VERSION 5.8 ;
BUSBITCHARS "[]" ;
DIVIDERCHAR "/" ;
UNITS
    DATABASE MICRONS 1000 ;
END UNITS

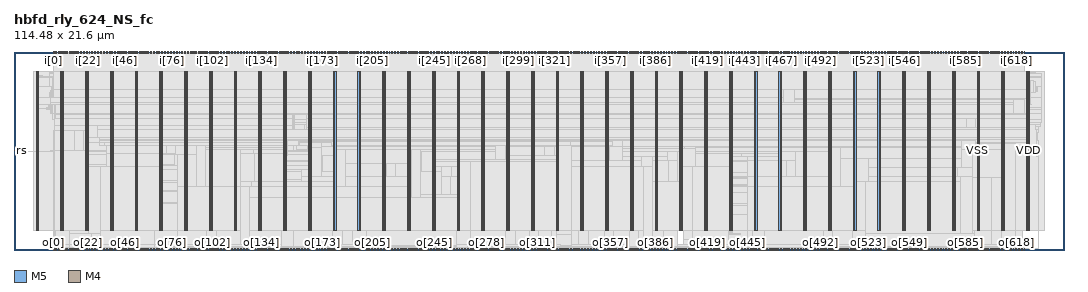
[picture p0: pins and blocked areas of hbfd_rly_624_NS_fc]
MACRO hbfd_rly_624_NS_fc
  FOREIGN hbfd_rly_624_NS_fc 0 0 ;
  CLASS BLOCK ;
  SIZE 114.48 BY 21.6 ;
  PIN clk_in
    DIRECTION INPUT ;
    USE SIGNAL ;
    PORT
      LAYER M5 ;
        RECT  57.216 21.408 57.24 21.6 ;
    END
  END clk_in
  PIN clk_out
    DIRECTION OUTPUT ;
    USE SIGNAL ;
    PORT
      LAYER M5 ;
        RECT  57.216 0 57.24 0.192 ;
    END
  END clk_out
  PIN i[0]
    DIRECTION INPUT ;
    USE SIGNAL ;
    PORT
      LAYER M5 ;
        RECT  4.32 21.408 4.344 21.6 ;
    END
  END i[0]
  PIN i[100]
    DIRECTION INPUT ;
    USE SIGNAL ;
    PORT
      LAYER M5 ;
        RECT  21.264 21.408 21.288 21.6 ;
    END
  END i[100]
  PIN i[101]
    DIRECTION INPUT ;
    USE SIGNAL ;
    PORT
      LAYER M5 ;
        RECT  21.456 21.408 21.48 21.6 ;
    END
  END i[101]
  PIN i[102]
    DIRECTION INPUT ;
    USE SIGNAL ;
    PORT
      LAYER M5 ;
        RECT  21.6 21.408 21.624 21.6 ;
    END
  END i[102]
  PIN i[103]
    DIRECTION INPUT ;
    USE SIGNAL ;
    PORT
      LAYER M5 ;
        RECT  21.792 21.408 21.816 21.6 ;
    END
  END i[103]
  PIN i[104]
    DIRECTION INPUT ;
    USE SIGNAL ;
    PORT
      LAYER M5 ;
        RECT  21.936 21.408 21.96 21.6 ;
    END
  END i[104]
  PIN i[105]
    DIRECTION INPUT ;
    USE SIGNAL ;
    PORT
      LAYER M5 ;
        RECT  22.128 21.408 22.152 21.6 ;
    END
  END i[105]
  PIN i[106]
    DIRECTION INPUT ;
    USE SIGNAL ;
    PORT
      LAYER M5 ;
        RECT  22.272 21.408 22.296 21.6 ;
    END
  END i[106]
  PIN i[107]
    DIRECTION INPUT ;
    USE SIGNAL ;
    PORT
      LAYER M5 ;
        RECT  22.464 21.408 22.488 21.6 ;
    END
  END i[107]
  PIN i[108]
    DIRECTION INPUT ;
    USE SIGNAL ;
    PORT
      LAYER M5 ;
        RECT  22.608 21.408 22.632 21.6 ;
    END
  END i[108]
  PIN i[109]
    DIRECTION INPUT ;
    USE SIGNAL ;
    PORT
      LAYER M5 ;
        RECT  22.8 21.408 22.824 21.6 ;
    END
  END i[109]
  PIN i[10]
    DIRECTION INPUT ;
    USE SIGNAL ;
    PORT
      LAYER M5 ;
        RECT  6 21.408 6.024 21.6 ;
    END
  END i[10]
  PIN i[110]
    DIRECTION INPUT ;
    USE SIGNAL ;
    PORT
      LAYER M5 ;
        RECT  22.944 21.408 22.968 21.6 ;
    END
  END i[110]
  PIN i[111]
    DIRECTION INPUT ;
    USE SIGNAL ;
    PORT
      LAYER M5 ;
        RECT  23.136 21.408 23.16 21.6 ;
    END
  END i[111]
  PIN i[112]
    DIRECTION INPUT ;
    USE SIGNAL ;
    PORT
      LAYER M5 ;
        RECT  23.328 21.408 23.352 21.6 ;
    END
  END i[112]
  PIN i[113]
    DIRECTION INPUT ;
    USE SIGNAL ;
    PORT
      LAYER M5 ;
        RECT  23.472 21.408 23.496 21.6 ;
    END
  END i[113]
  PIN i[114]
    DIRECTION INPUT ;
    USE SIGNAL ;
    PORT
      LAYER M5 ;
        RECT  23.664 21.408 23.688 21.6 ;
    END
  END i[114]
  PIN i[115]
    DIRECTION INPUT ;
    USE SIGNAL ;
    PORT
      LAYER M5 ;
        RECT  23.808 21.408 23.832 21.6 ;
    END
  END i[115]
  PIN i[116]
    DIRECTION INPUT ;
    USE SIGNAL ;
    PORT
      LAYER M5 ;
        RECT  24 21.408 24.024 21.6 ;
    END
  END i[116]
  PIN i[117]
    DIRECTION INPUT ;
    USE SIGNAL ;
    PORT
      LAYER M5 ;
        RECT  24.144 21.408 24.168 21.6 ;
    END
  END i[117]
  PIN i[118]
    DIRECTION INPUT ;
    USE SIGNAL ;
    PORT
      LAYER M5 ;
        RECT  24.336 21.408 24.36 21.6 ;
    END
  END i[118]
  PIN i[119]
    DIRECTION INPUT ;
    USE SIGNAL ;
    PORT
      LAYER M5 ;
        RECT  24.48 21.408 24.504 21.6 ;
    END
  END i[119]
  PIN i[11]
    DIRECTION INPUT ;
    USE SIGNAL ;
    PORT
      LAYER M5 ;
        RECT  6.192 21.408 6.216 21.6 ;
    END
  END i[11]
  PIN i[120]
    DIRECTION INPUT ;
    USE SIGNAL ;
    PORT
      LAYER M5 ;
        RECT  24.672 21.408 24.696 21.6 ;
    END
  END i[120]
  PIN i[121]
    DIRECTION INPUT ;
    USE SIGNAL ;
    PORT
      LAYER M5 ;
        RECT  24.816 21.408 24.84 21.6 ;
    END
  END i[121]
  PIN i[122]
    DIRECTION INPUT ;
    USE SIGNAL ;
    PORT
      LAYER M5 ;
        RECT  25.008 21.408 25.032 21.6 ;
    END
  END i[122]
  PIN i[123]
    DIRECTION INPUT ;
    USE SIGNAL ;
    PORT
      LAYER M5 ;
        RECT  25.152 21.408 25.176 21.6 ;
    END
  END i[123]
  PIN i[124]
    DIRECTION INPUT ;
    USE SIGNAL ;
    PORT
      LAYER M5 ;
        RECT  25.344 21.408 25.368 21.6 ;
    END
  END i[124]
  PIN i[125]
    DIRECTION INPUT ;
    USE SIGNAL ;
    PORT
      LAYER M5 ;
        RECT  25.488 21.408 25.512 21.6 ;
    END
  END i[125]
  PIN i[126]
    DIRECTION INPUT ;
    USE SIGNAL ;
    PORT
      LAYER M5 ;
        RECT  25.68 21.408 25.704 21.6 ;
    END
  END i[126]
  PIN i[127]
    DIRECTION INPUT ;
    USE SIGNAL ;
    PORT
      LAYER M5 ;
        RECT  25.872 21.408 25.896 21.6 ;
    END
  END i[127]
  PIN i[128]
    DIRECTION INPUT ;
    USE SIGNAL ;
    PORT
      LAYER M5 ;
        RECT  26.016 21.408 26.04 21.6 ;
    END
  END i[128]
  PIN i[129]
    DIRECTION INPUT ;
    USE SIGNAL ;
    PORT
      LAYER M5 ;
        RECT  26.208 21.408 26.232 21.6 ;
    END
  END i[129]
  PIN i[12]
    DIRECTION INPUT ;
    USE SIGNAL ;
    PORT
      LAYER M5 ;
        RECT  6.336 21.408 6.36 21.6 ;
    END
  END i[12]
  PIN i[130]
    DIRECTION INPUT ;
    USE SIGNAL ;
    PORT
      LAYER M5 ;
        RECT  26.352 21.408 26.376 21.6 ;
    END
  END i[130]
  PIN i[131]
    DIRECTION INPUT ;
    USE SIGNAL ;
    PORT
      LAYER M5 ;
        RECT  26.544 21.408 26.568 21.6 ;
    END
  END i[131]
  PIN i[132]
    DIRECTION INPUT ;
    USE SIGNAL ;
    PORT
      LAYER M5 ;
        RECT  26.688 21.408 26.712 21.6 ;
    END
  END i[132]
  PIN i[133]
    DIRECTION INPUT ;
    USE SIGNAL ;
    PORT
      LAYER M5 ;
        RECT  26.88 21.408 26.904 21.6 ;
    END
  END i[133]
  PIN i[134]
    DIRECTION INPUT ;
    USE SIGNAL ;
    PORT
      LAYER M5 ;
        RECT  27.024 21.408 27.048 21.6 ;
    END
  END i[134]
  PIN i[135]
    DIRECTION INPUT ;
    USE SIGNAL ;
    PORT
      LAYER M5 ;
        RECT  27.216 21.408 27.24 21.6 ;
    END
  END i[135]
  PIN i[136]
    DIRECTION INPUT ;
    USE SIGNAL ;
    PORT
      LAYER M5 ;
        RECT  27.36 21.408 27.384 21.6 ;
    END
  END i[136]
  PIN i[137]
    DIRECTION INPUT ;
    USE SIGNAL ;
    PORT
      LAYER M5 ;
        RECT  27.552 21.408 27.576 21.6 ;
    END
  END i[137]
  PIN i[138]
    DIRECTION INPUT ;
    USE SIGNAL ;
    PORT
      LAYER M5 ;
        RECT  27.696 21.408 27.72 21.6 ;
    END
  END i[138]
  PIN i[139]
    DIRECTION INPUT ;
    USE SIGNAL ;
    PORT
      LAYER M5 ;
        RECT  27.888 21.408 27.912 21.6 ;
    END
  END i[139]
  PIN i[13]
    DIRECTION INPUT ;
    USE SIGNAL ;
    PORT
      LAYER M5 ;
        RECT  6.528 21.408 6.552 21.6 ;
    END
  END i[13]
  PIN i[140]
    DIRECTION INPUT ;
    USE SIGNAL ;
    PORT
      LAYER M5 ;
        RECT  28.032 21.408 28.056 21.6 ;
    END
  END i[140]
  PIN i[141]
    DIRECTION INPUT ;
    USE SIGNAL ;
    PORT
      LAYER M5 ;
        RECT  28.224 21.408 28.248 21.6 ;
    END
  END i[141]
  PIN i[142]
    DIRECTION INPUT ;
    USE SIGNAL ;
    PORT
      LAYER M5 ;
        RECT  28.416 21.408 28.44 21.6 ;
    END
  END i[142]
  PIN i[143]
    DIRECTION INPUT ;
    USE SIGNAL ;
    PORT
      LAYER M5 ;
        RECT  28.56 21.408 28.584 21.6 ;
    END
  END i[143]
  PIN i[144]
    DIRECTION INPUT ;
    USE SIGNAL ;
    PORT
      LAYER M5 ;
        RECT  28.752 21.408 28.776 21.6 ;
    END
  END i[144]
  PIN i[145]
    DIRECTION INPUT ;
    USE SIGNAL ;
    PORT
      LAYER M5 ;
        RECT  28.896 21.408 28.92 21.6 ;
    END
  END i[145]
  PIN i[146]
    DIRECTION INPUT ;
    USE SIGNAL ;
    PORT
      LAYER M5 ;
        RECT  29.088 21.408 29.112 21.6 ;
    END
  END i[146]
  PIN i[147]
    DIRECTION INPUT ;
    USE SIGNAL ;
    PORT
      LAYER M5 ;
        RECT  29.232 21.408 29.256 21.6 ;
    END
  END i[147]
  PIN i[148]
    DIRECTION INPUT ;
    USE SIGNAL ;
    PORT
      LAYER M5 ;
        RECT  29.424 21.408 29.448 21.6 ;
    END
  END i[148]
  PIN i[149]
    DIRECTION INPUT ;
    USE SIGNAL ;
    PORT
      LAYER M5 ;
        RECT  29.568 21.408 29.592 21.6 ;
    END
  END i[149]
  PIN i[14]
    DIRECTION INPUT ;
    USE SIGNAL ;
    PORT
      LAYER M5 ;
        RECT  6.672 21.408 6.696 21.6 ;
    END
  END i[14]
  PIN i[150]
    DIRECTION INPUT ;
    USE SIGNAL ;
    PORT
      LAYER M5 ;
        RECT  29.76 21.408 29.784 21.6 ;
    END
  END i[150]
  PIN i[151]
    DIRECTION INPUT ;
    USE SIGNAL ;
    PORT
      LAYER M5 ;
        RECT  29.904 21.408 29.928 21.6 ;
    END
  END i[151]
  PIN i[152]
    DIRECTION INPUT ;
    USE SIGNAL ;
    PORT
      LAYER M5 ;
        RECT  30.096 21.408 30.12 21.6 ;
    END
  END i[152]
  PIN i[153]
    DIRECTION INPUT ;
    USE SIGNAL ;
    PORT
      LAYER M5 ;
        RECT  30.24 21.408 30.264 21.6 ;
    END
  END i[153]
  PIN i[154]
    DIRECTION INPUT ;
    USE SIGNAL ;
    PORT
      LAYER M5 ;
        RECT  30.432 21.408 30.456 21.6 ;
    END
  END i[154]
  PIN i[155]
    DIRECTION INPUT ;
    USE SIGNAL ;
    PORT
      LAYER M5 ;
        RECT  30.576 21.408 30.6 21.6 ;
    END
  END i[155]
  PIN i[156]
    DIRECTION INPUT ;
    USE SIGNAL ;
    PORT
      LAYER M5 ;
        RECT  30.768 21.408 30.792 21.6 ;
    END
  END i[156]
  PIN i[157]
    DIRECTION INPUT ;
    USE SIGNAL ;
    PORT
      LAYER M5 ;
        RECT  30.96 21.408 30.984 21.6 ;
    END
  END i[157]
  PIN i[158]
    DIRECTION INPUT ;
    USE SIGNAL ;
    PORT
      LAYER M5 ;
        RECT  31.104 21.408 31.128 21.6 ;
    END
  END i[158]
  PIN i[159]
    DIRECTION INPUT ;
    USE SIGNAL ;
    PORT
      LAYER M5 ;
        RECT  31.296 21.408 31.32 21.6 ;
    END
  END i[159]
  PIN i[15]
    DIRECTION INPUT ;
    USE SIGNAL ;
    PORT
      LAYER M5 ;
        RECT  6.864 21.408 6.888 21.6 ;
    END
  END i[15]
  PIN i[160]
    DIRECTION INPUT ;
    USE SIGNAL ;
    PORT
      LAYER M5 ;
        RECT  31.44 21.408 31.464 21.6 ;
    END
  END i[160]
  PIN i[161]
    DIRECTION INPUT ;
    USE SIGNAL ;
    PORT
      LAYER M5 ;
        RECT  31.632 21.408 31.656 21.6 ;
    END
  END i[161]
  PIN i[162]
    DIRECTION INPUT ;
    USE SIGNAL ;
    PORT
      LAYER M5 ;
        RECT  31.776 21.408 31.8 21.6 ;
    END
  END i[162]
  PIN i[163]
    DIRECTION INPUT ;
    USE SIGNAL ;
    PORT
      LAYER M5 ;
        RECT  31.968 21.408 31.992 21.6 ;
    END
  END i[163]
  PIN i[164]
    DIRECTION INPUT ;
    USE SIGNAL ;
    PORT
      LAYER M5 ;
        RECT  32.112 21.408 32.136 21.6 ;
    END
  END i[164]
  PIN i[165]
    DIRECTION INPUT ;
    USE SIGNAL ;
    PORT
      LAYER M5 ;
        RECT  32.304 21.408 32.328 21.6 ;
    END
  END i[165]
  PIN i[166]
    DIRECTION INPUT ;
    USE SIGNAL ;
    PORT
      LAYER M5 ;
        RECT  32.448 21.408 32.472 21.6 ;
    END
  END i[166]
  PIN i[167]
    DIRECTION INPUT ;
    USE SIGNAL ;
    PORT
      LAYER M5 ;
        RECT  32.64 21.408 32.664 21.6 ;
    END
  END i[167]
  PIN i[168]
    DIRECTION INPUT ;
    USE SIGNAL ;
    PORT
      LAYER M5 ;
        RECT  32.784 21.408 32.808 21.6 ;
    END
  END i[168]
  PIN i[169]
    DIRECTION INPUT ;
    USE SIGNAL ;
    PORT
      LAYER M5 ;
        RECT  32.976 21.408 33 21.6 ;
    END
  END i[169]
  PIN i[16]
    DIRECTION INPUT ;
    USE SIGNAL ;
    PORT
      LAYER M5 ;
        RECT  7.008 21.408 7.032 21.6 ;
    END
  END i[16]
  PIN i[170]
    DIRECTION INPUT ;
    USE SIGNAL ;
    PORT
      LAYER M5 ;
        RECT  33.12 21.408 33.144 21.6 ;
    END
  END i[170]
  PIN i[171]
    DIRECTION INPUT ;
    USE SIGNAL ;
    PORT
      LAYER M5 ;
        RECT  33.312 21.408 33.336 21.6 ;
    END
  END i[171]
  PIN i[172]
    DIRECTION INPUT ;
    USE SIGNAL ;
    PORT
      LAYER M5 ;
        RECT  33.504 21.408 33.528 21.6 ;
    END
  END i[172]
  PIN i[173]
    DIRECTION INPUT ;
    USE SIGNAL ;
    PORT
      LAYER M5 ;
        RECT  33.648 21.408 33.672 21.6 ;
    END
  END i[173]
  PIN i[174]
    DIRECTION INPUT ;
    USE SIGNAL ;
    PORT
      LAYER M5 ;
        RECT  33.84 21.408 33.864 21.6 ;
    END
  END i[174]
  PIN i[175]
    DIRECTION INPUT ;
    USE SIGNAL ;
    PORT
      LAYER M5 ;
        RECT  33.984 21.408 34.008 21.6 ;
    END
  END i[175]
  PIN i[176]
    DIRECTION INPUT ;
    USE SIGNAL ;
    PORT
      LAYER M5 ;
        RECT  34.176 21.408 34.2 21.6 ;
    END
  END i[176]
  PIN i[177]
    DIRECTION INPUT ;
    USE SIGNAL ;
    PORT
      LAYER M5 ;
        RECT  34.32 21.408 34.344 21.6 ;
    END
  END i[177]
  PIN i[178]
    DIRECTION INPUT ;
    USE SIGNAL ;
    PORT
      LAYER M5 ;
        RECT  34.512 21.408 34.536 21.6 ;
    END
  END i[178]
  PIN i[179]
    DIRECTION INPUT ;
    USE SIGNAL ;
    PORT
      LAYER M5 ;
        RECT  34.656 21.408 34.68 21.6 ;
    END
  END i[179]
  PIN i[17]
    DIRECTION INPUT ;
    USE SIGNAL ;
    PORT
      LAYER M5 ;
        RECT  7.2 21.408 7.224 21.6 ;
    END
  END i[17]
  PIN i[180]
    DIRECTION INPUT ;
    USE SIGNAL ;
    PORT
      LAYER M5 ;
        RECT  34.848 21.408 34.872 21.6 ;
    END
  END i[180]
  PIN i[181]
    DIRECTION INPUT ;
    USE SIGNAL ;
    PORT
      LAYER M5 ;
        RECT  34.992 21.408 35.016 21.6 ;
    END
  END i[181]
  PIN i[182]
    DIRECTION INPUT ;
    USE SIGNAL ;
    PORT
      LAYER M5 ;
        RECT  35.184 21.408 35.208 21.6 ;
    END
  END i[182]
  PIN i[183]
    DIRECTION INPUT ;
    USE SIGNAL ;
    PORT
      LAYER M5 ;
        RECT  35.328 21.408 35.352 21.6 ;
    END
  END i[183]
  PIN i[184]
    DIRECTION INPUT ;
    USE SIGNAL ;
    PORT
      LAYER M5 ;
        RECT  35.52 21.408 35.544 21.6 ;
    END
  END i[184]
  PIN i[185]
    DIRECTION INPUT ;
    USE SIGNAL ;
    PORT
      LAYER M5 ;
        RECT  35.664 21.408 35.688 21.6 ;
    END
  END i[185]
  PIN i[186]
    DIRECTION INPUT ;
    USE SIGNAL ;
    PORT
      LAYER M5 ;
        RECT  35.856 21.408 35.88 21.6 ;
    END
  END i[186]
  PIN i[187]
    DIRECTION INPUT ;
    USE SIGNAL ;
    PORT
      LAYER M5 ;
        RECT  36.048 21.408 36.072 21.6 ;
    END
  END i[187]
  PIN i[188]
    DIRECTION INPUT ;
    USE SIGNAL ;
    PORT
      LAYER M5 ;
        RECT  36.192 21.408 36.216 21.6 ;
    END
  END i[188]
  PIN i[189]
    DIRECTION INPUT ;
    USE SIGNAL ;
    PORT
      LAYER M5 ;
        RECT  36.384 21.408 36.408 21.6 ;
    END
  END i[189]
  PIN i[18]
    DIRECTION INPUT ;
    USE SIGNAL ;
    PORT
      LAYER M5 ;
        RECT  7.344 21.408 7.368 21.6 ;
    END
  END i[18]
  PIN i[190]
    DIRECTION INPUT ;
    USE SIGNAL ;
    PORT
      LAYER M5 ;
        RECT  36.528 21.408 36.552 21.6 ;
    END
  END i[190]
  PIN i[191]
    DIRECTION INPUT ;
    USE SIGNAL ;
    PORT
      LAYER M5 ;
        RECT  36.72 21.408 36.744 21.6 ;
    END
  END i[191]
  PIN i[192]
    DIRECTION INPUT ;
    USE SIGNAL ;
    PORT
      LAYER M5 ;
        RECT  36.864 21.408 36.888 21.6 ;
    END
  END i[192]
  PIN i[193]
    DIRECTION INPUT ;
    USE SIGNAL ;
    PORT
      LAYER M5 ;
        RECT  37.056 21.408 37.08 21.6 ;
    END
  END i[193]
  PIN i[194]
    DIRECTION INPUT ;
    USE SIGNAL ;
    PORT
      LAYER M5 ;
        RECT  37.2 21.408 37.224 21.6 ;
    END
  END i[194]
  PIN i[195]
    DIRECTION INPUT ;
    USE SIGNAL ;
    PORT
      LAYER M5 ;
        RECT  37.392 21.408 37.416 21.6 ;
    END
  END i[195]
  PIN i[196]
    DIRECTION INPUT ;
    USE SIGNAL ;
    PORT
      LAYER M5 ;
        RECT  37.536 21.408 37.56 21.6 ;
    END
  END i[196]
  PIN i[197]
    DIRECTION INPUT ;
    USE SIGNAL ;
    PORT
      LAYER M5 ;
        RECT  37.728 21.408 37.752 21.6 ;
    END
  END i[197]
  PIN i[198]
    DIRECTION INPUT ;
    USE SIGNAL ;
    PORT
      LAYER M5 ;
        RECT  37.872 21.408 37.896 21.6 ;
    END
  END i[198]
  PIN i[199]
    DIRECTION INPUT ;
    USE SIGNAL ;
    PORT
      LAYER M5 ;
        RECT  38.064 21.408 38.088 21.6 ;
    END
  END i[199]
  PIN i[19]
    DIRECTION INPUT ;
    USE SIGNAL ;
    PORT
      LAYER M5 ;
        RECT  7.536 21.408 7.56 21.6 ;
    END
  END i[19]
  PIN i[1]
    DIRECTION INPUT ;
    USE SIGNAL ;
    PORT
      LAYER M5 ;
        RECT  4.464 21.408 4.488 21.6 ;
    END
  END i[1]
  PIN i[200]
    DIRECTION INPUT ;
    USE SIGNAL ;
    PORT
      LAYER M5 ;
        RECT  38.208 21.408 38.232 21.6 ;
    END
  END i[200]
  PIN i[201]
    DIRECTION INPUT ;
    USE SIGNAL ;
    PORT
      LAYER M5 ;
        RECT  38.4 21.408 38.424 21.6 ;
    END
  END i[201]
  PIN i[202]
    DIRECTION INPUT ;
    USE SIGNAL ;
    PORT
      LAYER M5 ;
        RECT  38.592 21.408 38.616 21.6 ;
    END
  END i[202]
  PIN i[203]
    DIRECTION INPUT ;
    USE SIGNAL ;
    PORT
      LAYER M5 ;
        RECT  38.736 21.408 38.76 21.6 ;
    END
  END i[203]
  PIN i[204]
    DIRECTION INPUT ;
    USE SIGNAL ;
    PORT
      LAYER M5 ;
        RECT  38.928 21.408 38.952 21.6 ;
    END
  END i[204]
  PIN i[205]
    DIRECTION INPUT ;
    USE SIGNAL ;
    PORT
      LAYER M5 ;
        RECT  39.072 21.408 39.096 21.6 ;
    END
  END i[205]
  PIN i[206]
    DIRECTION INPUT ;
    USE SIGNAL ;
    PORT
      LAYER M5 ;
        RECT  39.264 21.408 39.288 21.6 ;
    END
  END i[206]
  PIN i[207]
    DIRECTION INPUT ;
    USE SIGNAL ;
    PORT
      LAYER M5 ;
        RECT  39.408 21.408 39.432 21.6 ;
    END
  END i[207]
  PIN i[208]
    DIRECTION INPUT ;
    USE SIGNAL ;
    PORT
      LAYER M5 ;
        RECT  39.6 21.408 39.624 21.6 ;
    END
  END i[208]
  PIN i[209]
    DIRECTION INPUT ;
    USE SIGNAL ;
    PORT
      LAYER M5 ;
        RECT  39.744 21.408 39.768 21.6 ;
    END
  END i[209]
  PIN i[20]
    DIRECTION INPUT ;
    USE SIGNAL ;
    PORT
      LAYER M5 ;
        RECT  7.68 21.408 7.704 21.6 ;
    END
  END i[20]
  PIN i[210]
    DIRECTION INPUT ;
    USE SIGNAL ;
    PORT
      LAYER M5 ;
        RECT  39.936 21.408 39.96 21.6 ;
    END
  END i[210]
  PIN i[211]
    DIRECTION INPUT ;
    USE SIGNAL ;
    PORT
      LAYER M5 ;
        RECT  40.08 21.408 40.104 21.6 ;
    END
  END i[211]
  PIN i[212]
    DIRECTION INPUT ;
    USE SIGNAL ;
    PORT
      LAYER M5 ;
        RECT  40.272 21.408 40.296 21.6 ;
    END
  END i[212]
  PIN i[213]
    DIRECTION INPUT ;
    USE SIGNAL ;
    PORT
      LAYER M5 ;
        RECT  40.416 21.408 40.44 21.6 ;
    END
  END i[213]
  PIN i[214]
    DIRECTION INPUT ;
    USE SIGNAL ;
    PORT
      LAYER M5 ;
        RECT  40.608 21.408 40.632 21.6 ;
    END
  END i[214]
  PIN i[215]
    DIRECTION INPUT ;
    USE SIGNAL ;
    PORT
      LAYER M5 ;
        RECT  40.752 21.408 40.776 21.6 ;
    END
  END i[215]
  PIN i[216]
    DIRECTION INPUT ;
    USE SIGNAL ;
    PORT
      LAYER M5 ;
        RECT  40.944 21.408 40.968 21.6 ;
    END
  END i[216]
  PIN i[217]
    DIRECTION INPUT ;
    USE SIGNAL ;
    PORT
      LAYER M5 ;
        RECT  41.136 21.408 41.16 21.6 ;
    END
  END i[217]
  PIN i[218]
    DIRECTION INPUT ;
    USE SIGNAL ;
    PORT
      LAYER M5 ;
        RECT  41.28 21.408 41.304 21.6 ;
    END
  END i[218]
  PIN i[219]
    DIRECTION INPUT ;
    USE SIGNAL ;
    PORT
      LAYER M5 ;
        RECT  41.472 21.408 41.496 21.6 ;
    END
  END i[219]
  PIN i[21]
    DIRECTION INPUT ;
    USE SIGNAL ;
    PORT
      LAYER M5 ;
        RECT  7.872 21.408 7.896 21.6 ;
    END
  END i[21]
  PIN i[220]
    DIRECTION INPUT ;
    USE SIGNAL ;
    PORT
      LAYER M5 ;
        RECT  41.616 21.408 41.64 21.6 ;
    END
  END i[220]
  PIN i[221]
    DIRECTION INPUT ;
    USE SIGNAL ;
    PORT
      LAYER M5 ;
        RECT  41.808 21.408 41.832 21.6 ;
    END
  END i[221]
  PIN i[222]
    DIRECTION INPUT ;
    USE SIGNAL ;
    PORT
      LAYER M5 ;
        RECT  41.952 21.408 41.976 21.6 ;
    END
  END i[222]
  PIN i[223]
    DIRECTION INPUT ;
    USE SIGNAL ;
    PORT
      LAYER M5 ;
        RECT  42.144 21.408 42.168 21.6 ;
    END
  END i[223]
  PIN i[224]
    DIRECTION INPUT ;
    USE SIGNAL ;
    PORT
      LAYER M5 ;
        RECT  42.288 21.408 42.312 21.6 ;
    END
  END i[224]
  PIN i[225]
    DIRECTION INPUT ;
    USE SIGNAL ;
    PORT
      LAYER M5 ;
        RECT  42.48 21.408 42.504 21.6 ;
    END
  END i[225]
  PIN i[226]
    DIRECTION INPUT ;
    USE SIGNAL ;
    PORT
      LAYER M5 ;
        RECT  42.624 21.408 42.648 21.6 ;
    END
  END i[226]
  PIN i[227]
    DIRECTION INPUT ;
    USE SIGNAL ;
    PORT
      LAYER M5 ;
        RECT  42.816 21.408 42.84 21.6 ;
    END
  END i[227]
  PIN i[228]
    DIRECTION INPUT ;
    USE SIGNAL ;
    PORT
      LAYER M5 ;
        RECT  42.96 21.408 42.984 21.6 ;
    END
  END i[228]
  PIN i[229]
    DIRECTION INPUT ;
    USE SIGNAL ;
    PORT
      LAYER M5 ;
        RECT  43.152 21.408 43.176 21.6 ;
    END
  END i[229]
  PIN i[22]
    DIRECTION INPUT ;
    USE SIGNAL ;
    PORT
      LAYER M5 ;
        RECT  8.016 21.408 8.04 21.6 ;
    END
  END i[22]
  PIN i[230]
    DIRECTION INPUT ;
    USE SIGNAL ;
    PORT
      LAYER M5 ;
        RECT  43.296 21.408 43.32 21.6 ;
    END
  END i[230]
  PIN i[231]
    DIRECTION INPUT ;
    USE SIGNAL ;
    PORT
      LAYER M5 ;
        RECT  43.488 21.408 43.512 21.6 ;
    END
  END i[231]
  PIN i[232]
    DIRECTION INPUT ;
    USE SIGNAL ;
    PORT
      LAYER M5 ;
        RECT  43.68 21.408 43.704 21.6 ;
    END
  END i[232]
  PIN i[233]
    DIRECTION INPUT ;
    USE SIGNAL ;
    PORT
      LAYER M5 ;
        RECT  43.824 21.408 43.848 21.6 ;
    END
  END i[233]
  PIN i[234]
    DIRECTION INPUT ;
    USE SIGNAL ;
    PORT
      LAYER M5 ;
        RECT  44.016 21.408 44.04 21.6 ;
    END
  END i[234]
  PIN i[235]
    DIRECTION INPUT ;
    USE SIGNAL ;
    PORT
      LAYER M5 ;
        RECT  44.16 21.408 44.184 21.6 ;
    END
  END i[235]
  PIN i[236]
    DIRECTION INPUT ;
    USE SIGNAL ;
    PORT
      LAYER M5 ;
        RECT  44.352 21.408 44.376 21.6 ;
    END
  END i[236]
  PIN i[237]
    DIRECTION INPUT ;
    USE SIGNAL ;
    PORT
      LAYER M5 ;
        RECT  44.496 21.408 44.52 21.6 ;
    END
  END i[237]
  PIN i[238]
    DIRECTION INPUT ;
    USE SIGNAL ;
    PORT
      LAYER M5 ;
        RECT  44.688 21.408 44.712 21.6 ;
    END
  END i[238]
  PIN i[239]
    DIRECTION INPUT ;
    USE SIGNAL ;
    PORT
      LAYER M5 ;
        RECT  44.832 21.408 44.856 21.6 ;
    END
  END i[239]
  PIN i[23]
    DIRECTION INPUT ;
    USE SIGNAL ;
    PORT
      LAYER M5 ;
        RECT  8.208 21.408 8.232 21.6 ;
    END
  END i[23]
  PIN i[240]
    DIRECTION INPUT ;
    USE SIGNAL ;
    PORT
      LAYER M5 ;
        RECT  45.024 21.408 45.048 21.6 ;
    END
  END i[240]
  PIN i[241]
    DIRECTION INPUT ;
    USE SIGNAL ;
    PORT
      LAYER M5 ;
        RECT  45.168 21.408 45.192 21.6 ;
    END
  END i[241]
  PIN i[242]
    DIRECTION INPUT ;
    USE SIGNAL ;
    PORT
      LAYER M5 ;
        RECT  45.36 21.408 45.384 21.6 ;
    END
  END i[242]
  PIN i[243]
    DIRECTION INPUT ;
    USE SIGNAL ;
    PORT
      LAYER M5 ;
        RECT  45.504 21.408 45.528 21.6 ;
    END
  END i[243]
  PIN i[244]
    DIRECTION INPUT ;
    USE SIGNAL ;
    PORT
      LAYER M5 ;
        RECT  45.696 21.408 45.72 21.6 ;
    END
  END i[244]
  PIN i[245]
    DIRECTION INPUT ;
    USE SIGNAL ;
    PORT
      LAYER M5 ;
        RECT  45.84 21.408 45.864 21.6 ;
    END
  END i[245]
  PIN i[246]
    DIRECTION INPUT ;
    USE SIGNAL ;
    PORT
      LAYER M5 ;
        RECT  46.032 21.408 46.056 21.6 ;
    END
  END i[246]
  PIN i[247]
    DIRECTION INPUT ;
    USE SIGNAL ;
    PORT
      LAYER M5 ;
        RECT  46.224 21.408 46.248 21.6 ;
    END
  END i[247]
  PIN i[248]
    DIRECTION INPUT ;
    USE SIGNAL ;
    PORT
      LAYER M5 ;
        RECT  46.368 21.408 46.392 21.6 ;
    END
  END i[248]
  PIN i[249]
    DIRECTION INPUT ;
    USE SIGNAL ;
    PORT
      LAYER M5 ;
        RECT  46.56 21.408 46.584 21.6 ;
    END
  END i[249]
  PIN i[24]
    DIRECTION INPUT ;
    USE SIGNAL ;
    PORT
      LAYER M5 ;
        RECT  8.4 21.408 8.424 21.6 ;
    END
  END i[24]
  PIN i[250]
    DIRECTION INPUT ;
    USE SIGNAL ;
    PORT
      LAYER M5 ;
        RECT  46.704 21.408 46.728 21.6 ;
    END
  END i[250]
  PIN i[251]
    DIRECTION INPUT ;
    USE SIGNAL ;
    PORT
      LAYER M5 ;
        RECT  46.896 21.408 46.92 21.6 ;
    END
  END i[251]
  PIN i[252]
    DIRECTION INPUT ;
    USE SIGNAL ;
    PORT
      LAYER M5 ;
        RECT  47.04 21.408 47.064 21.6 ;
    END
    PORT
      LAYER M5 ;
        RECT  46.944 21.456 47.208 21.491 ;
    END
  END i[252]
  PIN i[253]
    DIRECTION INPUT ;
    USE SIGNAL ;
    PORT
      LAYER M5 ;
        RECT  47.232 21.408 47.256 21.6 ;
    END
  END i[253]
  PIN i[254]
    DIRECTION INPUT ;
    USE SIGNAL ;
    PORT
      LAYER M5 ;
        RECT  47.376 21.408 47.4 21.6 ;
    END
  END i[254]
  PIN i[255]
    DIRECTION INPUT ;
    USE SIGNAL ;
    PORT
      LAYER M5 ;
        RECT  47.568 21.408 47.592 21.6 ;
    END
  END i[255]
  PIN i[256]
    DIRECTION INPUT ;
    USE SIGNAL ;
    PORT
      LAYER M5 ;
        RECT  47.712 21.408 47.736 21.6 ;
    END
  END i[256]
  PIN i[257]
    DIRECTION INPUT ;
    USE SIGNAL ;
    PORT
      LAYER M5 ;
        RECT  47.904 21.408 47.928 21.6 ;
    END
  END i[257]
  PIN i[258]
    DIRECTION INPUT ;
    USE SIGNAL ;
    PORT
      LAYER M5 ;
        RECT  48.048 21.408 48.072 21.6 ;
    END
  END i[258]
  PIN i[259]
    DIRECTION INPUT ;
    USE SIGNAL ;
    PORT
      LAYER M5 ;
        RECT  48.24 21.408 48.264 21.6 ;
    END
  END i[259]
  PIN i[25]
    DIRECTION INPUT ;
    USE SIGNAL ;
    PORT
      LAYER M5 ;
        RECT  8.544 21.408 8.568 21.6 ;
    END
  END i[25]
  PIN i[260]
    DIRECTION INPUT ;
    USE SIGNAL ;
    PORT
      LAYER M5 ;
        RECT  48.384 21.408 48.408 21.6 ;
    END
  END i[260]
  PIN i[261]
    DIRECTION INPUT ;
    USE SIGNAL ;
    PORT
      LAYER M5 ;
        RECT  48.576 21.408 48.6 21.6 ;
    END
  END i[261]
  PIN i[262]
    DIRECTION INPUT ;
    USE SIGNAL ;
    PORT
      LAYER M5 ;
        RECT  48.768 21.408 48.792 21.6 ;
    END
  END i[262]
  PIN i[263]
    DIRECTION INPUT ;
    USE SIGNAL ;
    PORT
      LAYER M5 ;
        RECT  48.912 21.408 48.936 21.6 ;
    END
  END i[263]
  PIN i[264]
    DIRECTION INPUT ;
    USE SIGNAL ;
    PORT
      LAYER M5 ;
        RECT  49.104 21.408 49.128 21.6 ;
    END
  END i[264]
  PIN i[265]
    DIRECTION INPUT ;
    USE SIGNAL ;
    PORT
      LAYER M5 ;
        RECT  49.248 21.408 49.272 21.6 ;
    END
  END i[265]
  PIN i[266]
    DIRECTION INPUT ;
    USE SIGNAL ;
    PORT
      LAYER M5 ;
        RECT  49.44 21.408 49.464 21.6 ;
    END
  END i[266]
  PIN i[267]
    DIRECTION INPUT ;
    USE SIGNAL ;
    PORT
      LAYER M5 ;
        RECT  49.584 21.408 49.608 21.6 ;
    END
  END i[267]
  PIN i[268]
    DIRECTION INPUT ;
    USE SIGNAL ;
    PORT
      LAYER M5 ;
        RECT  49.776 21.408 49.8 21.6 ;
    END
  END i[268]
  PIN i[269]
    DIRECTION INPUT ;
    USE SIGNAL ;
    PORT
      LAYER M5 ;
        RECT  49.92 21.408 49.944 21.6 ;
    END
  END i[269]
  PIN i[26]
    DIRECTION INPUT ;
    USE SIGNAL ;
    PORT
      LAYER M5 ;
        RECT  8.736 21.408 8.76 21.6 ;
    END
  END i[26]
  PIN i[270]
    DIRECTION INPUT ;
    USE SIGNAL ;
    PORT
      LAYER M5 ;
        RECT  50.112 21.408 50.136 21.6 ;
    END
  END i[270]
  PIN i[271]
    DIRECTION INPUT ;
    USE SIGNAL ;
    PORT
      LAYER M5 ;
        RECT  50.256 21.408 50.28 21.6 ;
    END
  END i[271]
  PIN i[272]
    DIRECTION INPUT ;
    USE SIGNAL ;
    PORT
      LAYER M5 ;
        RECT  50.448 21.408 50.472 21.6 ;
    END
  END i[272]
  PIN i[273]
    DIRECTION INPUT ;
    USE SIGNAL ;
    PORT
      LAYER M5 ;
        RECT  50.592 21.408 50.616 21.6 ;
    END
  END i[273]
  PIN i[274]
    DIRECTION INPUT ;
    USE SIGNAL ;
    PORT
      LAYER M5 ;
        RECT  50.784 21.408 50.808 21.6 ;
    END
  END i[274]
  PIN i[275]
    DIRECTION INPUT ;
    USE SIGNAL ;
    PORT
      LAYER M5 ;
        RECT  50.976 21.408 51 21.6 ;
    END
  END i[275]
  PIN i[276]
    DIRECTION INPUT ;
    USE SIGNAL ;
    PORT
      LAYER M5 ;
        RECT  51.12 21.408 51.144 21.6 ;
    END
  END i[276]
  PIN i[277]
    DIRECTION INPUT ;
    USE SIGNAL ;
    PORT
      LAYER M5 ;
        RECT  51.312 21.408 51.336 21.6 ;
    END
  END i[277]
  PIN i[278]
    DIRECTION INPUT ;
    USE SIGNAL ;
    PORT
      LAYER M5 ;
        RECT  51.456 21.408 51.48 21.6 ;
    END
  END i[278]
  PIN i[279]
    DIRECTION INPUT ;
    USE SIGNAL ;
    PORT
      LAYER M5 ;
        RECT  51.648 21.408 51.672 21.6 ;
    END
  END i[279]
  PIN i[27]
    DIRECTION INPUT ;
    USE SIGNAL ;
    PORT
      LAYER M5 ;
        RECT  8.88 21.408 8.904 21.6 ;
    END
  END i[27]
  PIN i[280]
    DIRECTION INPUT ;
    USE SIGNAL ;
    PORT
      LAYER M5 ;
        RECT  51.792 21.408 51.816 21.6 ;
    END
  END i[280]
  PIN i[281]
    DIRECTION INPUT ;
    USE SIGNAL ;
    PORT
      LAYER M5 ;
        RECT  51.984 21.408 52.008 21.6 ;
    END
  END i[281]
  PIN i[282]
    DIRECTION INPUT ;
    USE SIGNAL ;
    PORT
      LAYER M5 ;
        RECT  52.128 21.408 52.152 21.6 ;
    END
  END i[282]
  PIN i[283]
    DIRECTION INPUT ;
    USE SIGNAL ;
    PORT
      LAYER M5 ;
        RECT  52.32 21.408 52.344 21.6 ;
    END
  END i[283]
  PIN i[284]
    DIRECTION INPUT ;
    USE SIGNAL ;
    PORT
      LAYER M5 ;
        RECT  52.464 21.408 52.488 21.6 ;
    END
  END i[284]
  PIN i[285]
    DIRECTION INPUT ;
    USE SIGNAL ;
    PORT
      LAYER M5 ;
        RECT  52.656 21.408 52.68 21.6 ;
    END
  END i[285]
  PIN i[286]
    DIRECTION INPUT ;
    USE SIGNAL ;
    PORT
      LAYER M5 ;
        RECT  52.8 21.408 52.824 21.6 ;
    END
  END i[286]
  PIN i[287]
    DIRECTION INPUT ;
    USE SIGNAL ;
    PORT
      LAYER M5 ;
        RECT  52.992 21.408 53.016 21.6 ;
    END
  END i[287]
  PIN i[288]
    DIRECTION INPUT ;
    USE SIGNAL ;
    PORT
      LAYER M5 ;
        RECT  53.136 21.408 53.16 21.6 ;
    END
  END i[288]
  PIN i[289]
    DIRECTION INPUT ;
    USE SIGNAL ;
    PORT
      LAYER M5 ;
        RECT  53.328 21.408 53.352 21.6 ;
    END
  END i[289]
  PIN i[28]
    DIRECTION INPUT ;
    USE SIGNAL ;
    PORT
      LAYER M5 ;
        RECT  9.072 21.408 9.096 21.6 ;
    END
  END i[28]
  PIN i[290]
    DIRECTION INPUT ;
    USE SIGNAL ;
    PORT
      LAYER M5 ;
        RECT  53.52 21.408 53.544 21.6 ;
    END
  END i[290]
  PIN i[291]
    DIRECTION INPUT ;
    USE SIGNAL ;
    PORT
      LAYER M5 ;
        RECT  53.664 21.408 53.688 21.6 ;
    END
  END i[291]
  PIN i[292]
    DIRECTION INPUT ;
    USE SIGNAL ;
    PORT
      LAYER M5 ;
        RECT  53.856 21.408 53.88 21.6 ;
    END
  END i[292]
  PIN i[293]
    DIRECTION INPUT ;
    USE SIGNAL ;
    PORT
      LAYER M5 ;
        RECT  54 21.408 54.024 21.6 ;
    END
  END i[293]
  PIN i[294]
    DIRECTION INPUT ;
    USE SIGNAL ;
    PORT
      LAYER M5 ;
        RECT  54.192 21.408 54.216 21.6 ;
    END
  END i[294]
  PIN i[295]
    DIRECTION INPUT ;
    USE SIGNAL ;
    PORT
      LAYER M5 ;
        RECT  54.336 21.408 54.36 21.6 ;
    END
  END i[295]
  PIN i[296]
    DIRECTION INPUT ;
    USE SIGNAL ;
    PORT
      LAYER M5 ;
        RECT  54.528 21.408 54.552 21.6 ;
    END
  END i[296]
  PIN i[297]
    DIRECTION INPUT ;
    USE SIGNAL ;
    PORT
      LAYER M5 ;
        RECT  54.672 21.408 54.696 21.6 ;
    END
  END i[297]
  PIN i[298]
    DIRECTION INPUT ;
    USE SIGNAL ;
    PORT
      LAYER M5 ;
        RECT  54.864 21.408 54.888 21.6 ;
    END
  END i[298]
  PIN i[299]
    DIRECTION INPUT ;
    USE SIGNAL ;
    PORT
      LAYER M5 ;
        RECT  55.008 21.408 55.032 21.6 ;
    END
  END i[299]
  PIN i[29]
    DIRECTION INPUT ;
    USE SIGNAL ;
    PORT
      LAYER M5 ;
        RECT  9.216 21.408 9.24 21.6 ;
    END
  END i[29]
  PIN i[2]
    DIRECTION INPUT ;
    USE SIGNAL ;
    PORT
      LAYER M5 ;
        RECT  4.656 21.408 4.68 21.6 ;
    END
  END i[2]
  PIN i[300]
    DIRECTION INPUT ;
    USE SIGNAL ;
    PORT
      LAYER M5 ;
        RECT  55.2 21.408 55.224 21.6 ;
    END
  END i[300]
  PIN i[301]
    DIRECTION INPUT ;
    USE SIGNAL ;
    PORT
      LAYER M5 ;
        RECT  55.344 21.408 55.368 21.6 ;
    END
  END i[301]
  PIN i[302]
    DIRECTION INPUT ;
    USE SIGNAL ;
    PORT
      LAYER M5 ;
        RECT  55.536 21.408 55.56 21.6 ;
    END
  END i[302]
  PIN i[303]
    DIRECTION INPUT ;
    USE SIGNAL ;
    PORT
      LAYER M5 ;
        RECT  55.68 21.408 55.704 21.6 ;
    END
  END i[303]
  PIN i[304]
    DIRECTION INPUT ;
    USE SIGNAL ;
    PORT
      LAYER M5 ;
        RECT  55.872 21.408 55.896 21.6 ;
    END
  END i[304]
  PIN i[305]
    DIRECTION INPUT ;
    USE SIGNAL ;
    PORT
      LAYER M5 ;
        RECT  56.064 21.408 56.088 21.6 ;
    END
  END i[305]
  PIN i[306]
    DIRECTION INPUT ;
    USE SIGNAL ;
    PORT
      LAYER M5 ;
        RECT  56.208 21.408 56.232 21.6 ;
    END
  END i[306]
  PIN i[307]
    DIRECTION INPUT ;
    USE SIGNAL ;
    PORT
      LAYER M5 ;
        RECT  56.4 21.408 56.424 21.6 ;
    END
  END i[307]
  PIN i[308]
    DIRECTION INPUT ;
    USE SIGNAL ;
    PORT
      LAYER M5 ;
        RECT  56.544 21.408 56.568 21.6 ;
    END
  END i[308]
  PIN i[309]
    DIRECTION INPUT ;
    USE SIGNAL ;
    PORT
      LAYER M5 ;
        RECT  56.736 21.408 56.76 21.6 ;
    END
  END i[309]
  PIN i[30]
    DIRECTION INPUT ;
    USE SIGNAL ;
    PORT
      LAYER M5 ;
        RECT  9.408 21.408 9.432 21.6 ;
    END
  END i[30]
  PIN i[310]
    DIRECTION INPUT ;
    USE SIGNAL ;
    PORT
      LAYER M5 ;
        RECT  56.88 21.408 56.904 21.6 ;
    END
  END i[310]
  PIN i[311]
    DIRECTION INPUT ;
    USE SIGNAL ;
    PORT
      LAYER M5 ;
        RECT  57.072 21.408 57.096 21.6 ;
    END
  END i[311]
  PIN i[312]
    DIRECTION INPUT ;
    USE SIGNAL ;
    PORT
      LAYER M5 ;
        RECT  57.408 21.408 57.432 21.6 ;
    END
  END i[312]
  PIN i[313]
    DIRECTION INPUT ;
    USE SIGNAL ;
    PORT
      LAYER M5 ;
        RECT  57.552 21.408 57.576 21.6 ;
    END
  END i[313]
  PIN i[314]
    DIRECTION INPUT ;
    USE SIGNAL ;
    PORT
      LAYER M5 ;
        RECT  57.744 21.408 57.768 21.6 ;
    END
  END i[314]
  PIN i[315]
    DIRECTION INPUT ;
    USE SIGNAL ;
    PORT
      LAYER M5 ;
        RECT  57.888 21.408 57.912 21.6 ;
    END
  END i[315]
  PIN i[316]
    DIRECTION INPUT ;
    USE SIGNAL ;
    PORT
      LAYER M5 ;
        RECT  58.08 21.408 58.104 21.6 ;
    END
  END i[316]
  PIN i[317]
    DIRECTION INPUT ;
    USE SIGNAL ;
    PORT
      LAYER M5 ;
        RECT  58.224 21.408 58.248 21.6 ;
    END
  END i[317]
  PIN i[318]
    DIRECTION INPUT ;
    USE SIGNAL ;
    PORT
      LAYER M5 ;
        RECT  58.416 21.408 58.44 21.6 ;
    END
  END i[318]
  PIN i[319]
    DIRECTION INPUT ;
    USE SIGNAL ;
    PORT
      LAYER M5 ;
        RECT  58.608 21.408 58.632 21.6 ;
    END
  END i[319]
  PIN i[31]
    DIRECTION INPUT ;
    USE SIGNAL ;
    PORT
      LAYER M5 ;
        RECT  9.552 21.408 9.576 21.6 ;
    END
  END i[31]
  PIN i[320]
    DIRECTION INPUT ;
    USE SIGNAL ;
    PORT
      LAYER M5 ;
        RECT  58.752 21.408 58.776 21.6 ;
    END
  END i[320]
  PIN i[321]
    DIRECTION INPUT ;
    USE SIGNAL ;
    PORT
      LAYER M5 ;
        RECT  58.944 21.408 58.968 21.6 ;
    END
  END i[321]
  PIN i[322]
    DIRECTION INPUT ;
    USE SIGNAL ;
    PORT
      LAYER M5 ;
        RECT  59.088 21.408 59.112 21.6 ;
    END
  END i[322]
  PIN i[323]
    DIRECTION INPUT ;
    USE SIGNAL ;
    PORT
      LAYER M5 ;
        RECT  59.28 21.408 59.304 21.6 ;
    END
  END i[323]
  PIN i[324]
    DIRECTION INPUT ;
    USE SIGNAL ;
    PORT
      LAYER M5 ;
        RECT  59.424 21.408 59.448 21.6 ;
    END
  END i[324]
  PIN i[325]
    DIRECTION INPUT ;
    USE SIGNAL ;
    PORT
      LAYER M5 ;
        RECT  59.616 21.408 59.64 21.6 ;
    END
  END i[325]
  PIN i[326]
    DIRECTION INPUT ;
    USE SIGNAL ;
    PORT
      LAYER M5 ;
        RECT  59.76 21.408 59.784 21.6 ;
    END
  END i[326]
  PIN i[327]
    DIRECTION INPUT ;
    USE SIGNAL ;
    PORT
      LAYER M5 ;
        RECT  59.952 21.408 59.976 21.6 ;
    END
  END i[327]
  PIN i[328]
    DIRECTION INPUT ;
    USE SIGNAL ;
    PORT
      LAYER M5 ;
        RECT  60.096 21.408 60.12 21.6 ;
    END
  END i[328]
  PIN i[329]
    DIRECTION INPUT ;
    USE SIGNAL ;
    PORT
      LAYER M5 ;
        RECT  60.288 21.408 60.312 21.6 ;
    END
  END i[329]
  PIN i[32]
    DIRECTION INPUT ;
    USE SIGNAL ;
    PORT
      LAYER M5 ;
        RECT  9.744 21.408 9.768 21.6 ;
    END
  END i[32]
  PIN i[330]
    DIRECTION INPUT ;
    USE SIGNAL ;
    PORT
      LAYER M5 ;
        RECT  60.432 21.408 60.456 21.6 ;
    END
  END i[330]
  PIN i[331]
    DIRECTION INPUT ;
    USE SIGNAL ;
    PORT
      LAYER M5 ;
        RECT  60.624 21.408 60.648 21.6 ;
    END
  END i[331]
  PIN i[332]
    DIRECTION INPUT ;
    USE SIGNAL ;
    PORT
      LAYER M5 ;
        RECT  60.768 21.408 60.792 21.6 ;
    END
  END i[332]
  PIN i[333]
    DIRECTION INPUT ;
    USE SIGNAL ;
    PORT
      LAYER M5 ;
        RECT  60.96 21.408 60.984 21.6 ;
    END
  END i[333]
  PIN i[334]
    DIRECTION INPUT ;
    USE SIGNAL ;
    PORT
      LAYER M5 ;
        RECT  61.152 21.408 61.176 21.6 ;
    END
  END i[334]
  PIN i[335]
    DIRECTION INPUT ;
    USE SIGNAL ;
    PORT
      LAYER M5 ;
        RECT  61.296 21.408 61.32 21.6 ;
    END
  END i[335]
  PIN i[336]
    DIRECTION INPUT ;
    USE SIGNAL ;
    PORT
      LAYER M5 ;
        RECT  61.488 21.408 61.512 21.6 ;
    END
  END i[336]
  PIN i[337]
    DIRECTION INPUT ;
    USE SIGNAL ;
    PORT
      LAYER M5 ;
        RECT  61.632 21.408 61.656 21.6 ;
    END
  END i[337]
  PIN i[338]
    DIRECTION INPUT ;
    USE SIGNAL ;
    PORT
      LAYER M5 ;
        RECT  61.824 21.408 61.848 21.6 ;
    END
  END i[338]
  PIN i[339]
    DIRECTION INPUT ;
    USE SIGNAL ;
    PORT
      LAYER M5 ;
        RECT  61.968 21.408 61.992 21.6 ;
    END
  END i[339]
  PIN i[33]
    DIRECTION INPUT ;
    USE SIGNAL ;
    PORT
      LAYER M5 ;
        RECT  9.888 21.408 9.912 21.6 ;
    END
  END i[33]
  PIN i[340]
    DIRECTION INPUT ;
    USE SIGNAL ;
    PORT
      LAYER M5 ;
        RECT  62.16 21.408 62.184 21.6 ;
    END
  END i[340]
  PIN i[341]
    DIRECTION INPUT ;
    USE SIGNAL ;
    PORT
      LAYER M5 ;
        RECT  62.304 21.408 62.328 21.6 ;
    END
  END i[341]
  PIN i[342]
    DIRECTION INPUT ;
    USE SIGNAL ;
    PORT
      LAYER M5 ;
        RECT  62.496 21.408 62.52 21.6 ;
    END
  END i[342]
  PIN i[343]
    DIRECTION INPUT ;
    USE SIGNAL ;
    PORT
      LAYER M5 ;
        RECT  62.64 21.408 62.664 21.6 ;
    END
  END i[343]
  PIN i[344]
    DIRECTION INPUT ;
    USE SIGNAL ;
    PORT
      LAYER M5 ;
        RECT  62.832 21.408 62.856 21.6 ;
    END
  END i[344]
  PIN i[345]
    DIRECTION INPUT ;
    USE SIGNAL ;
    PORT
      LAYER M5 ;
        RECT  62.976 21.408 63 21.6 ;
    END
  END i[345]
  PIN i[346]
    DIRECTION INPUT ;
    USE SIGNAL ;
    PORT
      LAYER M5 ;
        RECT  63.168 21.408 63.192 21.6 ;
    END
  END i[346]
  PIN i[347]
    DIRECTION INPUT ;
    USE SIGNAL ;
    PORT
      LAYER M5 ;
        RECT  63.312 21.408 63.336 21.6 ;
    END
  END i[347]
  PIN i[348]
    DIRECTION INPUT ;
    USE SIGNAL ;
    PORT
      LAYER M5 ;
        RECT  63.504 21.408 63.528 21.6 ;
    END
  END i[348]
  PIN i[349]
    DIRECTION INPUT ;
    USE SIGNAL ;
    PORT
      LAYER M5 ;
        RECT  63.696 21.408 63.72 21.6 ;
    END
  END i[349]
  PIN i[34]
    DIRECTION INPUT ;
    USE SIGNAL ;
    PORT
      LAYER M5 ;
        RECT  10.08 21.408 10.104 21.6 ;
    END
  END i[34]
  PIN i[350]
    DIRECTION INPUT ;
    USE SIGNAL ;
    PORT
      LAYER M5 ;
        RECT  63.84 21.408 63.864 21.6 ;
    END
  END i[350]
  PIN i[351]
    DIRECTION INPUT ;
    USE SIGNAL ;
    PORT
      LAYER M5 ;
        RECT  64.032 21.408 64.056 21.6 ;
    END
  END i[351]
  PIN i[352]
    DIRECTION INPUT ;
    USE SIGNAL ;
    PORT
      LAYER M5 ;
        RECT  64.176 21.408 64.2 21.6 ;
    END
  END i[352]
  PIN i[353]
    DIRECTION INPUT ;
    USE SIGNAL ;
    PORT
      LAYER M5 ;
        RECT  64.368 21.408 64.392 21.6 ;
    END
  END i[353]
  PIN i[354]
    DIRECTION INPUT ;
    USE SIGNAL ;
    PORT
      LAYER M5 ;
        RECT  64.512 21.408 64.536 21.6 ;
    END
  END i[354]
  PIN i[355]
    DIRECTION INPUT ;
    USE SIGNAL ;
    PORT
      LAYER M5 ;
        RECT  64.704 21.408 64.728 21.6 ;
    END
  END i[355]
  PIN i[356]
    DIRECTION INPUT ;
    USE SIGNAL ;
    PORT
      LAYER M5 ;
        RECT  64.848 21.408 64.872 21.6 ;
    END
  END i[356]
  PIN i[357]
    DIRECTION INPUT ;
    USE SIGNAL ;
    PORT
      LAYER M5 ;
        RECT  65.04 21.408 65.064 21.6 ;
    END
  END i[357]
  PIN i[358]
    DIRECTION INPUT ;
    USE SIGNAL ;
    PORT
      LAYER M5 ;
        RECT  65.184 21.408 65.208 21.6 ;
    END
  END i[358]
  PIN i[359]
    DIRECTION INPUT ;
    USE SIGNAL ;
    PORT
      LAYER M5 ;
        RECT  65.376 21.408 65.4 21.6 ;
    END
  END i[359]
  PIN i[35]
    DIRECTION INPUT ;
    USE SIGNAL ;
    PORT
      LAYER M5 ;
        RECT  10.224 21.408 10.248 21.6 ;
    END
  END i[35]
  PIN i[360]
    DIRECTION INPUT ;
    USE SIGNAL ;
    PORT
      LAYER M5 ;
        RECT  65.52 21.408 65.544 21.6 ;
    END
  END i[360]
  PIN i[361]
    DIRECTION INPUT ;
    USE SIGNAL ;
    PORT
      LAYER M5 ;
        RECT  65.712 21.408 65.736 21.6 ;
    END
  END i[361]
  PIN i[362]
    DIRECTION INPUT ;
    USE SIGNAL ;
    PORT
      LAYER M5 ;
        RECT  65.856 21.408 65.88 21.6 ;
    END
  END i[362]
  PIN i[363]
    DIRECTION INPUT ;
    USE SIGNAL ;
    PORT
      LAYER M5 ;
        RECT  66.048 21.408 66.072 21.6 ;
    END
  END i[363]
  PIN i[364]
    DIRECTION INPUT ;
    USE SIGNAL ;
    PORT
      LAYER M5 ;
        RECT  66.24 21.408 66.264 21.6 ;
    END
  END i[364]
  PIN i[365]
    DIRECTION INPUT ;
    USE SIGNAL ;
    PORT
      LAYER M5 ;
        RECT  66.384 21.408 66.408 21.6 ;
    END
  END i[365]
  PIN i[366]
    DIRECTION INPUT ;
    USE SIGNAL ;
    PORT
      LAYER M5 ;
        RECT  66.576 21.408 66.6 21.6 ;
    END
  END i[366]
  PIN i[367]
    DIRECTION INPUT ;
    USE SIGNAL ;
    PORT
      LAYER M5 ;
        RECT  66.72 21.408 66.744 21.6 ;
    END
  END i[367]
  PIN i[368]
    DIRECTION INPUT ;
    USE SIGNAL ;
    PORT
      LAYER M5 ;
        RECT  66.912 21.408 66.936 21.6 ;
    END
  END i[368]
  PIN i[369]
    DIRECTION INPUT ;
    USE SIGNAL ;
    PORT
      LAYER M5 ;
        RECT  67.056 21.408 67.08 21.6 ;
    END
  END i[369]
  PIN i[36]
    DIRECTION INPUT ;
    USE SIGNAL ;
    PORT
      LAYER M5 ;
        RECT  10.416 21.408 10.44 21.6 ;
    END
  END i[36]
  PIN i[370]
    DIRECTION INPUT ;
    USE SIGNAL ;
    PORT
      LAYER M5 ;
        RECT  67.248 21.408 67.272 21.6 ;
    END
  END i[370]
  PIN i[371]
    DIRECTION INPUT ;
    USE SIGNAL ;
    PORT
      LAYER M5 ;
        RECT  67.392 21.408 67.416 21.6 ;
    END
  END i[371]
  PIN i[372]
    DIRECTION INPUT ;
    USE SIGNAL ;
    PORT
      LAYER M5 ;
        RECT  67.584 21.408 67.608 21.6 ;
    END
  END i[372]
  PIN i[373]
    DIRECTION INPUT ;
    USE SIGNAL ;
    PORT
      LAYER M5 ;
        RECT  67.728 21.408 67.752 21.6 ;
    END
  END i[373]
  PIN i[374]
    DIRECTION INPUT ;
    USE SIGNAL ;
    PORT
      LAYER M5 ;
        RECT  67.92 21.408 67.944 21.6 ;
    END
  END i[374]
  PIN i[375]
    DIRECTION INPUT ;
    USE SIGNAL ;
    PORT
      LAYER M5 ;
        RECT  68.064 21.408 68.088 21.6 ;
    END
  END i[375]
  PIN i[376]
    DIRECTION INPUT ;
    USE SIGNAL ;
    PORT
      LAYER M5 ;
        RECT  68.256 21.408 68.28 21.6 ;
    END
  END i[376]
  PIN i[377]
    DIRECTION INPUT ;
    USE SIGNAL ;
    PORT
      LAYER M5 ;
        RECT  68.4 21.408 68.424 21.6 ;
    END
  END i[377]
  PIN i[378]
    DIRECTION INPUT ;
    USE SIGNAL ;
    PORT
      LAYER M5 ;
        RECT  68.592 21.408 68.616 21.6 ;
    END
  END i[378]
  PIN i[379]
    DIRECTION INPUT ;
    USE SIGNAL ;
    PORT
      LAYER M5 ;
        RECT  68.784 21.408 68.808 21.6 ;
    END
  END i[379]
  PIN i[37]
    DIRECTION INPUT ;
    USE SIGNAL ;
    PORT
      LAYER M5 ;
        RECT  10.56 21.408 10.584 21.6 ;
    END
  END i[37]
  PIN i[380]
    DIRECTION INPUT ;
    USE SIGNAL ;
    PORT
      LAYER M5 ;
        RECT  68.928 21.408 68.952 21.6 ;
    END
  END i[380]
  PIN i[381]
    DIRECTION INPUT ;
    USE SIGNAL ;
    PORT
      LAYER M5 ;
        RECT  69.12 21.408 69.144 21.6 ;
    END
  END i[381]
  PIN i[382]
    DIRECTION INPUT ;
    USE SIGNAL ;
    PORT
      LAYER M5 ;
        RECT  69.264 21.408 69.288 21.6 ;
    END
  END i[382]
  PIN i[383]
    DIRECTION INPUT ;
    USE SIGNAL ;
    PORT
      LAYER M5 ;
        RECT  69.456 21.408 69.48 21.6 ;
    END
  END i[383]
  PIN i[384]
    DIRECTION INPUT ;
    USE SIGNAL ;
    PORT
      LAYER M5 ;
        RECT  69.6 21.408 69.624 21.6 ;
    END
  END i[384]
  PIN i[385]
    DIRECTION INPUT ;
    USE SIGNAL ;
    PORT
      LAYER M5 ;
        RECT  69.792 21.408 69.816 21.6 ;
    END
  END i[385]
  PIN i[386]
    DIRECTION INPUT ;
    USE SIGNAL ;
    PORT
      LAYER M5 ;
        RECT  69.936 21.408 69.96 21.6 ;
    END
  END i[386]
  PIN i[387]
    DIRECTION INPUT ;
    USE SIGNAL ;
    PORT
      LAYER M5 ;
        RECT  70.128 21.408 70.152 21.6 ;
    END
  END i[387]
  PIN i[388]
    DIRECTION INPUT ;
    USE SIGNAL ;
    PORT
      LAYER M5 ;
        RECT  70.272 21.408 70.296 21.6 ;
    END
  END i[388]
  PIN i[389]
    DIRECTION INPUT ;
    USE SIGNAL ;
    PORT
      LAYER M5 ;
        RECT  70.464 21.408 70.488 21.6 ;
    END
  END i[389]
  PIN i[38]
    DIRECTION INPUT ;
    USE SIGNAL ;
    PORT
      LAYER M5 ;
        RECT  10.752 21.408 10.776 21.6 ;
    END
  END i[38]
  PIN i[390]
    DIRECTION INPUT ;
    USE SIGNAL ;
    PORT
      LAYER M5 ;
        RECT  70.608 21.408 70.632 21.6 ;
    END
  END i[390]
  PIN i[391]
    DIRECTION INPUT ;
    USE SIGNAL ;
    PORT
      LAYER M5 ;
        RECT  70.8 21.408 70.824 21.6 ;
    END
  END i[391]
  PIN i[392]
    DIRECTION INPUT ;
    USE SIGNAL ;
    PORT
      LAYER M5 ;
        RECT  70.944 21.408 70.968 21.6 ;
    END
  END i[392]
  PIN i[393]
    DIRECTION INPUT ;
    USE SIGNAL ;
    PORT
      LAYER M5 ;
        RECT  71.136 21.408 71.16 21.6 ;
    END
  END i[393]
  PIN i[394]
    DIRECTION INPUT ;
    USE SIGNAL ;
    PORT
      LAYER M5 ;
        RECT  71.328 21.408 71.352 21.6 ;
    END
  END i[394]
  PIN i[395]
    DIRECTION INPUT ;
    USE SIGNAL ;
    PORT
      LAYER M5 ;
        RECT  71.472 21.408 71.496 21.6 ;
    END
  END i[395]
  PIN i[396]
    DIRECTION INPUT ;
    USE SIGNAL ;
    PORT
      LAYER M5 ;
        RECT  71.664 21.408 71.688 21.6 ;
    END
  END i[396]
  PIN i[397]
    DIRECTION INPUT ;
    USE SIGNAL ;
    PORT
      LAYER M5 ;
        RECT  71.808 21.408 71.832 21.6 ;
    END
  END i[397]
  PIN i[398]
    DIRECTION INPUT ;
    USE SIGNAL ;
    PORT
      LAYER M5 ;
        RECT  72 21.408 72.024 21.6 ;
    END
  END i[398]
  PIN i[399]
    DIRECTION INPUT ;
    USE SIGNAL ;
    PORT
      LAYER M5 ;
        RECT  72.144 21.408 72.168 21.6 ;
    END
  END i[399]
  PIN i[39]
    DIRECTION INPUT ;
    USE SIGNAL ;
    PORT
      LAYER M5 ;
        RECT  10.944 21.408 10.968 21.6 ;
    END
  END i[39]
  PIN i[3]
    DIRECTION INPUT ;
    USE SIGNAL ;
    PORT
      LAYER M5 ;
        RECT  4.8 21.408 4.824 21.6 ;
    END
  END i[3]
  PIN i[400]
    DIRECTION INPUT ;
    USE SIGNAL ;
    PORT
      LAYER M5 ;
        RECT  72.336 21.408 72.36 21.6 ;
    END
  END i[400]
  PIN i[401]
    DIRECTION INPUT ;
    USE SIGNAL ;
    PORT
      LAYER M5 ;
        RECT  72.48 21.408 72.504 21.6 ;
    END
  END i[401]
  PIN i[402]
    DIRECTION INPUT ;
    USE SIGNAL ;
    PORT
      LAYER M5 ;
        RECT  72.672 21.408 72.696 21.6 ;
    END
  END i[402]
  PIN i[403]
    DIRECTION INPUT ;
    USE SIGNAL ;
    PORT
      LAYER M5 ;
        RECT  72.816 21.408 72.84 21.6 ;
    END
  END i[403]
  PIN i[404]
    DIRECTION INPUT ;
    USE SIGNAL ;
    PORT
      LAYER M5 ;
        RECT  73.008 21.408 73.032 21.6 ;
    END
  END i[404]
  PIN i[405]
    DIRECTION INPUT ;
    USE SIGNAL ;
    PORT
      LAYER M5 ;
        RECT  73.152 21.408 73.176 21.6 ;
    END
  END i[405]
  PIN i[406]
    DIRECTION INPUT ;
    USE SIGNAL ;
    PORT
      LAYER M5 ;
        RECT  73.344 21.408 73.368 21.6 ;
    END
  END i[406]
  PIN i[407]
    DIRECTION INPUT ;
    USE SIGNAL ;
    PORT
      LAYER M5 ;
        RECT  73.488 21.408 73.512 21.6 ;
    END
  END i[407]
  PIN i[408]
    DIRECTION INPUT ;
    USE SIGNAL ;
    PORT
      LAYER M5 ;
        RECT  73.68 21.408 73.704 21.6 ;
    END
  END i[408]
  PIN i[409]
    DIRECTION INPUT ;
    USE SIGNAL ;
    PORT
      LAYER M5 ;
        RECT  73.872 21.408 73.896 21.6 ;
    END
  END i[409]
  PIN i[40]
    DIRECTION INPUT ;
    USE SIGNAL ;
    PORT
      LAYER M5 ;
        RECT  11.088 21.408 11.112 21.6 ;
    END
  END i[40]
  PIN i[410]
    DIRECTION INPUT ;
    USE SIGNAL ;
    PORT
      LAYER M5 ;
        RECT  74.016 21.408 74.04 21.6 ;
    END
  END i[410]
  PIN i[411]
    DIRECTION INPUT ;
    USE SIGNAL ;
    PORT
      LAYER M5 ;
        RECT  74.208 21.408 74.232 21.6 ;
    END
  END i[411]
  PIN i[412]
    DIRECTION INPUT ;
    USE SIGNAL ;
    PORT
      LAYER M5 ;
        RECT  74.352 21.408 74.376 21.6 ;
    END
  END i[412]
  PIN i[413]
    DIRECTION INPUT ;
    USE SIGNAL ;
    PORT
      LAYER M5 ;
        RECT  74.544 21.408 74.568 21.6 ;
    END
  END i[413]
  PIN i[414]
    DIRECTION INPUT ;
    USE SIGNAL ;
    PORT
      LAYER M5 ;
        RECT  74.688 21.408 74.712 21.6 ;
    END
  END i[414]
  PIN i[415]
    DIRECTION INPUT ;
    USE SIGNAL ;
    PORT
      LAYER M5 ;
        RECT  74.88 21.408 74.904 21.6 ;
    END
  END i[415]
  PIN i[416]
    DIRECTION INPUT ;
    USE SIGNAL ;
    PORT
      LAYER M5 ;
        RECT  75.024 21.408 75.048 21.6 ;
    END
  END i[416]
  PIN i[417]
    DIRECTION INPUT ;
    USE SIGNAL ;
    PORT
      LAYER M5 ;
        RECT  75.216 21.408 75.24 21.6 ;
    END
  END i[417]
  PIN i[418]
    DIRECTION INPUT ;
    USE SIGNAL ;
    PORT
      LAYER M5 ;
        RECT  75.36 21.408 75.384 21.6 ;
    END
  END i[418]
  PIN i[419]
    DIRECTION INPUT ;
    USE SIGNAL ;
    PORT
      LAYER M5 ;
        RECT  75.552 21.408 75.576 21.6 ;
    END
  END i[419]
  PIN i[41]
    DIRECTION INPUT ;
    USE SIGNAL ;
    PORT
      LAYER M5 ;
        RECT  11.28 21.408 11.304 21.6 ;
    END
  END i[41]
  PIN i[420]
    DIRECTION INPUT ;
    USE SIGNAL ;
    PORT
      LAYER M5 ;
        RECT  75.696 21.408 75.72 21.6 ;
    END
  END i[420]
  PIN i[421]
    DIRECTION INPUT ;
    USE SIGNAL ;
    PORT
      LAYER M5 ;
        RECT  75.888 21.408 75.912 21.6 ;
    END
  END i[421]
  PIN i[422]
    DIRECTION INPUT ;
    USE SIGNAL ;
    PORT
      LAYER M5 ;
        RECT  76.032 21.408 76.056 21.6 ;
    END
  END i[422]
  PIN i[423]
    DIRECTION INPUT ;
    USE SIGNAL ;
    PORT
      LAYER M5 ;
        RECT  76.224 21.408 76.248 21.6 ;
    END
  END i[423]
  PIN i[424]
    DIRECTION INPUT ;
    USE SIGNAL ;
    PORT
      LAYER M5 ;
        RECT  76.416 21.408 76.44 21.6 ;
    END
  END i[424]
  PIN i[425]
    DIRECTION INPUT ;
    USE SIGNAL ;
    PORT
      LAYER M5 ;
        RECT  76.56 21.408 76.584 21.6 ;
    END
  END i[425]
  PIN i[426]
    DIRECTION INPUT ;
    USE SIGNAL ;
    PORT
      LAYER M5 ;
        RECT  76.752 21.408 76.776 21.6 ;
    END
  END i[426]
  PIN i[427]
    DIRECTION INPUT ;
    USE SIGNAL ;
    PORT
      LAYER M5 ;
        RECT  76.896 21.408 76.92 21.6 ;
    END
  END i[427]
  PIN i[428]
    DIRECTION INPUT ;
    USE SIGNAL ;
    PORT
      LAYER M5 ;
        RECT  77.088 21.408 77.112 21.6 ;
    END
  END i[428]
  PIN i[429]
    DIRECTION INPUT ;
    USE SIGNAL ;
    PORT
      LAYER M5 ;
        RECT  77.232 21.408 77.256 21.6 ;
    END
  END i[429]
  PIN i[42]
    DIRECTION INPUT ;
    USE SIGNAL ;
    PORT
      LAYER M5 ;
        RECT  11.424 21.408 11.448 21.6 ;
    END
  END i[42]
  PIN i[430]
    DIRECTION INPUT ;
    USE SIGNAL ;
    PORT
      LAYER M5 ;
        RECT  77.424 21.408 77.448 21.6 ;
    END
  END i[430]
  PIN i[431]
    DIRECTION INPUT ;
    USE SIGNAL ;
    PORT
      LAYER M5 ;
        RECT  77.568 21.408 77.592 21.6 ;
    END
  END i[431]
  PIN i[432]
    DIRECTION INPUT ;
    USE SIGNAL ;
    PORT
      LAYER M5 ;
        RECT  77.76 21.408 77.784 21.6 ;
    END
  END i[432]
  PIN i[433]
    DIRECTION INPUT ;
    USE SIGNAL ;
    PORT
      LAYER M5 ;
        RECT  77.904 21.408 77.928 21.6 ;
    END
  END i[433]
  PIN i[434]
    DIRECTION INPUT ;
    USE SIGNAL ;
    PORT
      LAYER M5 ;
        RECT  78.096 21.408 78.12 21.6 ;
    END
  END i[434]
  PIN i[435]
    DIRECTION INPUT ;
    USE SIGNAL ;
    PORT
      LAYER M5 ;
        RECT  78.24 21.408 78.264 21.6 ;
    END
  END i[435]
  PIN i[436]
    DIRECTION INPUT ;
    USE SIGNAL ;
    PORT
      LAYER M5 ;
        RECT  78.432 21.408 78.456 21.6 ;
    END
  END i[436]
  PIN i[437]
    DIRECTION INPUT ;
    USE SIGNAL ;
    PORT
      LAYER M5 ;
        RECT  78.576 21.408 78.6 21.6 ;
    END
  END i[437]
  PIN i[438]
    DIRECTION INPUT ;
    USE SIGNAL ;
    PORT
      LAYER M5 ;
        RECT  78.768 21.408 78.792 21.6 ;
    END
  END i[438]
  PIN i[439]
    DIRECTION INPUT ;
    USE SIGNAL ;
    PORT
      LAYER M5 ;
        RECT  78.96 21.408 78.984 21.6 ;
    END
  END i[439]
  PIN i[43]
    DIRECTION INPUT ;
    USE SIGNAL ;
    PORT
      LAYER M5 ;
        RECT  11.616 21.408 11.64 21.6 ;
    END
  END i[43]
  PIN i[440]
    DIRECTION INPUT ;
    USE SIGNAL ;
    PORT
      LAYER M5 ;
        RECT  79.104 21.408 79.128 21.6 ;
    END
  END i[440]
  PIN i[441]
    DIRECTION INPUT ;
    USE SIGNAL ;
    PORT
      LAYER M5 ;
        RECT  79.296 21.408 79.32 21.6 ;
    END
  END i[441]
  PIN i[442]
    DIRECTION INPUT ;
    USE SIGNAL ;
    PORT
      LAYER M5 ;
        RECT  79.44 21.408 79.464 21.6 ;
    END
  END i[442]
  PIN i[443]
    DIRECTION INPUT ;
    USE SIGNAL ;
    PORT
      LAYER M5 ;
        RECT  79.632 21.408 79.656 21.6 ;
    END
  END i[443]
  PIN i[444]
    DIRECTION INPUT ;
    USE SIGNAL ;
    PORT
      LAYER M5 ;
        RECT  79.776 21.408 79.8 21.6 ;
    END
  END i[444]
  PIN i[445]
    DIRECTION INPUT ;
    USE SIGNAL ;
    PORT
      LAYER M5 ;
        RECT  79.968 21.408 79.992 21.6 ;
    END
  END i[445]
  PIN i[446]
    DIRECTION INPUT ;
    USE SIGNAL ;
    PORT
      LAYER M5 ;
        RECT  80.112 21.408 80.136 21.6 ;
    END
  END i[446]
  PIN i[447]
    DIRECTION INPUT ;
    USE SIGNAL ;
    PORT
      LAYER M5 ;
        RECT  80.304 21.408 80.328 21.6 ;
    END
  END i[447]
  PIN i[448]
    DIRECTION INPUT ;
    USE SIGNAL ;
    PORT
      LAYER M5 ;
        RECT  80.448 21.408 80.472 21.6 ;
    END
  END i[448]
  PIN i[449]
    DIRECTION INPUT ;
    USE SIGNAL ;
    PORT
      LAYER M5 ;
        RECT  80.64 21.408 80.664 21.6 ;
    END
  END i[449]
  PIN i[44]
    DIRECTION INPUT ;
    USE SIGNAL ;
    PORT
      LAYER M5 ;
        RECT  11.76 21.408 11.784 21.6 ;
    END
  END i[44]
  PIN i[450]
    DIRECTION INPUT ;
    USE SIGNAL ;
    PORT
      LAYER M5 ;
        RECT  80.784 21.408 80.808 21.6 ;
    END
  END i[450]
  PIN i[451]
    DIRECTION INPUT ;
    USE SIGNAL ;
    PORT
      LAYER M5 ;
        RECT  80.976 21.408 81 21.6 ;
    END
  END i[451]
  PIN i[452]
    DIRECTION INPUT ;
    USE SIGNAL ;
    PORT
      LAYER M5 ;
        RECT  81.12 21.408 81.144 21.6 ;
    END
  END i[452]
  PIN i[453]
    DIRECTION INPUT ;
    USE SIGNAL ;
    PORT
      LAYER M5 ;
        RECT  81.312 21.408 81.336 21.6 ;
    END
  END i[453]
  PIN i[454]
    DIRECTION INPUT ;
    USE SIGNAL ;
    PORT
      LAYER M5 ;
        RECT  81.504 21.408 81.528 21.6 ;
    END
  END i[454]
  PIN i[455]
    DIRECTION INPUT ;
    USE SIGNAL ;
    PORT
      LAYER M5 ;
        RECT  81.648 21.408 81.672 21.6 ;
    END
  END i[455]
  PIN i[456]
    DIRECTION INPUT ;
    USE SIGNAL ;
    PORT
      LAYER M5 ;
        RECT  81.84 21.408 81.864 21.6 ;
    END
  END i[456]
  PIN i[457]
    DIRECTION INPUT ;
    USE SIGNAL ;
    PORT
      LAYER M5 ;
        RECT  81.984 21.408 82.008 21.6 ;
    END
  END i[457]
  PIN i[458]
    DIRECTION INPUT ;
    USE SIGNAL ;
    PORT
      LAYER M5 ;
        RECT  82.176 21.408 82.2 21.6 ;
    END
  END i[458]
  PIN i[459]
    DIRECTION INPUT ;
    USE SIGNAL ;
    PORT
      LAYER M5 ;
        RECT  82.32 21.408 82.344 21.6 ;
    END
  END i[459]
  PIN i[45]
    DIRECTION INPUT ;
    USE SIGNAL ;
    PORT
      LAYER M5 ;
        RECT  11.952 21.408 11.976 21.6 ;
    END
  END i[45]
  PIN i[460]
    DIRECTION INPUT ;
    USE SIGNAL ;
    PORT
      LAYER M5 ;
        RECT  82.512 21.408 82.536 21.6 ;
    END
  END i[460]
  PIN i[461]
    DIRECTION INPUT ;
    USE SIGNAL ;
    PORT
      LAYER M5 ;
        RECT  82.656 21.408 82.68 21.6 ;
    END
  END i[461]
  PIN i[462]
    DIRECTION INPUT ;
    USE SIGNAL ;
    PORT
      LAYER M5 ;
        RECT  82.848 21.408 82.872 21.6 ;
    END
  END i[462]
  PIN i[463]
    DIRECTION INPUT ;
    USE SIGNAL ;
    PORT
      LAYER M5 ;
        RECT  82.992 21.408 83.016 21.6 ;
    END
  END i[463]
  PIN i[464]
    DIRECTION INPUT ;
    USE SIGNAL ;
    PORT
      LAYER M5 ;
        RECT  83.184 21.408 83.208 21.6 ;
    END
  END i[464]
  PIN i[465]
    DIRECTION INPUT ;
    USE SIGNAL ;
    PORT
      LAYER M5 ;
        RECT  83.328 21.408 83.352 21.6 ;
    END
  END i[465]
  PIN i[466]
    DIRECTION INPUT ;
    USE SIGNAL ;
    PORT
      LAYER M5 ;
        RECT  83.52 21.408 83.544 21.6 ;
    END
  END i[466]
  PIN i[467]
    DIRECTION INPUT ;
    USE SIGNAL ;
    PORT
      LAYER M5 ;
        RECT  83.664 21.408 83.688 21.6 ;
    END
  END i[467]
  PIN i[468]
    DIRECTION INPUT ;
    USE SIGNAL ;
    PORT
      LAYER M5 ;
        RECT  83.856 21.408 83.88 21.6 ;
    END
  END i[468]
  PIN i[469]
    DIRECTION INPUT ;
    USE SIGNAL ;
    PORT
      LAYER M5 ;
        RECT  84.048 21.408 84.072 21.6 ;
    END
  END i[469]
  PIN i[46]
    DIRECTION INPUT ;
    USE SIGNAL ;
    PORT
      LAYER M5 ;
        RECT  12.096 21.408 12.12 21.6 ;
    END
  END i[46]
  PIN i[470]
    DIRECTION INPUT ;
    USE SIGNAL ;
    PORT
      LAYER M5 ;
        RECT  84.192 21.408 84.216 21.6 ;
    END
  END i[470]
  PIN i[471]
    DIRECTION INPUT ;
    USE SIGNAL ;
    PORT
      LAYER M5 ;
        RECT  84.384 21.408 84.408 21.6 ;
    END
  END i[471]
  PIN i[472]
    DIRECTION INPUT ;
    USE SIGNAL ;
    PORT
      LAYER M5 ;
        RECT  84.528 21.408 84.552 21.6 ;
    END
  END i[472]
  PIN i[473]
    DIRECTION INPUT ;
    USE SIGNAL ;
    PORT
      LAYER M5 ;
        RECT  84.72 21.408 84.744 21.6 ;
    END
  END i[473]
  PIN i[474]
    DIRECTION INPUT ;
    USE SIGNAL ;
    PORT
      LAYER M5 ;
        RECT  84.864 21.408 84.888 21.6 ;
    END
  END i[474]
  PIN i[475]
    DIRECTION INPUT ;
    USE SIGNAL ;
    PORT
      LAYER M5 ;
        RECT  85.056 21.408 85.08 21.6 ;
    END
  END i[475]
  PIN i[476]
    DIRECTION INPUT ;
    USE SIGNAL ;
    PORT
      LAYER M5 ;
        RECT  85.2 21.408 85.224 21.6 ;
    END
  END i[476]
  PIN i[477]
    DIRECTION INPUT ;
    USE SIGNAL ;
    PORT
      LAYER M5 ;
        RECT  85.392 21.408 85.416 21.6 ;
    END
  END i[477]
  PIN i[478]
    DIRECTION INPUT ;
    USE SIGNAL ;
    PORT
      LAYER M5 ;
        RECT  85.536 21.408 85.56 21.6 ;
    END
  END i[478]
  PIN i[479]
    DIRECTION INPUT ;
    USE SIGNAL ;
    PORT
      LAYER M5 ;
        RECT  85.728 21.408 85.752 21.6 ;
    END
  END i[479]
  PIN i[47]
    DIRECTION INPUT ;
    USE SIGNAL ;
    PORT
      LAYER M5 ;
        RECT  12.288 21.408 12.312 21.6 ;
    END
  END i[47]
  PIN i[480]
    DIRECTION INPUT ;
    USE SIGNAL ;
    PORT
      LAYER M5 ;
        RECT  85.872 21.408 85.896 21.6 ;
    END
  END i[480]
  PIN i[481]
    DIRECTION INPUT ;
    USE SIGNAL ;
    PORT
      LAYER M5 ;
        RECT  86.064 21.408 86.088 21.6 ;
    END
  END i[481]
  PIN i[482]
    DIRECTION INPUT ;
    USE SIGNAL ;
    PORT
      LAYER M5 ;
        RECT  86.256 21.408 86.28 21.6 ;
    END
  END i[482]
  PIN i[483]
    DIRECTION INPUT ;
    USE SIGNAL ;
    PORT
      LAYER M5 ;
        RECT  86.4 21.408 86.424 21.6 ;
    END
  END i[483]
  PIN i[484]
    DIRECTION INPUT ;
    USE SIGNAL ;
    PORT
      LAYER M5 ;
        RECT  86.592 21.408 86.616 21.6 ;
    END
  END i[484]
  PIN i[485]
    DIRECTION INPUT ;
    USE SIGNAL ;
    PORT
      LAYER M5 ;
        RECT  86.736 21.408 86.76 21.6 ;
    END
  END i[485]
  PIN i[486]
    DIRECTION INPUT ;
    USE SIGNAL ;
    PORT
      LAYER M5 ;
        RECT  86.928 21.408 86.952 21.6 ;
    END
  END i[486]
  PIN i[487]
    DIRECTION INPUT ;
    USE SIGNAL ;
    PORT
      LAYER M5 ;
        RECT  87.072 21.408 87.096 21.6 ;
    END
  END i[487]
  PIN i[488]
    DIRECTION INPUT ;
    USE SIGNAL ;
    PORT
      LAYER M5 ;
        RECT  87.264 21.408 87.288 21.6 ;
    END
  END i[488]
  PIN i[489]
    DIRECTION INPUT ;
    USE SIGNAL ;
    PORT
      LAYER M5 ;
        RECT  87.408 21.408 87.432 21.6 ;
    END
  END i[489]
  PIN i[48]
    DIRECTION INPUT ;
    USE SIGNAL ;
    PORT
      LAYER M5 ;
        RECT  12.432 21.408 12.456 21.6 ;
    END
  END i[48]
  PIN i[490]
    DIRECTION INPUT ;
    USE SIGNAL ;
    PORT
      LAYER M5 ;
        RECT  87.6 21.408 87.624 21.6 ;
    END
  END i[490]
  PIN i[491]
    DIRECTION INPUT ;
    USE SIGNAL ;
    PORT
      LAYER M5 ;
        RECT  87.744 21.408 87.768 21.6 ;
    END
  END i[491]
  PIN i[492]
    DIRECTION INPUT ;
    USE SIGNAL ;
    PORT
      LAYER M5 ;
        RECT  87.936 21.408 87.96 21.6 ;
    END
  END i[492]
  PIN i[493]
    DIRECTION INPUT ;
    USE SIGNAL ;
    PORT
      LAYER M5 ;
        RECT  88.08 21.408 88.104 21.6 ;
    END
  END i[493]
  PIN i[494]
    DIRECTION INPUT ;
    USE SIGNAL ;
    PORT
      LAYER M5 ;
        RECT  88.272 21.408 88.296 21.6 ;
    END
  END i[494]
  PIN i[495]
    DIRECTION INPUT ;
    USE SIGNAL ;
    PORT
      LAYER M5 ;
        RECT  88.416 21.408 88.44 21.6 ;
    END
  END i[495]
  PIN i[496]
    DIRECTION INPUT ;
    USE SIGNAL ;
    PORT
      LAYER M5 ;
        RECT  88.608 21.408 88.632 21.6 ;
    END
  END i[496]
  PIN i[497]
    DIRECTION INPUT ;
    USE SIGNAL ;
    PORT
      LAYER M5 ;
        RECT  88.8 21.408 88.824 21.6 ;
    END
  END i[497]
  PIN i[498]
    DIRECTION INPUT ;
    USE SIGNAL ;
    PORT
      LAYER M5 ;
        RECT  88.944 21.408 88.968 21.6 ;
    END
  END i[498]
  PIN i[499]
    DIRECTION INPUT ;
    USE SIGNAL ;
    PORT
      LAYER M5 ;
        RECT  89.136 21.408 89.16 21.6 ;
    END
  END i[499]
  PIN i[49]
    DIRECTION INPUT ;
    USE SIGNAL ;
    PORT
      LAYER M5 ;
        RECT  12.624 21.408 12.648 21.6 ;
    END
  END i[49]
  PIN i[4]
    DIRECTION INPUT ;
    USE SIGNAL ;
    PORT
      LAYER M5 ;
        RECT  4.992 21.408 5.016 21.6 ;
    END
  END i[4]
  PIN i[500]
    DIRECTION INPUT ;
    USE SIGNAL ;
    PORT
      LAYER M5 ;
        RECT  89.28 21.408 89.304 21.6 ;
    END
  END i[500]
  PIN i[501]
    DIRECTION INPUT ;
    USE SIGNAL ;
    PORT
      LAYER M5 ;
        RECT  89.472 21.408 89.496 21.6 ;
    END
  END i[501]
  PIN i[502]
    DIRECTION INPUT ;
    USE SIGNAL ;
    PORT
      LAYER M5 ;
        RECT  89.616 21.408 89.64 21.6 ;
    END
  END i[502]
  PIN i[503]
    DIRECTION INPUT ;
    USE SIGNAL ;
    PORT
      LAYER M5 ;
        RECT  89.808 21.408 89.832 21.6 ;
    END
  END i[503]
  PIN i[504]
    DIRECTION INPUT ;
    USE SIGNAL ;
    PORT
      LAYER M5 ;
        RECT  89.952 21.408 89.976 21.6 ;
    END
  END i[504]
  PIN i[505]
    DIRECTION INPUT ;
    USE SIGNAL ;
    PORT
      LAYER M5 ;
        RECT  90.144 21.408 90.168 21.6 ;
    END
  END i[505]
  PIN i[506]
    DIRECTION INPUT ;
    USE SIGNAL ;
    PORT
      LAYER M5 ;
        RECT  90.288 21.408 90.312 21.6 ;
    END
  END i[506]
  PIN i[507]
    DIRECTION INPUT ;
    USE SIGNAL ;
    PORT
      LAYER M5 ;
        RECT  90.48 21.408 90.504 21.6 ;
    END
  END i[507]
  PIN i[508]
    DIRECTION INPUT ;
    USE SIGNAL ;
    PORT
      LAYER M5 ;
        RECT  90.624 21.408 90.648 21.6 ;
    END
  END i[508]
  PIN i[509]
    DIRECTION INPUT ;
    USE SIGNAL ;
    PORT
      LAYER M5 ;
        RECT  90.816 21.408 90.84 21.6 ;
    END
  END i[509]
  PIN i[50]
    DIRECTION INPUT ;
    USE SIGNAL ;
    PORT
      LAYER M5 ;
        RECT  12.768 21.408 12.792 21.6 ;
    END
  END i[50]
  PIN i[510]
    DIRECTION INPUT ;
    USE SIGNAL ;
    PORT
      LAYER M5 ;
        RECT  90.96 21.408 90.984 21.6 ;
    END
  END i[510]
  PIN i[511]
    DIRECTION INPUT ;
    USE SIGNAL ;
    PORT
      LAYER M5 ;
        RECT  91.152 21.408 91.176 21.6 ;
    END
  END i[511]
  PIN i[512]
    DIRECTION INPUT ;
    USE SIGNAL ;
    PORT
      LAYER M5 ;
        RECT  91.344 21.408 91.368 21.6 ;
    END
  END i[512]
  PIN i[513]
    DIRECTION INPUT ;
    USE SIGNAL ;
    PORT
      LAYER M5 ;
        RECT  91.488 21.408 91.512 21.6 ;
    END
  END i[513]
  PIN i[514]
    DIRECTION INPUT ;
    USE SIGNAL ;
    PORT
      LAYER M5 ;
        RECT  91.68 21.408 91.704 21.6 ;
    END
  END i[514]
  PIN i[515]
    DIRECTION INPUT ;
    USE SIGNAL ;
    PORT
      LAYER M5 ;
        RECT  91.824 21.408 91.848 21.6 ;
    END
  END i[515]
  PIN i[516]
    DIRECTION INPUT ;
    USE SIGNAL ;
    PORT
      LAYER M5 ;
        RECT  92.016 21.408 92.04 21.6 ;
    END
  END i[516]
  PIN i[517]
    DIRECTION INPUT ;
    USE SIGNAL ;
    PORT
      LAYER M5 ;
        RECT  92.16 21.408 92.184 21.6 ;
    END
  END i[517]
  PIN i[518]
    DIRECTION INPUT ;
    USE SIGNAL ;
    PORT
      LAYER M5 ;
        RECT  92.352 21.408 92.376 21.6 ;
    END
  END i[518]
  PIN i[519]
    DIRECTION INPUT ;
    USE SIGNAL ;
    PORT
      LAYER M5 ;
        RECT  92.496 21.408 92.52 21.6 ;
    END
  END i[519]
  PIN i[51]
    DIRECTION INPUT ;
    USE SIGNAL ;
    PORT
      LAYER M5 ;
        RECT  12.96 21.408 12.984 21.6 ;
    END
  END i[51]
  PIN i[520]
    DIRECTION INPUT ;
    USE SIGNAL ;
    PORT
      LAYER M5 ;
        RECT  92.688 21.408 92.712 21.6 ;
    END
  END i[520]
  PIN i[521]
    DIRECTION INPUT ;
    USE SIGNAL ;
    PORT
      LAYER M5 ;
        RECT  92.832 21.408 92.856 21.6 ;
    END
  END i[521]
  PIN i[522]
    DIRECTION INPUT ;
    USE SIGNAL ;
    PORT
      LAYER M5 ;
        RECT  93.024 21.408 93.048 21.6 ;
    END
  END i[522]
  PIN i[523]
    DIRECTION INPUT ;
    USE SIGNAL ;
    PORT
      LAYER M5 ;
        RECT  93.168 21.408 93.192 21.6 ;
    END
  END i[523]
  PIN i[524]
    DIRECTION INPUT ;
    USE SIGNAL ;
    PORT
      LAYER M5 ;
        RECT  93.36 21.408 93.384 21.6 ;
    END
  END i[524]
  PIN i[525]
    DIRECTION INPUT ;
    USE SIGNAL ;
    PORT
      LAYER M5 ;
        RECT  93.504 21.408 93.528 21.6 ;
    END
  END i[525]
  PIN i[526]
    DIRECTION INPUT ;
    USE SIGNAL ;
    PORT
      LAYER M5 ;
        RECT  93.696 21.408 93.72 21.6 ;
    END
  END i[526]
  PIN i[527]
    DIRECTION INPUT ;
    USE SIGNAL ;
    PORT
      LAYER M5 ;
        RECT  93.888 21.408 93.912 21.6 ;
    END
  END i[527]
  PIN i[528]
    DIRECTION INPUT ;
    USE SIGNAL ;
    PORT
      LAYER M5 ;
        RECT  94.032 21.408 94.056 21.6 ;
    END
  END i[528]
  PIN i[529]
    DIRECTION INPUT ;
    USE SIGNAL ;
    PORT
      LAYER M5 ;
        RECT  94.224 21.408 94.248 21.6 ;
    END
  END i[529]
  PIN i[52]
    DIRECTION INPUT ;
    USE SIGNAL ;
    PORT
      LAYER M5 ;
        RECT  13.152 21.408 13.176 21.6 ;
    END
  END i[52]
  PIN i[530]
    DIRECTION INPUT ;
    USE SIGNAL ;
    PORT
      LAYER M5 ;
        RECT  94.368 21.408 94.392 21.6 ;
    END
  END i[530]
  PIN i[531]
    DIRECTION INPUT ;
    USE SIGNAL ;
    PORT
      LAYER M5 ;
        RECT  94.56 21.408 94.584 21.6 ;
    END
  END i[531]
  PIN i[532]
    DIRECTION INPUT ;
    USE SIGNAL ;
    PORT
      LAYER M5 ;
        RECT  94.704 21.408 94.728 21.6 ;
    END
  END i[532]
  PIN i[533]
    DIRECTION INPUT ;
    USE SIGNAL ;
    PORT
      LAYER M5 ;
        RECT  94.896 21.408 94.92 21.6 ;
    END
  END i[533]
  PIN i[534]
    DIRECTION INPUT ;
    USE SIGNAL ;
    PORT
      LAYER M5 ;
        RECT  95.04 21.408 95.064 21.6 ;
    END
  END i[534]
  PIN i[535]
    DIRECTION INPUT ;
    USE SIGNAL ;
    PORT
      LAYER M5 ;
        RECT  95.232 21.408 95.256 21.6 ;
    END
  END i[535]
  PIN i[536]
    DIRECTION INPUT ;
    USE SIGNAL ;
    PORT
      LAYER M5 ;
        RECT  95.376 21.408 95.4 21.6 ;
    END
  END i[536]
  PIN i[537]
    DIRECTION INPUT ;
    USE SIGNAL ;
    PORT
      LAYER M5 ;
        RECT  95.568 21.408 95.592 21.6 ;
    END
  END i[537]
  PIN i[538]
    DIRECTION INPUT ;
    USE SIGNAL ;
    PORT
      LAYER M5 ;
        RECT  95.712 21.408 95.736 21.6 ;
    END
  END i[538]
  PIN i[539]
    DIRECTION INPUT ;
    USE SIGNAL ;
    PORT
      LAYER M5 ;
        RECT  95.904 21.408 95.928 21.6 ;
    END
  END i[539]
  PIN i[53]
    DIRECTION INPUT ;
    USE SIGNAL ;
    PORT
      LAYER M5 ;
        RECT  13.296 21.408 13.32 21.6 ;
    END
  END i[53]
  PIN i[540]
    DIRECTION INPUT ;
    USE SIGNAL ;
    PORT
      LAYER M5 ;
        RECT  96.048 21.408 96.072 21.6 ;
    END
  END i[540]
  PIN i[541]
    DIRECTION INPUT ;
    USE SIGNAL ;
    PORT
      LAYER M5 ;
        RECT  96.24 21.408 96.264 21.6 ;
    END
  END i[541]
  PIN i[542]
    DIRECTION INPUT ;
    USE SIGNAL ;
    PORT
      LAYER M5 ;
        RECT  96.432 21.408 96.456 21.6 ;
    END
  END i[542]
  PIN i[543]
    DIRECTION INPUT ;
    USE SIGNAL ;
    PORT
      LAYER M5 ;
        RECT  96.576 21.408 96.6 21.6 ;
    END
  END i[543]
  PIN i[544]
    DIRECTION INPUT ;
    USE SIGNAL ;
    PORT
      LAYER M5 ;
        RECT  96.768 21.408 96.792 21.6 ;
    END
  END i[544]
  PIN i[545]
    DIRECTION INPUT ;
    USE SIGNAL ;
    PORT
      LAYER M5 ;
        RECT  96.912 21.408 96.936 21.6 ;
    END
  END i[545]
  PIN i[546]
    DIRECTION INPUT ;
    USE SIGNAL ;
    PORT
      LAYER M5 ;
        RECT  97.104 21.408 97.128 21.6 ;
    END
  END i[546]
  PIN i[547]
    DIRECTION INPUT ;
    USE SIGNAL ;
    PORT
      LAYER M5 ;
        RECT  97.248 21.408 97.272 21.6 ;
    END
  END i[547]
  PIN i[548]
    DIRECTION INPUT ;
    USE SIGNAL ;
    PORT
      LAYER M5 ;
        RECT  97.44 21.408 97.464 21.6 ;
    END
  END i[548]
  PIN i[549]
    DIRECTION INPUT ;
    USE SIGNAL ;
    PORT
      LAYER M5 ;
        RECT  97.584 21.408 97.608 21.6 ;
    END
  END i[549]
  PIN i[54]
    DIRECTION INPUT ;
    USE SIGNAL ;
    PORT
      LAYER M5 ;
        RECT  13.488 21.408 13.512 21.6 ;
    END
  END i[54]
  PIN i[550]
    DIRECTION INPUT ;
    USE SIGNAL ;
    PORT
      LAYER M5 ;
        RECT  97.776 21.408 97.8 21.6 ;
    END
  END i[550]
  PIN i[551]
    DIRECTION INPUT ;
    USE SIGNAL ;
    PORT
      LAYER M5 ;
        RECT  97.92 21.408 97.944 21.6 ;
    END
  END i[551]
  PIN i[552]
    DIRECTION INPUT ;
    USE SIGNAL ;
    PORT
      LAYER M5 ;
        RECT  98.112 21.408 98.136 21.6 ;
    END
  END i[552]
  PIN i[553]
    DIRECTION INPUT ;
    USE SIGNAL ;
    PORT
      LAYER M5 ;
        RECT  98.256 21.408 98.28 21.6 ;
    END
  END i[553]
  PIN i[554]
    DIRECTION INPUT ;
    USE SIGNAL ;
    PORT
      LAYER M5 ;
        RECT  98.448 21.408 98.472 21.6 ;
    END
  END i[554]
  PIN i[555]
    DIRECTION INPUT ;
    USE SIGNAL ;
    PORT
      LAYER M5 ;
        RECT  98.592 21.408 98.616 21.6 ;
    END
  END i[555]
  PIN i[556]
    DIRECTION INPUT ;
    USE SIGNAL ;
    PORT
      LAYER M5 ;
        RECT  98.784 21.408 98.808 21.6 ;
    END
  END i[556]
  PIN i[557]
    DIRECTION INPUT ;
    USE SIGNAL ;
    PORT
      LAYER M5 ;
        RECT  98.976 21.408 99 21.6 ;
    END
  END i[557]
  PIN i[558]
    DIRECTION INPUT ;
    USE SIGNAL ;
    PORT
      LAYER M5 ;
        RECT  99.12 21.408 99.144 21.6 ;
    END
  END i[558]
  PIN i[559]
    DIRECTION INPUT ;
    USE SIGNAL ;
    PORT
      LAYER M5 ;
        RECT  99.312 21.408 99.336 21.6 ;
    END
  END i[559]
  PIN i[55]
    DIRECTION INPUT ;
    USE SIGNAL ;
    PORT
      LAYER M5 ;
        RECT  13.632 21.408 13.656 21.6 ;
    END
  END i[55]
  PIN i[560]
    DIRECTION INPUT ;
    USE SIGNAL ;
    PORT
      LAYER M5 ;
        RECT  99.456 21.408 99.48 21.6 ;
    END
  END i[560]
  PIN i[561]
    DIRECTION INPUT ;
    USE SIGNAL ;
    PORT
      LAYER M5 ;
        RECT  99.648 21.408 99.672 21.6 ;
    END
  END i[561]
  PIN i[562]
    DIRECTION INPUT ;
    USE SIGNAL ;
    PORT
      LAYER M5 ;
        RECT  99.792 21.408 99.816 21.6 ;
    END
  END i[562]
  PIN i[563]
    DIRECTION INPUT ;
    USE SIGNAL ;
    PORT
      LAYER M5 ;
        RECT  99.984 21.408 100.008 21.6 ;
    END
  END i[563]
  PIN i[564]
    DIRECTION INPUT ;
    USE SIGNAL ;
    PORT
      LAYER M5 ;
        RECT  100.128 21.408 100.152 21.6 ;
    END
  END i[564]
  PIN i[565]
    DIRECTION INPUT ;
    USE SIGNAL ;
    PORT
      LAYER M5 ;
        RECT  100.32 21.408 100.344 21.6 ;
    END
  END i[565]
  PIN i[566]
    DIRECTION INPUT ;
    USE SIGNAL ;
    PORT
      LAYER M5 ;
        RECT  100.464 21.408 100.488 21.6 ;
    END
  END i[566]
  PIN i[567]
    DIRECTION INPUT ;
    USE SIGNAL ;
    PORT
      LAYER M5 ;
        RECT  100.656 21.408 100.68 21.6 ;
    END
  END i[567]
  PIN i[568]
    DIRECTION INPUT ;
    USE SIGNAL ;
    PORT
      LAYER M5 ;
        RECT  100.8 21.408 100.824 21.6 ;
    END
  END i[568]
  PIN i[569]
    DIRECTION INPUT ;
    USE SIGNAL ;
    PORT
      LAYER M5 ;
        RECT  100.992 21.408 101.016 21.6 ;
    END
  END i[569]
  PIN i[56]
    DIRECTION INPUT ;
    USE SIGNAL ;
    PORT
      LAYER M5 ;
        RECT  13.824 21.408 13.848 21.6 ;
    END
  END i[56]
  PIN i[570]
    DIRECTION INPUT ;
    USE SIGNAL ;
    PORT
      LAYER M5 ;
        RECT  101.136 21.408 101.16 21.6 ;
    END
  END i[570]
  PIN i[571]
    DIRECTION INPUT ;
    USE SIGNAL ;
    PORT
      LAYER M5 ;
        RECT  101.328 21.408 101.352 21.6 ;
    END
  END i[571]
  PIN i[572]
    DIRECTION INPUT ;
    USE SIGNAL ;
    PORT
      LAYER M5 ;
        RECT  101.52 21.408 101.544 21.6 ;
    END
  END i[572]
  PIN i[573]
    DIRECTION INPUT ;
    USE SIGNAL ;
    PORT
      LAYER M5 ;
        RECT  101.664 21.408 101.688 21.6 ;
    END
  END i[573]
  PIN i[574]
    DIRECTION INPUT ;
    USE SIGNAL ;
    PORT
      LAYER M5 ;
        RECT  101.856 21.408 101.88 21.6 ;
    END
  END i[574]
  PIN i[575]
    DIRECTION INPUT ;
    USE SIGNAL ;
    PORT
      LAYER M5 ;
        RECT  102 21.408 102.024 21.6 ;
    END
  END i[575]
  PIN i[576]
    DIRECTION INPUT ;
    USE SIGNAL ;
    PORT
      LAYER M5 ;
        RECT  102.192 21.408 102.216 21.6 ;
    END
  END i[576]
  PIN i[577]
    DIRECTION INPUT ;
    USE SIGNAL ;
    PORT
      LAYER M5 ;
        RECT  102.336 21.408 102.36 21.6 ;
    END
  END i[577]
  PIN i[578]
    DIRECTION INPUT ;
    USE SIGNAL ;
    PORT
      LAYER M5 ;
        RECT  102.528 21.408 102.552 21.6 ;
    END
  END i[578]
  PIN i[579]
    DIRECTION INPUT ;
    USE SIGNAL ;
    PORT
      LAYER M5 ;
        RECT  102.672 21.408 102.696 21.6 ;
    END
  END i[579]
  PIN i[57]
    DIRECTION INPUT ;
    USE SIGNAL ;
    PORT
      LAYER M5 ;
        RECT  13.968 21.408 13.992 21.6 ;
    END
  END i[57]
  PIN i[580]
    DIRECTION INPUT ;
    USE SIGNAL ;
    PORT
      LAYER M5 ;
        RECT  102.864 21.408 102.888 21.6 ;
    END
  END i[580]
  PIN i[581]
    DIRECTION INPUT ;
    USE SIGNAL ;
    PORT
      LAYER M5 ;
        RECT  103.008 21.408 103.032 21.6 ;
    END
  END i[581]
  PIN i[582]
    DIRECTION INPUT ;
    USE SIGNAL ;
    PORT
      LAYER M5 ;
        RECT  103.2 21.408 103.224 21.6 ;
    END
  END i[582]
  PIN i[583]
    DIRECTION INPUT ;
    USE SIGNAL ;
    PORT
      LAYER M5 ;
        RECT  103.344 21.408 103.368 21.6 ;
    END
  END i[583]
  PIN i[584]
    DIRECTION INPUT ;
    USE SIGNAL ;
    PORT
      LAYER M5 ;
        RECT  103.536 21.408 103.56 21.6 ;
    END
  END i[584]
  PIN i[585]
    DIRECTION INPUT ;
    USE SIGNAL ;
    PORT
      LAYER M5 ;
        RECT  103.68 21.408 103.704 21.6 ;
    END
  END i[585]
  PIN i[586]
    DIRECTION INPUT ;
    USE SIGNAL ;
    PORT
      LAYER M5 ;
        RECT  103.872 21.408 103.896 21.6 ;
    END
  END i[586]
  PIN i[587]
    DIRECTION INPUT ;
    USE SIGNAL ;
    PORT
      LAYER M5 ;
        RECT  104.064 21.408 104.088 21.6 ;
    END
  END i[587]
  PIN i[588]
    DIRECTION INPUT ;
    USE SIGNAL ;
    PORT
      LAYER M5 ;
        RECT  104.208 21.408 104.232 21.6 ;
    END
  END i[588]
  PIN i[589]
    DIRECTION INPUT ;
    USE SIGNAL ;
    PORT
      LAYER M5 ;
        RECT  104.4 21.408 104.424 21.6 ;
    END
  END i[589]
  PIN i[58]
    DIRECTION INPUT ;
    USE SIGNAL ;
    PORT
      LAYER M5 ;
        RECT  14.16 21.408 14.184 21.6 ;
    END
  END i[58]
  PIN i[590]
    DIRECTION INPUT ;
    USE SIGNAL ;
    PORT
      LAYER M5 ;
        RECT  104.544 21.408 104.568 21.6 ;
    END
  END i[590]
  PIN i[591]
    DIRECTION INPUT ;
    USE SIGNAL ;
    PORT
      LAYER M5 ;
        RECT  104.736 21.408 104.76 21.6 ;
    END
  END i[591]
  PIN i[592]
    DIRECTION INPUT ;
    USE SIGNAL ;
    PORT
      LAYER M5 ;
        RECT  104.88 21.408 104.904 21.6 ;
    END
  END i[592]
  PIN i[593]
    DIRECTION INPUT ;
    USE SIGNAL ;
    PORT
      LAYER M5 ;
        RECT  105.072 21.408 105.096 21.6 ;
    END
  END i[593]
  PIN i[594]
    DIRECTION INPUT ;
    USE SIGNAL ;
    PORT
      LAYER M5 ;
        RECT  105.216 21.408 105.24 21.6 ;
    END
  END i[594]
  PIN i[595]
    DIRECTION INPUT ;
    USE SIGNAL ;
    PORT
      LAYER M5 ;
        RECT  105.408 21.408 105.432 21.6 ;
    END
  END i[595]
  PIN i[596]
    DIRECTION INPUT ;
    USE SIGNAL ;
    PORT
      LAYER M5 ;
        RECT  105.552 21.408 105.576 21.6 ;
    END
  END i[596]
  PIN i[597]
    DIRECTION INPUT ;
    USE SIGNAL ;
    PORT
      LAYER M5 ;
        RECT  105.744 21.408 105.768 21.6 ;
    END
  END i[597]
  PIN i[598]
    DIRECTION INPUT ;
    USE SIGNAL ;
    PORT
      LAYER M5 ;
        RECT  105.888 21.408 105.912 21.6 ;
    END
  END i[598]
  PIN i[599]
    DIRECTION INPUT ;
    USE SIGNAL ;
    PORT
      LAYER M5 ;
        RECT  106.08 21.408 106.104 21.6 ;
    END
  END i[599]
  PIN i[59]
    DIRECTION INPUT ;
    USE SIGNAL ;
    PORT
      LAYER M5 ;
        RECT  14.304 21.408 14.328 21.6 ;
    END
  END i[59]
  PIN i[5]
    DIRECTION INPUT ;
    USE SIGNAL ;
    PORT
      LAYER M5 ;
        RECT  5.136 21.408 5.16 21.6 ;
    END
  END i[5]
  PIN i[600]
    DIRECTION INPUT ;
    USE SIGNAL ;
    PORT
      LAYER M5 ;
        RECT  106.224 21.408 106.248 21.6 ;
    END
  END i[600]
  PIN i[601]
    DIRECTION INPUT ;
    USE SIGNAL ;
    PORT
      LAYER M5 ;
        RECT  106.416 21.408 106.44 21.6 ;
    END
  END i[601]
  PIN i[602]
    DIRECTION INPUT ;
    USE SIGNAL ;
    PORT
      LAYER M5 ;
        RECT  106.608 21.408 106.632 21.6 ;
    END
  END i[602]
  PIN i[603]
    DIRECTION INPUT ;
    USE SIGNAL ;
    PORT
      LAYER M5 ;
        RECT  106.752 21.408 106.776 21.6 ;
    END
  END i[603]
  PIN i[604]
    DIRECTION INPUT ;
    USE SIGNAL ;
    PORT
      LAYER M5 ;
        RECT  106.944 21.408 106.968 21.6 ;
    END
  END i[604]
  PIN i[605]
    DIRECTION INPUT ;
    USE SIGNAL ;
    PORT
      LAYER M5 ;
        RECT  107.088 21.408 107.112 21.6 ;
    END
  END i[605]
  PIN i[606]
    DIRECTION INPUT ;
    USE SIGNAL ;
    PORT
      LAYER M5 ;
        RECT  107.28 21.408 107.304 21.6 ;
    END
  END i[606]
  PIN i[607]
    DIRECTION INPUT ;
    USE SIGNAL ;
    PORT
      LAYER M5 ;
        RECT  107.424 21.408 107.448 21.6 ;
    END
  END i[607]
  PIN i[608]
    DIRECTION INPUT ;
    USE SIGNAL ;
    PORT
      LAYER M5 ;
        RECT  107.616 21.408 107.64 21.6 ;
    END
  END i[608]
  PIN i[609]
    DIRECTION INPUT ;
    USE SIGNAL ;
    PORT
      LAYER M5 ;
        RECT  107.76 21.408 107.784 21.6 ;
    END
  END i[609]
  PIN i[60]
    DIRECTION INPUT ;
    USE SIGNAL ;
    PORT
      LAYER M5 ;
        RECT  14.496 21.408 14.52 21.6 ;
    END
  END i[60]
  PIN i[610]
    DIRECTION INPUT ;
    USE SIGNAL ;
    PORT
      LAYER M5 ;
        RECT  107.952 21.408 107.976 21.6 ;
    END
  END i[610]
  PIN i[611]
    DIRECTION INPUT ;
    USE SIGNAL ;
    PORT
      LAYER M5 ;
        RECT  108.096 21.408 108.12 21.6 ;
    END
  END i[611]
  PIN i[612]
    DIRECTION INPUT ;
    USE SIGNAL ;
    PORT
      LAYER M5 ;
        RECT  108.288 21.408 108.312 21.6 ;
    END
  END i[612]
  PIN i[613]
    DIRECTION INPUT ;
    USE SIGNAL ;
    PORT
      LAYER M5 ;
        RECT  108.432 21.408 108.456 21.6 ;
    END
  END i[613]
  PIN i[614]
    DIRECTION INPUT ;
    USE SIGNAL ;
    PORT
      LAYER M5 ;
        RECT  108.624 21.408 108.648 21.6 ;
    END
  END i[614]
  PIN i[615]
    DIRECTION INPUT ;
    USE SIGNAL ;
    PORT
      LAYER M5 ;
        RECT  108.768 21.408 108.792 21.6 ;
    END
  END i[615]
  PIN i[616]
    DIRECTION INPUT ;
    USE SIGNAL ;
    PORT
      LAYER M5 ;
        RECT  108.96 21.408 108.984 21.6 ;
    END
  END i[616]
  PIN i[617]
    DIRECTION INPUT ;
    USE SIGNAL ;
    PORT
      LAYER M5 ;
        RECT  109.152 21.408 109.176 21.6 ;
    END
  END i[617]
  PIN i[618]
    DIRECTION INPUT ;
    USE SIGNAL ;
    PORT
      LAYER M5 ;
        RECT  109.296 21.408 109.32 21.6 ;
    END
  END i[618]
  PIN i[619]
    DIRECTION INPUT ;
    USE SIGNAL ;
    PORT
      LAYER M5 ;
        RECT  109.488 21.408 109.512 21.6 ;
    END
  END i[619]
  PIN i[61]
    DIRECTION INPUT ;
    USE SIGNAL ;
    PORT
      LAYER M5 ;
        RECT  14.64 21.408 14.664 21.6 ;
    END
  END i[61]
  PIN i[620]
    DIRECTION INPUT ;
    USE SIGNAL ;
    PORT
      LAYER M5 ;
        RECT  109.632 21.408 109.656 21.6 ;
    END
  END i[620]
  PIN i[621]
    DIRECTION INPUT ;
    USE SIGNAL ;
    PORT
      LAYER M5 ;
        RECT  109.824 21.408 109.848 21.6 ;
    END
  END i[621]
  PIN i[622]
    DIRECTION INPUT ;
    USE SIGNAL ;
    PORT
      LAYER M5 ;
        RECT  109.968 21.408 109.992 21.6 ;
    END
  END i[622]
  PIN i[623]
    DIRECTION INPUT ;
    USE SIGNAL ;
    PORT
      LAYER M5 ;
        RECT  110.16 21.408 110.184 21.6 ;
    END
  END i[623]
  PIN i[62]
    DIRECTION INPUT ;
    USE SIGNAL ;
    PORT
      LAYER M5 ;
        RECT  14.832 21.408 14.856 21.6 ;
    END
  END i[62]
  PIN i[63]
    DIRECTION INPUT ;
    USE SIGNAL ;
    PORT
      LAYER M5 ;
        RECT  14.976 21.408 15 21.6 ;
    END
  END i[63]
  PIN i[64]
    DIRECTION INPUT ;
    USE SIGNAL ;
    PORT
      LAYER M5 ;
        RECT  15.168 21.408 15.192 21.6 ;
    END
  END i[64]
  PIN i[65]
    DIRECTION INPUT ;
    USE SIGNAL ;
    PORT
      LAYER M5 ;
        RECT  15.312 21.408 15.336 21.6 ;
    END
  END i[65]
  PIN i[66]
    DIRECTION INPUT ;
    USE SIGNAL ;
    PORT
      LAYER M5 ;
        RECT  15.504 21.408 15.528 21.6 ;
    END
  END i[66]
  PIN i[67]
    DIRECTION INPUT ;
    USE SIGNAL ;
    PORT
      LAYER M5 ;
        RECT  15.696 21.408 15.72 21.6 ;
    END
  END i[67]
  PIN i[68]
    DIRECTION INPUT ;
    USE SIGNAL ;
    PORT
      LAYER M5 ;
        RECT  15.84 21.408 15.864 21.6 ;
    END
  END i[68]
  PIN i[69]
    DIRECTION INPUT ;
    USE SIGNAL ;
    PORT
      LAYER M5 ;
        RECT  16.032 21.408 16.056 21.6 ;
    END
  END i[69]
  PIN i[6]
    DIRECTION INPUT ;
    USE SIGNAL ;
    PORT
      LAYER M5 ;
        RECT  5.328 21.408 5.352 21.6 ;
    END
  END i[6]
  PIN i[70]
    DIRECTION INPUT ;
    USE SIGNAL ;
    PORT
      LAYER M5 ;
        RECT  16.176 21.408 16.2 21.6 ;
    END
  END i[70]
  PIN i[71]
    DIRECTION INPUT ;
    USE SIGNAL ;
    PORT
      LAYER M5 ;
        RECT  16.368 21.408 16.392 21.6 ;
    END
  END i[71]
  PIN i[72]
    DIRECTION INPUT ;
    USE SIGNAL ;
    PORT
      LAYER M5 ;
        RECT  16.512 21.408 16.536 21.6 ;
    END
  END i[72]
  PIN i[73]
    DIRECTION INPUT ;
    USE SIGNAL ;
    PORT
      LAYER M5 ;
        RECT  16.704 21.408 16.728 21.6 ;
    END
  END i[73]
  PIN i[74]
    DIRECTION INPUT ;
    USE SIGNAL ;
    PORT
      LAYER M5 ;
        RECT  16.848 21.408 16.872 21.6 ;
    END
  END i[74]
  PIN i[75]
    DIRECTION INPUT ;
    USE SIGNAL ;
    PORT
      LAYER M5 ;
        RECT  17.04 21.408 17.064 21.6 ;
    END
  END i[75]
  PIN i[76]
    DIRECTION INPUT ;
    USE SIGNAL ;
    PORT
      LAYER M5 ;
        RECT  17.184 21.408 17.208 21.6 ;
    END
  END i[76]
  PIN i[77]
    DIRECTION INPUT ;
    USE SIGNAL ;
    PORT
      LAYER M5 ;
        RECT  17.376 21.408 17.4 21.6 ;
    END
  END i[77]
  PIN i[78]
    DIRECTION INPUT ;
    USE SIGNAL ;
    PORT
      LAYER M5 ;
        RECT  17.52 21.408 17.544 21.6 ;
    END
  END i[78]
  PIN i[79]
    DIRECTION INPUT ;
    USE SIGNAL ;
    PORT
      LAYER M5 ;
        RECT  17.712 21.408 17.736 21.6 ;
    END
  END i[79]
  PIN i[7]
    DIRECTION INPUT ;
    USE SIGNAL ;
    PORT
      LAYER M5 ;
        RECT  5.472 21.408 5.496 21.6 ;
    END
  END i[7]
  PIN i[80]
    DIRECTION INPUT ;
    USE SIGNAL ;
    PORT
      LAYER M5 ;
        RECT  17.856 21.408 17.88 21.6 ;
    END
  END i[80]
  PIN i[81]
    DIRECTION INPUT ;
    USE SIGNAL ;
    PORT
      LAYER M5 ;
        RECT  18.048 21.408 18.072 21.6 ;
    END
  END i[81]
  PIN i[82]
    DIRECTION INPUT ;
    USE SIGNAL ;
    PORT
      LAYER M5 ;
        RECT  18.24 21.408 18.264 21.6 ;
    END
  END i[82]
  PIN i[83]
    DIRECTION INPUT ;
    USE SIGNAL ;
    PORT
      LAYER M5 ;
        RECT  18.384 21.408 18.408 21.6 ;
    END
  END i[83]
  PIN i[84]
    DIRECTION INPUT ;
    USE SIGNAL ;
    PORT
      LAYER M5 ;
        RECT  18.576 21.408 18.6 21.6 ;
    END
  END i[84]
  PIN i[85]
    DIRECTION INPUT ;
    USE SIGNAL ;
    PORT
      LAYER M5 ;
        RECT  18.72 21.408 18.744 21.6 ;
    END
  END i[85]
  PIN i[86]
    DIRECTION INPUT ;
    USE SIGNAL ;
    PORT
      LAYER M5 ;
        RECT  18.912 21.408 18.936 21.6 ;
    END
  END i[86]
  PIN i[87]
    DIRECTION INPUT ;
    USE SIGNAL ;
    PORT
      LAYER M5 ;
        RECT  19.056 21.408 19.08 21.6 ;
    END
  END i[87]
  PIN i[88]
    DIRECTION INPUT ;
    USE SIGNAL ;
    PORT
      LAYER M5 ;
        RECT  19.248 21.408 19.272 21.6 ;
    END
  END i[88]
  PIN i[89]
    DIRECTION INPUT ;
    USE SIGNAL ;
    PORT
      LAYER M5 ;
        RECT  19.392 21.408 19.416 21.6 ;
    END
  END i[89]
  PIN i[8]
    DIRECTION INPUT ;
    USE SIGNAL ;
    PORT
      LAYER M5 ;
        RECT  5.664 21.408 5.688 21.6 ;
    END
  END i[8]
  PIN i[90]
    DIRECTION INPUT ;
    USE SIGNAL ;
    PORT
      LAYER M5 ;
        RECT  19.584 21.408 19.608 21.6 ;
    END
  END i[90]
  PIN i[91]
    DIRECTION INPUT ;
    USE SIGNAL ;
    PORT
      LAYER M5 ;
        RECT  19.728 21.408 19.752 21.6 ;
    END
  END i[91]
  PIN i[92]
    DIRECTION INPUT ;
    USE SIGNAL ;
    PORT
      LAYER M5 ;
        RECT  19.92 21.408 19.944 21.6 ;
    END
  END i[92]
  PIN i[93]
    DIRECTION INPUT ;
    USE SIGNAL ;
    PORT
      LAYER M5 ;
        RECT  20.064 21.408 20.088 21.6 ;
    END
  END i[93]
  PIN i[94]
    DIRECTION INPUT ;
    USE SIGNAL ;
    PORT
      LAYER M5 ;
        RECT  20.256 21.408 20.28 21.6 ;
    END
  END i[94]
  PIN i[95]
    DIRECTION INPUT ;
    USE SIGNAL ;
    PORT
      LAYER M5 ;
        RECT  20.4 21.408 20.424 21.6 ;
    END
  END i[95]
  PIN i[96]
    DIRECTION INPUT ;
    USE SIGNAL ;
    PORT
      LAYER M5 ;
        RECT  20.592 21.408 20.616 21.6 ;
    END
  END i[96]
  PIN i[97]
    DIRECTION INPUT ;
    USE SIGNAL ;
    PORT
      LAYER M5 ;
        RECT  20.784 21.408 20.808 21.6 ;
    END
  END i[97]
  PIN i[98]
    DIRECTION INPUT ;
    USE SIGNAL ;
    PORT
      LAYER M5 ;
        RECT  20.928 21.408 20.952 21.6 ;
    END
  END i[98]
  PIN i[99]
    DIRECTION INPUT ;
    USE SIGNAL ;
    PORT
      LAYER M5 ;
        RECT  21.12 21.408 21.144 21.6 ;
    END
  END i[99]
  PIN i[9]
    DIRECTION INPUT ;
    USE SIGNAL ;
    PORT
      LAYER M5 ;
        RECT  5.856 21.408 5.88 21.6 ;
    END
  END i[9]
  PIN o[0]
    DIRECTION OUTPUT ;
    USE SIGNAL ;
    PORT
      LAYER M5 ;
        RECT  4.32 0 4.344 0.192 ;
    END
  END o[0]
  PIN o[100]
    DIRECTION OUTPUT ;
    USE SIGNAL ;
    PORT
      LAYER M5 ;
        RECT  21.264 0 21.288 0.192 ;
    END
  END o[100]
  PIN o[101]
    DIRECTION OUTPUT ;
    USE SIGNAL ;
    PORT
      LAYER M5 ;
        RECT  21.456 0 21.48 0.192 ;
    END
  END o[101]
  PIN o[102]
    DIRECTION OUTPUT ;
    USE SIGNAL ;
    PORT
      LAYER M5 ;
        RECT  21.6 0 21.624 0.192 ;
    END
  END o[102]
  PIN o[103]
    DIRECTION OUTPUT ;
    USE SIGNAL ;
    PORT
      LAYER M5 ;
        RECT  21.792 0 21.816 0.192 ;
    END
  END o[103]
  PIN o[104]
    DIRECTION OUTPUT ;
    USE SIGNAL ;
    PORT
      LAYER M5 ;
        RECT  21.936 0 21.96 0.192 ;
    END
  END o[104]
  PIN o[105]
    DIRECTION OUTPUT ;
    USE SIGNAL ;
    PORT
      LAYER M5 ;
        RECT  22.128 0 22.152 0.192 ;
    END
  END o[105]
  PIN o[106]
    DIRECTION OUTPUT ;
    USE SIGNAL ;
    PORT
      LAYER M5 ;
        RECT  22.272 0 22.296 0.192 ;
    END
  END o[106]
  PIN o[107]
    DIRECTION OUTPUT ;
    USE SIGNAL ;
    PORT
      LAYER M5 ;
        RECT  22.464 0 22.488 0.192 ;
    END
  END o[107]
  PIN o[108]
    DIRECTION OUTPUT ;
    USE SIGNAL ;
    PORT
      LAYER M5 ;
        RECT  22.608 0 22.632 0.192 ;
    END
  END o[108]
  PIN o[109]
    DIRECTION OUTPUT ;
    USE SIGNAL ;
    PORT
      LAYER M5 ;
        RECT  22.8 0 22.824 0.192 ;
    END
  END o[109]
  PIN o[10]
    DIRECTION OUTPUT ;
    USE SIGNAL ;
    PORT
      LAYER M5 ;
        RECT  6 0 6.024 0.192 ;
    END
  END o[10]
  PIN o[110]
    DIRECTION OUTPUT ;
    USE SIGNAL ;
    PORT
      LAYER M5 ;
        RECT  22.944 0 22.968 0.192 ;
    END
  END o[110]
  PIN o[111]
    DIRECTION OUTPUT ;
    USE SIGNAL ;
    PORT
      LAYER M5 ;
        RECT  23.136 0 23.16 0.192 ;
    END
  END o[111]
  PIN o[112]
    DIRECTION OUTPUT ;
    USE SIGNAL ;
    PORT
      LAYER M5 ;
        RECT  23.328 0 23.352 0.192 ;
    END
  END o[112]
  PIN o[113]
    DIRECTION OUTPUT ;
    USE SIGNAL ;
    PORT
      LAYER M5 ;
        RECT  23.472 0 23.496 0.192 ;
    END
  END o[113]
  PIN o[114]
    DIRECTION OUTPUT ;
    USE SIGNAL ;
    PORT
      LAYER M5 ;
        RECT  23.664 0 23.688 0.192 ;
    END
  END o[114]
  PIN o[115]
    DIRECTION OUTPUT ;
    USE SIGNAL ;
    PORT
      LAYER M5 ;
        RECT  23.808 0 23.832 0.192 ;
    END
  END o[115]
  PIN o[116]
    DIRECTION OUTPUT ;
    USE SIGNAL ;
    PORT
      LAYER M5 ;
        RECT  24 0 24.024 0.192 ;
    END
  END o[116]
  PIN o[117]
    DIRECTION OUTPUT ;
    USE SIGNAL ;
    PORT
      LAYER M5 ;
        RECT  24.144 0 24.168 0.192 ;
    END
  END o[117]
  PIN o[118]
    DIRECTION OUTPUT ;
    USE SIGNAL ;
    PORT
      LAYER M5 ;
        RECT  24.336 0 24.36 0.192 ;
    END
  END o[118]
  PIN o[119]
    DIRECTION OUTPUT ;
    USE SIGNAL ;
    PORT
      LAYER M5 ;
        RECT  24.48 0 24.504 0.192 ;
    END
  END o[119]
  PIN o[11]
    DIRECTION OUTPUT ;
    USE SIGNAL ;
    PORT
      LAYER M5 ;
        RECT  6.192 0 6.216 0.192 ;
    END
  END o[11]
  PIN o[120]
    DIRECTION OUTPUT ;
    USE SIGNAL ;
    PORT
      LAYER M5 ;
        RECT  24.672 0 24.696 0.192 ;
    END
  END o[120]
  PIN o[121]
    DIRECTION OUTPUT ;
    USE SIGNAL ;
    PORT
      LAYER M5 ;
        RECT  24.816 0 24.84 0.192 ;
    END
  END o[121]
  PIN o[122]
    DIRECTION OUTPUT ;
    USE SIGNAL ;
    PORT
      LAYER M5 ;
        RECT  25.008 0 25.032 0.192 ;
    END
  END o[122]
  PIN o[123]
    DIRECTION OUTPUT ;
    USE SIGNAL ;
    PORT
      LAYER M5 ;
        RECT  25.152 0 25.176 0.192 ;
    END
  END o[123]
  PIN o[124]
    DIRECTION OUTPUT ;
    USE SIGNAL ;
    PORT
      LAYER M5 ;
        RECT  25.344 0 25.368 0.192 ;
    END
  END o[124]
  PIN o[125]
    DIRECTION OUTPUT ;
    USE SIGNAL ;
    PORT
      LAYER M5 ;
        RECT  25.488 0 25.512 0.192 ;
    END
  END o[125]
  PIN o[126]
    DIRECTION OUTPUT ;
    USE SIGNAL ;
    PORT
      LAYER M5 ;
        RECT  25.68 0 25.704 0.192 ;
    END
  END o[126]
  PIN o[127]
    DIRECTION OUTPUT ;
    USE SIGNAL ;
    PORT
      LAYER M5 ;
        RECT  25.872 0 25.896 0.192 ;
    END
  END o[127]
  PIN o[128]
    DIRECTION OUTPUT ;
    USE SIGNAL ;
    PORT
      LAYER M5 ;
        RECT  26.016 0 26.04 0.192 ;
    END
  END o[128]
  PIN o[129]
    DIRECTION OUTPUT ;
    USE SIGNAL ;
    PORT
      LAYER M5 ;
        RECT  26.208 0 26.232 0.192 ;
    END
  END o[129]
  PIN o[12]
    DIRECTION OUTPUT ;
    USE SIGNAL ;
    PORT
      LAYER M5 ;
        RECT  6.336 0 6.36 0.192 ;
    END
  END o[12]
  PIN o[130]
    DIRECTION OUTPUT ;
    USE SIGNAL ;
    PORT
      LAYER M5 ;
        RECT  26.352 0 26.376 0.192 ;
    END
  END o[130]
  PIN o[131]
    DIRECTION OUTPUT ;
    USE SIGNAL ;
    PORT
      LAYER M5 ;
        RECT  26.544 0 26.568 0.192 ;
    END
  END o[131]
  PIN o[132]
    DIRECTION OUTPUT ;
    USE SIGNAL ;
    PORT
      LAYER M5 ;
        RECT  26.688 0 26.712 0.192 ;
    END
  END o[132]
  PIN o[133]
    DIRECTION OUTPUT ;
    USE SIGNAL ;
    PORT
      LAYER M5 ;
        RECT  26.88 0 26.904 0.192 ;
    END
  END o[133]
  PIN o[134]
    DIRECTION OUTPUT ;
    USE SIGNAL ;
    PORT
      LAYER M5 ;
        RECT  27.024 0 27.048 0.192 ;
    END
  END o[134]
  PIN o[135]
    DIRECTION OUTPUT ;
    USE SIGNAL ;
    PORT
      LAYER M5 ;
        RECT  27.216 0 27.24 0.192 ;
    END
  END o[135]
  PIN o[136]
    DIRECTION OUTPUT ;
    USE SIGNAL ;
    PORT
      LAYER M5 ;
        RECT  27.36 0 27.384 0.192 ;
    END
  END o[136]
  PIN o[137]
    DIRECTION OUTPUT ;
    USE SIGNAL ;
    PORT
      LAYER M5 ;
        RECT  27.552 0 27.576 0.192 ;
    END
  END o[137]
  PIN o[138]
    DIRECTION OUTPUT ;
    USE SIGNAL ;
    PORT
      LAYER M5 ;
        RECT  27.696 0 27.72 0.192 ;
    END
  END o[138]
  PIN o[139]
    DIRECTION OUTPUT ;
    USE SIGNAL ;
    PORT
      LAYER M5 ;
        RECT  27.888 0 27.912 0.192 ;
    END
  END o[139]
  PIN o[13]
    DIRECTION OUTPUT ;
    USE SIGNAL ;
    PORT
      LAYER M5 ;
        RECT  6.528 0 6.552 0.192 ;
    END
  END o[13]
  PIN o[140]
    DIRECTION OUTPUT ;
    USE SIGNAL ;
    PORT
      LAYER M5 ;
        RECT  28.032 0 28.056 0.192 ;
    END
  END o[140]
  PIN o[141]
    DIRECTION OUTPUT ;
    USE SIGNAL ;
    PORT
      LAYER M5 ;
        RECT  28.224 0 28.248 0.192 ;
    END
  END o[141]
  PIN o[142]
    DIRECTION OUTPUT ;
    USE SIGNAL ;
    PORT
      LAYER M5 ;
        RECT  28.416 0 28.44 0.192 ;
    END
  END o[142]
  PIN o[143]
    DIRECTION OUTPUT ;
    USE SIGNAL ;
    PORT
      LAYER M5 ;
        RECT  28.56 0 28.584 0.192 ;
    END
  END o[143]
  PIN o[144]
    DIRECTION OUTPUT ;
    USE SIGNAL ;
    PORT
      LAYER M5 ;
        RECT  28.752 0 28.776 0.192 ;
    END
  END o[144]
  PIN o[145]
    DIRECTION OUTPUT ;
    USE SIGNAL ;
    PORT
      LAYER M5 ;
        RECT  28.896 0 28.92 0.192 ;
    END
  END o[145]
  PIN o[146]
    DIRECTION OUTPUT ;
    USE SIGNAL ;
    PORT
      LAYER M5 ;
        RECT  29.088 0 29.112 0.192 ;
    END
  END o[146]
  PIN o[147]
    DIRECTION OUTPUT ;
    USE SIGNAL ;
    PORT
      LAYER M5 ;
        RECT  29.232 0 29.256 0.192 ;
    END
  END o[147]
  PIN o[148]
    DIRECTION OUTPUT ;
    USE SIGNAL ;
    PORT
      LAYER M5 ;
        RECT  29.424 0 29.448 0.192 ;
    END
  END o[148]
  PIN o[149]
    DIRECTION OUTPUT ;
    USE SIGNAL ;
    PORT
      LAYER M5 ;
        RECT  29.568 0 29.592 0.192 ;
    END
  END o[149]
  PIN o[14]
    DIRECTION OUTPUT ;
    USE SIGNAL ;
    PORT
      LAYER M5 ;
        RECT  6.672 0 6.696 0.192 ;
    END
  END o[14]
  PIN o[150]
    DIRECTION OUTPUT ;
    USE SIGNAL ;
    PORT
      LAYER M5 ;
        RECT  29.76 0 29.784 0.192 ;
    END
  END o[150]
  PIN o[151]
    DIRECTION OUTPUT ;
    USE SIGNAL ;
    PORT
      LAYER M5 ;
        RECT  29.904 0 29.928 0.192 ;
    END
  END o[151]
  PIN o[152]
    DIRECTION OUTPUT ;
    USE SIGNAL ;
    PORT
      LAYER M5 ;
        RECT  30.096 0 30.12 0.192 ;
    END
  END o[152]
  PIN o[153]
    DIRECTION OUTPUT ;
    USE SIGNAL ;
    PORT
      LAYER M5 ;
        RECT  30.24 0 30.264 0.192 ;
    END
  END o[153]
  PIN o[154]
    DIRECTION OUTPUT ;
    USE SIGNAL ;
    PORT
      LAYER M5 ;
        RECT  30.432 0 30.456 0.192 ;
    END
  END o[154]
  PIN o[155]
    DIRECTION OUTPUT ;
    USE SIGNAL ;
    PORT
      LAYER M5 ;
        RECT  30.576 0 30.6 0.192 ;
    END
  END o[155]
  PIN o[156]
    DIRECTION OUTPUT ;
    USE SIGNAL ;
    PORT
      LAYER M5 ;
        RECT  30.768 0 30.792 0.192 ;
    END
  END o[156]
  PIN o[157]
    DIRECTION OUTPUT ;
    USE SIGNAL ;
    PORT
      LAYER M5 ;
        RECT  30.96 0 30.984 0.192 ;
    END
  END o[157]
  PIN o[158]
    DIRECTION OUTPUT ;
    USE SIGNAL ;
    PORT
      LAYER M5 ;
        RECT  31.104 0 31.128 0.192 ;
    END
  END o[158]
  PIN o[159]
    DIRECTION OUTPUT ;
    USE SIGNAL ;
    PORT
      LAYER M5 ;
        RECT  31.296 0 31.32 0.192 ;
    END
  END o[159]
  PIN o[15]
    DIRECTION OUTPUT ;
    USE SIGNAL ;
    PORT
      LAYER M5 ;
        RECT  6.864 0 6.888 0.192 ;
    END
  END o[15]
  PIN o[160]
    DIRECTION OUTPUT ;
    USE SIGNAL ;
    PORT
      LAYER M5 ;
        RECT  31.44 0 31.464 0.192 ;
    END
  END o[160]
  PIN o[161]
    DIRECTION OUTPUT ;
    USE SIGNAL ;
    PORT
      LAYER M5 ;
        RECT  31.632 0 31.656 0.192 ;
    END
  END o[161]
  PIN o[162]
    DIRECTION OUTPUT ;
    USE SIGNAL ;
    PORT
      LAYER M5 ;
        RECT  31.776 0 31.8 0.192 ;
    END
  END o[162]
  PIN o[163]
    DIRECTION OUTPUT ;
    USE SIGNAL ;
    PORT
      LAYER M5 ;
        RECT  31.968 0 31.992 0.192 ;
    END
  END o[163]
  PIN o[164]
    DIRECTION OUTPUT ;
    USE SIGNAL ;
    PORT
      LAYER M5 ;
        RECT  32.112 0 32.136 0.192 ;
    END
  END o[164]
  PIN o[165]
    DIRECTION OUTPUT ;
    USE SIGNAL ;
    PORT
      LAYER M5 ;
        RECT  32.304 0 32.328 0.192 ;
    END
  END o[165]
  PIN o[166]
    DIRECTION OUTPUT ;
    USE SIGNAL ;
    PORT
      LAYER M5 ;
        RECT  32.448 0 32.472 0.192 ;
    END
  END o[166]
  PIN o[167]
    DIRECTION OUTPUT ;
    USE SIGNAL ;
    PORT
      LAYER M5 ;
        RECT  32.64 0 32.664 0.192 ;
    END
  END o[167]
  PIN o[168]
    DIRECTION OUTPUT ;
    USE SIGNAL ;
    PORT
      LAYER M5 ;
        RECT  32.784 0 32.808 0.192 ;
    END
  END o[168]
  PIN o[169]
    DIRECTION OUTPUT ;
    USE SIGNAL ;
    PORT
      LAYER M5 ;
        RECT  32.976 0 33 0.192 ;
    END
  END o[169]
  PIN o[16]
    DIRECTION OUTPUT ;
    USE SIGNAL ;
    PORT
      LAYER M5 ;
        RECT  7.008 0 7.032 0.192 ;
    END
  END o[16]
  PIN o[170]
    DIRECTION OUTPUT ;
    USE SIGNAL ;
    PORT
      LAYER M5 ;
        RECT  33.12 0 33.144 0.192 ;
    END
  END o[170]
  PIN o[171]
    DIRECTION OUTPUT ;
    USE SIGNAL ;
    PORT
      LAYER M5 ;
        RECT  33.312 0 33.336 0.192 ;
    END
  END o[171]
  PIN o[172]
    DIRECTION OUTPUT ;
    USE SIGNAL ;
    PORT
      LAYER M5 ;
        RECT  33.504 0 33.528 0.192 ;
    END
  END o[172]
  PIN o[173]
    DIRECTION OUTPUT ;
    USE SIGNAL ;
    PORT
      LAYER M5 ;
        RECT  33.648 0 33.672 0.192 ;
    END
  END o[173]
  PIN o[174]
    DIRECTION OUTPUT ;
    USE SIGNAL ;
    PORT
      LAYER M5 ;
        RECT  33.84 0 33.864 0.192 ;
    END
  END o[174]
  PIN o[175]
    DIRECTION OUTPUT ;
    USE SIGNAL ;
    PORT
      LAYER M5 ;
        RECT  33.984 0 34.008 0.192 ;
    END
  END o[175]
  PIN o[176]
    DIRECTION OUTPUT ;
    USE SIGNAL ;
    PORT
      LAYER M5 ;
        RECT  34.176 0 34.2 0.192 ;
    END
  END o[176]
  PIN o[177]
    DIRECTION OUTPUT ;
    USE SIGNAL ;
    PORT
      LAYER M5 ;
        RECT  34.32 0 34.344 0.192 ;
    END
  END o[177]
  PIN o[178]
    DIRECTION OUTPUT ;
    USE SIGNAL ;
    PORT
      LAYER M5 ;
        RECT  34.512 0 34.536 0.192 ;
    END
  END o[178]
  PIN o[179]
    DIRECTION OUTPUT ;
    USE SIGNAL ;
    PORT
      LAYER M5 ;
        RECT  34.656 0 34.68 0.192 ;
    END
  END o[179]
  PIN o[17]
    DIRECTION OUTPUT ;
    USE SIGNAL ;
    PORT
      LAYER M5 ;
        RECT  7.2 0 7.224 0.192 ;
    END
  END o[17]
  PIN o[180]
    DIRECTION OUTPUT ;
    USE SIGNAL ;
    PORT
      LAYER M5 ;
        RECT  34.848 0 34.872 0.192 ;
    END
  END o[180]
  PIN o[181]
    DIRECTION OUTPUT ;
    USE SIGNAL ;
    PORT
      LAYER M5 ;
        RECT  34.992 0 35.016 0.192 ;
    END
  END o[181]
  PIN o[182]
    DIRECTION OUTPUT ;
    USE SIGNAL ;
    PORT
      LAYER M5 ;
        RECT  35.184 0 35.208 0.192 ;
    END
  END o[182]
  PIN o[183]
    DIRECTION OUTPUT ;
    USE SIGNAL ;
    PORT
      LAYER M5 ;
        RECT  35.328 0 35.352 0.192 ;
    END
  END o[183]
  PIN o[184]
    DIRECTION OUTPUT ;
    USE SIGNAL ;
    PORT
      LAYER M5 ;
        RECT  35.52 0 35.544 0.192 ;
    END
  END o[184]
  PIN o[185]
    DIRECTION OUTPUT ;
    USE SIGNAL ;
    PORT
      LAYER M5 ;
        RECT  35.664 0 35.688 0.192 ;
    END
  END o[185]
  PIN o[186]
    DIRECTION OUTPUT ;
    USE SIGNAL ;
    PORT
      LAYER M5 ;
        RECT  35.856 0 35.88 0.192 ;
    END
  END o[186]
  PIN o[187]
    DIRECTION OUTPUT ;
    USE SIGNAL ;
    PORT
      LAYER M5 ;
        RECT  36.048 0 36.072 0.192 ;
    END
  END o[187]
  PIN o[188]
    DIRECTION OUTPUT ;
    USE SIGNAL ;
    PORT
      LAYER M5 ;
        RECT  36.192 0 36.216 0.192 ;
    END
  END o[188]
  PIN o[189]
    DIRECTION OUTPUT ;
    USE SIGNAL ;
    PORT
      LAYER M5 ;
        RECT  36.384 0 36.408 0.192 ;
    END
  END o[189]
  PIN o[18]
    DIRECTION OUTPUT ;
    USE SIGNAL ;
    PORT
      LAYER M5 ;
        RECT  7.344 0 7.368 0.192 ;
    END
  END o[18]
  PIN o[190]
    DIRECTION OUTPUT ;
    USE SIGNAL ;
    PORT
      LAYER M5 ;
        RECT  36.528 0 36.552 0.192 ;
    END
  END o[190]
  PIN o[191]
    DIRECTION OUTPUT ;
    USE SIGNAL ;
    PORT
      LAYER M5 ;
        RECT  36.72 0 36.744 0.192 ;
    END
  END o[191]
  PIN o[192]
    DIRECTION OUTPUT ;
    USE SIGNAL ;
    PORT
      LAYER M5 ;
        RECT  36.864 0 36.888 0.192 ;
    END
  END o[192]
  PIN o[193]
    DIRECTION OUTPUT ;
    USE SIGNAL ;
    PORT
      LAYER M5 ;
        RECT  37.056 0 37.08 0.192 ;
    END
  END o[193]
  PIN o[194]
    DIRECTION OUTPUT ;
    USE SIGNAL ;
    PORT
      LAYER M5 ;
        RECT  37.2 0 37.224 0.192 ;
    END
  END o[194]
  PIN o[195]
    DIRECTION OUTPUT ;
    USE SIGNAL ;
    PORT
      LAYER M5 ;
        RECT  37.392 0 37.416 0.192 ;
    END
  END o[195]
  PIN o[196]
    DIRECTION OUTPUT ;
    USE SIGNAL ;
    PORT
      LAYER M5 ;
        RECT  37.536 0 37.56 0.192 ;
    END
  END o[196]
  PIN o[197]
    DIRECTION OUTPUT ;
    USE SIGNAL ;
    PORT
      LAYER M5 ;
        RECT  37.728 0 37.752 0.192 ;
    END
  END o[197]
  PIN o[198]
    DIRECTION OUTPUT ;
    USE SIGNAL ;
    PORT
      LAYER M5 ;
        RECT  37.872 0 37.896 0.192 ;
    END
  END o[198]
  PIN o[199]
    DIRECTION OUTPUT ;
    USE SIGNAL ;
    PORT
      LAYER M5 ;
        RECT  38.064 0 38.088 0.192 ;
    END
  END o[199]
  PIN o[19]
    DIRECTION OUTPUT ;
    USE SIGNAL ;
    PORT
      LAYER M5 ;
        RECT  7.536 0 7.56 0.192 ;
    END
  END o[19]
  PIN o[1]
    DIRECTION OUTPUT ;
    USE SIGNAL ;
    PORT
      LAYER M5 ;
        RECT  4.464 0 4.488 0.192 ;
    END
  END o[1]
  PIN o[200]
    DIRECTION OUTPUT ;
    USE SIGNAL ;
    PORT
      LAYER M5 ;
        RECT  38.208 0 38.232 0.192 ;
    END
  END o[200]
  PIN o[201]
    DIRECTION OUTPUT ;
    USE SIGNAL ;
    PORT
      LAYER M5 ;
        RECT  38.4 0 38.424 0.192 ;
    END
  END o[201]
  PIN o[202]
    DIRECTION OUTPUT ;
    USE SIGNAL ;
    PORT
      LAYER M5 ;
        RECT  38.592 0 38.616 0.192 ;
    END
  END o[202]
  PIN o[203]
    DIRECTION OUTPUT ;
    USE SIGNAL ;
    PORT
      LAYER M5 ;
        RECT  38.736 0 38.76 0.192 ;
    END
  END o[203]
  PIN o[204]
    DIRECTION OUTPUT ;
    USE SIGNAL ;
    PORT
      LAYER M5 ;
        RECT  38.928 0 38.952 0.192 ;
    END
  END o[204]
  PIN o[205]
    DIRECTION OUTPUT ;
    USE SIGNAL ;
    PORT
      LAYER M5 ;
        RECT  39.072 0 39.096 0.192 ;
    END
  END o[205]
  PIN o[206]
    DIRECTION OUTPUT ;
    USE SIGNAL ;
    PORT
      LAYER M5 ;
        RECT  39.264 0 39.288 0.192 ;
    END
  END o[206]
  PIN o[207]
    DIRECTION OUTPUT ;
    USE SIGNAL ;
    PORT
      LAYER M5 ;
        RECT  39.408 0 39.432 0.192 ;
    END
  END o[207]
  PIN o[208]
    DIRECTION OUTPUT ;
    USE SIGNAL ;
    PORT
      LAYER M5 ;
        RECT  39.6 0 39.624 0.192 ;
    END
  END o[208]
  PIN o[209]
    DIRECTION OUTPUT ;
    USE SIGNAL ;
    PORT
      LAYER M5 ;
        RECT  39.744 0 39.768 0.192 ;
    END
  END o[209]
  PIN o[20]
    DIRECTION OUTPUT ;
    USE SIGNAL ;
    PORT
      LAYER M5 ;
        RECT  7.68 0 7.704 0.192 ;
    END
  END o[20]
  PIN o[210]
    DIRECTION OUTPUT ;
    USE SIGNAL ;
    PORT
      LAYER M5 ;
        RECT  39.936 0 39.96 0.192 ;
    END
  END o[210]
  PIN o[211]
    DIRECTION OUTPUT ;
    USE SIGNAL ;
    PORT
      LAYER M5 ;
        RECT  40.08 0 40.104 0.192 ;
    END
  END o[211]
  PIN o[212]
    DIRECTION OUTPUT ;
    USE SIGNAL ;
    PORT
      LAYER M5 ;
        RECT  40.272 0 40.296 0.192 ;
    END
  END o[212]
  PIN o[213]
    DIRECTION OUTPUT ;
    USE SIGNAL ;
    PORT
      LAYER M5 ;
        RECT  40.416 0 40.44 0.192 ;
    END
  END o[213]
  PIN o[214]
    DIRECTION OUTPUT ;
    USE SIGNAL ;
    PORT
      LAYER M5 ;
        RECT  40.608 0 40.632 0.192 ;
    END
  END o[214]
  PIN o[215]
    DIRECTION OUTPUT ;
    USE SIGNAL ;
    PORT
      LAYER M5 ;
        RECT  40.752 0 40.776 0.192 ;
    END
  END o[215]
  PIN o[216]
    DIRECTION OUTPUT ;
    USE SIGNAL ;
    PORT
      LAYER M5 ;
        RECT  40.944 0 40.968 0.192 ;
    END
  END o[216]
  PIN o[217]
    DIRECTION OUTPUT ;
    USE SIGNAL ;
    PORT
      LAYER M5 ;
        RECT  41.136 0 41.16 0.192 ;
    END
  END o[217]
  PIN o[218]
    DIRECTION OUTPUT ;
    USE SIGNAL ;
    PORT
      LAYER M5 ;
        RECT  41.28 0 41.304 0.192 ;
    END
  END o[218]
  PIN o[219]
    DIRECTION OUTPUT ;
    USE SIGNAL ;
    PORT
      LAYER M5 ;
        RECT  41.472 0 41.496 0.192 ;
    END
  END o[219]
  PIN o[21]
    DIRECTION OUTPUT ;
    USE SIGNAL ;
    PORT
      LAYER M5 ;
        RECT  7.872 0 7.896 0.192 ;
    END
  END o[21]
  PIN o[220]
    DIRECTION OUTPUT ;
    USE SIGNAL ;
    PORT
      LAYER M5 ;
        RECT  41.616 0 41.64 0.192 ;
    END
  END o[220]
  PIN o[221]
    DIRECTION OUTPUT ;
    USE SIGNAL ;
    PORT
      LAYER M5 ;
        RECT  41.808 0 41.832 0.192 ;
    END
  END o[221]
  PIN o[222]
    DIRECTION OUTPUT ;
    USE SIGNAL ;
    PORT
      LAYER M5 ;
        RECT  41.952 0 41.976 0.192 ;
    END
  END o[222]
  PIN o[223]
    DIRECTION OUTPUT ;
    USE SIGNAL ;
    PORT
      LAYER M5 ;
        RECT  42.144 0 42.168 0.192 ;
    END
  END o[223]
  PIN o[224]
    DIRECTION OUTPUT ;
    USE SIGNAL ;
    PORT
      LAYER M5 ;
        RECT  42.288 0 42.312 0.192 ;
    END
  END o[224]
  PIN o[225]
    DIRECTION OUTPUT ;
    USE SIGNAL ;
    PORT
      LAYER M5 ;
        RECT  42.48 0 42.504 0.192 ;
    END
  END o[225]
  PIN o[226]
    DIRECTION OUTPUT ;
    USE SIGNAL ;
    PORT
      LAYER M5 ;
        RECT  42.624 0 42.648 0.192 ;
    END
  END o[226]
  PIN o[227]
    DIRECTION OUTPUT ;
    USE SIGNAL ;
    PORT
      LAYER M5 ;
        RECT  42.816 0 42.84 0.192 ;
    END
  END o[227]
  PIN o[228]
    DIRECTION OUTPUT ;
    USE SIGNAL ;
    PORT
      LAYER M5 ;
        RECT  42.96 0 42.984 0.192 ;
    END
  END o[228]
  PIN o[229]
    DIRECTION OUTPUT ;
    USE SIGNAL ;
    PORT
      LAYER M5 ;
        RECT  43.152 0 43.176 0.192 ;
    END
  END o[229]
  PIN o[22]
    DIRECTION OUTPUT ;
    USE SIGNAL ;
    PORT
      LAYER M5 ;
        RECT  8.016 0 8.04 0.192 ;
    END
  END o[22]
  PIN o[230]
    DIRECTION OUTPUT ;
    USE SIGNAL ;
    PORT
      LAYER M5 ;
        RECT  43.296 0 43.32 0.192 ;
    END
  END o[230]
  PIN o[231]
    DIRECTION OUTPUT ;
    USE SIGNAL ;
    PORT
      LAYER M5 ;
        RECT  43.488 0 43.512 0.192 ;
    END
  END o[231]
  PIN o[232]
    DIRECTION OUTPUT ;
    USE SIGNAL ;
    PORT
      LAYER M5 ;
        RECT  43.68 0 43.704 0.192 ;
    END
  END o[232]
  PIN o[233]
    DIRECTION OUTPUT ;
    USE SIGNAL ;
    PORT
      LAYER M5 ;
        RECT  43.824 0 43.848 0.192 ;
    END
  END o[233]
  PIN o[234]
    DIRECTION OUTPUT ;
    USE SIGNAL ;
    PORT
      LAYER M5 ;
        RECT  44.016 0 44.04 0.192 ;
    END
  END o[234]
  PIN o[235]
    DIRECTION OUTPUT ;
    USE SIGNAL ;
    PORT
      LAYER M5 ;
        RECT  44.16 0 44.184 0.192 ;
    END
  END o[235]
  PIN o[236]
    DIRECTION OUTPUT ;
    USE SIGNAL ;
    PORT
      LAYER M5 ;
        RECT  44.352 0 44.376 0.192 ;
    END
  END o[236]
  PIN o[237]
    DIRECTION OUTPUT ;
    USE SIGNAL ;
    PORT
      LAYER M5 ;
        RECT  44.496 0 44.52 0.192 ;
    END
  END o[237]
  PIN o[238]
    DIRECTION OUTPUT ;
    USE SIGNAL ;
    PORT
      LAYER M5 ;
        RECT  44.688 0 44.712 0.192 ;
    END
  END o[238]
  PIN o[239]
    DIRECTION OUTPUT ;
    USE SIGNAL ;
    PORT
      LAYER M5 ;
        RECT  44.832 0 44.856 0.192 ;
    END
  END o[239]
  PIN o[23]
    DIRECTION OUTPUT ;
    USE SIGNAL ;
    PORT
      LAYER M5 ;
        RECT  8.208 0 8.232 0.192 ;
    END
  END o[23]
  PIN o[240]
    DIRECTION OUTPUT ;
    USE SIGNAL ;
    PORT
      LAYER M5 ;
        RECT  45.024 0 45.048 0.192 ;
    END
  END o[240]
  PIN o[241]
    DIRECTION OUTPUT ;
    USE SIGNAL ;
    PORT
      LAYER M5 ;
        RECT  45.168 0 45.192 0.192 ;
    END
  END o[241]
  PIN o[242]
    DIRECTION OUTPUT ;
    USE SIGNAL ;
    PORT
      LAYER M5 ;
        RECT  45.36 0 45.384 0.192 ;
    END
  END o[242]
  PIN o[243]
    DIRECTION OUTPUT ;
    USE SIGNAL ;
    PORT
      LAYER M5 ;
        RECT  45.504 0 45.528 0.192 ;
    END
  END o[243]
  PIN o[244]
    DIRECTION OUTPUT ;
    USE SIGNAL ;
    PORT
      LAYER M5 ;
        RECT  45.696 0 45.72 0.192 ;
    END
  END o[244]
  PIN o[245]
    DIRECTION OUTPUT ;
    USE SIGNAL ;
    PORT
      LAYER M5 ;
        RECT  45.84 0 45.864 0.192 ;
    END
  END o[245]
  PIN o[246]
    DIRECTION OUTPUT ;
    USE SIGNAL ;
    PORT
      LAYER M5 ;
        RECT  46.032 0 46.056 0.192 ;
    END
  END o[246]
  PIN o[247]
    DIRECTION OUTPUT ;
    USE SIGNAL ;
    PORT
      LAYER M5 ;
        RECT  46.224 0 46.248 0.192 ;
    END
  END o[247]
  PIN o[248]
    DIRECTION OUTPUT ;
    USE SIGNAL ;
    PORT
      LAYER M5 ;
        RECT  46.368 0 46.392 0.192 ;
    END
  END o[248]
  PIN o[249]
    DIRECTION OUTPUT ;
    USE SIGNAL ;
    PORT
      LAYER M5 ;
        RECT  46.56 0 46.584 0.192 ;
    END
  END o[249]
  PIN o[24]
    DIRECTION OUTPUT ;
    USE SIGNAL ;
    PORT
      LAYER M5 ;
        RECT  8.4 0 8.424 0.192 ;
    END
  END o[24]
  PIN o[250]
    DIRECTION OUTPUT ;
    USE SIGNAL ;
    PORT
      LAYER M5 ;
        RECT  46.704 0 46.728 0.192 ;
    END
  END o[250]
  PIN o[251]
    DIRECTION OUTPUT ;
    USE SIGNAL ;
    PORT
      LAYER M5 ;
        RECT  46.896 0 46.92 0.192 ;
    END
  END o[251]
  PIN o[252]
    DIRECTION OUTPUT ;
    USE SIGNAL ;
    PORT
      LAYER M5 ;
        RECT  47.04 0 47.064 0.192 ;
    END
  END o[252]
  PIN o[253]
    DIRECTION OUTPUT ;
    USE SIGNAL ;
    PORT
      LAYER M5 ;
        RECT  47.232 0 47.256 0.192 ;
    END
  END o[253]
  PIN o[254]
    DIRECTION OUTPUT ;
    USE SIGNAL ;
    PORT
      LAYER M5 ;
        RECT  47.376 0 47.4 0.192 ;
    END
  END o[254]
  PIN o[255]
    DIRECTION OUTPUT ;
    USE SIGNAL ;
    PORT
      LAYER M5 ;
        RECT  47.568 0 47.592 0.192 ;
    END
  END o[255]
  PIN o[256]
    DIRECTION OUTPUT ;
    USE SIGNAL ;
    PORT
      LAYER M5 ;
        RECT  47.712 0 47.736 0.192 ;
    END
  END o[256]
  PIN o[257]
    DIRECTION OUTPUT ;
    USE SIGNAL ;
    PORT
      LAYER M5 ;
        RECT  47.904 0 47.928 0.192 ;
    END
  END o[257]
  PIN o[258]
    DIRECTION OUTPUT ;
    USE SIGNAL ;
    PORT
      LAYER M5 ;
        RECT  48.048 0 48.072 0.192 ;
    END
  END o[258]
  PIN o[259]
    DIRECTION OUTPUT ;
    USE SIGNAL ;
    PORT
      LAYER M5 ;
        RECT  48.24 0 48.264 0.192 ;
    END
  END o[259]
  PIN o[25]
    DIRECTION OUTPUT ;
    USE SIGNAL ;
    PORT
      LAYER M5 ;
        RECT  8.544 0 8.568 0.192 ;
    END
  END o[25]
  PIN o[260]
    DIRECTION OUTPUT ;
    USE SIGNAL ;
    PORT
      LAYER M5 ;
        RECT  48.384 0 48.408 0.192 ;
    END
  END o[260]
  PIN o[261]
    DIRECTION OUTPUT ;
    USE SIGNAL ;
    PORT
      LAYER M5 ;
        RECT  48.576 0 48.6 0.192 ;
    END
  END o[261]
  PIN o[262]
    DIRECTION OUTPUT ;
    USE SIGNAL ;
    PORT
      LAYER M5 ;
        RECT  48.768 0 48.792 0.192 ;
    END
  END o[262]
  PIN o[263]
    DIRECTION OUTPUT ;
    USE SIGNAL ;
    PORT
      LAYER M5 ;
        RECT  48.912 0 48.936 0.192 ;
    END
  END o[263]
  PIN o[264]
    DIRECTION OUTPUT ;
    USE SIGNAL ;
    PORT
      LAYER M5 ;
        RECT  49.104 0 49.128 0.192 ;
    END
  END o[264]
  PIN o[265]
    DIRECTION OUTPUT ;
    USE SIGNAL ;
    PORT
      LAYER M5 ;
        RECT  49.248 0 49.272 0.192 ;
    END
  END o[265]
  PIN o[266]
    DIRECTION OUTPUT ;
    USE SIGNAL ;
    PORT
      LAYER M5 ;
        RECT  49.44 0 49.464 0.192 ;
    END
  END o[266]
  PIN o[267]
    DIRECTION OUTPUT ;
    USE SIGNAL ;
    PORT
      LAYER M5 ;
        RECT  49.584 0 49.608 0.192 ;
    END
  END o[267]
  PIN o[268]
    DIRECTION OUTPUT ;
    USE SIGNAL ;
    PORT
      LAYER M5 ;
        RECT  49.776 0 49.8 0.192 ;
    END
  END o[268]
  PIN o[269]
    DIRECTION OUTPUT ;
    USE SIGNAL ;
    PORT
      LAYER M5 ;
        RECT  49.92 0 49.944 0.192 ;
    END
  END o[269]
  PIN o[26]
    DIRECTION OUTPUT ;
    USE SIGNAL ;
    PORT
      LAYER M5 ;
        RECT  8.736 0 8.76 0.192 ;
    END
  END o[26]
  PIN o[270]
    DIRECTION OUTPUT ;
    USE SIGNAL ;
    PORT
      LAYER M5 ;
        RECT  50.112 0 50.136 0.192 ;
    END
  END o[270]
  PIN o[271]
    DIRECTION OUTPUT ;
    USE SIGNAL ;
    PORT
      LAYER M5 ;
        RECT  50.256 0 50.28 0.192 ;
    END
  END o[271]
  PIN o[272]
    DIRECTION OUTPUT ;
    USE SIGNAL ;
    PORT
      LAYER M5 ;
        RECT  50.448 0 50.472 0.192 ;
    END
  END o[272]
  PIN o[273]
    DIRECTION OUTPUT ;
    USE SIGNAL ;
    PORT
      LAYER M5 ;
        RECT  50.592 0 50.616 0.192 ;
    END
  END o[273]
  PIN o[274]
    DIRECTION OUTPUT ;
    USE SIGNAL ;
    PORT
      LAYER M5 ;
        RECT  50.784 0 50.808 0.192 ;
    END
  END o[274]
  PIN o[275]
    DIRECTION OUTPUT ;
    USE SIGNAL ;
    PORT
      LAYER M5 ;
        RECT  50.976 0 51 0.192 ;
    END
  END o[275]
  PIN o[276]
    DIRECTION OUTPUT ;
    USE SIGNAL ;
    PORT
      LAYER M5 ;
        RECT  51.12 0 51.144 0.192 ;
    END
  END o[276]
  PIN o[277]
    DIRECTION OUTPUT ;
    USE SIGNAL ;
    PORT
      LAYER M5 ;
        RECT  51.312 0 51.336 0.192 ;
    END
  END o[277]
  PIN o[278]
    DIRECTION OUTPUT ;
    USE SIGNAL ;
    PORT
      LAYER M5 ;
        RECT  51.456 0 51.48 0.192 ;
    END
  END o[278]
  PIN o[279]
    DIRECTION OUTPUT ;
    USE SIGNAL ;
    PORT
      LAYER M5 ;
        RECT  51.648 0 51.672 0.192 ;
    END
  END o[279]
  PIN o[27]
    DIRECTION OUTPUT ;
    USE SIGNAL ;
    PORT
      LAYER M5 ;
        RECT  8.88 0 8.904 0.192 ;
    END
  END o[27]
  PIN o[280]
    DIRECTION OUTPUT ;
    USE SIGNAL ;
    PORT
      LAYER M5 ;
        RECT  51.792 0 51.816 0.192 ;
    END
  END o[280]
  PIN o[281]
    DIRECTION OUTPUT ;
    USE SIGNAL ;
    PORT
      LAYER M5 ;
        RECT  51.984 0 52.008 0.192 ;
    END
  END o[281]
  PIN o[282]
    DIRECTION OUTPUT ;
    USE SIGNAL ;
    PORT
      LAYER M5 ;
        RECT  52.128 0 52.152 0.192 ;
    END
  END o[282]
  PIN o[283]
    DIRECTION OUTPUT ;
    USE SIGNAL ;
    PORT
      LAYER M5 ;
        RECT  52.32 0 52.344 0.192 ;
    END
  END o[283]
  PIN o[284]
    DIRECTION OUTPUT ;
    USE SIGNAL ;
    PORT
      LAYER M5 ;
        RECT  52.464 0 52.488 0.192 ;
    END
  END o[284]
  PIN o[285]
    DIRECTION OUTPUT ;
    USE SIGNAL ;
    PORT
      LAYER M5 ;
        RECT  52.656 0 52.68 0.192 ;
    END
  END o[285]
  PIN o[286]
    DIRECTION OUTPUT ;
    USE SIGNAL ;
    PORT
      LAYER M5 ;
        RECT  52.8 0 52.824 0.192 ;
    END
  END o[286]
  PIN o[287]
    DIRECTION OUTPUT ;
    USE SIGNAL ;
    PORT
      LAYER M5 ;
        RECT  52.992 0 53.016 0.192 ;
    END
  END o[287]
  PIN o[288]
    DIRECTION OUTPUT ;
    USE SIGNAL ;
    PORT
      LAYER M5 ;
        RECT  53.136 0 53.16 0.192 ;
    END
  END o[288]
  PIN o[289]
    DIRECTION OUTPUT ;
    USE SIGNAL ;
    PORT
      LAYER M5 ;
        RECT  53.328 0 53.352 0.192 ;
    END
  END o[289]
  PIN o[28]
    DIRECTION OUTPUT ;
    USE SIGNAL ;
    PORT
      LAYER M5 ;
        RECT  9.072 0 9.096 0.192 ;
    END
  END o[28]
  PIN o[290]
    DIRECTION OUTPUT ;
    USE SIGNAL ;
    PORT
      LAYER M5 ;
        RECT  53.52 0 53.544 0.192 ;
    END
  END o[290]
  PIN o[291]
    DIRECTION OUTPUT ;
    USE SIGNAL ;
    PORT
      LAYER M5 ;
        RECT  53.664 0 53.688 0.192 ;
    END
  END o[291]
  PIN o[292]
    DIRECTION OUTPUT ;
    USE SIGNAL ;
    PORT
      LAYER M5 ;
        RECT  53.856 0 53.88 0.192 ;
    END
  END o[292]
  PIN o[293]
    DIRECTION OUTPUT ;
    USE SIGNAL ;
    PORT
      LAYER M5 ;
        RECT  54 0 54.024 0.192 ;
    END
  END o[293]
  PIN o[294]
    DIRECTION OUTPUT ;
    USE SIGNAL ;
    PORT
      LAYER M5 ;
        RECT  54.192 0 54.216 0.192 ;
    END
  END o[294]
  PIN o[295]
    DIRECTION OUTPUT ;
    USE SIGNAL ;
    PORT
      LAYER M5 ;
        RECT  54.336 0 54.36 0.192 ;
    END
  END o[295]
  PIN o[296]
    DIRECTION OUTPUT ;
    USE SIGNAL ;
    PORT
      LAYER M5 ;
        RECT  54.528 0 54.552 0.192 ;
    END
  END o[296]
  PIN o[297]
    DIRECTION OUTPUT ;
    USE SIGNAL ;
    PORT
      LAYER M5 ;
        RECT  54.672 0 54.696 0.192 ;
    END
  END o[297]
  PIN o[298]
    DIRECTION OUTPUT ;
    USE SIGNAL ;
    PORT
      LAYER M5 ;
        RECT  54.864 0 54.888 0.192 ;
    END
  END o[298]
  PIN o[299]
    DIRECTION OUTPUT ;
    USE SIGNAL ;
    PORT
      LAYER M5 ;
        RECT  55.008 0 55.032 0.192 ;
    END
  END o[299]
  PIN o[29]
    DIRECTION OUTPUT ;
    USE SIGNAL ;
    PORT
      LAYER M5 ;
        RECT  9.216 0 9.24 0.192 ;
    END
  END o[29]
  PIN o[2]
    DIRECTION OUTPUT ;
    USE SIGNAL ;
    PORT
      LAYER M5 ;
        RECT  4.656 0 4.68 0.192 ;
    END
  END o[2]
  PIN o[300]
    DIRECTION OUTPUT ;
    USE SIGNAL ;
    PORT
      LAYER M5 ;
        RECT  55.2 0 55.224 0.192 ;
    END
  END o[300]
  PIN o[301]
    DIRECTION OUTPUT ;
    USE SIGNAL ;
    PORT
      LAYER M5 ;
        RECT  55.344 0 55.368 0.192 ;
    END
  END o[301]
  PIN o[302]
    DIRECTION OUTPUT ;
    USE SIGNAL ;
    PORT
      LAYER M5 ;
        RECT  55.536 0 55.56 0.192 ;
    END
  END o[302]
  PIN o[303]
    DIRECTION OUTPUT ;
    USE SIGNAL ;
    PORT
      LAYER M5 ;
        RECT  55.68 0 55.704 0.192 ;
    END
  END o[303]
  PIN o[304]
    DIRECTION OUTPUT ;
    USE SIGNAL ;
    PORT
      LAYER M5 ;
        RECT  55.872 0 55.896 0.192 ;
    END
  END o[304]
  PIN o[305]
    DIRECTION OUTPUT ;
    USE SIGNAL ;
    PORT
      LAYER M5 ;
        RECT  56.064 0 56.088 0.192 ;
    END
  END o[305]
  PIN o[306]
    DIRECTION OUTPUT ;
    USE SIGNAL ;
    PORT
      LAYER M5 ;
        RECT  56.208 0 56.232 0.192 ;
    END
  END o[306]
  PIN o[307]
    DIRECTION OUTPUT ;
    USE SIGNAL ;
    PORT
      LAYER M5 ;
        RECT  56.4 0 56.424 0.192 ;
    END
  END o[307]
  PIN o[308]
    DIRECTION OUTPUT ;
    USE SIGNAL ;
    PORT
      LAYER M5 ;
        RECT  56.544 0 56.568 0.192 ;
    END
  END o[308]
  PIN o[309]
    DIRECTION OUTPUT ;
    USE SIGNAL ;
    PORT
      LAYER M5 ;
        RECT  56.736 0 56.76 0.192 ;
    END
  END o[309]
  PIN o[30]
    DIRECTION OUTPUT ;
    USE SIGNAL ;
    PORT
      LAYER M5 ;
        RECT  9.408 0 9.432 0.192 ;
    END
  END o[30]
  PIN o[310]
    DIRECTION OUTPUT ;
    USE SIGNAL ;
    PORT
      LAYER M5 ;
        RECT  56.88 0 56.904 0.192 ;
    END
  END o[310]
  PIN o[311]
    DIRECTION OUTPUT ;
    USE SIGNAL ;
    PORT
      LAYER M5 ;
        RECT  57.072 0 57.096 0.192 ;
    END
  END o[311]
  PIN o[312]
    DIRECTION OUTPUT ;
    USE SIGNAL ;
    PORT
      LAYER M5 ;
        RECT  57.408 0 57.432 0.192 ;
    END
  END o[312]
  PIN o[313]
    DIRECTION OUTPUT ;
    USE SIGNAL ;
    PORT
      LAYER M5 ;
        RECT  57.552 0 57.576 0.192 ;
    END
  END o[313]
  PIN o[314]
    DIRECTION OUTPUT ;
    USE SIGNAL ;
    PORT
      LAYER M5 ;
        RECT  57.744 0 57.768 0.192 ;
    END
  END o[314]
  PIN o[315]
    DIRECTION OUTPUT ;
    USE SIGNAL ;
    PORT
      LAYER M5 ;
        RECT  57.888 0 57.912 0.192 ;
    END
  END o[315]
  PIN o[316]
    DIRECTION OUTPUT ;
    USE SIGNAL ;
    PORT
      LAYER M5 ;
        RECT  58.08 0 58.104 0.192 ;
    END
  END o[316]
  PIN o[317]
    DIRECTION OUTPUT ;
    USE SIGNAL ;
    PORT
      LAYER M5 ;
        RECT  58.224 0 58.248 0.192 ;
    END
  END o[317]
  PIN o[318]
    DIRECTION OUTPUT ;
    USE SIGNAL ;
    PORT
      LAYER M5 ;
        RECT  58.416 0 58.44 0.192 ;
    END
  END o[318]
  PIN o[319]
    DIRECTION OUTPUT ;
    USE SIGNAL ;
    PORT
      LAYER M5 ;
        RECT  58.608 0 58.632 0.192 ;
    END
  END o[319]
  PIN o[31]
    DIRECTION OUTPUT ;
    USE SIGNAL ;
    PORT
      LAYER M5 ;
        RECT  9.552 0 9.576 0.192 ;
    END
  END o[31]
  PIN o[320]
    DIRECTION OUTPUT ;
    USE SIGNAL ;
    PORT
      LAYER M5 ;
        RECT  58.752 0 58.776 0.192 ;
    END
  END o[320]
  PIN o[321]
    DIRECTION OUTPUT ;
    USE SIGNAL ;
    PORT
      LAYER M5 ;
        RECT  58.944 0 58.968 0.192 ;
    END
  END o[321]
  PIN o[322]
    DIRECTION OUTPUT ;
    USE SIGNAL ;
    PORT
      LAYER M5 ;
        RECT  59.088 0 59.112 0.192 ;
    END
  END o[322]
  PIN o[323]
    DIRECTION OUTPUT ;
    USE SIGNAL ;
    PORT
      LAYER M5 ;
        RECT  59.28 0 59.304 0.192 ;
    END
  END o[323]
  PIN o[324]
    DIRECTION OUTPUT ;
    USE SIGNAL ;
    PORT
      LAYER M5 ;
        RECT  59.424 0 59.448 0.192 ;
    END
  END o[324]
  PIN o[325]
    DIRECTION OUTPUT ;
    USE SIGNAL ;
    PORT
      LAYER M5 ;
        RECT  59.616 0 59.64 0.192 ;
    END
  END o[325]
  PIN o[326]
    DIRECTION OUTPUT ;
    USE SIGNAL ;
    PORT
      LAYER M5 ;
        RECT  59.76 0 59.784 0.192 ;
    END
  END o[326]
  PIN o[327]
    DIRECTION OUTPUT ;
    USE SIGNAL ;
    PORT
      LAYER M5 ;
        RECT  59.952 0 59.976 0.192 ;
    END
  END o[327]
  PIN o[328]
    DIRECTION OUTPUT ;
    USE SIGNAL ;
    PORT
      LAYER M5 ;
        RECT  60.096 0 60.12 0.192 ;
    END
  END o[328]
  PIN o[329]
    DIRECTION OUTPUT ;
    USE SIGNAL ;
    PORT
      LAYER M5 ;
        RECT  60.288 0 60.312 0.192 ;
    END
  END o[329]
  PIN o[32]
    DIRECTION OUTPUT ;
    USE SIGNAL ;
    PORT
      LAYER M5 ;
        RECT  9.744 0 9.768 0.192 ;
    END
  END o[32]
  PIN o[330]
    DIRECTION OUTPUT ;
    USE SIGNAL ;
    PORT
      LAYER M5 ;
        RECT  60.432 0 60.456 0.192 ;
    END
  END o[330]
  PIN o[331]
    DIRECTION OUTPUT ;
    USE SIGNAL ;
    PORT
      LAYER M5 ;
        RECT  60.624 0 60.648 0.192 ;
    END
  END o[331]
  PIN o[332]
    DIRECTION OUTPUT ;
    USE SIGNAL ;
    PORT
      LAYER M5 ;
        RECT  60.768 0 60.792 0.192 ;
    END
  END o[332]
  PIN o[333]
    DIRECTION OUTPUT ;
    USE SIGNAL ;
    PORT
      LAYER M5 ;
        RECT  60.96 0 60.984 0.192 ;
    END
  END o[333]
  PIN o[334]
    DIRECTION OUTPUT ;
    USE SIGNAL ;
    PORT
      LAYER M5 ;
        RECT  61.152 0 61.176 0.192 ;
    END
  END o[334]
  PIN o[335]
    DIRECTION OUTPUT ;
    USE SIGNAL ;
    PORT
      LAYER M5 ;
        RECT  61.296 0 61.32 0.192 ;
    END
  END o[335]
  PIN o[336]
    DIRECTION OUTPUT ;
    USE SIGNAL ;
    PORT
      LAYER M5 ;
        RECT  61.488 0 61.512 0.192 ;
    END
  END o[336]
  PIN o[337]
    DIRECTION OUTPUT ;
    USE SIGNAL ;
    PORT
      LAYER M5 ;
        RECT  61.632 0 61.656 0.192 ;
    END
  END o[337]
  PIN o[338]
    DIRECTION OUTPUT ;
    USE SIGNAL ;
    PORT
      LAYER M5 ;
        RECT  61.824 0 61.848 0.192 ;
    END
  END o[338]
  PIN o[339]
    DIRECTION OUTPUT ;
    USE SIGNAL ;
    PORT
      LAYER M5 ;
        RECT  61.968 0 61.992 0.192 ;
    END
  END o[339]
  PIN o[33]
    DIRECTION OUTPUT ;
    USE SIGNAL ;
    PORT
      LAYER M5 ;
        RECT  9.888 0 9.912 0.192 ;
    END
  END o[33]
  PIN o[340]
    DIRECTION OUTPUT ;
    USE SIGNAL ;
    PORT
      LAYER M5 ;
        RECT  62.16 0 62.184 0.192 ;
    END
  END o[340]
  PIN o[341]
    DIRECTION OUTPUT ;
    USE SIGNAL ;
    PORT
      LAYER M5 ;
        RECT  62.304 0 62.328 0.192 ;
    END
  END o[341]
  PIN o[342]
    DIRECTION OUTPUT ;
    USE SIGNAL ;
    PORT
      LAYER M5 ;
        RECT  62.496 0 62.52 0.192 ;
    END
  END o[342]
  PIN o[343]
    DIRECTION OUTPUT ;
    USE SIGNAL ;
    PORT
      LAYER M5 ;
        RECT  62.64 0 62.664 0.192 ;
    END
  END o[343]
  PIN o[344]
    DIRECTION OUTPUT ;
    USE SIGNAL ;
    PORT
      LAYER M5 ;
        RECT  62.832 0 62.856 0.192 ;
    END
  END o[344]
  PIN o[345]
    DIRECTION OUTPUT ;
    USE SIGNAL ;
    PORT
      LAYER M5 ;
        RECT  62.976 0 63 0.192 ;
    END
  END o[345]
  PIN o[346]
    DIRECTION OUTPUT ;
    USE SIGNAL ;
    PORT
      LAYER M5 ;
        RECT  63.168 0 63.192 0.192 ;
    END
  END o[346]
  PIN o[347]
    DIRECTION OUTPUT ;
    USE SIGNAL ;
    PORT
      LAYER M5 ;
        RECT  63.312 0 63.336 0.192 ;
    END
  END o[347]
  PIN o[348]
    DIRECTION OUTPUT ;
    USE SIGNAL ;
    PORT
      LAYER M5 ;
        RECT  63.504 0 63.528 0.192 ;
    END
  END o[348]
  PIN o[349]
    DIRECTION OUTPUT ;
    USE SIGNAL ;
    PORT
      LAYER M5 ;
        RECT  63.696 0 63.72 0.192 ;
    END
  END o[349]
  PIN o[34]
    DIRECTION OUTPUT ;
    USE SIGNAL ;
    PORT
      LAYER M5 ;
        RECT  10.08 0 10.104 0.192 ;
    END
  END o[34]
  PIN o[350]
    DIRECTION OUTPUT ;
    USE SIGNAL ;
    PORT
      LAYER M5 ;
        RECT  63.84 0 63.864 0.192 ;
    END
  END o[350]
  PIN o[351]
    DIRECTION OUTPUT ;
    USE SIGNAL ;
    PORT
      LAYER M5 ;
        RECT  64.032 0 64.056 0.192 ;
    END
  END o[351]
  PIN o[352]
    DIRECTION OUTPUT ;
    USE SIGNAL ;
    PORT
      LAYER M5 ;
        RECT  64.176 0 64.2 0.192 ;
    END
  END o[352]
  PIN o[353]
    DIRECTION OUTPUT ;
    USE SIGNAL ;
    PORT
      LAYER M5 ;
        RECT  64.368 0 64.392 0.192 ;
    END
  END o[353]
  PIN o[354]
    DIRECTION OUTPUT ;
    USE SIGNAL ;
    PORT
      LAYER M5 ;
        RECT  64.512 0 64.536 0.192 ;
    END
  END o[354]
  PIN o[355]
    DIRECTION OUTPUT ;
    USE SIGNAL ;
    PORT
      LAYER M5 ;
        RECT  64.704 0 64.728 0.192 ;
    END
  END o[355]
  PIN o[356]
    DIRECTION OUTPUT ;
    USE SIGNAL ;
    PORT
      LAYER M5 ;
        RECT  64.848 0 64.872 0.192 ;
    END
  END o[356]
  PIN o[357]
    DIRECTION OUTPUT ;
    USE SIGNAL ;
    PORT
      LAYER M5 ;
        RECT  65.04 0 65.064 0.192 ;
    END
  END o[357]
  PIN o[358]
    DIRECTION OUTPUT ;
    USE SIGNAL ;
    PORT
      LAYER M5 ;
        RECT  65.184 0 65.208 0.192 ;
    END
  END o[358]
  PIN o[359]
    DIRECTION OUTPUT ;
    USE SIGNAL ;
    PORT
      LAYER M5 ;
        RECT  65.376 0 65.4 0.192 ;
    END
  END o[359]
  PIN o[35]
    DIRECTION OUTPUT ;
    USE SIGNAL ;
    PORT
      LAYER M5 ;
        RECT  10.224 0 10.248 0.192 ;
    END
  END o[35]
  PIN o[360]
    DIRECTION OUTPUT ;
    USE SIGNAL ;
    PORT
      LAYER M5 ;
        RECT  65.52 0 65.544 0.192 ;
    END
  END o[360]
  PIN o[361]
    DIRECTION OUTPUT ;
    USE SIGNAL ;
    PORT
      LAYER M5 ;
        RECT  65.712 0 65.736 0.192 ;
    END
  END o[361]
  PIN o[362]
    DIRECTION OUTPUT ;
    USE SIGNAL ;
    PORT
      LAYER M5 ;
        RECT  65.856 0 65.88 0.192 ;
    END
  END o[362]
  PIN o[363]
    DIRECTION OUTPUT ;
    USE SIGNAL ;
    PORT
      LAYER M5 ;
        RECT  66.048 0 66.072 0.192 ;
    END
  END o[363]
  PIN o[364]
    DIRECTION OUTPUT ;
    USE SIGNAL ;
    PORT
      LAYER M5 ;
        RECT  66.24 0 66.264 0.192 ;
    END
  END o[364]
  PIN o[365]
    DIRECTION OUTPUT ;
    USE SIGNAL ;
    PORT
      LAYER M5 ;
        RECT  66.384 0 66.408 0.192 ;
    END
  END o[365]
  PIN o[366]
    DIRECTION OUTPUT ;
    USE SIGNAL ;
    PORT
      LAYER M5 ;
        RECT  66.576 0 66.6 0.192 ;
    END
  END o[366]
  PIN o[367]
    DIRECTION OUTPUT ;
    USE SIGNAL ;
    PORT
      LAYER M5 ;
        RECT  66.72 0 66.744 0.192 ;
    END
  END o[367]
  PIN o[368]
    DIRECTION OUTPUT ;
    USE SIGNAL ;
    PORT
      LAYER M5 ;
        RECT  66.912 0 66.936 0.192 ;
    END
  END o[368]
  PIN o[369]
    DIRECTION OUTPUT ;
    USE SIGNAL ;
    PORT
      LAYER M5 ;
        RECT  67.056 0 67.08 0.192 ;
    END
  END o[369]
  PIN o[36]
    DIRECTION OUTPUT ;
    USE SIGNAL ;
    PORT
      LAYER M5 ;
        RECT  10.416 0 10.44 0.192 ;
    END
  END o[36]
  PIN o[370]
    DIRECTION OUTPUT ;
    USE SIGNAL ;
    PORT
      LAYER M5 ;
        RECT  67.248 0 67.272 0.192 ;
    END
  END o[370]
  PIN o[371]
    DIRECTION OUTPUT ;
    USE SIGNAL ;
    PORT
      LAYER M5 ;
        RECT  67.392 0 67.416 0.192 ;
    END
  END o[371]
  PIN o[372]
    DIRECTION OUTPUT ;
    USE SIGNAL ;
    PORT
      LAYER M5 ;
        RECT  67.584 0 67.608 0.192 ;
    END
  END o[372]
  PIN o[373]
    DIRECTION OUTPUT ;
    USE SIGNAL ;
    PORT
      LAYER M5 ;
        RECT  67.728 0 67.752 0.192 ;
    END
  END o[373]
  PIN o[374]
    DIRECTION OUTPUT ;
    USE SIGNAL ;
    PORT
      LAYER M5 ;
        RECT  67.92 0 67.944 0.192 ;
    END
  END o[374]
  PIN o[375]
    DIRECTION OUTPUT ;
    USE SIGNAL ;
    PORT
      LAYER M5 ;
        RECT  68.064 0 68.088 0.192 ;
    END
  END o[375]
  PIN o[376]
    DIRECTION OUTPUT ;
    USE SIGNAL ;
    PORT
      LAYER M5 ;
        RECT  68.256 0 68.28 0.192 ;
    END
  END o[376]
  PIN o[377]
    DIRECTION OUTPUT ;
    USE SIGNAL ;
    PORT
      LAYER M5 ;
        RECT  68.4 0 68.424 0.192 ;
    END
  END o[377]
  PIN o[378]
    DIRECTION OUTPUT ;
    USE SIGNAL ;
    PORT
      LAYER M5 ;
        RECT  68.592 0 68.616 0.192 ;
    END
  END o[378]
  PIN o[379]
    DIRECTION OUTPUT ;
    USE SIGNAL ;
    PORT
      LAYER M5 ;
        RECT  68.784 0 68.808 0.192 ;
    END
  END o[379]
  PIN o[37]
    DIRECTION OUTPUT ;
    USE SIGNAL ;
    PORT
      LAYER M5 ;
        RECT  10.56 0 10.584 0.192 ;
    END
  END o[37]
  PIN o[380]
    DIRECTION OUTPUT ;
    USE SIGNAL ;
    PORT
      LAYER M5 ;
        RECT  68.928 0 68.952 0.192 ;
    END
  END o[380]
  PIN o[381]
    DIRECTION OUTPUT ;
    USE SIGNAL ;
    PORT
      LAYER M5 ;
        RECT  69.12 0 69.144 0.192 ;
    END
  END o[381]
  PIN o[382]
    DIRECTION OUTPUT ;
    USE SIGNAL ;
    PORT
      LAYER M5 ;
        RECT  69.264 0 69.288 0.192 ;
    END
  END o[382]
  PIN o[383]
    DIRECTION OUTPUT ;
    USE SIGNAL ;
    PORT
      LAYER M5 ;
        RECT  69.456 0 69.48 0.192 ;
    END
  END o[383]
  PIN o[384]
    DIRECTION OUTPUT ;
    USE SIGNAL ;
    PORT
      LAYER M5 ;
        RECT  69.6 0 69.624 0.192 ;
    END
  END o[384]
  PIN o[385]
    DIRECTION OUTPUT ;
    USE SIGNAL ;
    PORT
      LAYER M5 ;
        RECT  69.792 0 69.816 0.192 ;
    END
  END o[385]
  PIN o[386]
    DIRECTION OUTPUT ;
    USE SIGNAL ;
    PORT
      LAYER M5 ;
        RECT  69.936 0 69.96 0.192 ;
    END
  END o[386]
  PIN o[387]
    DIRECTION OUTPUT ;
    USE SIGNAL ;
    PORT
      LAYER M5 ;
        RECT  70.128 0 70.152 0.192 ;
    END
  END o[387]
  PIN o[388]
    DIRECTION OUTPUT ;
    USE SIGNAL ;
    PORT
      LAYER M5 ;
        RECT  70.272 0 70.296 0.192 ;
    END
  END o[388]
  PIN o[389]
    DIRECTION OUTPUT ;
    USE SIGNAL ;
    PORT
      LAYER M5 ;
        RECT  70.464 0 70.488 0.192 ;
    END
  END o[389]
  PIN o[38]
    DIRECTION OUTPUT ;
    USE SIGNAL ;
    PORT
      LAYER M5 ;
        RECT  10.752 0 10.776 0.192 ;
    END
  END o[38]
  PIN o[390]
    DIRECTION OUTPUT ;
    USE SIGNAL ;
    PORT
      LAYER M5 ;
        RECT  70.608 0 70.632 0.192 ;
    END
  END o[390]
  PIN o[391]
    DIRECTION OUTPUT ;
    USE SIGNAL ;
    PORT
      LAYER M5 ;
        RECT  70.8 0 70.824 0.192 ;
    END
  END o[391]
  PIN o[392]
    DIRECTION OUTPUT ;
    USE SIGNAL ;
    PORT
      LAYER M5 ;
        RECT  70.944 0 70.968 0.192 ;
    END
  END o[392]
  PIN o[393]
    DIRECTION OUTPUT ;
    USE SIGNAL ;
    PORT
      LAYER M5 ;
        RECT  71.136 0 71.16 0.192 ;
    END
  END o[393]
  PIN o[394]
    DIRECTION OUTPUT ;
    USE SIGNAL ;
    PORT
      LAYER M5 ;
        RECT  71.328 0 71.352 0.192 ;
    END
  END o[394]
  PIN o[395]
    DIRECTION OUTPUT ;
    USE SIGNAL ;
    PORT
      LAYER M5 ;
        RECT  71.472 0 71.496 0.192 ;
    END
  END o[395]
  PIN o[396]
    DIRECTION OUTPUT ;
    USE SIGNAL ;
    PORT
      LAYER M5 ;
        RECT  71.664 0 71.688 0.192 ;
    END
  END o[396]
  PIN o[397]
    DIRECTION OUTPUT ;
    USE SIGNAL ;
    PORT
      LAYER M5 ;
        RECT  71.808 0 71.832 0.192 ;
    END
  END o[397]
  PIN o[398]
    DIRECTION OUTPUT ;
    USE SIGNAL ;
    PORT
      LAYER M5 ;
        RECT  72 0 72.024 0.192 ;
    END
  END o[398]
  PIN o[399]
    DIRECTION OUTPUT ;
    USE SIGNAL ;
    PORT
      LAYER M5 ;
        RECT  72.144 0 72.168 0.192 ;
    END
  END o[399]
  PIN o[39]
    DIRECTION OUTPUT ;
    USE SIGNAL ;
    PORT
      LAYER M5 ;
        RECT  10.944 0 10.968 0.192 ;
    END
  END o[39]
  PIN o[3]
    DIRECTION OUTPUT ;
    USE SIGNAL ;
    PORT
      LAYER M5 ;
        RECT  4.8 0 4.824 0.192 ;
    END
  END o[3]
  PIN o[400]
    DIRECTION OUTPUT ;
    USE SIGNAL ;
    PORT
      LAYER M5 ;
        RECT  72.336 0 72.36 0.192 ;
    END
  END o[400]
  PIN o[401]
    DIRECTION OUTPUT ;
    USE SIGNAL ;
    PORT
      LAYER M5 ;
        RECT  72.48 0 72.504 0.192 ;
    END
  END o[401]
  PIN o[402]
    DIRECTION OUTPUT ;
    USE SIGNAL ;
    PORT
      LAYER M5 ;
        RECT  72.672 0 72.696 0.192 ;
    END
  END o[402]
  PIN o[403]
    DIRECTION OUTPUT ;
    USE SIGNAL ;
    PORT
      LAYER M5 ;
        RECT  72.816 0 72.84 0.192 ;
    END
  END o[403]
  PIN o[404]
    DIRECTION OUTPUT ;
    USE SIGNAL ;
    PORT
      LAYER M5 ;
        RECT  73.008 0 73.032 0.192 ;
    END
  END o[404]
  PIN o[405]
    DIRECTION OUTPUT ;
    USE SIGNAL ;
    PORT
      LAYER M5 ;
        RECT  73.152 0 73.176 0.192 ;
    END
  END o[405]
  PIN o[406]
    DIRECTION OUTPUT ;
    USE SIGNAL ;
    PORT
      LAYER M5 ;
        RECT  73.344 0 73.368 0.192 ;
    END
  END o[406]
  PIN o[407]
    DIRECTION OUTPUT ;
    USE SIGNAL ;
    PORT
      LAYER M5 ;
        RECT  73.488 0 73.512 0.192 ;
    END
  END o[407]
  PIN o[408]
    DIRECTION OUTPUT ;
    USE SIGNAL ;
    PORT
      LAYER M5 ;
        RECT  73.68 0 73.704 0.192 ;
    END
  END o[408]
  PIN o[409]
    DIRECTION OUTPUT ;
    USE SIGNAL ;
    PORT
      LAYER M5 ;
        RECT  73.872 0 73.896 0.192 ;
    END
  END o[409]
  PIN o[40]
    DIRECTION OUTPUT ;
    USE SIGNAL ;
    PORT
      LAYER M5 ;
        RECT  11.088 0 11.112 0.192 ;
    END
  END o[40]
  PIN o[410]
    DIRECTION OUTPUT ;
    USE SIGNAL ;
    PORT
      LAYER M5 ;
        RECT  74.016 0 74.04 0.192 ;
    END
  END o[410]
  PIN o[411]
    DIRECTION OUTPUT ;
    USE SIGNAL ;
    PORT
      LAYER M5 ;
        RECT  74.208 0 74.232 0.192 ;
    END
  END o[411]
  PIN o[412]
    DIRECTION OUTPUT ;
    USE SIGNAL ;
    PORT
      LAYER M5 ;
        RECT  74.352 0 74.376 0.192 ;
    END
  END o[412]
  PIN o[413]
    DIRECTION OUTPUT ;
    USE SIGNAL ;
    PORT
      LAYER M5 ;
        RECT  74.544 0 74.568 0.192 ;
    END
  END o[413]
  PIN o[414]
    DIRECTION OUTPUT ;
    USE SIGNAL ;
    PORT
      LAYER M5 ;
        RECT  74.688 0 74.712 0.192 ;
    END
  END o[414]
  PIN o[415]
    DIRECTION OUTPUT ;
    USE SIGNAL ;
    PORT
      LAYER M5 ;
        RECT  74.88 0 74.904 0.192 ;
    END
  END o[415]
  PIN o[416]
    DIRECTION OUTPUT ;
    USE SIGNAL ;
    PORT
      LAYER M5 ;
        RECT  75.024 0 75.048 0.192 ;
    END
  END o[416]
  PIN o[417]
    DIRECTION OUTPUT ;
    USE SIGNAL ;
    PORT
      LAYER M5 ;
        RECT  75.216 0 75.24 0.192 ;
    END
  END o[417]
  PIN o[418]
    DIRECTION OUTPUT ;
    USE SIGNAL ;
    PORT
      LAYER M5 ;
        RECT  75.36 0 75.384 0.192 ;
    END
  END o[418]
  PIN o[419]
    DIRECTION OUTPUT ;
    USE SIGNAL ;
    PORT
      LAYER M5 ;
        RECT  75.552 0 75.576 0.192 ;
    END
  END o[419]
  PIN o[41]
    DIRECTION OUTPUT ;
    USE SIGNAL ;
    PORT
      LAYER M5 ;
        RECT  11.28 0 11.304 0.192 ;
    END
  END o[41]
  PIN o[420]
    DIRECTION OUTPUT ;
    USE SIGNAL ;
    PORT
      LAYER M5 ;
        RECT  75.696 0 75.72 0.192 ;
    END
  END o[420]
  PIN o[421]
    DIRECTION OUTPUT ;
    USE SIGNAL ;
    PORT
      LAYER M5 ;
        RECT  75.888 0 75.912 0.192 ;
    END
  END o[421]
  PIN o[422]
    DIRECTION OUTPUT ;
    USE SIGNAL ;
    PORT
      LAYER M5 ;
        RECT  76.032 0 76.056 0.192 ;
    END
  END o[422]
  PIN o[423]
    DIRECTION OUTPUT ;
    USE SIGNAL ;
    PORT
      LAYER M5 ;
        RECT  76.224 0 76.248 0.192 ;
    END
  END o[423]
  PIN o[424]
    DIRECTION OUTPUT ;
    USE SIGNAL ;
    PORT
      LAYER M5 ;
        RECT  76.416 0 76.44 0.192 ;
    END
  END o[424]
  PIN o[425]
    DIRECTION OUTPUT ;
    USE SIGNAL ;
    PORT
      LAYER M5 ;
        RECT  76.56 0 76.584 0.192 ;
    END
  END o[425]
  PIN o[426]
    DIRECTION OUTPUT ;
    USE SIGNAL ;
    PORT
      LAYER M5 ;
        RECT  76.752 0 76.776 0.192 ;
    END
  END o[426]
  PIN o[427]
    DIRECTION OUTPUT ;
    USE SIGNAL ;
    PORT
      LAYER M5 ;
        RECT  76.896 0 76.92 0.192 ;
    END
  END o[427]
  PIN o[428]
    DIRECTION OUTPUT ;
    USE SIGNAL ;
    PORT
      LAYER M5 ;
        RECT  77.088 0 77.112 0.192 ;
    END
  END o[428]
  PIN o[429]
    DIRECTION OUTPUT ;
    USE SIGNAL ;
    PORT
      LAYER M5 ;
        RECT  77.232 0 77.256 0.192 ;
    END
  END o[429]
  PIN o[42]
    DIRECTION OUTPUT ;
    USE SIGNAL ;
    PORT
      LAYER M5 ;
        RECT  11.424 0 11.448 0.192 ;
    END
  END o[42]
  PIN o[430]
    DIRECTION OUTPUT ;
    USE SIGNAL ;
    PORT
      LAYER M5 ;
        RECT  77.424 0 77.448 0.192 ;
    END
  END o[430]
  PIN o[431]
    DIRECTION OUTPUT ;
    USE SIGNAL ;
    PORT
      LAYER M5 ;
        RECT  77.568 0 77.592 0.192 ;
    END
  END o[431]
  PIN o[432]
    DIRECTION OUTPUT ;
    USE SIGNAL ;
    PORT
      LAYER M5 ;
        RECT  77.76 0 77.784 0.192 ;
    END
  END o[432]
  PIN o[433]
    DIRECTION OUTPUT ;
    USE SIGNAL ;
    PORT
      LAYER M5 ;
        RECT  77.904 0 77.928 0.192 ;
    END
  END o[433]
  PIN o[434]
    DIRECTION OUTPUT ;
    USE SIGNAL ;
    PORT
      LAYER M5 ;
        RECT  78.096 0 78.12 0.192 ;
    END
  END o[434]
  PIN o[435]
    DIRECTION OUTPUT ;
    USE SIGNAL ;
    PORT
      LAYER M5 ;
        RECT  78.24 0 78.264 0.192 ;
    END
  END o[435]
  PIN o[436]
    DIRECTION OUTPUT ;
    USE SIGNAL ;
    PORT
      LAYER M5 ;
        RECT  78.432 0 78.456 0.192 ;
    END
  END o[436]
  PIN o[437]
    DIRECTION OUTPUT ;
    USE SIGNAL ;
    PORT
      LAYER M5 ;
        RECT  78.576 0 78.6 0.192 ;
    END
  END o[437]
  PIN o[438]
    DIRECTION OUTPUT ;
    USE SIGNAL ;
    PORT
      LAYER M5 ;
        RECT  78.768 0 78.792 0.192 ;
    END
  END o[438]
  PIN o[439]
    DIRECTION OUTPUT ;
    USE SIGNAL ;
    PORT
      LAYER M5 ;
        RECT  78.96 0 78.984 0.192 ;
    END
  END o[439]
  PIN o[43]
    DIRECTION OUTPUT ;
    USE SIGNAL ;
    PORT
      LAYER M5 ;
        RECT  11.616 0 11.64 0.192 ;
    END
  END o[43]
  PIN o[440]
    DIRECTION OUTPUT ;
    USE SIGNAL ;
    PORT
      LAYER M5 ;
        RECT  79.104 0 79.128 0.192 ;
    END
  END o[440]
  PIN o[441]
    DIRECTION OUTPUT ;
    USE SIGNAL ;
    PORT
      LAYER M5 ;
        RECT  79.296 0 79.32 0.192 ;
    END
  END o[441]
  PIN o[442]
    DIRECTION OUTPUT ;
    USE SIGNAL ;
    PORT
      LAYER M5 ;
        RECT  79.44 0 79.464 0.192 ;
    END
  END o[442]
  PIN o[443]
    DIRECTION OUTPUT ;
    USE SIGNAL ;
    PORT
      LAYER M5 ;
        RECT  79.632 0 79.656 0.192 ;
    END
  END o[443]
  PIN o[444]
    DIRECTION OUTPUT ;
    USE SIGNAL ;
    PORT
      LAYER M5 ;
        RECT  79.776 0 79.8 0.192 ;
    END
  END o[444]
  PIN o[445]
    DIRECTION OUTPUT ;
    USE SIGNAL ;
    PORT
      LAYER M5 ;
        RECT  79.968 0 79.992 0.192 ;
    END
  END o[445]
  PIN o[446]
    DIRECTION OUTPUT ;
    USE SIGNAL ;
    PORT
      LAYER M5 ;
        RECT  80.112 0 80.136 0.192 ;
    END
  END o[446]
  PIN o[447]
    DIRECTION OUTPUT ;
    USE SIGNAL ;
    PORT
      LAYER M5 ;
        RECT  80.304 0 80.328 0.192 ;
    END
  END o[447]
  PIN o[448]
    DIRECTION OUTPUT ;
    USE SIGNAL ;
    PORT
      LAYER M5 ;
        RECT  80.448 0 80.472 0.192 ;
    END
  END o[448]
  PIN o[449]
    DIRECTION OUTPUT ;
    USE SIGNAL ;
    PORT
      LAYER M5 ;
        RECT  80.64 0 80.664 0.192 ;
    END
  END o[449]
  PIN o[44]
    DIRECTION OUTPUT ;
    USE SIGNAL ;
    PORT
      LAYER M5 ;
        RECT  11.76 0 11.784 0.192 ;
    END
  END o[44]
  PIN o[450]
    DIRECTION OUTPUT ;
    USE SIGNAL ;
    PORT
      LAYER M5 ;
        RECT  80.784 0 80.808 0.192 ;
    END
  END o[450]
  PIN o[451]
    DIRECTION OUTPUT ;
    USE SIGNAL ;
    PORT
      LAYER M5 ;
        RECT  80.976 0 81 0.192 ;
    END
  END o[451]
  PIN o[452]
    DIRECTION OUTPUT ;
    USE SIGNAL ;
    PORT
      LAYER M5 ;
        RECT  81.12 0 81.144 0.192 ;
    END
  END o[452]
  PIN o[453]
    DIRECTION OUTPUT ;
    USE SIGNAL ;
    PORT
      LAYER M5 ;
        RECT  81.312 0 81.336 0.192 ;
    END
  END o[453]
  PIN o[454]
    DIRECTION OUTPUT ;
    USE SIGNAL ;
    PORT
      LAYER M5 ;
        RECT  81.504 0 81.528 0.192 ;
    END
  END o[454]
  PIN o[455]
    DIRECTION OUTPUT ;
    USE SIGNAL ;
    PORT
      LAYER M5 ;
        RECT  81.648 0 81.672 0.192 ;
    END
  END o[455]
  PIN o[456]
    DIRECTION OUTPUT ;
    USE SIGNAL ;
    PORT
      LAYER M5 ;
        RECT  81.84 0 81.864 0.192 ;
    END
  END o[456]
  PIN o[457]
    DIRECTION OUTPUT ;
    USE SIGNAL ;
    PORT
      LAYER M5 ;
        RECT  81.984 0 82.008 0.192 ;
    END
  END o[457]
  PIN o[458]
    DIRECTION OUTPUT ;
    USE SIGNAL ;
    PORT
      LAYER M5 ;
        RECT  82.176 0 82.2 0.192 ;
    END
  END o[458]
  PIN o[459]
    DIRECTION OUTPUT ;
    USE SIGNAL ;
    PORT
      LAYER M5 ;
        RECT  82.32 0 82.344 0.192 ;
    END
  END o[459]
  PIN o[45]
    DIRECTION OUTPUT ;
    USE SIGNAL ;
    PORT
      LAYER M5 ;
        RECT  11.952 0 11.976 0.192 ;
    END
  END o[45]
  PIN o[460]
    DIRECTION OUTPUT ;
    USE SIGNAL ;
    PORT
      LAYER M5 ;
        RECT  82.512 0 82.536 0.192 ;
    END
  END o[460]
  PIN o[461]
    DIRECTION OUTPUT ;
    USE SIGNAL ;
    PORT
      LAYER M5 ;
        RECT  82.656 0 82.68 0.192 ;
    END
  END o[461]
  PIN o[462]
    DIRECTION OUTPUT ;
    USE SIGNAL ;
    PORT
      LAYER M5 ;
        RECT  82.848 0 82.872 0.192 ;
    END
  END o[462]
  PIN o[463]
    DIRECTION OUTPUT ;
    USE SIGNAL ;
    PORT
      LAYER M5 ;
        RECT  82.992 0 83.016 0.192 ;
    END
  END o[463]
  PIN o[464]
    DIRECTION OUTPUT ;
    USE SIGNAL ;
    PORT
      LAYER M5 ;
        RECT  83.184 0 83.208 0.192 ;
    END
  END o[464]
  PIN o[465]
    DIRECTION OUTPUT ;
    USE SIGNAL ;
    PORT
      LAYER M5 ;
        RECT  83.328 0 83.352 0.192 ;
    END
  END o[465]
  PIN o[466]
    DIRECTION OUTPUT ;
    USE SIGNAL ;
    PORT
      LAYER M5 ;
        RECT  83.52 0 83.544 0.192 ;
    END
  END o[466]
  PIN o[467]
    DIRECTION OUTPUT ;
    USE SIGNAL ;
    PORT
      LAYER M5 ;
        RECT  83.664 0 83.688 0.192 ;
    END
  END o[467]
  PIN o[468]
    DIRECTION OUTPUT ;
    USE SIGNAL ;
    PORT
      LAYER M5 ;
        RECT  83.856 0 83.88 0.192 ;
    END
  END o[468]
  PIN o[469]
    DIRECTION OUTPUT ;
    USE SIGNAL ;
    PORT
      LAYER M5 ;
        RECT  84.048 0 84.072 0.192 ;
    END
  END o[469]
  PIN o[46]
    DIRECTION OUTPUT ;
    USE SIGNAL ;
    PORT
      LAYER M5 ;
        RECT  12.096 0 12.12 0.192 ;
    END
  END o[46]
  PIN o[470]
    DIRECTION OUTPUT ;
    USE SIGNAL ;
    PORT
      LAYER M5 ;
        RECT  84.192 0 84.216 0.192 ;
    END
  END o[470]
  PIN o[471]
    DIRECTION OUTPUT ;
    USE SIGNAL ;
    PORT
      LAYER M5 ;
        RECT  84.384 0 84.408 0.192 ;
    END
  END o[471]
  PIN o[472]
    DIRECTION OUTPUT ;
    USE SIGNAL ;
    PORT
      LAYER M5 ;
        RECT  84.528 0 84.552 0.192 ;
    END
  END o[472]
  PIN o[473]
    DIRECTION OUTPUT ;
    USE SIGNAL ;
    PORT
      LAYER M5 ;
        RECT  84.72 0 84.744 0.192 ;
    END
  END o[473]
  PIN o[474]
    DIRECTION OUTPUT ;
    USE SIGNAL ;
    PORT
      LAYER M5 ;
        RECT  84.864 0 84.888 0.192 ;
    END
  END o[474]
  PIN o[475]
    DIRECTION OUTPUT ;
    USE SIGNAL ;
    PORT
      LAYER M5 ;
        RECT  85.056 0 85.08 0.192 ;
    END
  END o[475]
  PIN o[476]
    DIRECTION OUTPUT ;
    USE SIGNAL ;
    PORT
      LAYER M5 ;
        RECT  85.2 0 85.224 0.192 ;
    END
  END o[476]
  PIN o[477]
    DIRECTION OUTPUT ;
    USE SIGNAL ;
    PORT
      LAYER M5 ;
        RECT  85.392 0 85.416 0.192 ;
    END
  END o[477]
  PIN o[478]
    DIRECTION OUTPUT ;
    USE SIGNAL ;
    PORT
      LAYER M5 ;
        RECT  85.536 0 85.56 0.192 ;
    END
  END o[478]
  PIN o[479]
    DIRECTION OUTPUT ;
    USE SIGNAL ;
    PORT
      LAYER M5 ;
        RECT  85.728 0 85.752 0.192 ;
    END
  END o[479]
  PIN o[47]
    DIRECTION OUTPUT ;
    USE SIGNAL ;
    PORT
      LAYER M5 ;
        RECT  12.288 0 12.312 0.192 ;
    END
  END o[47]
  PIN o[480]
    DIRECTION OUTPUT ;
    USE SIGNAL ;
    PORT
      LAYER M5 ;
        RECT  85.872 0 85.896 0.192 ;
    END
  END o[480]
  PIN o[481]
    DIRECTION OUTPUT ;
    USE SIGNAL ;
    PORT
      LAYER M5 ;
        RECT  86.064 0 86.088 0.192 ;
    END
  END o[481]
  PIN o[482]
    DIRECTION OUTPUT ;
    USE SIGNAL ;
    PORT
      LAYER M5 ;
        RECT  86.256 0 86.28 0.192 ;
    END
  END o[482]
  PIN o[483]
    DIRECTION OUTPUT ;
    USE SIGNAL ;
    PORT
      LAYER M5 ;
        RECT  86.4 0 86.424 0.192 ;
    END
  END o[483]
  PIN o[484]
    DIRECTION OUTPUT ;
    USE SIGNAL ;
    PORT
      LAYER M5 ;
        RECT  86.592 0 86.616 0.192 ;
    END
  END o[484]
  PIN o[485]
    DIRECTION OUTPUT ;
    USE SIGNAL ;
    PORT
      LAYER M5 ;
        RECT  86.736 0 86.76 0.192 ;
    END
  END o[485]
  PIN o[486]
    DIRECTION OUTPUT ;
    USE SIGNAL ;
    PORT
      LAYER M5 ;
        RECT  86.928 0 86.952 0.192 ;
    END
  END o[486]
  PIN o[487]
    DIRECTION OUTPUT ;
    USE SIGNAL ;
    PORT
      LAYER M5 ;
        RECT  87.072 0 87.096 0.192 ;
    END
  END o[487]
  PIN o[488]
    DIRECTION OUTPUT ;
    USE SIGNAL ;
    PORT
      LAYER M5 ;
        RECT  87.264 0 87.288 0.192 ;
    END
  END o[488]
  PIN o[489]
    DIRECTION OUTPUT ;
    USE SIGNAL ;
    PORT
      LAYER M5 ;
        RECT  87.408 0 87.432 0.192 ;
    END
  END o[489]
  PIN o[48]
    DIRECTION OUTPUT ;
    USE SIGNAL ;
    PORT
      LAYER M5 ;
        RECT  12.432 0 12.456 0.192 ;
    END
  END o[48]
  PIN o[490]
    DIRECTION OUTPUT ;
    USE SIGNAL ;
    PORT
      LAYER M5 ;
        RECT  87.6 0 87.624 0.192 ;
    END
  END o[490]
  PIN o[491]
    DIRECTION OUTPUT ;
    USE SIGNAL ;
    PORT
      LAYER M5 ;
        RECT  87.744 0 87.768 0.192 ;
    END
  END o[491]
  PIN o[492]
    DIRECTION OUTPUT ;
    USE SIGNAL ;
    PORT
      LAYER M5 ;
        RECT  87.936 0 87.96 0.192 ;
    END
  END o[492]
  PIN o[493]
    DIRECTION OUTPUT ;
    USE SIGNAL ;
    PORT
      LAYER M5 ;
        RECT  88.08 0 88.104 0.192 ;
    END
  END o[493]
  PIN o[494]
    DIRECTION OUTPUT ;
    USE SIGNAL ;
    PORT
      LAYER M5 ;
        RECT  88.272 0 88.296 0.192 ;
    END
  END o[494]
  PIN o[495]
    DIRECTION OUTPUT ;
    USE SIGNAL ;
    PORT
      LAYER M5 ;
        RECT  88.416 0 88.44 0.192 ;
    END
  END o[495]
  PIN o[496]
    DIRECTION OUTPUT ;
    USE SIGNAL ;
    PORT
      LAYER M5 ;
        RECT  88.608 0 88.632 0.192 ;
    END
  END o[496]
  PIN o[497]
    DIRECTION OUTPUT ;
    USE SIGNAL ;
    PORT
      LAYER M5 ;
        RECT  88.8 0 88.824 0.192 ;
    END
  END o[497]
  PIN o[498]
    DIRECTION OUTPUT ;
    USE SIGNAL ;
    PORT
      LAYER M5 ;
        RECT  88.944 0 88.968 0.192 ;
    END
  END o[498]
  PIN o[499]
    DIRECTION OUTPUT ;
    USE SIGNAL ;
    PORT
      LAYER M5 ;
        RECT  89.136 0 89.16 0.192 ;
    END
  END o[499]
  PIN o[49]
    DIRECTION OUTPUT ;
    USE SIGNAL ;
    PORT
      LAYER M5 ;
        RECT  12.624 0 12.648 0.192 ;
    END
  END o[49]
  PIN o[4]
    DIRECTION OUTPUT ;
    USE SIGNAL ;
    PORT
      LAYER M5 ;
        RECT  4.992 0 5.016 0.192 ;
    END
  END o[4]
  PIN o[500]
    DIRECTION OUTPUT ;
    USE SIGNAL ;
    PORT
      LAYER M5 ;
        RECT  89.28 0 89.304 0.192 ;
    END
  END o[500]
  PIN o[501]
    DIRECTION OUTPUT ;
    USE SIGNAL ;
    PORT
      LAYER M5 ;
        RECT  89.472 0 89.496 0.192 ;
    END
  END o[501]
  PIN o[502]
    DIRECTION OUTPUT ;
    USE SIGNAL ;
    PORT
      LAYER M5 ;
        RECT  89.616 0 89.64 0.192 ;
    END
  END o[502]
  PIN o[503]
    DIRECTION OUTPUT ;
    USE SIGNAL ;
    PORT
      LAYER M5 ;
        RECT  89.808 0 89.832 0.192 ;
    END
  END o[503]
  PIN o[504]
    DIRECTION OUTPUT ;
    USE SIGNAL ;
    PORT
      LAYER M5 ;
        RECT  89.952 0 89.976 0.192 ;
    END
  END o[504]
  PIN o[505]
    DIRECTION OUTPUT ;
    USE SIGNAL ;
    PORT
      LAYER M5 ;
        RECT  90.144 0 90.168 0.192 ;
    END
  END o[505]
  PIN o[506]
    DIRECTION OUTPUT ;
    USE SIGNAL ;
    PORT
      LAYER M5 ;
        RECT  90.288 0 90.312 0.192 ;
    END
  END o[506]
  PIN o[507]
    DIRECTION OUTPUT ;
    USE SIGNAL ;
    PORT
      LAYER M5 ;
        RECT  90.48 0 90.504 0.192 ;
    END
  END o[507]
  PIN o[508]
    DIRECTION OUTPUT ;
    USE SIGNAL ;
    PORT
      LAYER M5 ;
        RECT  90.624 0 90.648 0.192 ;
    END
  END o[508]
  PIN o[509]
    DIRECTION OUTPUT ;
    USE SIGNAL ;
    PORT
      LAYER M5 ;
        RECT  90.816 0 90.84 0.192 ;
    END
  END o[509]
  PIN o[50]
    DIRECTION OUTPUT ;
    USE SIGNAL ;
    PORT
      LAYER M5 ;
        RECT  12.768 0 12.792 0.192 ;
    END
  END o[50]
  PIN o[510]
    DIRECTION OUTPUT ;
    USE SIGNAL ;
    PORT
      LAYER M5 ;
        RECT  90.96 0 90.984 0.192 ;
    END
  END o[510]
  PIN o[511]
    DIRECTION OUTPUT ;
    USE SIGNAL ;
    PORT
      LAYER M5 ;
        RECT  91.152 0 91.176 0.192 ;
    END
  END o[511]
  PIN o[512]
    DIRECTION OUTPUT ;
    USE SIGNAL ;
    PORT
      LAYER M5 ;
        RECT  91.344 0 91.368 0.192 ;
    END
  END o[512]
  PIN o[513]
    DIRECTION OUTPUT ;
    USE SIGNAL ;
    PORT
      LAYER M5 ;
        RECT  91.488 0 91.512 0.192 ;
    END
  END o[513]
  PIN o[514]
    DIRECTION OUTPUT ;
    USE SIGNAL ;
    PORT
      LAYER M5 ;
        RECT  91.68 0 91.704 0.192 ;
    END
  END o[514]
  PIN o[515]
    DIRECTION OUTPUT ;
    USE SIGNAL ;
    PORT
      LAYER M5 ;
        RECT  91.824 0 91.848 0.192 ;
    END
  END o[515]
  PIN o[516]
    DIRECTION OUTPUT ;
    USE SIGNAL ;
    PORT
      LAYER M5 ;
        RECT  92.016 0 92.04 0.192 ;
    END
  END o[516]
  PIN o[517]
    DIRECTION OUTPUT ;
    USE SIGNAL ;
    PORT
      LAYER M5 ;
        RECT  92.16 0 92.184 0.192 ;
    END
  END o[517]
  PIN o[518]
    DIRECTION OUTPUT ;
    USE SIGNAL ;
    PORT
      LAYER M5 ;
        RECT  92.352 0 92.376 0.192 ;
    END
  END o[518]
  PIN o[519]
    DIRECTION OUTPUT ;
    USE SIGNAL ;
    PORT
      LAYER M5 ;
        RECT  92.496 0 92.52 0.192 ;
    END
  END o[519]
  PIN o[51]
    DIRECTION OUTPUT ;
    USE SIGNAL ;
    PORT
      LAYER M5 ;
        RECT  12.96 0 12.984 0.192 ;
    END
  END o[51]
  PIN o[520]
    DIRECTION OUTPUT ;
    USE SIGNAL ;
    PORT
      LAYER M5 ;
        RECT  92.688 0 92.712 0.192 ;
    END
  END o[520]
  PIN o[521]
    DIRECTION OUTPUT ;
    USE SIGNAL ;
    PORT
      LAYER M5 ;
        RECT  92.832 0 92.856 0.192 ;
    END
  END o[521]
  PIN o[522]
    DIRECTION OUTPUT ;
    USE SIGNAL ;
    PORT
      LAYER M5 ;
        RECT  93.024 0 93.048 0.192 ;
    END
  END o[522]
  PIN o[523]
    DIRECTION OUTPUT ;
    USE SIGNAL ;
    PORT
      LAYER M5 ;
        RECT  93.168 0 93.192 0.192 ;
    END
  END o[523]
  PIN o[524]
    DIRECTION OUTPUT ;
    USE SIGNAL ;
    PORT
      LAYER M5 ;
        RECT  93.36 0 93.384 0.192 ;
    END
  END o[524]
  PIN o[525]
    DIRECTION OUTPUT ;
    USE SIGNAL ;
    PORT
      LAYER M5 ;
        RECT  93.504 0 93.528 0.192 ;
    END
  END o[525]
  PIN o[526]
    DIRECTION OUTPUT ;
    USE SIGNAL ;
    PORT
      LAYER M5 ;
        RECT  93.696 0 93.72 0.192 ;
    END
  END o[526]
  PIN o[527]
    DIRECTION OUTPUT ;
    USE SIGNAL ;
    PORT
      LAYER M5 ;
        RECT  93.888 0 93.912 0.192 ;
    END
  END o[527]
  PIN o[528]
    DIRECTION OUTPUT ;
    USE SIGNAL ;
    PORT
      LAYER M5 ;
        RECT  94.032 0 94.056 0.192 ;
    END
  END o[528]
  PIN o[529]
    DIRECTION OUTPUT ;
    USE SIGNAL ;
    PORT
      LAYER M5 ;
        RECT  94.224 0 94.248 0.192 ;
    END
  END o[529]
  PIN o[52]
    DIRECTION OUTPUT ;
    USE SIGNAL ;
    PORT
      LAYER M5 ;
        RECT  13.152 0 13.176 0.192 ;
    END
  END o[52]
  PIN o[530]
    DIRECTION OUTPUT ;
    USE SIGNAL ;
    PORT
      LAYER M5 ;
        RECT  94.368 0 94.392 0.192 ;
    END
  END o[530]
  PIN o[531]
    DIRECTION OUTPUT ;
    USE SIGNAL ;
    PORT
      LAYER M5 ;
        RECT  94.56 0 94.584 0.192 ;
    END
  END o[531]
  PIN o[532]
    DIRECTION OUTPUT ;
    USE SIGNAL ;
    PORT
      LAYER M5 ;
        RECT  94.704 0 94.728 0.192 ;
    END
  END o[532]
  PIN o[533]
    DIRECTION OUTPUT ;
    USE SIGNAL ;
    PORT
      LAYER M5 ;
        RECT  94.896 0 94.92 0.192 ;
    END
  END o[533]
  PIN o[534]
    DIRECTION OUTPUT ;
    USE SIGNAL ;
    PORT
      LAYER M5 ;
        RECT  95.04 0 95.064 0.192 ;
    END
  END o[534]
  PIN o[535]
    DIRECTION OUTPUT ;
    USE SIGNAL ;
    PORT
      LAYER M5 ;
        RECT  95.232 0 95.256 0.192 ;
    END
  END o[535]
  PIN o[536]
    DIRECTION OUTPUT ;
    USE SIGNAL ;
    PORT
      LAYER M5 ;
        RECT  95.376 0 95.4 0.192 ;
    END
  END o[536]
  PIN o[537]
    DIRECTION OUTPUT ;
    USE SIGNAL ;
    PORT
      LAYER M5 ;
        RECT  95.568 0 95.592 0.192 ;
    END
  END o[537]
  PIN o[538]
    DIRECTION OUTPUT ;
    USE SIGNAL ;
    PORT
      LAYER M5 ;
        RECT  95.712 0 95.736 0.192 ;
    END
  END o[538]
  PIN o[539]
    DIRECTION OUTPUT ;
    USE SIGNAL ;
    PORT
      LAYER M5 ;
        RECT  95.904 0 95.928 0.192 ;
    END
  END o[539]
  PIN o[53]
    DIRECTION OUTPUT ;
    USE SIGNAL ;
    PORT
      LAYER M5 ;
        RECT  13.296 0 13.32 0.192 ;
    END
  END o[53]
  PIN o[540]
    DIRECTION OUTPUT ;
    USE SIGNAL ;
    PORT
      LAYER M5 ;
        RECT  96.048 0 96.072 0.192 ;
    END
  END o[540]
  PIN o[541]
    DIRECTION OUTPUT ;
    USE SIGNAL ;
    PORT
      LAYER M5 ;
        RECT  96.24 0 96.264 0.192 ;
    END
  END o[541]
  PIN o[542]
    DIRECTION OUTPUT ;
    USE SIGNAL ;
    PORT
      LAYER M5 ;
        RECT  96.432 0 96.456 0.192 ;
    END
  END o[542]
  PIN o[543]
    DIRECTION OUTPUT ;
    USE SIGNAL ;
    PORT
      LAYER M5 ;
        RECT  96.576 0 96.6 0.192 ;
    END
  END o[543]
  PIN o[544]
    DIRECTION OUTPUT ;
    USE SIGNAL ;
    PORT
      LAYER M5 ;
        RECT  96.768 0 96.792 0.192 ;
    END
  END o[544]
  PIN o[545]
    DIRECTION OUTPUT ;
    USE SIGNAL ;
    PORT
      LAYER M5 ;
        RECT  96.912 0 96.936 0.192 ;
    END
  END o[545]
  PIN o[546]
    DIRECTION OUTPUT ;
    USE SIGNAL ;
    PORT
      LAYER M5 ;
        RECT  97.104 0 97.128 0.192 ;
    END
  END o[546]
  PIN o[547]
    DIRECTION OUTPUT ;
    USE SIGNAL ;
    PORT
      LAYER M5 ;
        RECT  97.248 0 97.272 0.192 ;
    END
  END o[547]
  PIN o[548]
    DIRECTION OUTPUT ;
    USE SIGNAL ;
    PORT
      LAYER M5 ;
        RECT  97.44 0 97.464 0.192 ;
    END
  END o[548]
  PIN o[549]
    DIRECTION OUTPUT ;
    USE SIGNAL ;
    PORT
      LAYER M5 ;
        RECT  97.584 0 97.608 0.192 ;
    END
  END o[549]
  PIN o[54]
    DIRECTION OUTPUT ;
    USE SIGNAL ;
    PORT
      LAYER M5 ;
        RECT  13.488 0 13.512 0.192 ;
    END
  END o[54]
  PIN o[550]
    DIRECTION OUTPUT ;
    USE SIGNAL ;
    PORT
      LAYER M5 ;
        RECT  97.776 0 97.8 0.192 ;
    END
  END o[550]
  PIN o[551]
    DIRECTION OUTPUT ;
    USE SIGNAL ;
    PORT
      LAYER M5 ;
        RECT  97.92 0 97.944 0.192 ;
    END
  END o[551]
  PIN o[552]
    DIRECTION OUTPUT ;
    USE SIGNAL ;
    PORT
      LAYER M5 ;
        RECT  98.112 0 98.136 0.192 ;
    END
  END o[552]
  PIN o[553]
    DIRECTION OUTPUT ;
    USE SIGNAL ;
    PORT
      LAYER M5 ;
        RECT  98.256 0 98.28 0.192 ;
    END
  END o[553]
  PIN o[554]
    DIRECTION OUTPUT ;
    USE SIGNAL ;
    PORT
      LAYER M5 ;
        RECT  98.448 0 98.472 0.192 ;
    END
  END o[554]
  PIN o[555]
    DIRECTION OUTPUT ;
    USE SIGNAL ;
    PORT
      LAYER M5 ;
        RECT  98.592 0 98.616 0.192 ;
    END
  END o[555]
  PIN o[556]
    DIRECTION OUTPUT ;
    USE SIGNAL ;
    PORT
      LAYER M5 ;
        RECT  98.784 0 98.808 0.192 ;
    END
  END o[556]
  PIN o[557]
    DIRECTION OUTPUT ;
    USE SIGNAL ;
    PORT
      LAYER M5 ;
        RECT  98.976 0 99 0.192 ;
    END
  END o[557]
  PIN o[558]
    DIRECTION OUTPUT ;
    USE SIGNAL ;
    PORT
      LAYER M5 ;
        RECT  99.12 0 99.144 0.192 ;
    END
  END o[558]
  PIN o[559]
    DIRECTION OUTPUT ;
    USE SIGNAL ;
    PORT
      LAYER M5 ;
        RECT  99.312 0 99.336 0.192 ;
    END
  END o[559]
  PIN o[55]
    DIRECTION OUTPUT ;
    USE SIGNAL ;
    PORT
      LAYER M5 ;
        RECT  13.632 0 13.656 0.192 ;
    END
  END o[55]
  PIN o[560]
    DIRECTION OUTPUT ;
    USE SIGNAL ;
    PORT
      LAYER M5 ;
        RECT  99.456 0 99.48 0.192 ;
    END
  END o[560]
  PIN o[561]
    DIRECTION OUTPUT ;
    USE SIGNAL ;
    PORT
      LAYER M5 ;
        RECT  99.648 0 99.672 0.192 ;
    END
  END o[561]
  PIN o[562]
    DIRECTION OUTPUT ;
    USE SIGNAL ;
    PORT
      LAYER M5 ;
        RECT  99.792 0 99.816 0.192 ;
    END
  END o[562]
  PIN o[563]
    DIRECTION OUTPUT ;
    USE SIGNAL ;
    PORT
      LAYER M5 ;
        RECT  99.984 0 100.008 0.192 ;
    END
  END o[563]
  PIN o[564]
    DIRECTION OUTPUT ;
    USE SIGNAL ;
    PORT
      LAYER M5 ;
        RECT  100.128 0 100.152 0.192 ;
    END
  END o[564]
  PIN o[565]
    DIRECTION OUTPUT ;
    USE SIGNAL ;
    PORT
      LAYER M5 ;
        RECT  100.32 0 100.344 0.192 ;
    END
  END o[565]
  PIN o[566]
    DIRECTION OUTPUT ;
    USE SIGNAL ;
    PORT
      LAYER M5 ;
        RECT  100.464 0 100.488 0.192 ;
    END
  END o[566]
  PIN o[567]
    DIRECTION OUTPUT ;
    USE SIGNAL ;
    PORT
      LAYER M5 ;
        RECT  100.656 0 100.68 0.192 ;
    END
  END o[567]
  PIN o[568]
    DIRECTION OUTPUT ;
    USE SIGNAL ;
    PORT
      LAYER M5 ;
        RECT  100.8 0 100.824 0.192 ;
    END
  END o[568]
  PIN o[569]
    DIRECTION OUTPUT ;
    USE SIGNAL ;
    PORT
      LAYER M5 ;
        RECT  100.992 0 101.016 0.192 ;
    END
  END o[569]
  PIN o[56]
    DIRECTION OUTPUT ;
    USE SIGNAL ;
    PORT
      LAYER M5 ;
        RECT  13.824 0 13.848 0.192 ;
    END
  END o[56]
  PIN o[570]
    DIRECTION OUTPUT ;
    USE SIGNAL ;
    PORT
      LAYER M5 ;
        RECT  101.136 0 101.16 0.192 ;
    END
  END o[570]
  PIN o[571]
    DIRECTION OUTPUT ;
    USE SIGNAL ;
    PORT
      LAYER M5 ;
        RECT  101.328 0 101.352 0.192 ;
    END
  END o[571]
  PIN o[572]
    DIRECTION OUTPUT ;
    USE SIGNAL ;
    PORT
      LAYER M5 ;
        RECT  101.52 0 101.544 0.192 ;
    END
  END o[572]
  PIN o[573]
    DIRECTION OUTPUT ;
    USE SIGNAL ;
    PORT
      LAYER M5 ;
        RECT  101.664 0 101.688 0.192 ;
    END
  END o[573]
  PIN o[574]
    DIRECTION OUTPUT ;
    USE SIGNAL ;
    PORT
      LAYER M5 ;
        RECT  101.856 0 101.88 0.192 ;
    END
  END o[574]
  PIN o[575]
    DIRECTION OUTPUT ;
    USE SIGNAL ;
    PORT
      LAYER M5 ;
        RECT  102 0 102.024 0.192 ;
    END
  END o[575]
  PIN o[576]
    DIRECTION OUTPUT ;
    USE SIGNAL ;
    PORT
      LAYER M5 ;
        RECT  102.192 0 102.216 0.192 ;
    END
  END o[576]
  PIN o[577]
    DIRECTION OUTPUT ;
    USE SIGNAL ;
    PORT
      LAYER M5 ;
        RECT  102.336 0 102.36 0.192 ;
    END
  END o[577]
  PIN o[578]
    DIRECTION OUTPUT ;
    USE SIGNAL ;
    PORT
      LAYER M5 ;
        RECT  102.528 0 102.552 0.192 ;
    END
  END o[578]
  PIN o[579]
    DIRECTION OUTPUT ;
    USE SIGNAL ;
    PORT
      LAYER M5 ;
        RECT  102.672 0 102.696 0.192 ;
    END
  END o[579]
  PIN o[57]
    DIRECTION OUTPUT ;
    USE SIGNAL ;
    PORT
      LAYER M5 ;
        RECT  13.968 0 13.992 0.192 ;
    END
  END o[57]
  PIN o[580]
    DIRECTION OUTPUT ;
    USE SIGNAL ;
    PORT
      LAYER M5 ;
        RECT  102.864 0 102.888 0.192 ;
    END
  END o[580]
  PIN o[581]
    DIRECTION OUTPUT ;
    USE SIGNAL ;
    PORT
      LAYER M5 ;
        RECT  103.008 0 103.032 0.192 ;
    END
  END o[581]
  PIN o[582]
    DIRECTION OUTPUT ;
    USE SIGNAL ;
    PORT
      LAYER M5 ;
        RECT  103.2 0 103.224 0.192 ;
    END
  END o[582]
  PIN o[583]
    DIRECTION OUTPUT ;
    USE SIGNAL ;
    PORT
      LAYER M5 ;
        RECT  103.344 0 103.368 0.192 ;
    END
  END o[583]
  PIN o[584]
    DIRECTION OUTPUT ;
    USE SIGNAL ;
    PORT
      LAYER M5 ;
        RECT  103.536 0 103.56 0.192 ;
    END
  END o[584]
  PIN o[585]
    DIRECTION OUTPUT ;
    USE SIGNAL ;
    PORT
      LAYER M5 ;
        RECT  103.68 0 103.704 0.192 ;
    END
  END o[585]
  PIN o[586]
    DIRECTION OUTPUT ;
    USE SIGNAL ;
    PORT
      LAYER M5 ;
        RECT  103.872 0 103.896 0.192 ;
    END
  END o[586]
  PIN o[587]
    DIRECTION OUTPUT ;
    USE SIGNAL ;
    PORT
      LAYER M5 ;
        RECT  104.064 0 104.088 0.192 ;
    END
  END o[587]
  PIN o[588]
    DIRECTION OUTPUT ;
    USE SIGNAL ;
    PORT
      LAYER M5 ;
        RECT  104.208 0 104.232 0.192 ;
    END
  END o[588]
  PIN o[589]
    DIRECTION OUTPUT ;
    USE SIGNAL ;
    PORT
      LAYER M5 ;
        RECT  104.4 0 104.424 0.192 ;
    END
  END o[589]
  PIN o[58]
    DIRECTION OUTPUT ;
    USE SIGNAL ;
    PORT
      LAYER M5 ;
        RECT  14.16 0 14.184 0.192 ;
    END
  END o[58]
  PIN o[590]
    DIRECTION OUTPUT ;
    USE SIGNAL ;
    PORT
      LAYER M5 ;
        RECT  104.544 0 104.568 0.192 ;
    END
  END o[590]
  PIN o[591]
    DIRECTION OUTPUT ;
    USE SIGNAL ;
    PORT
      LAYER M5 ;
        RECT  104.736 0 104.76 0.192 ;
    END
  END o[591]
  PIN o[592]
    DIRECTION OUTPUT ;
    USE SIGNAL ;
    PORT
      LAYER M5 ;
        RECT  104.88 0 104.904 0.192 ;
    END
  END o[592]
  PIN o[593]
    DIRECTION OUTPUT ;
    USE SIGNAL ;
    PORT
      LAYER M5 ;
        RECT  105.072 0 105.096 0.192 ;
    END
  END o[593]
  PIN o[594]
    DIRECTION OUTPUT ;
    USE SIGNAL ;
    PORT
      LAYER M5 ;
        RECT  105.216 0 105.24 0.192 ;
    END
  END o[594]
  PIN o[595]
    DIRECTION OUTPUT ;
    USE SIGNAL ;
    PORT
      LAYER M5 ;
        RECT  105.408 0 105.432 0.192 ;
    END
  END o[595]
  PIN o[596]
    DIRECTION OUTPUT ;
    USE SIGNAL ;
    PORT
      LAYER M5 ;
        RECT  105.552 0 105.576 0.192 ;
    END
  END o[596]
  PIN o[597]
    DIRECTION OUTPUT ;
    USE SIGNAL ;
    PORT
      LAYER M5 ;
        RECT  105.744 0 105.768 0.192 ;
    END
  END o[597]
  PIN o[598]
    DIRECTION OUTPUT ;
    USE SIGNAL ;
    PORT
      LAYER M5 ;
        RECT  105.888 0 105.912 0.192 ;
    END
  END o[598]
  PIN o[599]
    DIRECTION OUTPUT ;
    USE SIGNAL ;
    PORT
      LAYER M5 ;
        RECT  106.08 0 106.104 0.192 ;
    END
  END o[599]
  PIN o[59]
    DIRECTION OUTPUT ;
    USE SIGNAL ;
    PORT
      LAYER M5 ;
        RECT  14.304 0 14.328 0.192 ;
    END
  END o[59]
  PIN o[5]
    DIRECTION OUTPUT ;
    USE SIGNAL ;
    PORT
      LAYER M5 ;
        RECT  5.136 0 5.16 0.192 ;
    END
  END o[5]
  PIN o[600]
    DIRECTION OUTPUT ;
    USE SIGNAL ;
    PORT
      LAYER M5 ;
        RECT  106.224 0 106.248 0.192 ;
    END
  END o[600]
  PIN o[601]
    DIRECTION OUTPUT ;
    USE SIGNAL ;
    PORT
      LAYER M5 ;
        RECT  106.416 0 106.44 0.192 ;
    END
  END o[601]
  PIN o[602]
    DIRECTION OUTPUT ;
    USE SIGNAL ;
    PORT
      LAYER M5 ;
        RECT  106.608 0 106.632 0.192 ;
    END
  END o[602]
  PIN o[603]
    DIRECTION OUTPUT ;
    USE SIGNAL ;
    PORT
      LAYER M5 ;
        RECT  106.752 0 106.776 0.192 ;
    END
  END o[603]
  PIN o[604]
    DIRECTION OUTPUT ;
    USE SIGNAL ;
    PORT
      LAYER M5 ;
        RECT  106.944 0 106.968 0.192 ;
    END
  END o[604]
  PIN o[605]
    DIRECTION OUTPUT ;
    USE SIGNAL ;
    PORT
      LAYER M5 ;
        RECT  107.088 0 107.112 0.192 ;
    END
  END o[605]
  PIN o[606]
    DIRECTION OUTPUT ;
    USE SIGNAL ;
    PORT
      LAYER M5 ;
        RECT  107.28 0 107.304 0.192 ;
    END
  END o[606]
  PIN o[607]
    DIRECTION OUTPUT ;
    USE SIGNAL ;
    PORT
      LAYER M5 ;
        RECT  107.424 0 107.448 0.192 ;
    END
  END o[607]
  PIN o[608]
    DIRECTION OUTPUT ;
    USE SIGNAL ;
    PORT
      LAYER M5 ;
        RECT  107.616 0 107.64 0.192 ;
    END
  END o[608]
  PIN o[609]
    DIRECTION OUTPUT ;
    USE SIGNAL ;
    PORT
      LAYER M5 ;
        RECT  107.76 0 107.784 0.192 ;
    END
  END o[609]
  PIN o[60]
    DIRECTION OUTPUT ;
    USE SIGNAL ;
    PORT
      LAYER M5 ;
        RECT  14.496 0 14.52 0.192 ;
    END
  END o[60]
  PIN o[610]
    DIRECTION OUTPUT ;
    USE SIGNAL ;
    PORT
      LAYER M5 ;
        RECT  107.952 0 107.976 0.192 ;
    END
  END o[610]
  PIN o[611]
    DIRECTION OUTPUT ;
    USE SIGNAL ;
    PORT
      LAYER M5 ;
        RECT  108.096 0 108.12 0.192 ;
    END
  END o[611]
  PIN o[612]
    DIRECTION OUTPUT ;
    USE SIGNAL ;
    PORT
      LAYER M5 ;
        RECT  108.288 0 108.312 0.192 ;
    END
  END o[612]
  PIN o[613]
    DIRECTION OUTPUT ;
    USE SIGNAL ;
    PORT
      LAYER M5 ;
        RECT  108.432 0 108.456 0.192 ;
    END
  END o[613]
  PIN o[614]
    DIRECTION OUTPUT ;
    USE SIGNAL ;
    PORT
      LAYER M5 ;
        RECT  108.624 0 108.648 0.192 ;
    END
  END o[614]
  PIN o[615]
    DIRECTION OUTPUT ;
    USE SIGNAL ;
    PORT
      LAYER M5 ;
        RECT  108.768 0 108.792 0.192 ;
    END
  END o[615]
  PIN o[616]
    DIRECTION OUTPUT ;
    USE SIGNAL ;
    PORT
      LAYER M5 ;
        RECT  108.96 0 108.984 0.192 ;
    END
  END o[616]
  PIN o[617]
    DIRECTION OUTPUT ;
    USE SIGNAL ;
    PORT
      LAYER M5 ;
        RECT  109.152 0 109.176 0.192 ;
    END
  END o[617]
  PIN o[618]
    DIRECTION OUTPUT ;
    USE SIGNAL ;
    PORT
      LAYER M5 ;
        RECT  109.296 0 109.32 0.192 ;
    END
  END o[618]
  PIN o[619]
    DIRECTION OUTPUT ;
    USE SIGNAL ;
    PORT
      LAYER M5 ;
        RECT  109.488 0 109.512 0.192 ;
    END
  END o[619]
  PIN o[61]
    DIRECTION OUTPUT ;
    USE SIGNAL ;
    PORT
      LAYER M5 ;
        RECT  14.64 0 14.664 0.192 ;
    END
  END o[61]
  PIN o[620]
    DIRECTION OUTPUT ;
    USE SIGNAL ;
    PORT
      LAYER M5 ;
        RECT  109.632 0 109.656 0.192 ;
    END
  END o[620]
  PIN o[621]
    DIRECTION OUTPUT ;
    USE SIGNAL ;
    PORT
      LAYER M5 ;
        RECT  109.824 0 109.848 0.192 ;
    END
  END o[621]
  PIN o[622]
    DIRECTION OUTPUT ;
    USE SIGNAL ;
    PORT
      LAYER M5 ;
        RECT  109.968 0 109.992 0.192 ;
    END
  END o[622]
  PIN o[623]
    DIRECTION OUTPUT ;
    USE SIGNAL ;
    PORT
      LAYER M5 ;
        RECT  110.16 0 110.184 0.192 ;
    END
  END o[623]
  PIN o[62]
    DIRECTION OUTPUT ;
    USE SIGNAL ;
    PORT
      LAYER M5 ;
        RECT  14.832 0 14.856 0.192 ;
    END
  END o[62]
  PIN o[63]
    DIRECTION OUTPUT ;
    USE SIGNAL ;
    PORT
      LAYER M5 ;
        RECT  14.976 0 15 0.192 ;
    END
  END o[63]
  PIN o[64]
    DIRECTION OUTPUT ;
    USE SIGNAL ;
    PORT
      LAYER M5 ;
        RECT  15.168 0 15.192 0.192 ;
    END
  END o[64]
  PIN o[65]
    DIRECTION OUTPUT ;
    USE SIGNAL ;
    PORT
      LAYER M5 ;
        RECT  15.312 0 15.336 0.192 ;
    END
  END o[65]
  PIN o[66]
    DIRECTION OUTPUT ;
    USE SIGNAL ;
    PORT
      LAYER M5 ;
        RECT  15.504 0 15.528 0.192 ;
    END
  END o[66]
  PIN o[67]
    DIRECTION OUTPUT ;
    USE SIGNAL ;
    PORT
      LAYER M5 ;
        RECT  15.696 0 15.72 0.192 ;
    END
  END o[67]
  PIN o[68]
    DIRECTION OUTPUT ;
    USE SIGNAL ;
    PORT
      LAYER M5 ;
        RECT  15.84 0 15.864 0.192 ;
    END
  END o[68]
  PIN o[69]
    DIRECTION OUTPUT ;
    USE SIGNAL ;
    PORT
      LAYER M5 ;
        RECT  16.032 0 16.056 0.192 ;
    END
  END o[69]
  PIN o[6]
    DIRECTION OUTPUT ;
    USE SIGNAL ;
    PORT
      LAYER M5 ;
        RECT  5.328 0 5.352 0.192 ;
    END
  END o[6]
  PIN o[70]
    DIRECTION OUTPUT ;
    USE SIGNAL ;
    PORT
      LAYER M5 ;
        RECT  16.176 0 16.2 0.192 ;
    END
  END o[70]
  PIN o[71]
    DIRECTION OUTPUT ;
    USE SIGNAL ;
    PORT
      LAYER M5 ;
        RECT  16.368 0 16.392 0.192 ;
    END
  END o[71]
  PIN o[72]
    DIRECTION OUTPUT ;
    USE SIGNAL ;
    PORT
      LAYER M5 ;
        RECT  16.512 0 16.536 0.192 ;
    END
  END o[72]
  PIN o[73]
    DIRECTION OUTPUT ;
    USE SIGNAL ;
    PORT
      LAYER M5 ;
        RECT  16.704 0 16.728 0.192 ;
    END
  END o[73]
  PIN o[74]
    DIRECTION OUTPUT ;
    USE SIGNAL ;
    PORT
      LAYER M5 ;
        RECT  16.848 0 16.872 0.192 ;
    END
  END o[74]
  PIN o[75]
    DIRECTION OUTPUT ;
    USE SIGNAL ;
    PORT
      LAYER M5 ;
        RECT  17.04 0 17.064 0.192 ;
    END
  END o[75]
  PIN o[76]
    DIRECTION OUTPUT ;
    USE SIGNAL ;
    PORT
      LAYER M5 ;
        RECT  17.184 0 17.208 0.192 ;
    END
  END o[76]
  PIN o[77]
    DIRECTION OUTPUT ;
    USE SIGNAL ;
    PORT
      LAYER M5 ;
        RECT  17.376 0 17.4 0.192 ;
    END
  END o[77]
  PIN o[78]
    DIRECTION OUTPUT ;
    USE SIGNAL ;
    PORT
      LAYER M5 ;
        RECT  17.52 0 17.544 0.192 ;
    END
  END o[78]
  PIN o[79]
    DIRECTION OUTPUT ;
    USE SIGNAL ;
    PORT
      LAYER M5 ;
        RECT  17.712 0 17.736 0.192 ;
    END
  END o[79]
  PIN o[7]
    DIRECTION OUTPUT ;
    USE SIGNAL ;
    PORT
      LAYER M5 ;
        RECT  5.472 0 5.496 0.192 ;
    END
  END o[7]
  PIN o[80]
    DIRECTION OUTPUT ;
    USE SIGNAL ;
    PORT
      LAYER M5 ;
        RECT  17.856 0 17.88 0.192 ;
    END
  END o[80]
  PIN o[81]
    DIRECTION OUTPUT ;
    USE SIGNAL ;
    PORT
      LAYER M5 ;
        RECT  18.048 0 18.072 0.192 ;
    END
  END o[81]
  PIN o[82]
    DIRECTION OUTPUT ;
    USE SIGNAL ;
    PORT
      LAYER M5 ;
        RECT  18.24 0 18.264 0.192 ;
    END
  END o[82]
  PIN o[83]
    DIRECTION OUTPUT ;
    USE SIGNAL ;
    PORT
      LAYER M5 ;
        RECT  18.384 0 18.408 0.192 ;
    END
  END o[83]
  PIN o[84]
    DIRECTION OUTPUT ;
    USE SIGNAL ;
    PORT
      LAYER M5 ;
        RECT  18.576 0 18.6 0.192 ;
    END
  END o[84]
  PIN o[85]
    DIRECTION OUTPUT ;
    USE SIGNAL ;
    PORT
      LAYER M5 ;
        RECT  18.72 0 18.744 0.192 ;
    END
  END o[85]
  PIN o[86]
    DIRECTION OUTPUT ;
    USE SIGNAL ;
    PORT
      LAYER M5 ;
        RECT  18.912 0 18.936 0.192 ;
    END
  END o[86]
  PIN o[87]
    DIRECTION OUTPUT ;
    USE SIGNAL ;
    PORT
      LAYER M5 ;
        RECT  19.056 0 19.08 0.192 ;
    END
  END o[87]
  PIN o[88]
    DIRECTION OUTPUT ;
    USE SIGNAL ;
    PORT
      LAYER M5 ;
        RECT  19.248 0 19.272 0.192 ;
    END
  END o[88]
  PIN o[89]
    DIRECTION OUTPUT ;
    USE SIGNAL ;
    PORT
      LAYER M5 ;
        RECT  19.392 0 19.416 0.192 ;
    END
  END o[89]
  PIN o[8]
    DIRECTION OUTPUT ;
    USE SIGNAL ;
    PORT
      LAYER M5 ;
        RECT  5.664 0 5.688 0.192 ;
    END
  END o[8]
  PIN o[90]
    DIRECTION OUTPUT ;
    USE SIGNAL ;
    PORT
      LAYER M5 ;
        RECT  19.584 0 19.608 0.192 ;
    END
  END o[90]
  PIN o[91]
    DIRECTION OUTPUT ;
    USE SIGNAL ;
    PORT
      LAYER M5 ;
        RECT  19.728 0 19.752 0.192 ;
    END
  END o[91]
  PIN o[92]
    DIRECTION OUTPUT ;
    USE SIGNAL ;
    PORT
      LAYER M5 ;
        RECT  19.92 0 19.944 0.192 ;
    END
  END o[92]
  PIN o[93]
    DIRECTION OUTPUT ;
    USE SIGNAL ;
    PORT
      LAYER M5 ;
        RECT  20.064 0 20.088 0.192 ;
    END
  END o[93]
  PIN o[94]
    DIRECTION OUTPUT ;
    USE SIGNAL ;
    PORT
      LAYER M5 ;
        RECT  20.256 0 20.28 0.192 ;
    END
  END o[94]
  PIN o[95]
    DIRECTION OUTPUT ;
    USE SIGNAL ;
    PORT
      LAYER M5 ;
        RECT  20.4 0 20.424 0.192 ;
    END
  END o[95]
  PIN o[96]
    DIRECTION OUTPUT ;
    USE SIGNAL ;
    PORT
      LAYER M5 ;
        RECT  20.592 0 20.616 0.192 ;
    END
  END o[96]
  PIN o[97]
    DIRECTION OUTPUT ;
    USE SIGNAL ;
    PORT
      LAYER M5 ;
        RECT  20.784 0 20.808 0.192 ;
    END
  END o[97]
  PIN o[98]
    DIRECTION OUTPUT ;
    USE SIGNAL ;
    PORT
      LAYER M5 ;
        RECT  20.928 0 20.952 0.192 ;
    END
  END o[98]
  PIN o[99]
    DIRECTION OUTPUT ;
    USE SIGNAL ;
    PORT
      LAYER M5 ;
        RECT  21.12 0 21.144 0.192 ;
    END
  END o[99]
  PIN o[9]
    DIRECTION OUTPUT ;
    USE SIGNAL ;
    PORT
      LAYER M5 ;
        RECT  5.856 0 5.88 0.192 ;
    END
  END o[9]
  PIN rs
    DIRECTION INPUT ;
    USE SIGNAL ;
    PORT
      LAYER M4 ;
        RECT  0 10.8 0.192 10.824 ;
    END
    PORT
      LAYER M4 ;
        RECT  0.156 10.8 0.205 10.824 ;
    END
  END rs
  PIN VDD
    DIRECTION INOUT ;
    USE POWER ;
    PORT
      LAYER M5 ;
        RECT  110.592 2.151 110.712 19.449 ;
        RECT  107.892 2.151 108.012 19.449 ;
        RECT  105.192 2.151 105.312 19.449 ;
        RECT  102.492 2.151 102.612 19.449 ;
        RECT  99.792 2.151 99.912 19.449 ;
        RECT  97.092 2.151 97.212 19.449 ;
        RECT  94.392 2.151 94.512 19.449 ;
        RECT  91.692 2.151 91.812 19.449 ;
        RECT  88.992 2.151 89.112 19.449 ;
        RECT  86.292 2.151 86.412 19.449 ;
        RECT  83.592 2.151 83.712 19.449 ;
        RECT  80.892 2.151 81.012 19.449 ;
        RECT  78.192 2.151 78.312 19.449 ;
        RECT  75.492 2.151 75.612 19.449 ;
        RECT  72.792 2.151 72.912 19.449 ;
        RECT  70.092 2.151 70.212 19.449 ;
        RECT  67.392 2.151 67.512 19.449 ;
        RECT  64.692 2.151 64.812 19.449 ;
        RECT  61.992 2.151 62.112 19.449 ;
        RECT  59.292 2.151 59.412 19.449 ;
        RECT  56.592 2.151 56.712 19.449 ;
        RECT  53.892 2.151 54.012 19.449 ;
        RECT  51.192 2.151 51.312 19.449 ;
        RECT  48.492 2.151 48.612 19.449 ;
        RECT  45.792 2.151 45.912 19.449 ;
        RECT  43.092 2.151 43.212 19.449 ;
        RECT  40.392 2.151 40.512 19.449 ;
        RECT  37.692 2.151 37.812 19.449 ;
        RECT  34.992 2.151 35.112 19.449 ;
        RECT  32.292 2.151 32.412 19.449 ;
        RECT  29.592 2.151 29.712 19.449 ;
        RECT  26.892 2.151 27.012 19.449 ;
        RECT  24.192 2.151 24.312 19.449 ;
        RECT  21.492 2.151 21.612 19.449 ;
        RECT  18.792 2.151 18.912 19.449 ;
        RECT  16.092 2.151 16.212 19.449 ;
        RECT  13.392 2.151 13.512 19.449 ;
        RECT  10.692 2.151 10.812 19.449 ;
        RECT  7.992 2.151 8.112 19.449 ;
        RECT  5.292 2.151 5.412 19.449 ;
        RECT  2.592 2.151 2.712 19.449 ;
    END
  END VDD
  PIN VSS
    DIRECTION INOUT ;
    USE GROUND ;
    PORT
      LAYER M5 ;
        RECT  110.4 2.137 110.52 19.463 ;
        RECT  107.7 2.137 107.82 19.463 ;
        RECT  105 2.137 105.12 19.463 ;
        RECT  102.3 2.137 102.42 19.463 ;
        RECT  99.6 2.137 99.72 19.463 ;
        RECT  96.9 2.137 97.02 19.463 ;
        RECT  94.2 2.137 94.32 19.463 ;
        RECT  91.5 2.137 91.62 19.463 ;
        RECT  88.8 2.137 88.92 19.463 ;
        RECT  86.1 2.137 86.22 19.463 ;
        RECT  83.4 2.137 83.52 19.463 ;
        RECT  80.7 2.137 80.82 19.463 ;
        RECT  78 2.137 78.12 19.463 ;
        RECT  75.3 2.137 75.42 19.463 ;
        RECT  72.6 2.137 72.72 19.463 ;
        RECT  69.9 2.137 70.02 19.463 ;
        RECT  67.2 2.137 67.32 19.463 ;
        RECT  64.5 2.137 64.62 19.463 ;
        RECT  61.8 2.137 61.92 19.463 ;
        RECT  59.1 2.137 59.22 19.463 ;
        RECT  56.4 2.137 56.52 19.463 ;
        RECT  53.7 2.137 53.82 19.463 ;
        RECT  51 2.137 51.12 19.463 ;
        RECT  48.3 2.137 48.42 19.463 ;
        RECT  45.6 2.137 45.72 19.463 ;
        RECT  42.9 2.137 43.02 19.463 ;
        RECT  40.2 2.137 40.32 19.463 ;
        RECT  37.5 2.137 37.62 19.463 ;
        RECT  34.8 2.137 34.92 19.463 ;
        RECT  32.1 2.137 32.22 19.463 ;
        RECT  29.4 2.137 29.52 19.463 ;
        RECT  26.7 2.137 26.82 19.463 ;
        RECT  24 2.137 24.12 19.463 ;
        RECT  21.3 2.137 21.42 19.463 ;
        RECT  18.6 2.137 18.72 19.463 ;
        RECT  15.9 2.137 16.02 19.463 ;
        RECT  13.2 2.137 13.32 19.463 ;
        RECT  10.5 2.137 10.62 19.463 ;
        RECT  7.8 2.137 7.92 19.463 ;
        RECT  5.1 2.137 5.22 19.463 ;
        RECT  2.4 2.137 2.52 19.463 ;
    END
  END VSS
  # OT_OBS_CLOSED layer=M5 d_um=1.536 added=109
  OBS
    LAYER RVTN ;
     RECT  2.16 2.16 112.32 2.295 ;
     RECT  2.16 2.565 112.32 2.835 ;
     RECT  2.16 3.105 112.32 3.375 ;
     RECT  2.16 3.645 112.32 3.915 ;
     RECT  2.16 4.185 112.32 4.455 ;
     RECT  2.16 4.725 112.32 4.995 ;
     RECT  2.16 5.265 112.32 5.535 ;
     RECT  2.16 5.805 112.32 6.075 ;
     RECT  2.16 6.345 112.32 6.615 ;
     RECT  2.16 6.885 112.32 7.155 ;
     RECT  2.16 7.425 112.32 7.695 ;
     RECT  2.16 7.965 112.32 8.235 ;
     RECT  2.16 8.505 112.32 8.775 ;
     RECT  2.16 9.045 112.32 9.315 ;
     RECT  2.16 9.585 112.32 9.855 ;
     RECT  2.16 10.125 112.32 10.395 ;
     RECT  2.16 10.665 112.32 10.935 ;
     RECT  2.16 11.205 112.32 11.475 ;
     RECT  2.16 11.745 112.32 12.015 ;
     RECT  2.16 12.285 112.32 12.555 ;
     RECT  2.16 12.825 112.32 13.095 ;
     RECT  2.16 13.365 112.32 13.635 ;
     RECT  2.16 13.905 112.32 14.175 ;
     RECT  2.16 14.445 112.32 14.715 ;
     RECT  2.16 14.985 112.32 15.255 ;
     RECT  2.16 15.525 112.32 15.795 ;
     RECT  2.16 16.065 112.32 16.335 ;
     RECT  2.16 16.605 112.32 16.875 ;
     RECT  2.16 17.145 112.32 17.415 ;
     RECT  2.16 17.685 112.32 17.955 ;
     RECT  2.16 18.225 112.32 18.495 ;
     RECT  2.16 18.765 112.32 19.035 ;
     RECT  2.16 19.305 112.32 19.44 ;
    LAYER RVTP ;
     RECT  2.16 2.295 112.32 2.565 ;
     RECT  2.16 2.835 112.32 3.105 ;
     RECT  2.16 3.375 112.32 3.645 ;
     RECT  2.16 3.915 112.32 4.185 ;
     RECT  2.16 4.455 112.32 4.725 ;
     RECT  2.16 4.995 112.32 5.265 ;
     RECT  2.16 5.535 112.32 5.805 ;
     RECT  2.16 6.075 112.32 6.345 ;
     RECT  2.16 6.615 112.32 6.885 ;
     RECT  2.16 7.155 112.32 7.425 ;
     RECT  2.16 7.695 112.32 7.965 ;
     RECT  2.16 8.235 112.32 8.505 ;
     RECT  2.16 8.775 112.32 9.045 ;
     RECT  2.16 9.315 112.32 9.585 ;
     RECT  2.16 9.855 112.32 10.125 ;
     RECT  2.16 10.395 112.32 10.665 ;
     RECT  2.16 10.935 112.32 11.205 ;
     RECT  2.16 11.475 112.32 11.745 ;
     RECT  2.16 12.015 112.32 12.285 ;
     RECT  2.16 12.555 112.32 12.825 ;
     RECT  2.16 13.095 112.32 13.365 ;
     RECT  2.16 13.635 112.32 13.905 ;
     RECT  2.16 14.175 112.32 14.445 ;
     RECT  2.16 14.715 112.32 14.985 ;
     RECT  2.16 15.255 112.32 15.525 ;
     RECT  2.16 15.795 112.32 16.065 ;
     RECT  2.16 16.335 112.32 16.605 ;
     RECT  2.16 16.875 112.32 17.145 ;
     RECT  2.16 17.415 112.32 17.685 ;
     RECT  2.16 17.955 112.32 18.225 ;
     RECT  2.16 18.495 112.32 18.765 ;
     RECT  2.16 19.035 112.32 19.305 ;
    LAYER M1 ;
     RECT  2.16 2.151 112.32 19.449 ;
    LAYER M2 ;
     RECT  2.16 2.151 7.987 19.449 ;
     RECT  7.987 1.728 8.951 19.449 ;
     RECT  8.951 2.151 15.979 19.449 ;
     RECT  15.979 1.728 17.087 19.449 ;
     RECT  17.087 2.151 18.823 19.449 ;
     RECT  18.823 1.728 19.607 19.449 ;
     RECT  19.607 2.151 112.32 19.449 ;
    LAYER M3 ;
     RECT  7.992 0.187 8.694 0.235 ;
     RECT  9.468 0.187 10.998 0.235 ;
     RECT  12.024 0.187 12.654 0.235 ;
     RECT  13.896 0.187 18.846 0.235 ;
     RECT  19.728 0.187 20.646 0.235 ;
     RECT  22.032 0.187 22.05 0.235 ;
     RECT  25.956 0.187 25.974 0.235 ;
     RECT  28.908 0.187 29.142 0.235 ;
     RECT  30.6 0.187 30.798 0.235 ;
     RECT  31.752 0.187 33.138 0.235 ;
     RECT  35.532 0.187 35.55 0.235 ;
     RECT  38.664 0.187 38.682 0.235 ;
     RECT  39.78 0.187 40.626 0.235 ;
     RECT  41.94 0.187 42.534 0.235 ;
     RECT  43.992 0.187 44.01 0.235 ;
     RECT  44.784 0.187 45.054 0.235 ;
     RECT  51.552 0.187 51.57 0.235 ;
     RECT  53.424 0.187 54.81 0.235 ;
     RECT  55.584 0.187 55.602 0.235 ;
     RECT  57.096 0.187 57.438 0.235 ;
     RECT  58.176 0.187 58.194 0.235 ;
     RECT  59.94 0.187 59.958 0.235 ;
     RECT  60.804 0.187 61.326 0.235 ;
     RECT  63.252 0.187 63.882 0.235 ;
     RECT  65.664 0.187 66.402 0.235 ;
     RECT  67.644 0.187 67.662 0.235 ;
     RECT  68.724 0.187 69.39 0.235 ;
     RECT  73.368 0.187 75.654 0.235 ;
     RECT  76.86 0.187 77.274 0.235 ;
     RECT  79.02 0.187 79.038 0.235 ;
     RECT  80.064 0.187 80.082 0.235 ;
     RECT  81.288 0.187 81.702 0.235 ;
     RECT  82.548 0.187 82.89 0.235 ;
     RECT  84.312 0.187 85.014 0.235 ;
     RECT  87.012 0.187 87.03 0.235 ;
     RECT  88.308 0.187 89.622 0.235 ;
     RECT  91.044 0.187 91.062 0.235 ;
     RECT  94.86 0.187 96.534 0.235 ;
     RECT  101.016 0.187 101.034 0.235 ;
     RECT  101.88 0.187 101.898 0.235 ;
     RECT  103.068 0.187 103.086 0.235 ;
     RECT  104.688 0.187 107.478 0.235 ;
     RECT  108.504 0.187 108.522 0.235 ;
     RECT  109.368 0.187 109.53 0.235 ;
     RECT  4.356 0.187 7.254 0.283 ;
     RECT  7.992 0.235 10.998 0.283 ;
     RECT  12.024 0.235 20.646 0.283 ;
     RECT  22.032 0.235 22.23 0.283 ;
     RECT  23.04 0.187 24.174 0.283 ;
     RECT  24.948 0.187 25.182 0.283 ;
     RECT  25.956 0.235 26.046 0.283 ;
     RECT  30.42 0.235 30.798 0.283 ;
     RECT  31.644 0.235 33.138 0.283 ;
     RECT  34.596 0.187 34.614 0.283 ;
     RECT  35.532 0.235 35.802 0.283 ;
     RECT  36.54 0.187 36.558 0.283 ;
     RECT  43.632 0.235 45.054 0.283 ;
     RECT  51.48 0.235 51.57 0.283 ;
     RECT  52.488 0.187 52.506 0.283 ;
     RECT  56.952 0.235 58.986 0.283 ;
     RECT  59.868 0.235 61.326 0.283 ;
     RECT  62.388 0.187 62.406 0.283 ;
     RECT  65.664 0.235 66.474 0.283 ;
     RECT  67.644 0.235 69.75 0.283 ;
     RECT  70.92 0.187 72.054 0.283 ;
     RECT  87.012 0.235 87.498 0.283 ;
     RECT  88.308 0.235 91.062 0.283 ;
     RECT  103.068 0.235 109.782 0.283 ;
     RECT  22.032 0.283 24.174 0.331 ;
     RECT  31.644 0.283 33.498 0.331 ;
     RECT  34.596 0.283 36.558 0.331 ;
     RECT  43.524 0.283 45.054 0.331 ;
     RECT  62.28 0.283 62.406 0.331 ;
     RECT  63.18 0.235 63.882 0.331 ;
     RECT  65.448 0.283 66.69 0.331 ;
     RECT  73.26 0.235 75.654 0.331 ;
     RECT  87.012 0.283 91.062 0.331 ;
     RECT  21.816 0.331 24.174 0.379 ;
     RECT  29.916 0.283 30.798 0.379 ;
     RECT  31.644 0.331 36.558 0.379 ;
     RECT  4.356 0.283 20.646 0.523 ;
     RECT  43.308 0.331 45.054 0.523 ;
     RECT  46.116 0.187 46.134 0.523 ;
     RECT  47.232 0.187 50.526 0.523 ;
     RECT  51.48 0.283 52.506 0.523 ;
     RECT  53.424 0.235 55.602 0.523 ;
     RECT  56.952 0.283 61.398 0.523 ;
     RECT  62.28 0.331 63.882 0.523 ;
     RECT  65.196 0.331 66.69 0.523 ;
     RECT  78.336 0.235 79.254 0.523 ;
     RECT  80.064 0.235 85.086 0.523 ;
     RECT  86.94 0.331 91.062 0.523 ;
     RECT  92.016 0.187 93.942 0.523 ;
     RECT  94.716 0.235 96.534 0.523 ;
     RECT  97.632 0.187 100.17 0.523 ;
     RECT  37.332 0.187 37.35 0.571 ;
     RECT  38.088 0.235 42.534 0.571 ;
     RECT  97.56 0.523 100.17 0.571 ;
     RECT  46.116 0.523 50.526 1.147 ;
     RECT  51.48 0.523 55.89 1.147 ;
     RECT  73.044 0.331 75.654 1.147 ;
     RECT  76.86 0.235 77.526 1.147 ;
     RECT  78.336 0.523 85.086 1.147 ;
     RECT  21.744 0.379 24.174 1.723 ;
     RECT  24.948 0.283 26.046 1.723 ;
     RECT  43.308 0.523 45.162 1.723 ;
     RECT  46.116 1.147 55.89 1.723 ;
     RECT  56.952 0.523 66.69 1.723 ;
     RECT  67.644 0.283 72.054 1.723 ;
     RECT  92.016 0.523 96.534 1.723 ;
     RECT  4.356 0.523 20.79 2.143 ;
     RECT  21.744 1.723 26.046 2.143 ;
     RECT  26.856 0.187 27.846 2.143 ;
     RECT  28.764 0.235 29.142 2.143 ;
     RECT  29.916 0.379 36.558 2.143 ;
     RECT  37.332 0.571 42.534 2.143 ;
     RECT  43.308 1.723 55.89 2.143 ;
     RECT  56.952 1.723 72.054 2.143 ;
     RECT  73.044 1.147 85.086 2.143 ;
     RECT  86.256 0.523 91.062 2.143 ;
     RECT  91.836 1.723 96.534 2.143 ;
     RECT  97.308 0.571 100.17 2.143 ;
     RECT  101.016 0.235 101.898 2.143 ;
     RECT  102.708 0.283 109.926 2.143 ;
     RECT  2.415 2.143 2.505 2.413 ;
     RECT  101.016 2.143 110.505 2.413 ;
     RECT  37.332 2.143 85.086 3.839 ;
     RECT  76.86 3.839 85.086 4.801 ;
     RECT  4.356 2.143 27.846 5.035 ;
     RECT  28.764 2.143 36.558 5.035 ;
     RECT  76.644 4.801 85.086 5.071 ;
     RECT  4.356 5.035 36.558 5.189 ;
     RECT  76.536 5.071 85.086 6.283 ;
     RECT  4.356 5.189 27.846 6.421 ;
     RECT  28.764 5.189 36.558 6.421 ;
     RECT  4.356 6.421 36.558 6.539 ;
     RECT  101.016 2.413 110.697 6.848 ;
     RECT  27.72 6.539 36.558 6.859 ;
     RECT  37.332 3.839 75.654 6.859 ;
     RECT  76.536 6.283 85.122 6.925 ;
     RECT  86.115 2.143 100.17 6.925 ;
     RECT  76.536 6.925 100.17 7.079 ;
     RECT  76.536 7.079 98.73 7.087 ;
     RECT  76.392 7.087 98.73 7.187 ;
     RECT  4.356 6.539 26.997 7.349 ;
     RECT  27.72 6.859 75.654 7.349 ;
     RECT  11.628 7.349 26.997 7.619 ;
     RECT  19.656 7.619 26.997 7.735 ;
     RECT  27.72 7.349 52.506 7.735 ;
     RECT  99.576 7.079 100.17 7.735 ;
     RECT  100.98 6.848 110.697 7.735 ;
     RECT  53.244 7.349 75.654 7.771 ;
     RECT  76.392 7.187 85.086 7.771 ;
     RECT  53.244 7.771 85.086 7.933 ;
     RECT  85.932 7.187 98.73 7.933 ;
     RECT  53.244 7.933 98.73 8.011 ;
     RECT  99.576 7.735 110.697 8.011 ;
     RECT  53.244 8.011 110.697 8.501 ;
     RECT  19.656 7.735 52.506 8.581 ;
     RECT  53.244 8.501 76.554 8.581 ;
     RECT  11.628 7.619 18.897 8.815 ;
     RECT  19.656 8.581 76.554 8.815 ;
     RECT  4.356 7.349 10.797 8.977 ;
     RECT  11.628 8.815 76.554 9.239 ;
     RECT  4.356 8.977 10.818 9.355 ;
     RECT  11.628 9.239 17.514 9.355 ;
     RECT  18.252 9.239 76.554 9.661 ;
     RECT  77.508 8.501 110.697 9.661 ;
     RECT  18.252 9.661 110.697 9.779 ;
     RECT  111.708 0.187 111.726 10.201 ;
     RECT  4.356 9.355 17.514 10.435 ;
     RECT  18.252 9.779 94.95 10.435 ;
     RECT  4.356 10.435 94.95 10.699 ;
     RECT  3.996 10.699 94.95 10.741 ;
     RECT  95.868 9.779 110.697 10.741 ;
     RECT  0.216 10.699 0.234 10.829 ;
     RECT  3.996 10.741 110.697 10.895 ;
     RECT  111.492 10.201 111.726 11.939 ;
     RECT  111.492 11.939 111.618 12.856 ;
     RECT  4.356 10.895 110.697 13.019 ;
     RECT  111.492 12.856 111.654 13.171 ;
     RECT  111.42 13.171 111.654 13.441 ;
     RECT  4.572 13.019 110.697 13.675 ;
     RECT  111.42 13.441 111.87 13.675 ;
     RECT  4.572 13.675 111.87 13.909 ;
     RECT  4.572 13.909 112.014 14.215 ;
     RECT  4.212 14.215 112.014 14.917 ;
     RECT  4.032 14.917 112.014 15.331 ;
     RECT  3.564 15.331 112.014 15.485 ;
     RECT  2.415 2.413 2.697 16.603 ;
     RECT  3.708 15.485 112.014 16.603 ;
     RECT  2.415 16.603 112.014 17.879 ;
     RECT  2.415 17.879 2.697 18.811 ;
     RECT  2.415 18.811 3.114 18.841 ;
     RECT  3.852 17.879 112.014 18.841 ;
     RECT  2.415 18.841 112.014 18.959 ;
     RECT  2.415 18.959 3.114 19.031 ;
     RECT  2.415 19.031 2.697 19.187 ;
     RECT  3.852 18.959 112.014 19.229 ;
     RECT  3.852 19.229 111.582 19.265 ;
     RECT  3.852 19.265 23.202 19.301 ;
     RECT  28.224 19.265 31.338 19.301 ;
     RECT  109.116 19.265 111.366 19.301 ;
     RECT  61.38 19.265 75.978 19.337 ;
     RECT  4.212 19.301 10.674 19.373 ;
     RECT  11.412 19.301 23.202 19.373 ;
     RECT  23.976 19.265 27.018 19.373 ;
     RECT  28.836 19.301 31.338 19.373 ;
     RECT  64.008 19.337 75.978 19.373 ;
     RECT  4.392 19.373 10.674 19.379 ;
     RECT  11.412 19.373 19.602 19.379 ;
     RECT  20.448 19.373 23.202 19.379 ;
     RECT  23.976 19.373 25.038 19.379 ;
     RECT  25.776 19.373 27.018 19.379 ;
     RECT  29.016 19.373 31.338 19.379 ;
     RECT  32.076 19.265 38.394 19.379 ;
     RECT  39.168 19.265 49.95 19.379 ;
     RECT  50.976 19.265 60.534 19.379 ;
     RECT  61.38 19.337 63.234 19.379 ;
     RECT  64.008 19.373 73.53 19.379 ;
     RECT  74.268 19.373 75.978 19.379 ;
     RECT  77.148 19.265 82.278 19.379 ;
     RECT  83.088 19.265 89.91 19.379 ;
     RECT  90.648 19.265 94.59 19.379 ;
     RECT  95.436 19.265 97.47 19.379 ;
     RECT  98.208 19.265 108.306 19.379 ;
     RECT  109.548 19.301 110.754 19.379 ;
     RECT  5.04 19.379 6.138 19.409 ;
     RECT  110.415 19.379 110.754 19.409 ;
     RECT  18.252 19.379 18.954 19.421 ;
     RECT  2.415 19.187 2.505 19.457 ;
     RECT  5.115 19.409 6.138 19.457 ;
     RECT  7.815 19.379 8.154 19.457 ;
     RECT  15.804 19.379 16.005 19.457 ;
     RECT  18.615 19.421 18.954 19.457 ;
     RECT  34.815 19.379 34.905 19.457 ;
     RECT  37.515 19.379 37.746 19.457 ;
     RECT  40.215 19.379 40.554 19.457 ;
     RECT  45.615 19.379 45.774 19.457 ;
     RECT  48.24 19.379 48.405 19.457 ;
     RECT  53.64 19.379 53.805 19.457 ;
     RECT  56.415 19.379 56.754 19.457 ;
     RECT  67.215 19.379 67.446 19.457 ;
     RECT  69.915 19.379 70.005 19.457 ;
     RECT  72.615 19.379 72.774 19.457 ;
     RECT  88.815 19.379 88.905 19.457 ;
     RECT  91.515 19.379 91.782 19.457 ;
     RECT  96.915 19.379 97.146 19.457 ;
     RECT  99.615 19.379 99.954 19.457 ;
     RECT  102.315 19.379 102.69 19.457 ;
     RECT  110.415 19.409 110.505 19.457 ;
     RECT  106.452 19.379 106.47 19.469 ;
     RECT  7.956 19.457 8.154 19.565 ;
     RECT  10.404 19.379 10.674 19.565 ;
     RECT  13.104 19.379 13.518 19.565 ;
     RECT  18.756 19.457 18.954 19.565 ;
     RECT  29.34 19.379 29.79 19.565 ;
     RECT  37.728 19.457 37.746 19.565 ;
     RECT  40.536 19.457 40.554 19.565 ;
     RECT  42.768 19.379 43.182 19.565 ;
     RECT  45.756 19.457 45.774 19.565 ;
     RECT  53.64 19.457 53.658 19.565 ;
     RECT  59.076 19.379 59.31 19.565 ;
     RECT  61.776 19.379 62.19 19.565 ;
     RECT  64.476 19.379 64.746 19.565 ;
     RECT  67.356 19.457 67.446 19.565 ;
     RECT  75.24 19.379 75.582 19.565 ;
     RECT  80.604 19.379 81.018 19.565 ;
     RECT  83.34 19.379 83.754 19.565 ;
     RECT  86.076 19.379 86.454 19.565 ;
     RECT  91.656 19.457 91.782 19.565 ;
     RECT  94.176 19.379 94.59 19.565 ;
     RECT  97.056 19.457 97.146 19.565 ;
     RECT  99.756 19.457 99.954 19.565 ;
     RECT  102.672 19.457 102.69 19.565 ;
     RECT  104.976 19.379 105.246 19.565 ;
     RECT  107.64 19.379 108.306 19.565 ;
     RECT  5.256 19.457 6.138 19.613 ;
     RECT  7.956 19.565 7.974 19.613 ;
     RECT  10.656 19.565 10.674 19.613 ;
     RECT  13.104 19.565 13.122 19.613 ;
     RECT  15.804 19.457 15.822 19.613 ;
     RECT  18.756 19.565 18.774 19.613 ;
     RECT  21.276 19.379 21.654 19.613 ;
     RECT  23.976 19.379 24.354 19.613 ;
     RECT  26.676 19.379 27.018 19.613 ;
     RECT  29.34 19.565 29.358 19.613 ;
     RECT  32.076 19.379 32.49 19.613 ;
     RECT  48.24 19.457 48.258 19.613 ;
     RECT  50.976 19.379 51.174 19.613 ;
     RECT  56.556 19.457 56.754 19.613 ;
     RECT  59.076 19.565 59.094 19.613 ;
     RECT  61.776 19.565 61.794 19.613 ;
     RECT  64.476 19.565 64.494 19.613 ;
     RECT  67.356 19.565 67.374 19.613 ;
     RECT  72.756 19.457 72.774 19.613 ;
     RECT  75.456 19.565 75.474 19.613 ;
     RECT  77.508 19.379 78.174 19.613 ;
     RECT  80.604 19.565 80.874 19.613 ;
     RECT  83.556 19.565 83.574 19.613 ;
     RECT  86.076 19.565 86.094 19.613 ;
     RECT  94.176 19.565 94.194 19.613 ;
     RECT  97.056 19.565 97.074 19.613 ;
     RECT  99.756 19.565 99.774 19.613 ;
     RECT  104.976 19.565 104.994 19.613 ;
     RECT  107.856 19.565 108.306 19.613 ;
     RECT  5.472 19.613 6.138 19.661 ;
     RECT  32.472 19.613 32.49 19.661 ;
     RECT  56.736 19.613 56.754 19.661 ;
     RECT  24.336 19.613 24.354 19.709 ;
     RECT  6.12 19.661 6.138 19.997 ;
     RECT  9.216 19.379 9.234 19.997 ;
     RECT  39.456 19.379 39.474 19.997 ;
     RECT  42.768 19.565 42.786 19.997 ;
     RECT  108.288 19.613 108.306 19.997 ;
     RECT  77.508 19.613 77.526 20.573 ;
     RECT  87.192 19.379 87.21 20.573 ;
     RECT  91.656 19.565 91.674 20.573 ;
     RECT  5.904 21.355 5.922 21.485 ;
     RECT  9.576 21.355 9.594 21.485 ;
     RECT  15.012 21.355 15.03 21.485 ;
     RECT  18.288 21.355 18.306 21.485 ;
     RECT  19.044 21.355 19.314 21.485 ;
     RECT  20.808 21.355 20.826 21.485 ;
     RECT  31.464 21.355 31.482 21.485 ;
     RECT  33.876 21.355 33.894 21.485 ;
     RECT  34.704 21.355 34.722 21.485 ;
     RECT  45.396 21.355 45.414 21.485 ;
     RECT  46.944 21.355 47.214 21.485 ;
     RECT  54.9 21.355 55.386 21.485 ;
     RECT  58.788 21.355 58.806 21.485 ;
     RECT  77.256 21.355 77.274 21.485 ;
     RECT  79.596 21.355 79.614 21.485 ;
     RECT  81.684 21.355 81.702 21.485 ;
     RECT  99.432 21.355 99.45 21.485 ;
    LAYER M4 ;
     RECT  0.205 10.704 0.245 10.824 ;
     RECT  0.245 10.704 2.408 10.728 ;
     RECT  2.408 2.148 2.512 19.452 ;
     RECT  2.512 2.418 2.704 19.182 ;
     RECT  2.704 16.608 3.733 16.632 ;
     RECT  3.733 16.56 3.877 16.632 ;
     RECT  2.704 15.456 3.925 15.48 ;
     RECT  3.877 16.56 3.925 17.16 ;
     RECT  3.925 15.456 3.985 17.16 ;
     RECT  3.985 15.456 4.021 17.352 ;
     RECT  2.704 10.704 4.025 10.728 ;
     RECT  4.021 14.928 4.057 17.352 ;
     RECT  4.057 14.928 4.237 17.688 ;
     RECT  2.704 18.816 4.237 18.84 ;
     RECT  4.237 14.928 4.381 18.84 ;
     RECT  4.381 14.928 4.453 19.368 ;
     RECT  4.301 0.192 4.604 0.216 ;
     RECT  4.604 0.192 4.835 0.552 ;
     RECT  4.669 13.056 5.108 13.08 ;
     RECT  4.453 14.256 5.108 19.368 ;
     RECT  5.108 2.148 5.125 19.452 ;
     RECT  5.125 2.148 5.212 19.608 ;
     RECT  5.212 2.418 5.404 19.608 ;
     RECT  5.404 11.424 5.42 19.608 ;
     RECT  5.845 21.36 5.893 21.384 ;
     RECT  5.893 21.36 5.933 21.48 ;
     RECT  5.933 21.456 5.977 21.48 ;
     RECT  5.42 11.424 6.005 19.656 ;
     RECT  6.005 18.768 6.109 19.656 ;
     RECT  6.109 18.768 6.265 19.992 ;
     RECT  6.265 18.816 6.371 19.992 ;
     RECT  4.835 0.192 6.939 0.312 ;
     RECT  6.939 0.192 7.049 0.36 ;
     RECT  6.005 11.424 7.297 17.784 ;
     RECT  6.371 18.816 7.297 19.368 ;
     RECT  7.297 11.424 7.333 19.368 ;
     RECT  7.525 9.792 7.808 9.816 ;
     RECT  7.333 10.848 7.808 19.368 ;
     RECT  7.808 2.148 7.861 19.452 ;
     RECT  7.049 0.192 7.985 0.312 ;
     RECT  7.861 2.148 7.985 19.608 ;
     RECT  7.985 2.148 8.104 19.56 ;
     RECT  8.104 9.792 8.129 9.816 ;
     RECT  8.104 11.712 8.165 19.56 ;
     RECT  8.389 1.728 8.849 1.752 ;
     RECT  7.985 0.192 9.164 0.264 ;
     RECT  8.165 11.712 9.205 19.368 ;
     RECT  9.164 0.192 9.251 0.552 ;
     RECT  9.205 11.712 9.313 19.992 ;
     RECT  9.541 21.36 9.565 21.384 ;
     RECT  9.565 21.36 9.628 21.48 ;
     RECT  9.628 21.456 9.649 21.48 ;
     RECT  9.313 11.376 9.923 19.992 ;
     RECT  9.923 11.376 10.069 19.656 ;
     RECT  10.069 11.136 10.213 19.656 ;
     RECT  9.251 0.192 10.321 0.312 ;
     RECT  10.321 0.192 10.364 0.504 ;
     RECT  10.364 0.192 10.451 0.552 ;
     RECT  9.397 9.12 10.508 9.144 ;
     RECT  10.213 10.272 10.508 19.656 ;
     RECT  10.508 2.148 10.612 19.656 ;
     RECT  10.451 0.192 10.787 0.504 ;
     RECT  10.612 2.418 10.787 19.656 ;
     RECT  10.787 2.418 10.804 19.368 ;
     RECT  10.804 11.664 11.893 19.368 ;
     RECT  10.787 0.192 11.945 0.36 ;
     RECT  11.893 11.424 11.987 19.368 ;
     RECT  11.945 0.192 12.053 0.312 ;
     RECT  11.987 11.424 12.181 16.632 ;
     RECT  12.085 9.12 12.229 9.144 ;
     RECT  12.053 0.192 12.233 0.264 ;
     RECT  12.229 8.496 12.277 9.144 ;
     RECT  12.181 11.232 12.757 16.632 ;
     RECT  12.757 10.32 12.997 16.632 ;
     RECT  11.987 17.616 12.997 19.368 ;
     RECT  12.997 10.32 13.093 19.368 ;
     RECT  13.141 1.728 13.208 1.752 ;
     RECT  12.277 7.968 13.208 9.144 ;
     RECT  13.093 10.32 13.208 19.608 ;
     RECT  12.233 0.192 13.285 0.216 ;
     RECT  13.208 1.728 13.504 19.608 ;
     RECT  13.285 0.192 13.589 0.264 ;
     RECT  13.504 18.768 13.619 19.608 ;
     RECT  13.504 10.896 13.637 17.736 ;
     RECT  13.637 11.376 13.825 17.736 ;
     RECT  13.504 1.728 14.141 1.752 ;
     RECT  13.589 0.192 14.293 0.312 ;
     RECT  14.293 0.192 14.429 0.408 ;
     RECT  13.825 11.712 14.561 17.736 ;
     RECT  13.619 18.768 14.561 19.368 ;
     RECT  14.561 11.712 14.915 19.368 ;
     RECT  14.965 21.36 15.001 21.384 ;
     RECT  15.001 21.36 15.052 21.48 ;
     RECT  15.052 21.456 15.085 21.48 ;
     RECT  14.915 14.928 15.749 19.368 ;
     RECT  15.749 14.928 15.788 19.512 ;
     RECT  14.915 11.712 15.793 13.896 ;
     RECT  14.965 8.544 15.908 8.568 ;
     RECT  15.793 11.664 15.908 13.896 ;
     RECT  15.788 14.928 15.908 19.608 ;
     RECT  14.429 0.192 16.012 0.216 ;
     RECT  15.908 2.148 16.012 19.608 ;
     RECT  16.012 2.418 16.165 19.608 ;
     RECT  16.165 2.418 16.204 19.704 ;
     RECT  16.204 10.512 16.357 19.704 ;
     RECT  16.357 10.512 16.499 19.8 ;
     RECT  16.499 10.512 16.547 19.368 ;
     RECT  16.547 10.512 16.643 12.072 ;
     RECT  16.012 0.192 16.652 0.264 ;
     RECT  16.652 0.192 17.219 0.552 ;
     RECT  17.219 0.192 17.453 0.36 ;
     RECT  16.643 10.512 17.557 10.968 ;
     RECT  16.643 11.952 17.845 12.072 ;
     RECT  16.547 13.056 17.845 19.368 ;
     RECT  17.557 10.416 18.037 10.968 ;
     RECT  17.845 11.952 18.037 19.368 ;
     RECT  18.037 10.416 18.085 19.368 ;
     RECT  18.085 10.32 18.241 19.368 ;
     RECT  18.229 21.36 18.277 21.384 ;
     RECT  18.277 21.36 18.565 21.48 ;
     RECT  18.241 10.32 18.608 19.416 ;
     RECT  18.608 2.148 18.709 19.452 ;
     RECT  18.565 20.544 18.709 21.48 ;
     RECT  18.709 2.148 18.712 21.48 ;
     RECT  18.712 2.304 18.796 21.48 ;
     RECT  18.796 2.304 18.904 19.56 ;
     RECT  18.904 10.32 18.988 19.56 ;
     RECT  18.988 10.32 19.001 19.368 ;
     RECT  18.796 20.544 19.369 21.48 ;
     RECT  19.369 20.544 19.475 20.568 ;
     RECT  17.453 0.192 19.54 0.264 ;
     RECT  18.904 2.304 19.721 2.328 ;
     RECT  19.54 0.192 20.053 0.312 ;
     RECT  19.001 10.32 20.117 10.968 ;
     RECT  20.117 10.896 20.653 10.968 ;
     RECT  19.001 12 20.653 19.368 ;
     RECT  20.053 0.192 20.732 0.36 ;
     RECT  20.773 21.36 20.797 21.384 ;
     RECT  20.732 0.192 20.819 0.552 ;
     RECT  20.797 21.36 20.86 21.48 ;
     RECT  20.86 21.456 20.881 21.48 ;
     RECT  20.653 10.896 21.253 19.368 ;
     RECT  20.389 6.864 21.308 6.888 ;
     RECT  21.253 10.896 21.308 19.608 ;
     RECT  21.308 2.148 21.412 19.608 ;
     RECT  21.412 2.418 21.604 19.608 ;
     RECT  21.604 10.944 21.665 19.608 ;
     RECT  20.819 0.192 21.773 0.408 ;
     RECT  21.773 0.192 22.601 0.36 ;
     RECT  21.665 10.944 23.125 19.368 ;
     RECT  23.125 10.896 23.245 19.368 ;
     RECT  22.601 0.192 23.363 0.312 ;
     RECT  23.245 10.8 23.372 19.368 ;
     RECT  23.372 10.752 23.653 19.368 ;
     RECT  21.604 9.12 23.797 9.144 ;
     RECT  23.653 10.32 23.948 19.368 ;
     RECT  23.989 1.728 24.008 1.752 ;
     RECT  22.933 6.288 24.008 6.312 ;
     RECT  22.789 7.968 24.008 7.992 ;
     RECT  23.797 9.12 24.008 9.288 ;
     RECT  23.948 10.32 24.008 19.608 ;
     RECT  24.008 1.728 24.284 19.608 ;
     RECT  24.284 1.728 24.304 19.704 ;
     RECT  24.304 9.264 24.329 9.288 ;
     RECT  24.304 10.32 24.371 19.704 ;
     RECT  24.371 10.32 24.419 19.608 ;
     RECT  24.419 10.32 24.515 19.368 ;
     RECT  24.515 10.32 24.545 15.336 ;
     RECT  23.363 0.192 24.805 0.264 ;
     RECT  24.304 1.728 24.833 1.752 ;
     RECT  24.805 0.192 24.997 0.312 ;
     RECT  24.997 0.192 25.292 0.36 ;
     RECT  25.292 0.192 25.379 0.552 ;
     RECT  24.545 10.944 25.573 15.336 ;
     RECT  24.515 16.512 25.573 19.368 ;
     RECT  25.669 6.864 25.861 6.888 ;
     RECT  25.573 10.944 26.149 19.368 ;
     RECT  26.149 10.512 26.197 19.368 ;
     RECT  26.197 9.792 26.341 19.368 ;
     RECT  25.379 0.192 26.581 0.264 ;
     RECT  26.341 9.264 26.636 19.368 ;
     RECT  25.861 6.864 26.708 7.464 ;
     RECT  26.636 9.264 26.708 19.608 ;
     RECT  26.708 2.148 27.004 19.608 ;
     RECT  27.004 9.648 27.059 19.608 ;
     RECT  27.059 9.648 27.155 19.56 ;
     RECT  27.205 1.728 27.353 1.752 ;
     RECT  27.155 9.648 27.389 19.032 ;
     RECT  26.581 0.192 27.443 0.312 ;
     RECT  27.389 10.272 28.213 19.032 ;
     RECT  27.004 7.44 28.549 8.184 ;
     RECT  28.213 10.272 28.741 19.128 ;
     RECT  27.443 0.192 29.173 0.264 ;
     RECT  28.741 10.272 29.329 19.368 ;
     RECT  28.549 6.288 29.408 6.312 ;
     RECT  28.549 7.44 29.408 9.096 ;
     RECT  29.329 10.272 29.408 19.608 ;
     RECT  29.408 2.148 29.459 19.608 ;
     RECT  29.459 2.148 29.512 19.56 ;
     RECT  29.512 2.418 29.704 19.56 ;
     RECT  29.173 0.192 29.749 0.312 ;
     RECT  29.704 10.32 29.765 19.56 ;
     RECT  29.765 10.848 29.836 19.56 ;
     RECT  29.749 0.192 30.229 0.36 ;
     RECT  29.836 10.848 30.521 19.368 ;
     RECT  30.521 13.056 30.629 19.368 ;
     RECT  30.565 1.728 30.773 1.752 ;
     RECT  30.521 10.848 30.809 12.024 ;
     RECT  30.229 0.192 31.052 0.408 ;
     RECT  30.757 21.36 31.453 21.384 ;
     RECT  31.052 0.192 31.475 0.552 ;
     RECT  31.453 21.36 31.516 21.48 ;
     RECT  31.516 21.456 31.537 21.48 ;
     RECT  30.629 13.056 31.669 13.704 ;
     RECT  31.669 13.008 31.861 13.704 ;
     RECT  30.629 14.784 31.861 19.368 ;
     RECT  30.809 10.944 31.957 12.024 ;
     RECT  31.861 13.008 31.957 19.368 ;
     RECT  31.957 10.944 32.06 19.368 ;
     RECT  29.704 7.44 32.108 7.464 ;
     RECT  31.285 8.736 32.108 8.76 ;
     RECT  32.06 10.944 32.108 19.608 ;
     RECT  32.108 2.148 32.212 19.608 ;
     RECT  32.212 2.418 32.404 19.608 ;
     RECT  31.475 0.192 32.437 0.264 ;
     RECT  32.404 10.944 32.437 19.608 ;
     RECT  32.437 10.944 32.524 19.656 ;
     RECT  32.437 0.192 32.965 0.312 ;
     RECT  32.524 10.944 33.113 19.368 ;
     RECT  33.301 1.728 33.617 1.752 ;
     RECT  33.113 10.944 33.637 17.208 ;
     RECT  33.829 21.36 33.865 21.384 ;
     RECT  32.404 7.44 33.973 7.992 ;
     RECT  32.965 0.192 34.268 0.36 ;
     RECT  34.268 0.192 34.355 0.552 ;
     RECT  33.637 10.272 34.412 17.208 ;
     RECT  33.113 18.192 34.412 19.368 ;
     RECT  33.865 21.36 34.733 21.48 ;
     RECT  34.733 21.456 34.739 21.48 ;
     RECT  34.645 5.712 34.808 5.736 ;
     RECT  33.973 7.44 34.808 8.568 ;
     RECT  34.412 10.272 34.808 19.368 ;
     RECT  34.808 2.148 34.837 19.452 ;
     RECT  34.837 2.148 34.912 19.608 ;
     RECT  34.912 2.418 34.981 19.608 ;
     RECT  34.981 2.418 35.104 19.704 ;
     RECT  35.104 10.944 35.173 19.704 ;
     RECT  35.173 10.944 35.315 19.8 ;
     RECT  35.315 10.944 35.363 19.368 ;
     RECT  34.355 0.192 35.449 0.312 ;
     RECT  35.449 0.192 35.699 0.552 ;
     RECT  35.363 11.328 35.788 19.368 ;
     RECT  35.699 0.192 35.957 0.36 ;
     RECT  35.104 5.712 36.533 5.736 ;
     RECT  36.373 10.272 36.86 10.296 ;
     RECT  35.788 11.376 36.86 19.368 ;
     RECT  35.957 0.192 37.189 0.312 ;
     RECT  36.86 10.272 37.333 19.368 ;
     RECT  35.104 6.864 37.508 6.888 ;
     RECT  36.709 8.544 37.508 8.568 ;
     RECT  37.333 10.272 37.508 19.608 ;
     RECT  37.508 2.148 37.571 19.608 ;
     RECT  37.571 2.148 37.612 19.56 ;
     RECT  37.189 0.192 37.685 0.6 ;
     RECT  37.612 2.418 37.804 19.56 ;
     RECT  37.804 11.424 38.003 19.56 ;
     RECT  37.804 10.224 38.051 10.248 ;
     RECT  37.685 0.192 38.627 0.456 ;
     RECT  38.924 8.88 39.011 8.904 ;
     RECT  38.917 10.272 39.121 10.296 ;
     RECT  38.003 11.424 39.121 19.368 ;
     RECT  39.121 10.272 39.445 19.368 ;
     RECT  38.627 0.192 39.779 0.408 ;
     RECT  40.049 1.728 40.133 1.752 ;
     RECT  37.804 6.288 40.208 6.312 ;
     RECT  39.397 8.544 40.208 8.568 ;
     RECT  39.445 10.272 40.208 19.992 ;
     RECT  40.208 2.148 40.307 19.992 ;
     RECT  40.307 2.148 40.312 19.56 ;
     RECT  40.312 2.418 40.504 19.56 ;
     RECT  40.504 9.12 40.565 19.56 ;
     RECT  40.565 9.12 40.835 19.368 ;
     RECT  39.779 0.192 40.933 0.264 ;
     RECT  40.933 0.192 41.093 0.312 ;
     RECT  41.093 0.192 41.228 0.36 ;
     RECT  41.228 0.192 41.315 0.552 ;
     RECT  40.835 9.12 41.321 9.144 ;
     RECT  40.835 10.272 41.897 19.368 ;
     RECT  41.315 0.192 41.933 0.312 ;
     RECT  41.897 10.512 42.757 19.368 ;
     RECT  42.613 6 42.908 6.024 ;
     RECT  40.504 8.016 42.908 8.04 ;
     RECT  41.941 9.264 42.908 9.288 ;
     RECT  42.757 10.512 42.908 19.992 ;
     RECT  41.933 0.192 42.949 0.216 ;
     RECT  42.908 2.148 42.995 19.992 ;
     RECT  42.995 2.148 43.012 19.56 ;
     RECT  42.949 0.192 43.141 0.36 ;
     RECT  43.012 2.418 43.204 19.56 ;
     RECT  43.204 14.64 43.228 19.56 ;
     RECT  43.141 0.192 43.628 0.408 ;
     RECT  43.628 0.192 43.715 0.552 ;
     RECT  43.204 5.712 44.561 5.736 ;
     RECT  43.204 10.992 44.773 13.656 ;
     RECT  43.228 14.64 44.773 19.368 ;
     RECT  44.677 7.968 44.821 7.992 ;
     RECT  43.715 0.192 45.116 0.264 ;
     RECT  44.821 7.968 45.133 8.568 ;
     RECT  44.773 10.992 45.164 19.368 ;
     RECT  45.116 0.192 45.203 0.552 ;
     RECT  45.349 21.36 45.385 21.384 ;
     RECT  45.385 21.36 45.436 21.48 ;
     RECT  45.436 21.456 45.469 21.48 ;
     RECT  45.133 7.968 45.493 9.144 ;
     RECT  45.349 1.728 45.608 1.752 ;
     RECT  45.493 7.44 45.608 9.144 ;
     RECT  45.164 10.752 45.608 19.368 ;
     RECT  45.608 1.728 45.685 19.452 ;
     RECT  45.685 1.728 45.904 19.608 ;
     RECT  45.904 10.848 46.019 19.608 ;
     RECT  46.019 14.64 46.021 19.608 ;
     RECT  46.021 14.64 46.163 19.704 ;
     RECT  45.203 0.192 46.172 0.264 ;
     RECT  45.904 7.44 46.217 7.464 ;
     RECT  45.904 1.728 46.325 1.752 ;
     RECT  46.019 10.848 46.361 13.32 ;
     RECT  46.172 0.192 46.885 0.552 ;
     RECT  46.885 21.36 46.933 21.384 ;
     RECT  46.885 0.192 46.973 0.6 ;
     RECT  45.904 5.712 46.973 5.736 ;
     RECT  46.973 0.192 47.075 0.552 ;
     RECT  46.361 10.848 47.117 12.936 ;
     RECT  47.117 11.376 47.123 12.936 ;
     RECT  47.113 9.072 47.197 9.096 ;
     RECT  46.933 21.36 47.225 21.48 ;
     RECT  47.225 21.36 47.267 21.384 ;
     RECT  46.163 14.64 47.269 19.368 ;
     RECT  47.557 7.968 48.037 7.992 ;
     RECT  47.123 11.376 48.085 12.792 ;
     RECT  48.085 11.376 48.181 13.128 ;
     RECT  47.269 14.352 48.181 19.368 ;
     RECT  48.221 1.728 48.305 1.752 ;
     RECT  47.365 6 48.308 6.024 ;
     RECT  48.037 7.44 48.308 7.992 ;
     RECT  48.181 11.376 48.308 19.704 ;
     RECT  48.308 2.148 48.412 19.704 ;
     RECT  47.075 0.192 48.419 0.312 ;
     RECT  48.412 2.418 48.419 19.704 ;
     RECT  48.419 2.418 48.604 19.56 ;
     RECT  48.604 7.44 48.773 7.992 ;
     RECT  48.773 7.968 48.845 7.992 ;
     RECT  48.604 11.472 48.851 19.56 ;
     RECT  48.419 0.192 49.388 0.264 ;
     RECT  48.604 9.648 49.421 9.672 ;
     RECT  49.388 0.192 49.573 0.552 ;
     RECT  49.573 0.192 49.745 0.6 ;
     RECT  48.851 11.472 50.437 19.368 ;
     RECT  50.437 10.848 50.924 19.368 ;
     RECT  49.745 0.192 50.965 0.264 ;
     RECT  50.581 9.696 51.008 9.72 ;
     RECT  50.924 10.848 51.008 19.608 ;
     RECT  50.965 0.192 51.109 1.176 ;
     RECT  51.008 2.148 51.109 19.608 ;
     RECT  51.109 0.192 51.185 19.608 ;
     RECT  51.185 1.728 51.196 19.608 ;
     RECT  51.196 1.728 51.304 19.56 ;
     RECT  51.304 10.224 51.443 19.56 ;
     RECT  51.304 1.728 51.653 1.752 ;
     RECT  51.443 10.224 52.121 19.368 ;
     RECT  52.121 10.272 52.259 19.368 ;
     RECT  51.185 0.192 52.268 0.312 ;
     RECT  52.268 0.192 52.355 1.128 ;
     RECT  51.304 6.864 52.789 6.888 ;
     RECT  51.304 7.968 52.789 7.992 ;
     RECT  52.355 0.192 53.027 0.552 ;
     RECT  52.259 10.272 53.305 10.296 ;
     RECT  52.259 11.328 53.305 19.368 ;
     RECT  53.305 10.272 53.317 19.368 ;
     RECT  52.789 6.864 53.509 7.992 ;
     RECT  53.317 9.792 53.557 19.368 ;
     RECT  53.509 6.864 53.708 8.04 ;
     RECT  53.557 9.792 53.708 19.608 ;
     RECT  53.708 2.148 53.812 19.608 ;
     RECT  53.812 2.418 54.004 19.608 ;
     RECT  54.004 6.96 54.065 8.04 ;
     RECT  54.004 9.792 54.131 19.608 ;
     RECT  54.065 8.016 54.173 8.04 ;
     RECT  53.027 0.192 54.284 0.312 ;
     RECT  54.853 21.36 54.889 21.384 ;
     RECT  54.131 9.792 55.244 19.368 ;
     RECT  55.244 9.504 55.331 19.368 ;
     RECT  54.889 21.36 55.42 21.48 ;
     RECT  55.42 21.456 55.441 21.48 ;
     RECT  54.284 0.192 55.907 0.552 ;
     RECT  55.525 8.544 56.185 8.568 ;
     RECT  54.065 6.96 56.197 6.984 ;
     RECT  55.331 9.648 56.389 19.368 ;
     RECT  55.669 5.136 56.408 5.16 ;
     RECT  56.197 6.96 56.408 7.464 ;
     RECT  56.185 8.496 56.408 8.568 ;
     RECT  56.389 9.648 56.408 19.608 ;
     RECT  56.408 2.148 56.512 19.608 ;
     RECT  56.512 2.418 56.533 19.608 ;
     RECT  56.533 2.418 56.704 19.656 ;
     RECT  56.704 10.704 56.765 19.656 ;
     RECT  56.765 10.704 56.819 19.56 ;
     RECT  56.819 10.8 56.867 19.56 ;
     RECT  55.907 0.192 56.869 0.312 ;
     RECT  56.867 10.8 57.011 19.368 ;
     RECT  56.704 8.544 57.053 8.568 ;
     RECT  56.869 0.192 57.061 0.36 ;
     RECT  57.061 0.192 57.197 0.6 ;
     RECT  56.704 7.44 57.377 7.464 ;
     RECT  57.011 10.848 57.587 19.368 ;
     RECT  57.805 6.816 57.889 6.84 ;
     RECT  57.197 0.192 57.989 0.36 ;
     RECT  57.587 10.848 58.405 13.656 ;
     RECT  58.741 21.36 58.777 21.384 ;
     RECT  58.405 10.272 58.813 13.656 ;
     RECT  57.587 14.832 58.813 19.368 ;
     RECT  58.777 21.36 58.828 21.48 ;
     RECT  58.828 21.456 58.861 21.48 ;
     RECT  58.813 10.272 59.036 19.368 ;
     RECT  57.989 0.192 59.077 0.312 ;
     RECT  58.597 5.712 59.108 5.736 ;
     RECT  59.036 10.272 59.108 19.608 ;
     RECT  59.108 2.148 59.123 19.608 ;
     RECT  59.123 2.148 59.212 19.56 ;
     RECT  59.212 2.418 59.404 19.56 ;
     RECT  59.077 0.192 59.537 0.6 ;
     RECT  59.404 11.232 59.555 19.56 ;
     RECT  59.537 0.192 60.949 0.408 ;
     RECT  59.555 11.232 61.141 19.368 ;
     RECT  60.949 0.192 61.373 1.176 ;
     RECT  61.141 10.272 61.765 19.368 ;
     RECT  61.765 10.272 61.808 19.608 ;
     RECT  61.373 0.192 61.859 0.552 ;
     RECT  61.808 2.148 61.859 19.608 ;
     RECT  61.859 2.148 61.912 19.56 ;
     RECT  61.912 2.418 62.104 19.56 ;
     RECT  62.104 10.944 62.236 19.56 ;
     RECT  62.236 10.944 62.561 19.368 ;
     RECT  62.104 5.712 62.777 5.736 ;
     RECT  61.859 0.192 62.813 0.36 ;
     RECT  63.157 7.44 63.425 7.464 ;
     RECT  62.561 11.136 63.961 19.368 ;
     RECT  63.961 10.704 64.076 19.368 ;
     RECT  64.076 10.512 64.357 19.368 ;
     RECT  62.813 0.192 64.46 0.312 ;
     RECT  64.357 10.32 64.46 19.368 ;
     RECT  64.021 6.288 64.508 6.312 ;
     RECT  64.46 10.32 64.508 19.608 ;
     RECT  64.508 2.148 64.547 19.608 ;
     RECT  64.547 2.148 64.612 19.56 ;
     RECT  64.46 0.192 64.739 0.552 ;
     RECT  64.612 2.418 64.804 19.56 ;
     RECT  64.804 7.92 64.931 7.944 ;
     RECT  64.804 9.696 64.979 19.56 ;
     RECT  64.804 6.288 65.369 6.36 ;
     RECT  64.979 9.696 65.369 19.368 ;
     RECT  64.739 0.192 66.053 0.36 ;
     RECT  65.369 9.696 66.565 9.72 ;
     RECT  65.369 10.8 67.052 19.368 ;
     RECT  66.709 1.728 67.208 1.752 ;
     RECT  65.369 6.336 67.208 6.36 ;
     RECT  66.565 9.264 67.208 9.72 ;
     RECT  67.052 10.752 67.208 19.368 ;
     RECT  67.208 1.728 67.237 19.452 ;
     RECT  67.237 1.728 67.385 19.608 ;
     RECT  67.385 1.728 67.468 19.56 ;
     RECT  67.468 1.728 67.504 19.368 ;
     RECT  66.053 0.192 67.717 0.312 ;
     RECT  67.717 0.192 67.889 0.36 ;
     RECT  67.504 1.728 68.177 1.752 ;
     RECT  67.504 10.8 68.533 19.368 ;
     RECT  68.533 10.512 68.924 19.368 ;
     RECT  67.889 0.192 69.068 0.312 ;
     RECT  68.924 10.224 69.733 19.368 ;
     RECT  69.068 0.192 69.827 0.552 ;
     RECT  68.581 9.12 69.908 9.144 ;
     RECT  69.733 10.224 69.908 19.608 ;
     RECT  69.908 2.148 70.204 19.608 ;
     RECT  70.204 10.416 70.261 19.608 ;
     RECT  70.261 10.416 70.403 19.656 ;
     RECT  70.789 1.728 71.237 1.752 ;
     RECT  71.197 8.496 71.281 8.52 ;
     RECT  70.403 10.416 71.317 19.368 ;
     RECT  69.827 0.192 71.597 0.36 ;
     RECT  71.317 9.696 72.373 19.368 ;
     RECT  72.133 5.184 72.608 5.208 ;
     RECT  71.461 7.44 72.608 7.464 ;
     RECT  72.373 9.696 72.608 19.56 ;
     RECT  72.608 2.148 72.661 19.56 ;
     RECT  72.661 2.148 72.712 19.608 ;
     RECT  72.712 2.418 72.785 19.608 ;
     RECT  72.785 2.418 72.851 19.56 ;
     RECT  72.851 2.418 72.904 19.368 ;
     RECT  71.597 0.192 72.989 0.312 ;
     RECT  72.904 5.184 73.037 5.208 ;
     RECT  72.904 10.608 73.109 19.368 ;
     RECT  73.109 11.04 73.139 19.368 ;
     RECT  72.989 0.192 73.333 0.36 ;
     RECT  73.333 0.192 73.537 0.408 ;
     RECT  73.537 0.192 73.715 0.552 ;
     RECT  73.139 11.232 73.901 19.368 ;
     RECT  73.901 11.232 74.869 17.064 ;
     RECT  73.901 18.24 74.869 19.368 ;
     RECT  74.869 11.232 75.013 19.368 ;
     RECT  73.715 0.192 75.157 0.408 ;
     RECT  75.013 10.848 75.205 19.368 ;
     RECT  74.869 5.712 75.308 5.736 ;
     RECT  74.197 7.44 75.308 7.464 ;
     RECT  74.005 9.12 75.308 9.144 ;
     RECT  75.205 10.848 75.308 19.56 ;
     RECT  75.308 2.148 75.349 19.56 ;
     RECT  75.349 2.148 75.412 19.608 ;
     RECT  75.412 2.418 75.485 19.608 ;
     RECT  75.485 2.418 75.604 19.56 ;
     RECT  75.604 10.224 75.628 19.56 ;
     RECT  75.628 10.224 75.731 19.368 ;
     RECT  75.604 6.864 75.827 6.888 ;
     RECT  75.731 10.848 75.853 19.368 ;
     RECT  75.157 0.192 76.021 0.552 ;
     RECT  75.853 10.896 76.067 19.368 ;
     RECT  76.021 0.192 76.205 1.176 ;
     RECT  76.067 10.896 77.077 19.128 ;
     RECT  76.205 0.192 77.228 0.312 ;
     RECT  77.221 21.36 77.245 21.384 ;
     RECT  77.245 21.36 77.329 21.48 ;
     RECT  77.228 0.192 77.557 0.36 ;
     RECT  77.497 20.544 77.603 20.568 ;
     RECT  77.557 0.192 77.749 1.176 ;
     RECT  77.749 0.192 77.825 1.752 ;
     RECT  77.825 1.728 78.008 1.752 ;
     RECT  77.413 7.968 78.008 7.992 ;
     RECT  77.077 10.896 78.008 19.368 ;
     RECT  78.008 1.728 78.085 19.452 ;
     RECT  78.085 1.728 78.185 19.608 ;
     RECT  78.185 1.728 78.304 19.56 ;
     RECT  78.304 10.512 78.419 19.56 ;
     RECT  77.825 0.192 78.908 0.312 ;
     RECT  78.304 1.728 79.157 1.752 ;
     RECT  78.419 10.512 79.292 19.368 ;
     RECT  79.292 10.224 79.379 19.368 ;
     RECT  79.541 21.456 79.58 21.48 ;
     RECT  79.58 21.36 79.625 21.48 ;
     RECT  79.625 21.36 79.667 21.384 ;
     RECT  78.908 0.192 79.811 0.552 ;
     RECT  79.379 10.8 80.549 19.368 ;
     RECT  80.549 10.8 80.588 19.512 ;
     RECT  80.293 5.712 80.708 5.736 ;
     RECT  80.101 6.864 80.708 6.888 ;
     RECT  80.588 10.8 80.708 19.608 ;
     RECT  80.708 2.148 80.812 19.608 ;
     RECT  80.812 2.418 80.885 19.608 ;
     RECT  80.885 2.418 81.004 19.56 ;
     RECT  81.004 11.04 81.052 19.56 ;
     RECT  79.811 0.192 81.109 0.264 ;
     RECT  81.637 21.36 81.673 21.384 ;
     RECT  81.673 21.36 81.724 21.48 ;
     RECT  81.724 21.456 81.757 21.48 ;
     RECT  81.052 11.04 81.785 19.368 ;
     RECT  82.105 9.648 82.189 9.672 ;
     RECT  81.109 0.192 82.253 0.6 ;
     RECT  82.321 9.072 82.405 9.096 ;
     RECT  81.785 11.04 82.465 14.952 ;
     RECT  82.309 1.728 82.649 1.752 ;
     RECT  82.465 10.848 82.897 14.952 ;
     RECT  81.785 15.984 82.897 19.368 ;
     RECT  82.165 8.016 82.981 8.04 ;
     RECT  82.897 10.848 83.317 19.368 ;
     RECT  82.981 7.44 83.408 8.04 ;
     RECT  83.221 9.504 83.408 9.528 ;
     RECT  83.317 10.848 83.408 19.56 ;
     RECT  82.253 0.192 83.501 0.216 ;
     RECT  83.408 2.148 83.509 19.56 ;
     RECT  83.509 2.148 83.512 19.608 ;
     RECT  83.512 2.418 83.596 19.608 ;
     RECT  83.596 2.418 83.704 19.56 ;
     RECT  83.704 10.704 83.765 19.56 ;
     RECT  83.765 10.704 83.837 19.368 ;
     RECT  83.501 0.192 84.037 0.264 ;
     RECT  83.837 17.136 84.197 19.368 ;
     RECT  83.837 10.704 84.275 16.056 ;
     RECT  84.037 0.192 84.449 0.312 ;
     RECT  83.704 7.968 84.953 7.992 ;
     RECT  84.449 0.192 85.025 0.264 ;
     RECT  85.025 0.24 85.097 0.264 ;
     RECT  83.704 6.288 85.133 6.312 ;
     RECT  83.704 9.696 85.165 9.72 ;
     RECT  84.275 10.704 85.165 10.92 ;
     RECT  84.275 12 85.453 16.056 ;
     RECT  84.197 17.472 85.453 19.368 ;
     RECT  85.165 9.696 85.525 10.92 ;
     RECT  85.525 9.696 85.628 10.968 ;
     RECT  85.453 12 85.628 19.368 ;
     RECT  85.628 9.696 86.053 19.368 ;
     RECT  85.717 8.16 86.108 8.184 ;
     RECT  86.053 9.696 86.108 19.608 ;
     RECT  86.053 0.192 86.204 0.216 ;
     RECT  86.204 0.192 86.291 0.552 ;
     RECT  86.108 2.148 86.404 19.608 ;
     RECT  86.404 10.704 86.429 19.608 ;
     RECT  86.429 10.896 86.531 19.608 ;
     RECT  86.531 10.896 86.689 19.368 ;
     RECT  86.581 1.728 86.717 1.752 ;
     RECT  86.291 0.192 87.113 0.36 ;
     RECT  87.181 20.544 87.299 20.568 ;
     RECT  86.689 10.896 87.397 17.688 ;
     RECT  87.113 0.192 87.689 0.312 ;
     RECT  87.397 10.272 87.733 17.688 ;
     RECT  86.689 18.816 87.733 19.368 ;
     RECT  87.505 8.496 87.779 8.52 ;
     RECT  87.733 10.272 88.693 19.368 ;
     RECT  87.589 5.712 88.808 5.736 ;
     RECT  88.261 8.544 88.808 8.568 ;
     RECT  88.693 10.272 88.808 19.608 ;
     RECT  87.689 0.192 88.933 0.216 ;
     RECT  88.808 2.148 89.104 19.608 ;
     RECT  88.933 0.192 89.125 0.264 ;
     RECT  89.104 11.232 89.125 19.608 ;
     RECT  89.125 11.232 89.267 19.704 ;
     RECT  89.269 1.728 89.561 1.752 ;
     RECT  89.267 11.232 89.603 19.368 ;
     RECT  89.603 11.76 89.633 19.368 ;
     RECT  89.633 11.76 89.891 14.424 ;
     RECT  89.125 0.192 89.941 0.312 ;
     RECT  89.941 0.192 90.245 0.36 ;
     RECT  89.104 6.864 90.461 6.888 ;
     RECT  89.891 12.048 90.668 14.424 ;
     RECT  89.633 15.6 90.668 19.368 ;
     RECT  90.805 10.896 91.093 10.92 ;
     RECT  90.668 12.048 91.093 19.368 ;
     RECT  91.093 10.896 91.381 19.368 ;
     RECT  91.333 1.728 91.508 1.752 ;
     RECT  90.469 5.136 91.508 5.16 ;
     RECT  91.141 8.544 91.508 8.568 ;
     RECT  91.381 10.896 91.508 19.608 ;
     RECT  91.508 1.728 91.523 19.608 ;
     RECT  90.245 0.192 91.669 0.264 ;
     RECT  91.523 1.728 91.793 19.56 ;
     RECT  91.793 1.728 91.804 19.368 ;
     RECT  91.645 20.544 91.859 20.568 ;
     RECT  91.804 1.728 91.865 1.752 ;
     RECT  91.804 8.544 92.045 8.568 ;
     RECT  91.669 0.192 92.153 0.6 ;
     RECT  91.804 9.936 92.771 9.96 ;
     RECT  91.804 11.376 92.869 19.368 ;
     RECT  92.869 11.328 92.905 19.368 ;
     RECT  92.153 0.192 93.053 0.408 ;
     RECT  92.905 11.184 93.061 19.368 ;
     RECT  93.053 0.192 94.165 0.36 ;
     RECT  93.061 10.224 94.165 19.368 ;
     RECT  92.821 7.44 94.208 7.464 ;
     RECT  94.165 10.224 94.208 19.608 ;
     RECT  94.208 2.148 94.259 19.608 ;
     RECT  94.259 2.148 94.312 19.56 ;
     RECT  94.165 0.192 94.429 0.552 ;
     RECT  94.312 2.418 94.504 19.56 ;
     RECT  94.504 10.608 94.636 19.56 ;
     RECT  94.429 0.192 95.285 0.312 ;
     RECT  94.504 8.976 95.321 9 ;
     RECT  94.636 10.608 96.565 19.368 ;
     RECT  96.565 10.32 96.901 19.368 ;
     RECT  95.893 6.288 96.908 6.312 ;
     RECT  96.421 8.544 96.908 8.568 ;
     RECT  96.901 10.32 96.908 19.608 ;
     RECT  96.908 2.148 97.085 19.608 ;
     RECT  95.285 0.192 97.093 0.264 ;
     RECT  97.085 2.148 97.204 19.56 ;
     RECT  97.093 0.192 97.237 0.312 ;
     RECT  97.237 0.192 97.337 0.6 ;
     RECT  97.204 10.608 97.379 19.56 ;
     RECT  97.204 8.016 97.481 8.568 ;
     RECT  97.379 10.608 97.481 19.368 ;
     RECT  97.337 0.192 97.619 0.552 ;
     RECT  97.481 10.704 97.625 19.368 ;
     RECT  97.429 1.728 97.805 1.752 ;
     RECT  97.619 0.192 98.629 0.312 ;
     RECT  97.481 8.016 99.109 8.04 ;
     RECT  97.625 10.8 99.277 19.368 ;
     RECT  99.377 21.456 99.404 21.48 ;
     RECT  99.404 21.36 99.461 21.48 ;
     RECT  99.461 21.36 99.491 21.384 ;
     RECT  99.277 10.704 99.493 19.368 ;
     RECT  99.109 8.016 99.608 8.568 ;
     RECT  99.493 9.792 99.608 19.368 ;
     RECT  99.608 2.148 99.637 19.452 ;
     RECT  99.637 2.148 99.712 19.608 ;
     RECT  99.712 2.418 99.785 19.608 ;
     RECT  98.629 0.192 99.827 0.552 ;
     RECT  99.785 2.418 99.904 19.56 ;
     RECT  99.904 9.12 99.965 19.56 ;
     RECT  99.965 9.12 100.115 19.368 ;
     RECT  100.115 9.12 100.145 13.656 ;
     RECT  100.145 10.704 100.163 13.656 ;
     RECT  100.163 10.704 100.538 13.608 ;
     RECT  100.538 10.752 100.787 13.608 ;
     RECT  100.145 9.12 100.937 9.144 ;
     RECT  99.904 6.864 101.009 6.888 ;
     RECT  99.827 0.192 101.317 0.216 ;
     RECT  100.787 10.992 101.329 13.608 ;
     RECT  100.115 15.024 101.329 19.368 ;
     RECT  101.329 10.992 102.085 19.368 ;
     RECT  102.181 1.728 102.308 1.752 ;
     RECT  101.845 9.792 102.308 9.816 ;
     RECT  102.085 10.992 102.308 19.704 ;
     RECT  101.317 0.192 102.325 0.264 ;
     RECT  102.308 1.728 102.325 19.704 ;
     RECT  102.325 0.192 102.563 19.704 ;
     RECT  102.563 0.192 102.604 19.56 ;
     RECT  102.604 11.328 102.707 19.56 ;
     RECT  102.604 0.192 102.773 1.752 ;
     RECT  102.707 11.328 102.995 19.368 ;
     RECT  102.604 8.976 103.187 9.912 ;
     RECT  102.995 11.376 103.283 19.368 ;
     RECT  103.187 8.976 103.529 9.816 ;
     RECT  103.283 11.952 103.763 19.368 ;
     RECT  102.773 0.192 103.841 0.312 ;
     RECT  102.604 7.968 103.925 7.992 ;
     RECT  102.773 1.728 104.033 1.752 ;
     RECT  103.841 0.192 104.348 0.36 ;
     RECT  104.348 0.192 104.435 0.552 ;
     RECT  103.529 8.976 104.725 9.096 ;
     RECT  104.533 10.896 104.869 10.92 ;
     RECT  103.763 12 104.869 19.368 ;
     RECT  104.869 10.896 104.965 19.368 ;
     RECT  104.725 8.976 105.008 9.288 ;
     RECT  104.965 10.896 105.008 19.608 ;
     RECT  105.008 2.148 105.107 19.608 ;
     RECT  105.107 2.148 105.112 19.56 ;
     RECT  105.112 2.418 105.292 19.56 ;
     RECT  105.292 2.418 105.304 19.368 ;
     RECT  104.435 0.192 105.433 0.264 ;
     RECT  105.304 9.024 105.539 9.096 ;
     RECT  105.304 10.608 105.58 19.368 ;
     RECT  105.58 10.896 105.635 19.368 ;
     RECT  105.635 10.896 105.689 17.928 ;
     RECT  105.689 11.136 105.731 17.928 ;
     RECT  105.539 9.072 105.761 9.096 ;
     RECT  105.731 11.136 106.265 17.784 ;
     RECT  105.304 7.968 106.273 7.992 ;
     RECT  105.635 19.104 106.441 19.368 ;
     RECT  105.433 0.192 106.451 0.552 ;
     RECT  106.441 19.104 106.643 19.464 ;
     RECT  106.643 19.104 106.693 19.368 ;
     RECT  106.451 0.192 106.697 0.264 ;
     RECT  106.265 11.664 106.789 17.784 ;
     RECT  106.693 19.056 106.789 19.368 ;
     RECT  106.789 11.664 107.269 19.368 ;
     RECT  107.269 10.896 107.605 19.368 ;
     RECT  107.509 2.016 107.651 2.04 ;
     RECT  106.597 9.12 107.708 9.144 ;
     RECT  107.605 10.896 107.708 19.56 ;
     RECT  107.708 2.148 107.749 19.56 ;
     RECT  107.749 2.148 107.812 19.608 ;
     RECT  106.697 0.192 107.941 0.216 ;
     RECT  107.812 2.418 108.004 19.608 ;
     RECT  107.941 0.192 108.064 0.264 ;
     RECT  108.004 10.896 108.131 19.608 ;
     RECT  108.131 10.896 108.137 18.984 ;
     RECT  108.064 0.192 108.277 0.312 ;
     RECT  108.137 11.712 108.323 18.984 ;
     RECT  108.236 19.968 108.323 19.992 ;
     RECT  108.277 0.192 108.425 0.36 ;
     RECT  108.323 12.528 108.515 18.984 ;
     RECT  108.515 12.528 109.145 14.904 ;
     RECT  108.515 15.984 109.477 18.936 ;
     RECT  108.425 0.192 109.937 0.312 ;
     RECT  109.145 12.816 109.969 14.904 ;
     RECT  109.477 15.984 109.969 19.368 ;
     RECT  109.969 12.816 110.408 19.368 ;
     RECT  110.408 2.148 110.512 19.452 ;
     RECT  110.512 2.418 110.704 19.182 ;
     RECT  110.704 15.84 110.765 18.84 ;
     RECT  110.765 15.84 110.837 18.456 ;
     RECT  110.704 13.68 110.945 13.704 ;
     RECT  110.837 15.84 110.945 15.864 ;
     RECT  110.837 17.184 111.161 18.456 ;
     RECT  111.161 17.184 111.341 18.408 ;
     RECT  111.341 17.28 111.413 18.408 ;
     RECT  111.413 17.28 111.521 17.88 ;
     RECT  111.521 17.28 111.593 17.736 ;
     RECT  109.937 0.192 111.737 0.216 ;
    LAYER M5 ;
     RECT  4.344 0.144 4.464 0.192 ;
     RECT  4.488 0.144 4.656 0.192 ;
     RECT  4.68 0.144 4.8 0.192 ;
     RECT  4.824 0.144 4.992 0.192 ;
     RECT  5.016 0.144 5.136 0.192 ;
     RECT  5.16 0.144 5.328 0.192 ;
     RECT  5.352 0.144 5.472 0.192 ;
     RECT  5.496 0.144 5.664 0.192 ;
     RECT  5.688 0.144 5.856 0.192 ;
     RECT  5.88 0.144 6 0.192 ;
     RECT  6.024 0.144 6.192 0.192 ;
     RECT  6.216 0.144 6.336 0.192 ;
     RECT  6.36 0.144 6.528 0.192 ;
     RECT  6.552 0.144 6.672 0.192 ;
     RECT  6.696 0.144 6.864 0.192 ;
     RECT  6.888 0.144 7.008 0.192 ;
     RECT  7.032 0.144 7.2 0.192 ;
     RECT  7.224 0.144 7.344 0.192 ;
     RECT  7.368 0.144 7.536 0.192 ;
     RECT  7.56 0.144 7.68 0.192 ;
     RECT  7.704 0.144 7.872 0.192 ;
     RECT  7.896 0.144 8.016 0.192 ;
     RECT  8.04 0.144 8.208 0.192 ;
     RECT  8.232 0.144 8.4 0.192 ;
     RECT  8.424 0.144 8.544 0.192 ;
     RECT  8.568 0.144 8.736 0.192 ;
     RECT  8.76 0.144 8.88 0.192 ;
     RECT  8.904 0.144 9.072 0.192 ;
     RECT  9.096 0.144 9.216 0.192 ;
     RECT  9.24 0.144 9.408 0.192 ;
     RECT  9.432 0.144 9.552 0.192 ;
     RECT  9.576 0.144 9.744 0.192 ;
     RECT  9.768 0.144 9.888 0.192 ;
     RECT  9.912 0.144 10.08 0.192 ;
     RECT  10.104 0.144 10.224 0.192 ;
     RECT  10.248 0.144 10.416 0.192 ;
     RECT  10.44 0.144 10.56 0.192 ;
     RECT  10.584 0.144 10.752 0.192 ;
     RECT  10.776 0.144 10.944 0.192 ;
     RECT  10.968 0.144 11.088 0.192 ;
     RECT  11.112 0.144 11.28 0.192 ;
     RECT  11.304 0.144 11.424 0.192 ;
     RECT  11.448 0.144 11.616 0.192 ;
     RECT  11.64 0.144 11.76 0.192 ;
     RECT  11.784 0.144 11.952 0.192 ;
     RECT  11.976 0.144 12.096 0.192 ;
     RECT  12.12 0.144 12.288 0.192 ;
     RECT  12.312 0.144 12.432 0.192 ;
     RECT  12.456 0.144 12.624 0.192 ;
     RECT  12.648 0.144 12.768 0.192 ;
     RECT  12.792 0.144 12.96 0.192 ;
     RECT  12.984 0.144 13.152 0.192 ;
     RECT  13.176 0.144 13.296 0.192 ;
     RECT  13.32 0.144 13.488 0.192 ;
     RECT  13.512 0.144 13.632 0.192 ;
     RECT  13.656 0.144 13.824 0.192 ;
     RECT  13.848 0.144 13.968 0.192 ;
     RECT  13.992 0.144 14.16 0.192 ;
     RECT  14.184 0.144 14.304 0.192 ;
     RECT  14.328 0.144 14.496 0.192 ;
     RECT  14.52 0.144 14.64 0.192 ;
     RECT  14.664 0.144 14.832 0.192 ;
     RECT  14.856 0.144 14.976 0.192 ;
     RECT  15 0.144 15.168 0.192 ;
     RECT  15.192 0.144 15.312 0.192 ;
     RECT  15.336 0.144 15.504 0.192 ;
     RECT  15.528 0.144 15.696 0.192 ;
     RECT  15.72 0.144 15.84 0.192 ;
     RECT  15.864 0.144 16.032 0.192 ;
     RECT  16.056 0.144 16.176 0.192 ;
     RECT  16.2 0.144 16.368 0.192 ;
     RECT  16.392 0.144 16.512 0.192 ;
     RECT  16.536 0.144 16.704 0.192 ;
     RECT  16.728 0.144 16.848 0.192 ;
     RECT  16.872 0.144 17.04 0.192 ;
     RECT  17.064 0.144 17.184 0.192 ;
     RECT  17.208 0.144 17.376 0.192 ;
     RECT  17.4 0.144 17.52 0.192 ;
     RECT  17.544 0.144 17.712 0.192 ;
     RECT  17.736 0.144 17.856 0.192 ;
     RECT  17.88 0.144 18.048 0.192 ;
     RECT  18.072 0.144 18.24 0.192 ;
     RECT  18.264 0.144 18.384 0.192 ;
     RECT  18.408 0.144 18.576 0.192 ;
     RECT  18.6 0.144 18.72 0.192 ;
     RECT  18.744 0.144 18.912 0.192 ;
     RECT  18.936 0.144 19.056 0.192 ;
     RECT  19.08 0.144 19.248 0.192 ;
     RECT  19.272 0.144 19.392 0.192 ;
     RECT  19.416 0.144 19.584 0.192 ;
     RECT  19.608 0.144 19.728 0.192 ;
     RECT  19.752 0.144 19.92 0.192 ;
     RECT  19.944 0.144 20.064 0.192 ;
     RECT  20.088 0.144 20.256 0.192 ;
     RECT  20.28 0.144 20.4 0.192 ;
     RECT  20.424 0.144 20.592 0.192 ;
     RECT  20.616 0.144 20.784 0.192 ;
     RECT  20.808 0.144 20.928 0.192 ;
     RECT  20.952 0.144 21.12 0.192 ;
     RECT  21.144 0.144 21.264 0.192 ;
     RECT  21.288 0.144 21.456 0.192 ;
     RECT  21.48 0.144 21.6 0.192 ;
     RECT  21.624 0.144 21.792 0.192 ;
     RECT  21.816 0.144 21.936 0.192 ;
     RECT  21.96 0.144 22.128 0.192 ;
     RECT  22.152 0.144 22.272 0.192 ;
     RECT  22.296 0.144 22.464 0.192 ;
     RECT  22.488 0.144 22.608 0.192 ;
     RECT  22.632 0.144 22.8 0.192 ;
     RECT  22.824 0.144 22.944 0.192 ;
     RECT  22.968 0.144 23.136 0.192 ;
     RECT  23.16 0.144 23.328 0.192 ;
     RECT  23.352 0.144 23.472 0.192 ;
     RECT  23.496 0.144 23.664 0.192 ;
     RECT  23.688 0.144 23.808 0.192 ;
     RECT  23.832 0.144 24 0.192 ;
     RECT  24.024 0.144 24.144 0.192 ;
     RECT  24.168 0.144 24.336 0.192 ;
     RECT  24.36 0.144 24.48 0.192 ;
     RECT  24.504 0.144 24.672 0.192 ;
     RECT  24.696 0.144 24.816 0.192 ;
     RECT  24.84 0.144 25.008 0.192 ;
     RECT  25.032 0.144 25.152 0.192 ;
     RECT  25.176 0.144 25.344 0.192 ;
     RECT  25.368 0.144 25.488 0.192 ;
     RECT  25.512 0.144 25.68 0.192 ;
     RECT  25.704 0.144 25.872 0.192 ;
     RECT  25.896 0.144 26.016 0.192 ;
     RECT  26.04 0.144 26.208 0.192 ;
     RECT  26.232 0.144 26.352 0.192 ;
     RECT  26.376 0.144 26.544 0.192 ;
     RECT  26.568 0.144 26.688 0.192 ;
     RECT  26.712 0.144 26.88 0.192 ;
     RECT  26.904 0.144 27.024 0.192 ;
     RECT  27.048 0.144 27.216 0.192 ;
     RECT  27.24 0.144 27.36 0.192 ;
     RECT  27.384 0.144 27.552 0.192 ;
     RECT  27.576 0.144 27.696 0.192 ;
     RECT  27.72 0.144 27.888 0.192 ;
     RECT  27.912 0.144 28.032 0.192 ;
     RECT  28.056 0.144 28.224 0.192 ;
     RECT  28.248 0.144 28.416 0.192 ;
     RECT  28.44 0.144 28.56 0.192 ;
     RECT  28.584 0.144 28.752 0.192 ;
     RECT  28.776 0.144 28.896 0.192 ;
     RECT  28.92 0.144 29.088 0.192 ;
     RECT  29.112 0.144 29.232 0.192 ;
     RECT  29.256 0.144 29.424 0.192 ;
     RECT  29.448 0.144 29.568 0.192 ;
     RECT  29.592 0.144 29.76 0.192 ;
     RECT  29.784 0.144 29.904 0.192 ;
     RECT  29.928 0.144 30.096 0.192 ;
     RECT  30.12 0.144 30.24 0.192 ;
     RECT  30.264 0.144 30.432 0.192 ;
     RECT  30.456 0.144 30.576 0.192 ;
     RECT  30.6 0.144 30.768 0.192 ;
     RECT  30.792 0.144 30.96 0.192 ;
     RECT  30.984 0.144 31.104 0.192 ;
     RECT  31.128 0.144 31.296 0.192 ;
     RECT  31.32 0.144 31.44 0.192 ;
     RECT  31.464 0.144 31.632 0.192 ;
     RECT  31.656 0.144 31.776 0.192 ;
     RECT  31.8 0.144 31.968 0.192 ;
     RECT  31.992 0.144 32.112 0.192 ;
     RECT  32.136 0.144 32.304 0.192 ;
     RECT  32.328 0.144 32.448 0.192 ;
     RECT  32.472 0.144 32.64 0.192 ;
     RECT  32.664 0.144 32.784 0.192 ;
     RECT  32.808 0.144 32.976 0.192 ;
     RECT  33 0.144 33.12 0.192 ;
     RECT  33.144 0.144 33.312 0.192 ;
     RECT  33.336 0.144 33.504 0.192 ;
     RECT  33.528 0.144 33.648 0.192 ;
     RECT  33.672 0.144 33.84 0.192 ;
     RECT  33.864 0.144 33.984 0.192 ;
     RECT  34.008 0.144 34.176 0.192 ;
     RECT  34.2 0.144 34.32 0.192 ;
     RECT  34.344 0.144 34.512 0.192 ;
     RECT  34.536 0.144 34.656 0.192 ;
     RECT  34.68 0.144 34.848 0.192 ;
     RECT  34.872 0.144 34.992 0.192 ;
     RECT  35.016 0.144 35.184 0.192 ;
     RECT  35.208 0.144 35.328 0.192 ;
     RECT  35.352 0.144 35.52 0.192 ;
     RECT  35.544 0.144 35.664 0.192 ;
     RECT  35.688 0.144 35.856 0.192 ;
     RECT  35.88 0.144 36.048 0.192 ;
     RECT  36.072 0.144 36.192 0.192 ;
     RECT  36.216 0.144 36.384 0.192 ;
     RECT  36.408 0.144 36.528 0.192 ;
     RECT  36.552 0.144 36.72 0.192 ;
     RECT  36.744 0.144 36.864 0.192 ;
     RECT  36.888 0.144 37.056 0.192 ;
     RECT  37.08 0.144 37.2 0.192 ;
     RECT  37.224 0.144 37.392 0.192 ;
     RECT  37.416 0.144 37.536 0.192 ;
     RECT  37.56 0.144 37.728 0.192 ;
     RECT  37.752 0.144 37.872 0.192 ;
     RECT  37.896 0.144 38.064 0.192 ;
     RECT  38.088 0.144 38.208 0.192 ;
     RECT  38.232 0.144 38.4 0.192 ;
     RECT  38.424 0.144 38.592 0.192 ;
     RECT  38.616 0.144 38.736 0.192 ;
     RECT  38.76 0.144 38.928 0.192 ;
     RECT  38.952 0.144 39.072 0.192 ;
     RECT  39.096 0.144 39.264 0.192 ;
     RECT  39.288 0.144 39.408 0.192 ;
     RECT  39.432 0.144 39.6 0.192 ;
     RECT  39.624 0.144 39.744 0.192 ;
     RECT  39.768 0.144 39.936 0.192 ;
     RECT  39.96 0.144 40.08 0.192 ;
     RECT  40.104 0.144 40.272 0.192 ;
     RECT  40.296 0.144 40.416 0.192 ;
     RECT  40.44 0.144 40.608 0.192 ;
     RECT  40.632 0.144 40.752 0.192 ;
     RECT  40.776 0.144 40.944 0.192 ;
     RECT  40.968 0.144 41.136 0.192 ;
     RECT  41.16 0.144 41.28 0.192 ;
     RECT  41.304 0.144 41.472 0.192 ;
     RECT  41.496 0.144 41.616 0.192 ;
     RECT  41.64 0.144 41.808 0.192 ;
     RECT  41.832 0.144 41.952 0.192 ;
     RECT  41.976 0.144 42.144 0.192 ;
     RECT  42.168 0.144 42.288 0.192 ;
     RECT  42.312 0.144 42.48 0.192 ;
     RECT  42.504 0.144 42.624 0.192 ;
     RECT  42.648 0.144 42.816 0.192 ;
     RECT  42.84 0.144 42.96 0.192 ;
     RECT  42.984 0.144 43.152 0.192 ;
     RECT  43.176 0.144 43.296 0.192 ;
     RECT  43.32 0.144 43.488 0.192 ;
     RECT  43.512 0.144 43.68 0.192 ;
     RECT  43.704 0.144 43.824 0.192 ;
     RECT  43.848 0.144 44.016 0.192 ;
     RECT  44.04 0.144 44.16 0.192 ;
     RECT  44.184 0.144 44.352 0.192 ;
     RECT  44.376 0.144 44.496 0.192 ;
     RECT  44.52 0.144 44.688 0.192 ;
     RECT  44.712 0.144 44.832 0.192 ;
     RECT  44.856 0.144 45.024 0.192 ;
     RECT  45.048 0.144 45.168 0.192 ;
     RECT  45.192 0.144 45.36 0.192 ;
     RECT  45.384 0.144 45.504 0.192 ;
     RECT  45.528 0.144 45.696 0.192 ;
     RECT  45.72 0.144 45.84 0.192 ;
     RECT  45.864 0.144 46.032 0.192 ;
     RECT  46.056 0.144 46.224 0.192 ;
     RECT  46.248 0.144 46.368 0.192 ;
     RECT  46.392 0.144 46.56 0.192 ;
     RECT  46.584 0.144 46.704 0.192 ;
     RECT  46.728 0.144 46.896 0.192 ;
     RECT  46.92 0.144 47.04 0.192 ;
     RECT  47.064 0.144 47.232 0.192 ;
     RECT  47.256 0.144 47.376 0.192 ;
     RECT  47.4 0.144 47.568 0.192 ;
     RECT  47.592 0.144 47.712 0.192 ;
     RECT  47.736 0.144 47.904 0.192 ;
     RECT  47.928 0.144 48.048 0.192 ;
     RECT  48.072 0.144 48.24 0.192 ;
     RECT  48.264 0.144 48.384 0.192 ;
     RECT  48.408 0.144 48.576 0.192 ;
     RECT  48.6 0.144 48.768 0.192 ;
     RECT  48.792 0.144 48.912 0.192 ;
     RECT  48.936 0.144 49.104 0.192 ;
     RECT  49.128 0.144 49.248 0.192 ;
     RECT  49.272 0.144 49.44 0.192 ;
     RECT  49.464 0.144 49.584 0.192 ;
     RECT  49.608 0.144 49.776 0.192 ;
     RECT  49.8 0.144 49.92 0.192 ;
     RECT  49.944 0.144 50.112 0.192 ;
     RECT  50.136 0.144 50.256 0.192 ;
     RECT  50.28 0.144 50.448 0.192 ;
     RECT  50.472 0.144 50.592 0.192 ;
     RECT  50.616 0.144 50.784 0.192 ;
     RECT  50.808 0.144 50.976 0.192 ;
     RECT  51 0.144 51.12 0.192 ;
     RECT  51.144 0.144 51.312 0.192 ;
     RECT  51.336 0.144 51.456 0.192 ;
     RECT  51.48 0.144 51.648 0.192 ;
     RECT  51.672 0.144 51.792 0.192 ;
     RECT  51.816 0.144 51.984 0.192 ;
     RECT  52.008 0.144 52.128 0.192 ;
     RECT  52.152 0.144 52.32 0.192 ;
     RECT  52.344 0.144 52.464 0.192 ;
     RECT  52.488 0.144 52.656 0.192 ;
     RECT  52.68 0.144 52.8 0.192 ;
     RECT  52.824 0.144 52.992 0.192 ;
     RECT  53.016 0.144 53.136 0.192 ;
     RECT  53.16 0.144 53.328 0.192 ;
     RECT  53.352 0.144 53.52 0.192 ;
     RECT  53.544 0.144 53.664 0.192 ;
     RECT  53.688 0.144 53.856 0.192 ;
     RECT  53.88 0.144 54 0.192 ;
     RECT  54.024 0.144 54.192 0.192 ;
     RECT  54.216 0.144 54.336 0.192 ;
     RECT  54.36 0.144 54.528 0.192 ;
     RECT  54.552 0.144 54.672 0.192 ;
     RECT  54.696 0.144 54.864 0.192 ;
     RECT  54.888 0.144 55.008 0.192 ;
     RECT  55.032 0.144 55.2 0.192 ;
     RECT  55.224 0.144 55.344 0.192 ;
     RECT  55.368 0.144 55.536 0.192 ;
     RECT  55.56 0.144 55.68 0.192 ;
     RECT  55.704 0.144 55.872 0.192 ;
     RECT  55.896 0.144 56.064 0.192 ;
     RECT  56.088 0.144 56.208 0.192 ;
     RECT  56.232 0.144 56.4 0.192 ;
     RECT  56.424 0.144 56.544 0.192 ;
     RECT  56.568 0.144 56.736 0.192 ;
     RECT  56.76 0.144 56.88 0.192 ;
     RECT  56.904 0.144 57.072 0.192 ;
     RECT  57.096 0.144 57.216 0.192 ;
     RECT  57.24 0.144 57.408 0.192 ;
     RECT  57.432 0.144 57.552 0.192 ;
     RECT  57.576 0.144 57.744 0.192 ;
     RECT  57.768 0.144 57.888 0.192 ;
     RECT  57.912 0.144 58.08 0.192 ;
     RECT  58.104 0.144 58.224 0.192 ;
     RECT  58.248 0.144 58.416 0.192 ;
     RECT  58.44 0.144 58.608 0.192 ;
     RECT  58.632 0.144 58.752 0.192 ;
     RECT  58.776 0.144 58.944 0.192 ;
     RECT  58.968 0.144 59.088 0.192 ;
     RECT  59.112 0.144 59.28 0.192 ;
     RECT  59.304 0.144 59.424 0.192 ;
     RECT  59.448 0.144 59.616 0.192 ;
     RECT  59.64 0.144 59.76 0.192 ;
     RECT  59.784 0.144 59.952 0.192 ;
     RECT  59.976 0.144 60.096 0.192 ;
     RECT  60.12 0.144 60.288 0.192 ;
     RECT  60.312 0.144 60.432 0.192 ;
     RECT  60.456 0.144 60.624 0.192 ;
     RECT  60.648 0.144 60.768 0.192 ;
     RECT  60.792 0.144 60.96 0.192 ;
     RECT  60.984 0.144 61.152 0.192 ;
     RECT  61.176 0.144 61.296 0.192 ;
     RECT  61.32 0.144 61.488 0.192 ;
     RECT  61.512 0.144 61.632 0.192 ;
     RECT  61.656 0.144 61.824 0.192 ;
     RECT  61.848 0.144 61.968 0.192 ;
     RECT  61.992 0.144 62.16 0.192 ;
     RECT  62.184 0.144 62.304 0.192 ;
     RECT  62.328 0.144 62.496 0.192 ;
     RECT  62.52 0.144 62.64 0.192 ;
     RECT  62.664 0.144 62.832 0.192 ;
     RECT  62.856 0.144 62.976 0.192 ;
     RECT  63 0.144 63.168 0.192 ;
     RECT  63.192 0.144 63.312 0.192 ;
     RECT  63.336 0.144 63.504 0.192 ;
     RECT  63.528 0.144 63.696 0.192 ;
     RECT  63.72 0.144 63.84 0.192 ;
     RECT  63.864 0.144 64.032 0.192 ;
     RECT  64.056 0.144 64.176 0.192 ;
     RECT  64.2 0.144 64.368 0.192 ;
     RECT  64.392 0.144 64.512 0.192 ;
     RECT  64.536 0.144 64.704 0.192 ;
     RECT  64.728 0.144 64.848 0.192 ;
     RECT  64.872 0.144 65.04 0.192 ;
     RECT  65.064 0.144 65.184 0.192 ;
     RECT  65.208 0.144 65.376 0.192 ;
     RECT  65.4 0.144 65.52 0.192 ;
     RECT  65.544 0.144 65.712 0.192 ;
     RECT  65.736 0.144 65.856 0.192 ;
     RECT  65.88 0.144 66.048 0.192 ;
     RECT  66.072 0.144 66.24 0.192 ;
     RECT  66.264 0.144 66.384 0.192 ;
     RECT  66.408 0.144 66.576 0.192 ;
     RECT  66.6 0.144 66.72 0.192 ;
     RECT  66.744 0.144 66.912 0.192 ;
     RECT  66.936 0.144 67.056 0.192 ;
     RECT  67.08 0.144 67.248 0.192 ;
     RECT  67.272 0.144 67.392 0.192 ;
     RECT  67.416 0.144 67.584 0.192 ;
     RECT  67.608 0.144 67.728 0.192 ;
     RECT  67.752 0.144 67.92 0.192 ;
     RECT  67.944 0.144 68.064 0.192 ;
     RECT  68.088 0.144 68.256 0.192 ;
     RECT  68.28 0.144 68.4 0.192 ;
     RECT  68.424 0.144 68.592 0.192 ;
     RECT  68.616 0.144 68.784 0.192 ;
     RECT  68.808 0.144 68.928 0.192 ;
     RECT  68.952 0.144 69.12 0.192 ;
     RECT  69.144 0.144 69.264 0.192 ;
     RECT  69.288 0.144 69.456 0.192 ;
     RECT  69.48 0.144 69.6 0.192 ;
     RECT  69.624 0.144 69.792 0.192 ;
     RECT  69.816 0.144 69.936 0.192 ;
     RECT  69.96 0.144 70.128 0.192 ;
     RECT  70.152 0.144 70.272 0.192 ;
     RECT  70.296 0.144 70.464 0.192 ;
     RECT  70.488 0.144 70.608 0.192 ;
     RECT  70.632 0.144 70.8 0.192 ;
     RECT  70.824 0.144 70.944 0.192 ;
     RECT  70.968 0.144 71.136 0.192 ;
     RECT  71.16 0.144 71.328 0.192 ;
     RECT  71.352 0.144 71.472 0.192 ;
     RECT  71.496 0.144 71.664 0.192 ;
     RECT  71.688 0.144 71.808 0.192 ;
     RECT  71.832 0.144 72 0.192 ;
     RECT  72.024 0.144 72.144 0.192 ;
     RECT  72.168 0.144 72.336 0.192 ;
     RECT  72.36 0.144 72.48 0.192 ;
     RECT  72.504 0.144 72.672 0.192 ;
     RECT  72.696 0.144 72.816 0.192 ;
     RECT  72.84 0.144 73.008 0.192 ;
     RECT  73.032 0.144 73.152 0.192 ;
     RECT  73.176 0.144 73.344 0.192 ;
     RECT  73.368 0.144 73.488 0.192 ;
     RECT  73.512 0.144 73.68 0.192 ;
     RECT  73.704 0.144 73.872 0.192 ;
     RECT  73.896 0.144 74.016 0.192 ;
     RECT  74.04 0.144 74.208 0.192 ;
     RECT  74.232 0.144 74.352 0.192 ;
     RECT  74.376 0.144 74.544 0.192 ;
     RECT  74.568 0.144 74.688 0.192 ;
     RECT  74.712 0.144 74.88 0.192 ;
     RECT  74.904 0.144 75.024 0.192 ;
     RECT  75.048 0.144 75.216 0.192 ;
     RECT  75.24 0.144 75.36 0.192 ;
     RECT  75.384 0.144 75.552 0.192 ;
     RECT  75.576 0.144 75.696 0.192 ;
     RECT  75.72 0.144 75.888 0.192 ;
     RECT  75.912 0.144 76.032 0.192 ;
     RECT  76.056 0.144 76.224 0.192 ;
     RECT  76.248 0.144 76.416 0.192 ;
     RECT  76.44 0.144 76.56 0.192 ;
     RECT  76.584 0.144 76.752 0.192 ;
     RECT  76.776 0.144 76.896 0.192 ;
     RECT  76.92 0.144 77.088 0.192 ;
     RECT  77.112 0.144 77.232 0.192 ;
     RECT  77.256 0.144 77.424 0.192 ;
     RECT  77.448 0.144 77.568 0.192 ;
     RECT  77.592 0.144 77.76 0.192 ;
     RECT  77.784 0.144 77.904 0.192 ;
     RECT  77.928 0.144 78.096 0.192 ;
     RECT  78.12 0.144 78.24 0.192 ;
     RECT  78.264 0.144 78.432 0.192 ;
     RECT  78.456 0.144 78.576 0.192 ;
     RECT  78.6 0.144 78.768 0.192 ;
     RECT  78.792 0.144 78.96 0.192 ;
     RECT  78.984 0.144 79.104 0.192 ;
     RECT  79.128 0.144 79.296 0.192 ;
     RECT  79.32 0.144 79.44 0.192 ;
     RECT  79.464 0.144 79.632 0.192 ;
     RECT  79.656 0.144 79.776 0.192 ;
     RECT  79.8 0.144 79.968 0.192 ;
     RECT  79.992 0.144 80.112 0.192 ;
     RECT  80.136 0.144 80.304 0.192 ;
     RECT  80.328 0.144 80.448 0.192 ;
     RECT  80.472 0.144 80.64 0.192 ;
     RECT  80.664 0.144 80.784 0.192 ;
     RECT  80.808 0.144 80.976 0.192 ;
     RECT  81 0.144 81.12 0.192 ;
     RECT  81.144 0.144 81.312 0.192 ;
     RECT  81.336 0.144 81.504 0.192 ;
     RECT  81.528 0.144 81.648 0.192 ;
     RECT  81.672 0.144 81.84 0.192 ;
     RECT  81.864 0.144 81.984 0.192 ;
     RECT  82.008 0.144 82.176 0.192 ;
     RECT  82.2 0.144 82.32 0.192 ;
     RECT  82.344 0.144 82.512 0.192 ;
     RECT  82.536 0.144 82.656 0.192 ;
     RECT  82.68 0.144 82.848 0.192 ;
     RECT  82.872 0.144 82.992 0.192 ;
     RECT  83.016 0.144 83.184 0.192 ;
     RECT  83.208 0.144 83.328 0.192 ;
     RECT  83.352 0.144 83.52 0.192 ;
     RECT  83.544 0.144 83.664 0.192 ;
     RECT  83.688 0.144 83.856 0.192 ;
     RECT  83.88 0.144 84.048 0.192 ;
     RECT  84.072 0.144 84.192 0.192 ;
     RECT  84.216 0.144 84.384 0.192 ;
     RECT  84.408 0.144 84.528 0.192 ;
     RECT  84.552 0.144 84.72 0.192 ;
     RECT  84.744 0.144 84.864 0.192 ;
     RECT  84.888 0.144 85.056 0.192 ;
     RECT  85.08 0.144 85.2 0.192 ;
     RECT  85.224 0.144 85.392 0.192 ;
     RECT  85.416 0.144 85.536 0.192 ;
     RECT  85.56 0.144 85.728 0.192 ;
     RECT  85.752 0.144 85.872 0.192 ;
     RECT  85.896 0.144 86.064 0.192 ;
     RECT  86.088 0.144 86.256 0.192 ;
     RECT  86.28 0.144 86.4 0.192 ;
     RECT  86.424 0.144 86.592 0.192 ;
     RECT  86.616 0.144 86.736 0.192 ;
     RECT  86.76 0.144 86.928 0.192 ;
     RECT  86.952 0.144 87.072 0.192 ;
     RECT  87.096 0.144 87.264 0.192 ;
     RECT  87.288 0.144 87.408 0.192 ;
     RECT  87.432 0.144 87.6 0.192 ;
     RECT  87.624 0.144 87.744 0.192 ;
     RECT  87.768 0.144 87.936 0.192 ;
     RECT  87.96 0.144 88.08 0.192 ;
     RECT  88.104 0.144 88.272 0.192 ;
     RECT  88.296 0.144 88.416 0.192 ;
     RECT  88.44 0.144 88.608 0.192 ;
     RECT  88.632 0.144 88.8 0.192 ;
     RECT  88.824 0.144 88.944 0.192 ;
     RECT  88.968 0.144 89.136 0.192 ;
     RECT  89.16 0.144 89.28 0.192 ;
     RECT  89.304 0.144 89.472 0.192 ;
     RECT  89.496 0.144 89.616 0.192 ;
     RECT  89.64 0.144 89.808 0.192 ;
     RECT  89.832 0.144 89.952 0.192 ;
     RECT  89.976 0.144 90.144 0.192 ;
     RECT  90.168 0.144 90.288 0.192 ;
     RECT  90.312 0.144 90.48 0.192 ;
     RECT  90.504 0.144 90.624 0.192 ;
     RECT  90.648 0.144 90.816 0.192 ;
     RECT  90.84 0.144 90.96 0.192 ;
     RECT  90.984 0.144 91.152 0.192 ;
     RECT  91.176 0.144 91.344 0.192 ;
     RECT  91.368 0.144 91.488 0.192 ;
     RECT  91.512 0.144 91.68 0.192 ;
     RECT  91.704 0.144 91.824 0.192 ;
     RECT  91.848 0.144 92.016 0.192 ;
     RECT  92.04 0.144 92.16 0.192 ;
     RECT  92.184 0.144 92.352 0.192 ;
     RECT  92.376 0.144 92.496 0.192 ;
     RECT  92.52 0.144 92.688 0.192 ;
     RECT  92.712 0.144 92.832 0.192 ;
     RECT  92.856 0.144 93.024 0.192 ;
     RECT  93.048 0.144 93.168 0.192 ;
     RECT  93.192 0.144 93.36 0.192 ;
     RECT  93.384 0.144 93.504 0.192 ;
     RECT  93.528 0.144 93.696 0.192 ;
     RECT  93.72 0.144 93.888 0.192 ;
     RECT  93.912 0.144 94.032 0.192 ;
     RECT  94.056 0.144 94.224 0.192 ;
     RECT  94.248 0.144 94.368 0.192 ;
     RECT  94.392 0.144 94.56 0.192 ;
     RECT  94.584 0.144 94.704 0.192 ;
     RECT  94.728 0.144 94.896 0.192 ;
     RECT  94.92 0.144 95.04 0.192 ;
     RECT  95.064 0.144 95.232 0.192 ;
     RECT  95.256 0.144 95.376 0.192 ;
     RECT  95.4 0.144 95.568 0.192 ;
     RECT  95.592 0.144 95.712 0.192 ;
     RECT  95.736 0.144 95.904 0.192 ;
     RECT  95.928 0.144 96.048 0.192 ;
     RECT  96.072 0.144 96.24 0.192 ;
     RECT  96.264 0.144 96.432 0.192 ;
     RECT  96.456 0.144 96.576 0.192 ;
     RECT  96.6 0.144 96.768 0.192 ;
     RECT  96.792 0.144 96.912 0.192 ;
     RECT  96.936 0.144 97.104 0.192 ;
     RECT  97.128 0.144 97.248 0.192 ;
     RECT  97.272 0.144 97.44 0.192 ;
     RECT  97.464 0.144 97.584 0.192 ;
     RECT  97.608 0.144 97.776 0.192 ;
     RECT  97.8 0.144 97.92 0.192 ;
     RECT  97.944 0.144 98.112 0.192 ;
     RECT  98.136 0.144 98.256 0.192 ;
     RECT  98.28 0.144 98.448 0.192 ;
     RECT  98.472 0.144 98.592 0.192 ;
     RECT  98.616 0.144 98.784 0.192 ;
     RECT  98.808 0.144 98.976 0.192 ;
     RECT  99 0.144 99.12 0.192 ;
     RECT  99.144 0.144 99.312 0.192 ;
     RECT  99.336 0.144 99.456 0.192 ;
     RECT  99.48 0.144 99.648 0.192 ;
     RECT  99.672 0.144 99.792 0.192 ;
     RECT  99.816 0.144 99.984 0.192 ;
     RECT  100.008 0.144 100.128 0.192 ;
     RECT  100.152 0.144 100.32 0.192 ;
     RECT  100.344 0.144 100.464 0.192 ;
     RECT  100.488 0.144 100.656 0.192 ;
     RECT  100.68 0.144 100.8 0.192 ;
     RECT  100.824 0.144 100.992 0.192 ;
     RECT  101.016 0.144 101.136 0.192 ;
     RECT  101.16 0.144 101.328 0.192 ;
     RECT  101.352 0.144 101.52 0.192 ;
     RECT  101.544 0.144 101.664 0.192 ;
     RECT  101.688 0.144 101.856 0.192 ;
     RECT  101.88 0.144 102 0.192 ;
     RECT  102.024 0.144 102.192 0.192 ;
     RECT  102.216 0.144 102.336 0.192 ;
     RECT  102.36 0.144 102.528 0.192 ;
     RECT  102.552 0.144 102.672 0.192 ;
     RECT  102.696 0.144 102.864 0.192 ;
     RECT  102.888 0.144 103.008 0.192 ;
     RECT  103.032 0.144 103.2 0.192 ;
     RECT  103.224 0.144 103.344 0.192 ;
     RECT  103.368 0.144 103.536 0.192 ;
     RECT  103.56 0.144 103.68 0.192 ;
     RECT  103.704 0.144 103.872 0.192 ;
     RECT  103.896 0.144 104.064 0.192 ;
     RECT  104.088 0.144 104.208 0.192 ;
     RECT  104.232 0.144 104.4 0.192 ;
     RECT  104.424 0.144 104.544 0.192 ;
     RECT  104.568 0.144 104.736 0.192 ;
     RECT  104.76 0.144 104.88 0.192 ;
     RECT  104.904 0.144 105.072 0.192 ;
     RECT  105.096 0.144 105.216 0.192 ;
     RECT  105.24 0.144 105.408 0.192 ;
     RECT  105.432 0.144 105.552 0.192 ;
     RECT  105.576 0.144 105.744 0.192 ;
     RECT  105.768 0.144 105.888 0.192 ;
     RECT  105.912 0.144 106.08 0.192 ;
     RECT  106.104 0.144 106.224 0.192 ;
     RECT  106.248 0.144 106.416 0.192 ;
     RECT  106.44 0.144 106.608 0.192 ;
     RECT  106.632 0.144 106.752 0.192 ;
     RECT  106.776 0.144 106.944 0.192 ;
     RECT  106.968 0.144 107.088 0.192 ;
     RECT  107.112 0.144 107.28 0.192 ;
     RECT  107.304 0.144 107.424 0.192 ;
     RECT  107.448 0.144 107.616 0.192 ;
     RECT  107.64 0.144 107.76 0.192 ;
     RECT  107.784 0.144 107.952 0.192 ;
     RECT  107.976 0.144 108.096 0.192 ;
     RECT  108.12 0.144 108.288 0.192 ;
     RECT  108.312 0.144 108.432 0.192 ;
     RECT  108.456 0.144 108.624 0.192 ;
     RECT  108.648 0.144 108.768 0.192 ;
     RECT  108.792 0.144 108.96 0.192 ;
     RECT  108.984 0.144 109.152 0.192 ;
     RECT  109.176 0.144 109.296 0.192 ;
     RECT  109.32 0.144 109.488 0.192 ;
     RECT  109.512 0.144 109.632 0.192 ;
     RECT  109.656 0.144 109.824 0.192 ;
     RECT  109.848 0.144 109.968 0.192 ;
     RECT  109.992 0.144 110.16 0.192 ;
     RECT  4.32 0.192 110.184 0.227 ;
     RECT  4.464 0.227 109.992 0.275 ;
     RECT  4.464 0.275 15.336 0.323 ;
     RECT  16.704 0.275 48.408 0.323 ;
     RECT  49.44 0.275 109.992 0.323 ;
     RECT  16.704 0.323 48.264 0.371 ;
     RECT  49.44 0.323 77.928 0.371 ;
     RECT  105.744 0.323 109.992 0.371 ;
     RECT  16.704 0.371 21.144 0.419 ;
     RECT  30.24 0.371 34.68 0.419 ;
     RECT  35.664 0.371 48.264 0.419 ;
     RECT  49.44 0.371 67.08 0.419 ;
     RECT  73.344 0.371 77.928 0.419 ;
     RECT  89.28 0.323 104.76 0.419 ;
     RECT  38.208 0.419 48.264 0.467 ;
     RECT  4.464 0.323 4.824 0.563 ;
     RECT  6 0.323 15.336 0.563 ;
     RECT  16.704 0.419 20.952 0.563 ;
     RECT  22.128 0.371 29.208 0.563 ;
     RECT  35.664 0.419 37.224 0.563 ;
     RECT  49.44 0.419 59.112 0.563 ;
     RECT  60.768 0.419 67.08 0.563 ;
     RECT  68.064 0.371 69.816 0.563 ;
     RECT  73.68 0.419 77.928 0.563 ;
     RECT  78.96 0.323 88.296 0.563 ;
     RECT  105.744 0.371 107.64 0.563 ;
     RECT  35.856 0.563 37.224 0.611 ;
     RECT  49.584 0.563 53.544 0.611 ;
     RECT  54.672 0.563 59.112 0.611 ;
     RECT  79.968 0.563 88.296 0.611 ;
     RECT  89.28 0.419 91.704 0.611 ;
     RECT  6 0.563 8.424 1.763 ;
     RECT  92.832 0.419 104.76 1.763 ;
     RECT  4.464 0.563 4.488 2.137 ;
     RECT  6 1.763 8.112 2.137 ;
     RECT  9.408 0.563 15.336 2.137 ;
     RECT  17.856 0.563 20.952 2.137 ;
     RECT  22.128 0.563 24.696 2.137 ;
     RECT  25.68 0.563 29.208 2.137 ;
     RECT  30.432 0.419 34.68 2.137 ;
     RECT  35.856 0.611 36.888 2.137 ;
     RECT  38.4 0.467 48.264 2.137 ;
     RECT  49.776 0.611 53.544 2.137 ;
     RECT  54.672 0.611 56.232 2.137 ;
     RECT  57.216 0.611 58.632 2.137 ;
     RECT  60.768 0.563 61.512 2.137 ;
     RECT  62.64 0.563 64.392 2.137 ;
     RECT  65.376 0.563 67.08 2.137 ;
     RECT  68.064 0.563 68.616 2.137 ;
     RECT  69.6 0.563 69.624 2.137 ;
     RECT  70.8 0.371 72.36 2.137 ;
     RECT  74.016 0.563 77.928 2.137 ;
     RECT  79.968 0.611 80.472 2.137 ;
     RECT  81.84 0.611 88.296 2.137 ;
     RECT  89.28 0.611 91.368 2.137 ;
     RECT  104.544 1.763 104.76 2.137 ;
     RECT  106.608 0.563 107.64 2.137 ;
     RECT  109.152 0.371 109.992 2.137 ;
     RECT  2.4 2.137 2.52 2.151 ;
     RECT  9.408 2.137 16.02 2.151 ;
     RECT  25.68 2.137 48.42 2.151 ;
     RECT  49.776 2.137 59.22 2.151 ;
     RECT  69.6 2.137 72.72 2.151 ;
     RECT  74.016 2.137 78.12 2.151 ;
     RECT  79.968 2.137 80.82 2.151 ;
     RECT  81.84 2.137 91.62 2.151 ;
     RECT  104.544 2.137 105.12 2.151 ;
     RECT  106.608 2.137 107.82 2.151 ;
     RECT  109.152 2.137 110.52 2.151 ;
     RECT  25.68 2.151 48.612 5.747 ;
     RECT  44.352 5.747 48.612 6.035 ;
     RECT  17.856 2.137 24.696 6.899 ;
     RECT  25.68 5.747 43.32 6.899 ;
     RECT  79.968 2.151 91.812 6.899 ;
     RECT  25.872 6.899 35.112 7.475 ;
     RECT  69.6 2.151 72.912 7.475 ;
     RECT  92.832 1.763 103.224 7.475 ;
     RECT  104.544 2.151 105.312 7.957 ;
     RECT  106.608 2.151 108.012 7.957 ;
     RECT  31.296 7.475 35.112 8.003 ;
     RECT  47.568 6.035 48.612 8.003 ;
     RECT  79.968 6.899 89.112 8.003 ;
     RECT  93.216 7.475 103.224 8.003 ;
     RECT  36.192 6.899 43.32 8.051 ;
     RECT  33.504 8.003 35.112 8.579 ;
     RECT  44.352 6.035 46.584 8.579 ;
     RECT  31.296 8.003 32.412 8.771 ;
     RECT  93.216 8.003 102.888 8.965 ;
     RECT  45.6 8.579 46.584 9.061 ;
     RECT  47.712 8.003 48.612 9.061 ;
     RECT  9.408 2.151 16.212 9.155 ;
     RECT  60.768 2.137 68.616 9.155 ;
     RECT  74.016 2.151 78.312 9.155 ;
     RECT  36.192 8.051 40.632 9.397 ;
     RECT  41.616 8.051 43.32 9.397 ;
     RECT  45.6 9.061 48.612 9.637 ;
     RECT  49.776 2.151 59.412 9.637 ;
     RECT  60.768 9.155 68.424 9.731 ;
     RECT  69.6 7.475 71.352 9.731 ;
     RECT  79.968 8.003 84.216 9.731 ;
     RECT  45.6 9.637 59.412 9.827 ;
     RECT  90.144 6.899 91.812 9.925 ;
     RECT  93.216 8.965 103.32 9.925 ;
     RECT  66.384 9.731 68.424 10.213 ;
     RECT  69.6 9.731 71.256 10.213 ;
     RECT  79.968 9.731 83.712 10.213 ;
     RECT  33.504 8.579 33.672 10.307 ;
     RECT  53.568 9.827 59.412 10.307 ;
     RECT  17.856 6.899 19.944 10.405 ;
     RECT  10.08 9.155 16.212 10.501 ;
     RECT  26.208 7.475 29.712 10.501 ;
     RECT  74.352 9.155 78.312 10.501 ;
     RECT  79.344 10.213 83.712 10.501 ;
     RECT  74.352 10.501 83.712 10.693 ;
     RECT  85.2 8.003 89.112 10.693 ;
     RECT  44.352 8.579 44.376 10.741 ;
     RECT  45.6 9.827 52.488 10.741 ;
     RECT  66.384 10.213 71.256 10.741 ;
     RECT  66.384 10.741 71.304 10.789 ;
     RECT  72.336 7.475 72.912 10.789 ;
     RECT  4.464 2.137 8.112 10.883 ;
     RECT  104.544 7.957 108.012 10.931 ;
     RECT  20.928 6.899 24.696 10.933 ;
     RECT  26.16 10.501 29.712 10.933 ;
     RECT  34.8 8.579 35.112 10.933 ;
     RECT  36.192 9.397 43.32 10.933 ;
     RECT  34.8 10.933 43.32 10.981 ;
     RECT  44.352 10.741 52.488 10.981 ;
     RECT  66.384 10.789 72.912 11.029 ;
     RECT  20.928 10.933 29.712 11.173 ;
     RECT  32.1 8.771 32.412 11.221 ;
     RECT  33.504 10.307 33.528 11.221 ;
     RECT  74.352 10.693 89.112 11.221 ;
     RECT  90.144 9.925 103.32 11.221 ;
     RECT  34.8 10.981 52.488 11.317 ;
     RECT  53.568 10.307 57.864 11.317 ;
     RECT  58.896 10.307 59.412 11.317 ;
     RECT  60.768 9.731 64.968 11.317 ;
     RECT  66.384 11.029 73.128 11.317 ;
     RECT  74.352 11.221 103.32 11.317 ;
     RECT  10.08 10.501 16.584 11.365 ;
     RECT  17.568 10.405 19.944 11.365 ;
     RECT  20.928 11.173 29.832 11.365 ;
     RECT  34.656 11.317 52.488 11.365 ;
     RECT  53.568 11.317 59.412 11.365 ;
     RECT  60.768 11.317 65.208 11.365 ;
     RECT  104.88 10.931 108.012 11.653 ;
     RECT  104.88 11.653 108.12 11.701 ;
     RECT  109.152 2.151 110.712 11.701 ;
     RECT  9.888 11.365 29.832 11.749 ;
     RECT  31.056 11.413 31.08 11.749 ;
     RECT  32.1 11.221 33.528 11.749 ;
     RECT  31.056 11.749 33.672 11.845 ;
     RECT  34.656 11.365 59.412 11.845 ;
     RECT  60.72 11.365 65.208 11.845 ;
     RECT  31.056 11.845 65.208 11.893 ;
     RECT  66.384 11.317 103.32 11.893 ;
     RECT  31.056 11.893 103.32 11.941 ;
     RECT  9.36 11.749 29.832 11.989 ;
     RECT  30.816 11.941 103.752 11.989 ;
     RECT  9.36 11.989 103.752 12.037 ;
     RECT  104.88 11.701 110.712 12.037 ;
     RECT  9.36 12.037 110.712 12.229 ;
     RECT  4.464 10.883 6.552 12.997 ;
     RECT  7.584 10.883 8.112 12.997 ;
     RECT  9.12 12.229 110.712 13.091 ;
     RECT  9.12 13.091 30.84 13.187 ;
     RECT  31.872 13.091 110.712 13.331 ;
     RECT  4.464 12.997 8.112 13.573 ;
     RECT  9.12 13.187 30.312 13.573 ;
     RECT  4.464 13.573 30.312 14.291 ;
     RECT  31.872 13.331 103.896 14.389 ;
     RECT  104.88 13.331 110.712 14.389 ;
     RECT  4.512 14.291 30.312 14.773 ;
     RECT  31.872 14.389 110.712 14.773 ;
     RECT  4.512 14.773 110.712 14.867 ;
     RECT  4.512 14.867 108.984 15.829 ;
     RECT  3.936 15.829 108.984 16.067 ;
     RECT  85.056 16.067 108.984 16.453 ;
     RECT  85.056 16.453 109.032 16.501 ;
     RECT  110.16 14.867 110.712 16.501 ;
     RECT  3.936 16.067 83.88 16.595 ;
     RECT  4.32 16.595 83.88 17.461 ;
     RECT  85.056 16.501 110.712 17.461 ;
     RECT  2.4 2.151 2.712 19.449 ;
     RECT  4.32 17.461 110.712 19.449 ;
     RECT  2.4 19.449 2.52 19.463 ;
     RECT  4.32 19.449 110.52 19.463 ;
     RECT  4.32 19.463 110.184 21.408 ;
     RECT  4.344 21.408 4.464 21.456 ;
     RECT  4.488 21.408 4.656 21.456 ;
     RECT  4.68 21.408 4.8 21.456 ;
     RECT  4.824 21.408 4.992 21.456 ;
     RECT  5.016 21.408 5.136 21.456 ;
     RECT  5.16 21.408 5.328 21.456 ;
     RECT  5.352 21.408 5.472 21.456 ;
     RECT  5.496 21.408 5.664 21.456 ;
     RECT  5.688 21.408 5.856 21.456 ;
     RECT  5.88 21.408 6 21.456 ;
     RECT  6.024 21.408 6.192 21.456 ;
     RECT  6.216 21.408 6.336 21.456 ;
     RECT  6.36 21.408 6.528 21.456 ;
     RECT  6.552 21.408 6.672 21.456 ;
     RECT  6.696 21.408 6.864 21.456 ;
     RECT  6.888 21.408 7.008 21.456 ;
     RECT  7.032 21.408 7.2 21.456 ;
     RECT  7.224 21.408 7.344 21.456 ;
     RECT  7.368 21.408 7.536 21.456 ;
     RECT  7.56 21.408 7.68 21.456 ;
     RECT  7.704 21.408 7.872 21.456 ;
     RECT  7.896 21.408 8.016 21.456 ;
     RECT  8.04 21.408 8.208 21.456 ;
     RECT  8.232 21.408 8.4 21.456 ;
     RECT  8.424 21.408 8.544 21.456 ;
     RECT  8.568 21.408 8.736 21.456 ;
     RECT  8.76 21.408 8.88 21.456 ;
     RECT  8.904 21.408 9.072 21.456 ;
     RECT  9.096 21.408 9.216 21.456 ;
     RECT  9.24 21.408 9.408 21.456 ;
     RECT  9.432 21.408 9.552 21.456 ;
     RECT  9.576 21.408 9.744 21.456 ;
     RECT  9.768 21.408 9.888 21.456 ;
     RECT  9.912 21.408 10.08 21.456 ;
     RECT  10.104 21.408 10.224 21.456 ;
     RECT  10.248 21.408 10.416 21.456 ;
     RECT  10.44 21.408 10.56 21.456 ;
     RECT  10.584 21.408 10.752 21.456 ;
     RECT  10.776 21.408 10.944 21.456 ;
     RECT  10.968 21.408 11.088 21.456 ;
     RECT  11.112 21.408 11.28 21.456 ;
     RECT  11.304 21.408 11.424 21.456 ;
     RECT  11.448 21.408 11.616 21.456 ;
     RECT  11.64 21.408 11.76 21.456 ;
     RECT  11.784 21.408 11.952 21.456 ;
     RECT  11.976 21.408 12.096 21.456 ;
     RECT  12.12 21.408 12.288 21.456 ;
     RECT  12.312 21.408 12.432 21.456 ;
     RECT  12.456 21.408 12.624 21.456 ;
     RECT  12.648 21.408 12.768 21.456 ;
     RECT  12.792 21.408 12.96 21.456 ;
     RECT  12.984 21.408 13.152 21.456 ;
     RECT  13.176 21.408 13.296 21.456 ;
     RECT  13.32 21.408 13.488 21.456 ;
     RECT  13.512 21.408 13.632 21.456 ;
     RECT  13.656 21.408 13.824 21.456 ;
     RECT  13.848 21.408 13.968 21.456 ;
     RECT  13.992 21.408 14.16 21.456 ;
     RECT  14.184 21.408 14.304 21.456 ;
     RECT  14.328 21.408 14.496 21.456 ;
     RECT  14.52 21.408 14.64 21.456 ;
     RECT  14.664 21.408 14.832 21.456 ;
     RECT  14.856 21.408 14.976 21.456 ;
     RECT  15 21.408 15.168 21.456 ;
     RECT  15.192 21.408 15.312 21.456 ;
     RECT  15.336 21.408 15.504 21.456 ;
     RECT  15.528 21.408 15.696 21.456 ;
     RECT  15.72 21.408 15.84 21.456 ;
     RECT  15.864 21.408 16.032 21.456 ;
     RECT  16.056 21.408 16.176 21.456 ;
     RECT  16.2 21.408 16.368 21.456 ;
     RECT  16.392 21.408 16.512 21.456 ;
     RECT  16.536 21.408 16.704 21.456 ;
     RECT  16.728 21.408 16.848 21.456 ;
     RECT  16.872 21.408 17.04 21.456 ;
     RECT  17.064 21.408 17.184 21.456 ;
     RECT  17.208 21.408 17.376 21.456 ;
     RECT  17.4 21.408 17.52 21.456 ;
     RECT  17.544 21.408 17.712 21.456 ;
     RECT  17.736 21.408 17.856 21.456 ;
     RECT  17.88 21.408 18.048 21.456 ;
     RECT  18.072 21.408 18.24 21.456 ;
     RECT  18.264 21.408 18.384 21.456 ;
     RECT  18.408 21.408 18.576 21.456 ;
     RECT  18.6 21.408 18.72 21.456 ;
     RECT  18.744 21.408 18.912 21.456 ;
     RECT  18.936 21.408 19.056 21.456 ;
     RECT  19.08 21.408 19.248 21.456 ;
     RECT  19.272 21.408 19.392 21.456 ;
     RECT  19.416 21.408 19.584 21.456 ;
     RECT  19.608 21.408 19.728 21.456 ;
     RECT  19.752 21.408 19.92 21.456 ;
     RECT  19.944 21.408 20.064 21.456 ;
     RECT  20.088 21.408 20.256 21.456 ;
     RECT  20.28 21.408 20.4 21.456 ;
     RECT  20.424 21.408 20.592 21.456 ;
     RECT  20.616 21.408 20.784 21.456 ;
     RECT  20.808 21.408 20.928 21.456 ;
     RECT  20.952 21.408 21.12 21.456 ;
     RECT  21.144 21.408 21.264 21.456 ;
     RECT  21.288 21.408 21.456 21.456 ;
     RECT  21.48 21.408 21.6 21.456 ;
     RECT  21.624 21.408 21.792 21.456 ;
     RECT  21.816 21.408 21.936 21.456 ;
     RECT  21.96 21.408 22.128 21.456 ;
     RECT  22.152 21.408 22.272 21.456 ;
     RECT  22.296 21.408 22.464 21.456 ;
     RECT  22.488 21.408 22.608 21.456 ;
     RECT  22.632 21.408 22.8 21.456 ;
     RECT  22.824 21.408 22.944 21.456 ;
     RECT  22.968 21.408 23.136 21.456 ;
     RECT  23.16 21.408 23.328 21.456 ;
     RECT  23.352 21.408 23.472 21.456 ;
     RECT  23.496 21.408 23.664 21.456 ;
     RECT  23.688 21.408 23.808 21.456 ;
     RECT  23.832 21.408 24 21.456 ;
     RECT  24.024 21.408 24.144 21.456 ;
     RECT  24.168 21.408 24.336 21.456 ;
     RECT  24.36 21.408 24.48 21.456 ;
     RECT  24.504 21.408 24.672 21.456 ;
     RECT  24.696 21.408 24.816 21.456 ;
     RECT  24.84 21.408 25.008 21.456 ;
     RECT  25.032 21.408 25.152 21.456 ;
     RECT  25.176 21.408 25.344 21.456 ;
     RECT  25.368 21.408 25.488 21.456 ;
     RECT  25.512 21.408 25.68 21.456 ;
     RECT  25.704 21.408 25.872 21.456 ;
     RECT  25.896 21.408 26.016 21.456 ;
     RECT  26.04 21.408 26.208 21.456 ;
     RECT  26.232 21.408 26.352 21.456 ;
     RECT  26.376 21.408 26.544 21.456 ;
     RECT  26.568 21.408 26.688 21.456 ;
     RECT  26.712 21.408 26.88 21.456 ;
     RECT  26.904 21.408 27.024 21.456 ;
     RECT  27.048 21.408 27.216 21.456 ;
     RECT  27.24 21.408 27.36 21.456 ;
     RECT  27.384 21.408 27.552 21.456 ;
     RECT  27.576 21.408 27.696 21.456 ;
     RECT  27.72 21.408 27.888 21.456 ;
     RECT  27.912 21.408 28.032 21.456 ;
     RECT  28.056 21.408 28.224 21.456 ;
     RECT  28.248 21.408 28.416 21.456 ;
     RECT  28.44 21.408 28.56 21.456 ;
     RECT  28.584 21.408 28.752 21.456 ;
     RECT  28.776 21.408 28.896 21.456 ;
     RECT  28.92 21.408 29.088 21.456 ;
     RECT  29.112 21.408 29.232 21.456 ;
     RECT  29.256 21.408 29.424 21.456 ;
     RECT  29.448 21.408 29.568 21.456 ;
     RECT  29.592 21.408 29.76 21.456 ;
     RECT  29.784 21.408 29.904 21.456 ;
     RECT  29.928 21.408 30.096 21.456 ;
     RECT  30.12 21.408 30.24 21.456 ;
     RECT  30.264 21.408 30.432 21.456 ;
     RECT  30.456 21.408 30.576 21.456 ;
     RECT  30.6 21.408 30.768 21.456 ;
     RECT  30.792 21.408 30.96 21.456 ;
     RECT  30.984 21.408 31.104 21.456 ;
     RECT  31.128 21.408 31.296 21.456 ;
     RECT  31.32 21.408 31.44 21.456 ;
     RECT  31.464 21.408 31.632 21.456 ;
     RECT  31.656 21.408 31.776 21.456 ;
     RECT  31.8 21.408 31.968 21.456 ;
     RECT  31.992 21.408 32.112 21.456 ;
     RECT  32.136 21.408 32.304 21.456 ;
     RECT  32.328 21.408 32.448 21.456 ;
     RECT  32.472 21.408 32.64 21.456 ;
     RECT  32.664 21.408 32.784 21.456 ;
     RECT  32.808 21.408 32.976 21.456 ;
     RECT  33 21.408 33.12 21.456 ;
     RECT  33.144 21.408 33.312 21.456 ;
     RECT  33.336 21.408 33.504 21.456 ;
     RECT  33.528 21.408 33.648 21.456 ;
     RECT  33.672 21.408 33.84 21.456 ;
     RECT  33.864 21.408 33.984 21.456 ;
     RECT  34.008 21.408 34.176 21.456 ;
     RECT  34.2 21.408 34.32 21.456 ;
     RECT  34.344 21.408 34.512 21.456 ;
     RECT  34.536 21.408 34.656 21.456 ;
     RECT  34.68 21.408 34.848 21.456 ;
     RECT  34.872 21.408 34.992 21.456 ;
     RECT  35.016 21.408 35.184 21.456 ;
     RECT  35.208 21.408 35.328 21.456 ;
     RECT  35.352 21.408 35.52 21.456 ;
     RECT  35.544 21.408 35.664 21.456 ;
     RECT  35.688 21.408 35.856 21.456 ;
     RECT  35.88 21.408 36.048 21.456 ;
     RECT  36.072 21.408 36.192 21.456 ;
     RECT  36.216 21.408 36.384 21.456 ;
     RECT  36.408 21.408 36.528 21.456 ;
     RECT  36.552 21.408 36.72 21.456 ;
     RECT  36.744 21.408 36.864 21.456 ;
     RECT  36.888 21.408 37.056 21.456 ;
     RECT  37.08 21.408 37.2 21.456 ;
     RECT  37.224 21.408 37.392 21.456 ;
     RECT  37.416 21.408 37.536 21.456 ;
     RECT  37.56 21.408 37.728 21.456 ;
     RECT  37.752 21.408 37.872 21.456 ;
     RECT  37.896 21.408 38.064 21.456 ;
     RECT  38.088 21.408 38.208 21.456 ;
     RECT  38.232 21.408 38.4 21.456 ;
     RECT  38.424 21.408 38.592 21.456 ;
     RECT  38.616 21.408 38.736 21.456 ;
     RECT  38.76 21.408 38.928 21.456 ;
     RECT  38.952 21.408 39.072 21.456 ;
     RECT  39.096 21.408 39.264 21.456 ;
     RECT  39.288 21.408 39.408 21.456 ;
     RECT  39.432 21.408 39.6 21.456 ;
     RECT  39.624 21.408 39.744 21.456 ;
     RECT  39.768 21.408 39.936 21.456 ;
     RECT  39.96 21.408 40.08 21.456 ;
     RECT  40.104 21.408 40.272 21.456 ;
     RECT  40.296 21.408 40.416 21.456 ;
     RECT  40.44 21.408 40.608 21.456 ;
     RECT  40.632 21.408 40.752 21.456 ;
     RECT  40.776 21.408 40.944 21.456 ;
     RECT  40.968 21.408 41.136 21.456 ;
     RECT  41.16 21.408 41.28 21.456 ;
     RECT  41.304 21.408 41.472 21.456 ;
     RECT  41.496 21.408 41.616 21.456 ;
     RECT  41.64 21.408 41.808 21.456 ;
     RECT  41.832 21.408 41.952 21.456 ;
     RECT  41.976 21.408 42.144 21.456 ;
     RECT  42.168 21.408 42.288 21.456 ;
     RECT  42.312 21.408 42.48 21.456 ;
     RECT  42.504 21.408 42.624 21.456 ;
     RECT  42.648 21.408 42.816 21.456 ;
     RECT  42.84 21.408 42.96 21.456 ;
     RECT  42.984 21.408 43.152 21.456 ;
     RECT  43.176 21.408 43.296 21.456 ;
     RECT  43.32 21.408 43.488 21.456 ;
     RECT  43.512 21.408 43.68 21.456 ;
     RECT  43.704 21.408 43.824 21.456 ;
     RECT  43.848 21.408 44.016 21.456 ;
     RECT  44.04 21.408 44.16 21.456 ;
     RECT  44.184 21.408 44.352 21.456 ;
     RECT  44.376 21.408 44.496 21.456 ;
     RECT  44.52 21.408 44.688 21.456 ;
     RECT  44.712 21.408 44.832 21.456 ;
     RECT  44.856 21.408 45.024 21.456 ;
     RECT  45.048 21.408 45.168 21.456 ;
     RECT  45.192 21.408 45.36 21.456 ;
     RECT  45.384 21.408 45.504 21.456 ;
     RECT  45.528 21.408 45.696 21.456 ;
     RECT  45.72 21.408 45.84 21.456 ;
     RECT  45.864 21.408 46.032 21.456 ;
     RECT  46.056 21.408 46.224 21.456 ;
     RECT  46.248 21.408 46.368 21.456 ;
     RECT  46.392 21.408 46.56 21.456 ;
     RECT  46.584 21.408 46.704 21.456 ;
     RECT  46.728 21.408 46.896 21.456 ;
     RECT  46.92 21.408 47.04 21.456 ;
     RECT  47.064 21.408 47.232 21.456 ;
     RECT  47.256 21.408 47.376 21.456 ;
     RECT  47.4 21.408 47.568 21.456 ;
     RECT  47.592 21.408 47.712 21.456 ;
     RECT  47.736 21.408 47.904 21.456 ;
     RECT  47.928 21.408 48.048 21.456 ;
     RECT  48.072 21.408 48.24 21.456 ;
     RECT  48.264 21.408 48.384 21.456 ;
     RECT  48.408 21.408 48.576 21.456 ;
     RECT  48.6 21.408 48.768 21.456 ;
     RECT  48.792 21.408 48.912 21.456 ;
     RECT  48.936 21.408 49.104 21.456 ;
     RECT  49.128 21.408 49.248 21.456 ;
     RECT  49.272 21.408 49.44 21.456 ;
     RECT  49.464 21.408 49.584 21.456 ;
     RECT  49.608 21.408 49.776 21.456 ;
     RECT  49.8 21.408 49.92 21.456 ;
     RECT  49.944 21.408 50.112 21.456 ;
     RECT  50.136 21.408 50.256 21.456 ;
     RECT  50.28 21.408 50.448 21.456 ;
     RECT  50.472 21.408 50.592 21.456 ;
     RECT  50.616 21.408 50.784 21.456 ;
     RECT  50.808 21.408 50.976 21.456 ;
     RECT  51 21.408 51.12 21.456 ;
     RECT  51.144 21.408 51.312 21.456 ;
     RECT  51.336 21.408 51.456 21.456 ;
     RECT  51.48 21.408 51.648 21.456 ;
     RECT  51.672 21.408 51.792 21.456 ;
     RECT  51.816 21.408 51.984 21.456 ;
     RECT  52.008 21.408 52.128 21.456 ;
     RECT  52.152 21.408 52.32 21.456 ;
     RECT  52.344 21.408 52.464 21.456 ;
     RECT  52.488 21.408 52.656 21.456 ;
     RECT  52.68 21.408 52.8 21.456 ;
     RECT  52.824 21.408 52.992 21.456 ;
     RECT  53.016 21.408 53.136 21.456 ;
     RECT  53.16 21.408 53.328 21.456 ;
     RECT  53.352 21.408 53.52 21.456 ;
     RECT  53.544 21.408 53.664 21.456 ;
     RECT  53.688 21.408 53.856 21.456 ;
     RECT  53.88 21.408 54 21.456 ;
     RECT  54.024 21.408 54.192 21.456 ;
     RECT  54.216 21.408 54.336 21.456 ;
     RECT  54.36 21.408 54.528 21.456 ;
     RECT  54.552 21.408 54.672 21.456 ;
     RECT  54.696 21.408 54.864 21.456 ;
     RECT  54.888 21.408 55.008 21.456 ;
     RECT  55.032 21.408 55.2 21.456 ;
     RECT  55.224 21.408 55.344 21.456 ;
     RECT  55.368 21.408 55.536 21.456 ;
     RECT  55.56 21.408 55.68 21.456 ;
     RECT  55.704 21.408 55.872 21.456 ;
     RECT  55.896 21.408 56.064 21.456 ;
     RECT  56.088 21.408 56.208 21.456 ;
     RECT  56.232 21.408 56.4 21.456 ;
     RECT  56.424 21.408 56.544 21.456 ;
     RECT  56.568 21.408 56.736 21.456 ;
     RECT  56.76 21.408 56.88 21.456 ;
     RECT  56.904 21.408 57.072 21.456 ;
     RECT  57.096 21.408 57.216 21.456 ;
     RECT  57.24 21.408 57.408 21.456 ;
     RECT  57.432 21.408 57.552 21.456 ;
     RECT  57.576 21.408 57.744 21.456 ;
     RECT  57.768 21.408 57.888 21.456 ;
     RECT  57.912 21.408 58.08 21.456 ;
     RECT  58.104 21.408 58.224 21.456 ;
     RECT  58.248 21.408 58.416 21.456 ;
     RECT  58.44 21.408 58.608 21.456 ;
     RECT  58.632 21.408 58.752 21.456 ;
     RECT  58.776 21.408 58.944 21.456 ;
     RECT  58.968 21.408 59.088 21.456 ;
     RECT  59.112 21.408 59.28 21.456 ;
     RECT  59.304 21.408 59.424 21.456 ;
     RECT  59.448 21.408 59.616 21.456 ;
     RECT  59.64 21.408 59.76 21.456 ;
     RECT  59.784 21.408 59.952 21.456 ;
     RECT  59.976 21.408 60.096 21.456 ;
     RECT  60.12 21.408 60.288 21.456 ;
     RECT  60.312 21.408 60.432 21.456 ;
     RECT  60.456 21.408 60.624 21.456 ;
     RECT  60.648 21.408 60.768 21.456 ;
     RECT  60.792 21.408 60.96 21.456 ;
     RECT  60.984 21.408 61.152 21.456 ;
     RECT  61.176 21.408 61.296 21.456 ;
     RECT  61.32 21.408 61.488 21.456 ;
     RECT  61.512 21.408 61.632 21.456 ;
     RECT  61.656 21.408 61.824 21.456 ;
     RECT  61.848 21.408 61.968 21.456 ;
     RECT  61.992 21.408 62.16 21.456 ;
     RECT  62.184 21.408 62.304 21.456 ;
     RECT  62.328 21.408 62.496 21.456 ;
     RECT  62.52 21.408 62.64 21.456 ;
     RECT  62.664 21.408 62.832 21.456 ;
     RECT  62.856 21.408 62.976 21.456 ;
     RECT  63 21.408 63.168 21.456 ;
     RECT  63.192 21.408 63.312 21.456 ;
     RECT  63.336 21.408 63.504 21.456 ;
     RECT  63.528 21.408 63.696 21.456 ;
     RECT  63.72 21.408 63.84 21.456 ;
     RECT  63.864 21.408 64.032 21.456 ;
     RECT  64.056 21.408 64.176 21.456 ;
     RECT  64.2 21.408 64.368 21.456 ;
     RECT  64.392 21.408 64.512 21.456 ;
     RECT  64.536 21.408 64.704 21.456 ;
     RECT  64.728 21.408 64.848 21.456 ;
     RECT  64.872 21.408 65.04 21.456 ;
     RECT  65.064 21.408 65.184 21.456 ;
     RECT  65.208 21.408 65.376 21.456 ;
     RECT  65.4 21.408 65.52 21.456 ;
     RECT  65.544 21.408 65.712 21.456 ;
     RECT  65.736 21.408 65.856 21.456 ;
     RECT  65.88 21.408 66.048 21.456 ;
     RECT  66.072 21.408 66.24 21.456 ;
     RECT  66.264 21.408 66.384 21.456 ;
     RECT  66.408 21.408 66.576 21.456 ;
     RECT  66.6 21.408 66.72 21.456 ;
     RECT  66.744 21.408 66.912 21.456 ;
     RECT  66.936 21.408 67.056 21.456 ;
     RECT  67.08 21.408 67.248 21.456 ;
     RECT  67.272 21.408 67.392 21.456 ;
     RECT  67.416 21.408 67.584 21.456 ;
     RECT  67.608 21.408 67.728 21.456 ;
     RECT  67.752 21.408 67.92 21.456 ;
     RECT  67.944 21.408 68.064 21.456 ;
     RECT  68.088 21.408 68.256 21.456 ;
     RECT  68.28 21.408 68.4 21.456 ;
     RECT  68.424 21.408 68.592 21.456 ;
     RECT  68.616 21.408 68.784 21.456 ;
     RECT  68.808 21.408 68.928 21.456 ;
     RECT  68.952 21.408 69.12 21.456 ;
     RECT  69.144 21.408 69.264 21.456 ;
     RECT  69.288 21.408 69.456 21.456 ;
     RECT  69.48 21.408 69.6 21.456 ;
     RECT  69.624 21.408 69.792 21.456 ;
     RECT  69.816 21.408 69.936 21.456 ;
     RECT  69.96 21.408 70.128 21.456 ;
     RECT  70.152 21.408 70.272 21.456 ;
     RECT  70.296 21.408 70.464 21.456 ;
     RECT  70.488 21.408 70.608 21.456 ;
     RECT  70.632 21.408 70.8 21.456 ;
     RECT  70.824 21.408 70.944 21.456 ;
     RECT  70.968 21.408 71.136 21.456 ;
     RECT  71.16 21.408 71.328 21.456 ;
     RECT  71.352 21.408 71.472 21.456 ;
     RECT  71.496 21.408 71.664 21.456 ;
     RECT  71.688 21.408 71.808 21.456 ;
     RECT  71.832 21.408 72 21.456 ;
     RECT  72.024 21.408 72.144 21.456 ;
     RECT  72.168 21.408 72.336 21.456 ;
     RECT  72.36 21.408 72.48 21.456 ;
     RECT  72.504 21.408 72.672 21.456 ;
     RECT  72.696 21.408 72.816 21.456 ;
     RECT  72.84 21.408 73.008 21.456 ;
     RECT  73.032 21.408 73.152 21.456 ;
     RECT  73.176 21.408 73.344 21.456 ;
     RECT  73.368 21.408 73.488 21.456 ;
     RECT  73.512 21.408 73.68 21.456 ;
     RECT  73.704 21.408 73.872 21.456 ;
     RECT  73.896 21.408 74.016 21.456 ;
     RECT  74.04 21.408 74.208 21.456 ;
     RECT  74.232 21.408 74.352 21.456 ;
     RECT  74.376 21.408 74.544 21.456 ;
     RECT  74.568 21.408 74.688 21.456 ;
     RECT  74.712 21.408 74.88 21.456 ;
     RECT  74.904 21.408 75.024 21.456 ;
     RECT  75.048 21.408 75.216 21.456 ;
     RECT  75.24 21.408 75.36 21.456 ;
     RECT  75.384 21.408 75.552 21.456 ;
     RECT  75.576 21.408 75.696 21.456 ;
     RECT  75.72 21.408 75.888 21.456 ;
     RECT  75.912 21.408 76.032 21.456 ;
     RECT  76.056 21.408 76.224 21.456 ;
     RECT  76.248 21.408 76.416 21.456 ;
     RECT  76.44 21.408 76.56 21.456 ;
     RECT  76.584 21.408 76.752 21.456 ;
     RECT  76.776 21.408 76.896 21.456 ;
     RECT  76.92 21.408 77.088 21.456 ;
     RECT  77.112 21.408 77.232 21.456 ;
     RECT  77.256 21.408 77.424 21.456 ;
     RECT  77.448 21.408 77.568 21.456 ;
     RECT  77.592 21.408 77.76 21.456 ;
     RECT  77.784 21.408 77.904 21.456 ;
     RECT  77.928 21.408 78.096 21.456 ;
     RECT  78.12 21.408 78.24 21.456 ;
     RECT  78.264 21.408 78.432 21.456 ;
     RECT  78.456 21.408 78.576 21.456 ;
     RECT  78.6 21.408 78.768 21.456 ;
     RECT  78.792 21.408 78.96 21.456 ;
     RECT  78.984 21.408 79.104 21.456 ;
     RECT  79.128 21.408 79.296 21.456 ;
     RECT  79.32 21.408 79.44 21.456 ;
     RECT  79.464 21.408 79.632 21.456 ;
     RECT  79.656 21.408 79.776 21.456 ;
     RECT  79.8 21.408 79.968 21.456 ;
     RECT  79.992 21.408 80.112 21.456 ;
     RECT  80.136 21.408 80.304 21.456 ;
     RECT  80.328 21.408 80.448 21.456 ;
     RECT  80.472 21.408 80.64 21.456 ;
     RECT  80.664 21.408 80.784 21.456 ;
     RECT  80.808 21.408 80.976 21.456 ;
     RECT  81 21.408 81.12 21.456 ;
     RECT  81.144 21.408 81.312 21.456 ;
     RECT  81.336 21.408 81.504 21.456 ;
     RECT  81.528 21.408 81.648 21.456 ;
     RECT  81.672 21.408 81.84 21.456 ;
     RECT  81.864 21.408 81.984 21.456 ;
     RECT  82.008 21.408 82.176 21.456 ;
     RECT  82.2 21.408 82.32 21.456 ;
     RECT  82.344 21.408 82.512 21.456 ;
     RECT  82.536 21.408 82.656 21.456 ;
     RECT  82.68 21.408 82.848 21.456 ;
     RECT  82.872 21.408 82.992 21.456 ;
     RECT  83.016 21.408 83.184 21.456 ;
     RECT  83.208 21.408 83.328 21.456 ;
     RECT  83.352 21.408 83.52 21.456 ;
     RECT  83.544 21.408 83.664 21.456 ;
     RECT  83.688 21.408 83.856 21.456 ;
     RECT  83.88 21.408 84.048 21.456 ;
     RECT  84.072 21.408 84.192 21.456 ;
     RECT  84.216 21.408 84.384 21.456 ;
     RECT  84.408 21.408 84.528 21.456 ;
     RECT  84.552 21.408 84.72 21.456 ;
     RECT  84.744 21.408 84.864 21.456 ;
     RECT  84.888 21.408 85.056 21.456 ;
     RECT  85.08 21.408 85.2 21.456 ;
     RECT  85.224 21.408 85.392 21.456 ;
     RECT  85.416 21.408 85.536 21.456 ;
     RECT  85.56 21.408 85.728 21.456 ;
     RECT  85.752 21.408 85.872 21.456 ;
     RECT  85.896 21.408 86.064 21.456 ;
     RECT  86.088 21.408 86.256 21.456 ;
     RECT  86.28 21.408 86.4 21.456 ;
     RECT  86.424 21.408 86.592 21.456 ;
     RECT  86.616 21.408 86.736 21.456 ;
     RECT  86.76 21.408 86.928 21.456 ;
     RECT  86.952 21.408 87.072 21.456 ;
     RECT  87.096 21.408 87.264 21.456 ;
     RECT  87.288 21.408 87.408 21.456 ;
     RECT  87.432 21.408 87.6 21.456 ;
     RECT  87.624 21.408 87.744 21.456 ;
     RECT  87.768 21.408 87.936 21.456 ;
     RECT  87.96 21.408 88.08 21.456 ;
     RECT  88.104 21.408 88.272 21.456 ;
     RECT  88.296 21.408 88.416 21.456 ;
     RECT  88.44 21.408 88.608 21.456 ;
     RECT  88.632 21.408 88.8 21.456 ;
     RECT  88.824 21.408 88.944 21.456 ;
     RECT  88.968 21.408 89.136 21.456 ;
     RECT  89.16 21.408 89.28 21.456 ;
     RECT  89.304 21.408 89.472 21.456 ;
     RECT  89.496 21.408 89.616 21.456 ;
     RECT  89.64 21.408 89.808 21.456 ;
     RECT  89.832 21.408 89.952 21.456 ;
     RECT  89.976 21.408 90.144 21.456 ;
     RECT  90.168 21.408 90.288 21.456 ;
     RECT  90.312 21.408 90.48 21.456 ;
     RECT  90.504 21.408 90.624 21.456 ;
     RECT  90.648 21.408 90.816 21.456 ;
     RECT  90.84 21.408 90.96 21.456 ;
     RECT  90.984 21.408 91.152 21.456 ;
     RECT  91.176 21.408 91.344 21.456 ;
     RECT  91.368 21.408 91.488 21.456 ;
     RECT  91.512 21.408 91.68 21.456 ;
     RECT  91.704 21.408 91.824 21.456 ;
     RECT  91.848 21.408 92.016 21.456 ;
     RECT  92.04 21.408 92.16 21.456 ;
     RECT  92.184 21.408 92.352 21.456 ;
     RECT  92.376 21.408 92.496 21.456 ;
     RECT  92.52 21.408 92.688 21.456 ;
     RECT  92.712 21.408 92.832 21.456 ;
     RECT  92.856 21.408 93.024 21.456 ;
     RECT  93.048 21.408 93.168 21.456 ;
     RECT  93.192 21.408 93.36 21.456 ;
     RECT  93.384 21.408 93.504 21.456 ;
     RECT  93.528 21.408 93.696 21.456 ;
     RECT  93.72 21.408 93.888 21.456 ;
     RECT  93.912 21.408 94.032 21.456 ;
     RECT  94.056 21.408 94.224 21.456 ;
     RECT  94.248 21.408 94.368 21.456 ;
     RECT  94.392 21.408 94.56 21.456 ;
     RECT  94.584 21.408 94.704 21.456 ;
     RECT  94.728 21.408 94.896 21.456 ;
     RECT  94.92 21.408 95.04 21.456 ;
     RECT  95.064 21.408 95.232 21.456 ;
     RECT  95.256 21.408 95.376 21.456 ;
     RECT  95.4 21.408 95.568 21.456 ;
     RECT  95.592 21.408 95.712 21.456 ;
     RECT  95.736 21.408 95.904 21.456 ;
     RECT  95.928 21.408 96.048 21.456 ;
     RECT  96.072 21.408 96.24 21.456 ;
     RECT  96.264 21.408 96.432 21.456 ;
     RECT  96.456 21.408 96.576 21.456 ;
     RECT  96.6 21.408 96.768 21.456 ;
     RECT  96.792 21.408 96.912 21.456 ;
     RECT  96.936 21.408 97.104 21.456 ;
     RECT  97.128 21.408 97.248 21.456 ;
     RECT  97.272 21.408 97.44 21.456 ;
     RECT  97.464 21.408 97.584 21.456 ;
     RECT  97.608 21.408 97.776 21.456 ;
     RECT  97.8 21.408 97.92 21.456 ;
     RECT  97.944 21.408 98.112 21.456 ;
     RECT  98.136 21.408 98.256 21.456 ;
     RECT  98.28 21.408 98.448 21.456 ;
     RECT  98.472 21.408 98.592 21.456 ;
     RECT  98.616 21.408 98.784 21.456 ;
     RECT  98.808 21.408 98.976 21.456 ;
     RECT  99 21.408 99.12 21.456 ;
     RECT  99.144 21.408 99.312 21.456 ;
     RECT  99.336 21.408 99.456 21.456 ;
     RECT  99.48 21.408 99.648 21.456 ;
     RECT  99.672 21.408 99.792 21.456 ;
     RECT  99.816 21.408 99.984 21.456 ;
     RECT  100.008 21.408 100.128 21.456 ;
     RECT  100.152 21.408 100.32 21.456 ;
     RECT  100.344 21.408 100.464 21.456 ;
     RECT  100.488 21.408 100.656 21.456 ;
     RECT  100.68 21.408 100.8 21.456 ;
     RECT  100.824 21.408 100.992 21.456 ;
     RECT  101.016 21.408 101.136 21.456 ;
     RECT  101.16 21.408 101.328 21.456 ;
     RECT  101.352 21.408 101.52 21.456 ;
     RECT  101.544 21.408 101.664 21.456 ;
     RECT  101.688 21.408 101.856 21.456 ;
     RECT  101.88 21.408 102 21.456 ;
     RECT  102.024 21.408 102.192 21.456 ;
     RECT  102.216 21.408 102.336 21.456 ;
     RECT  102.36 21.408 102.528 21.456 ;
     RECT  102.552 21.408 102.672 21.456 ;
     RECT  102.696 21.408 102.864 21.456 ;
     RECT  102.888 21.408 103.008 21.456 ;
     RECT  103.032 21.408 103.2 21.456 ;
     RECT  103.224 21.408 103.344 21.456 ;
     RECT  103.368 21.408 103.536 21.456 ;
     RECT  103.56 21.408 103.68 21.456 ;
     RECT  103.704 21.408 103.872 21.456 ;
     RECT  103.896 21.408 104.064 21.456 ;
     RECT  104.088 21.408 104.208 21.456 ;
     RECT  104.232 21.408 104.4 21.456 ;
     RECT  104.424 21.408 104.544 21.456 ;
     RECT  104.568 21.408 104.736 21.456 ;
     RECT  104.76 21.408 104.88 21.456 ;
     RECT  104.904 21.408 105.072 21.456 ;
     RECT  105.096 21.408 105.216 21.456 ;
     RECT  105.24 21.408 105.408 21.456 ;
     RECT  105.432 21.408 105.552 21.456 ;
     RECT  105.576 21.408 105.744 21.456 ;
     RECT  105.768 21.408 105.888 21.456 ;
     RECT  105.912 21.408 106.08 21.456 ;
     RECT  106.104 21.408 106.224 21.456 ;
     RECT  106.248 21.408 106.416 21.456 ;
     RECT  106.44 21.408 106.608 21.456 ;
     RECT  106.632 21.408 106.752 21.456 ;
     RECT  106.776 21.408 106.944 21.456 ;
     RECT  106.968 21.408 107.088 21.456 ;
     RECT  107.112 21.408 107.28 21.456 ;
     RECT  107.304 21.408 107.424 21.456 ;
     RECT  107.448 21.408 107.616 21.456 ;
     RECT  107.64 21.408 107.76 21.456 ;
     RECT  107.784 21.408 107.952 21.456 ;
     RECT  107.976 21.408 108.096 21.456 ;
     RECT  108.12 21.408 108.288 21.456 ;
     RECT  108.312 21.408 108.432 21.456 ;
     RECT  108.456 21.408 108.624 21.456 ;
     RECT  108.648 21.408 108.768 21.456 ;
     RECT  108.792 21.408 108.96 21.456 ;
     RECT  108.984 21.408 109.152 21.456 ;
     RECT  109.176 21.408 109.296 21.456 ;
     RECT  109.32 21.408 109.488 21.456 ;
     RECT  109.512 21.408 109.632 21.456 ;
     RECT  109.656 21.408 109.824 21.456 ;
     RECT  109.848 21.408 109.968 21.456 ;
     RECT  109.992 21.408 110.16 21.456 ;
     RECT  5.904 21.456 5.928 21.491 ;
     RECT  9.6 21.456 9.624 21.491 ;
     RECT  15.024 21.456 15.048 21.491 ;
     RECT  18.288 21.456 18.384 21.491 ;
     RECT  18.408 21.456 18.576 21.491 ;
     RECT  18.6 21.456 18.72 21.491 ;
     RECT  18.744 21.456 18.912 21.491 ;
     RECT  18.936 21.456 19.056 21.491 ;
     RECT  19.08 21.456 19.248 21.491 ;
     RECT  19.272 21.456 19.32 21.491 ;
     RECT  20.832 21.456 20.856 21.491 ;
     RECT  31.488 21.456 31.512 21.491 ;
     RECT  33.888 21.456 33.984 21.491 ;
     RECT  34.008 21.456 34.176 21.491 ;
     RECT  34.2 21.456 34.32 21.491 ;
     RECT  34.344 21.456 34.512 21.491 ;
     RECT  34.536 21.456 34.656 21.491 ;
     RECT  34.68 21.456 34.728 21.491 ;
     RECT  45.408 21.456 45.432 21.491 ;
     RECT  54.912 21.456 55.008 21.491 ;
     RECT  55.032 21.456 55.2 21.491 ;
     RECT  55.224 21.456 55.344 21.491 ;
     RECT  55.368 21.456 55.416 21.491 ;
     RECT  58.8 21.456 58.824 21.491 ;
     RECT  77.28 21.456 77.304 21.491 ;
     RECT  79.584 21.456 79.608 21.491 ;
     RECT  81.696 21.456 81.72 21.491 ;
     RECT  99.408 21.456 99.432 21.491 ;
     RECT  15.336 0.275 16.704 0.563 ;
     RECT  48.408 0.275 49.44 0.323 ;
     RECT  4.824 0.323 6 0.563 ;
     RECT  48.264 0.323 49.44 0.563 ;
     RECT  77.928 0.323 78.96 0.563 ;
     RECT  88.296 0.323 89.28 2.137 ;
     RECT  104.76 0.323 105.744 0.563 ;
     RECT  21.144 0.371 22.128 0.419 ;
     RECT  29.208 0.371 30.24 0.419 ;
     RECT  34.68 0.371 35.664 0.563 ;
     RECT  67.08 0.371 68.064 2.137 ;
     RECT  69.816 0.371 70.8 0.563 ;
     RECT  72.36 0.371 73.344 0.419 ;
     RECT  107.64 0.371 109.152 2.137 ;
     RECT  20.952 0.419 22.128 2.137 ;
     RECT  29.208 0.419 30.432 2.137 ;
     RECT  37.224 0.419 38.208 0.467 ;
     RECT  72.36 0.419 73.68 0.563 ;
     RECT  91.704 0.419 92.832 0.611 ;
     RECT  37.224 0.467 38.4 0.611 ;
     RECT  4.488 0.563 6 2.137 ;
     RECT  8.424 0.563 9.408 1.763 ;
     RECT  24.696 0.563 25.68 6.899 ;
     RECT  34.68 0.563 35.856 2.137 ;
     RECT  48.264 0.563 49.584 0.611 ;
     RECT  53.544 0.563 54.672 2.137 ;
     RECT  61.512 0.563 62.64 2.137 ;
     RECT  64.392 0.563 65.376 2.137 ;
     RECT  68.616 0.563 69.6 9.155 ;
     RECT  69.624 0.563 70.8 2.137 ;
     RECT  36.888 0.611 38.4 2.137 ;
     RECT  48.264 0.611 49.776 2.137 ;
     RECT  56.232 0.611 57.216 2.137 ;
     RECT  58.632 0.611 59.112 2.137 ;
     RECT  80.472 0.611 81.84 2.137 ;
     RECT  91.368 0.611 92.832 2.137 ;
     RECT  8.112 1.763 9.408 9.155 ;
     RECT  103.224 1.763 104.544 8.003 ;
     RECT  48.42 2.137 49.776 2.151 ;
     RECT  72.72 2.137 74.016 2.151 ;
     RECT  80.82 2.137 81.84 2.151 ;
     RECT  91.62 2.137 92.832 2.151 ;
     RECT  105.12 2.137 106.608 2.151 ;
     RECT  107.82 2.137 109.152 2.151 ;
     RECT  48.612 2.151 49.776 9.637 ;
     RECT  59.412 2.151 60.768 11.365 ;
     RECT  72.912 2.151 74.016 9.155 ;
     RECT  91.812 2.151 92.832 7.475 ;
     RECT  105.312 2.151 106.608 7.957 ;
     RECT  108.012 2.151 109.152 11.653 ;
     RECT  43.32 5.747 44.352 10.981 ;
     RECT  46.584 6.035 47.568 8.003 ;
     RECT  19.944 6.899 20.928 11.365 ;
     RECT  24.696 6.899 25.872 7.475 ;
     RECT  35.112 6.899 36.192 10.933 ;
     RECT  89.112 6.899 90.144 11.221 ;
     RECT  24.696 7.475 26.208 10.501 ;
     RECT  71.352 7.475 72.336 9.731 ;
     RECT  91.812 7.475 93.216 9.925 ;
     RECT  32.412 8.003 33.504 11.221 ;
     RECT  46.584 8.003 47.712 9.061 ;
     RECT  84.216 8.003 85.2 9.731 ;
     RECT  102.888 8.003 104.544 8.965 ;
     RECT  40.632 8.051 41.616 9.397 ;
     RECT  33.672 8.579 34.8 10.307 ;
     RECT  44.376 8.579 45.6 10.741 ;
     RECT  103.32 8.965 104.544 10.931 ;
     RECT  68.424 9.155 69.6 10.213 ;
     RECT  72.912 9.155 74.352 11.029 ;
     RECT  64.968 9.731 66.384 11.317 ;
     RECT  71.256 9.731 72.336 10.741 ;
     RECT  83.712 9.731 85.2 10.693 ;
     RECT  52.488 9.827 53.568 11.365 ;
     RECT  78.312 10.213 79.344 10.501 ;
     RECT  33.528 10.307 34.8 11.317 ;
     RECT  57.864 10.307 58.896 11.317 ;
     RECT  16.212 10.405 17.568 10.501 ;
     RECT  16.584 10.501 17.568 11.365 ;
     RECT  24.696 10.501 26.16 10.933 ;
     RECT  71.304 10.741 72.336 10.789 ;
     RECT  6.552 10.883 7.584 12.997 ;
     RECT  103.32 10.931 104.88 11.941 ;
     RECT  73.128 11.029 74.352 11.317 ;
     RECT  33.528 11.317 34.656 11.749 ;
     RECT  65.208 11.317 66.384 11.893 ;
     RECT  59.412 11.365 60.72 11.845 ;
     RECT  29.832 11.413 31.056 11.941 ;
     RECT  31.08 11.413 32.1 11.749 ;
     RECT  108.12 11.653 109.152 11.701 ;
     RECT  8.112 11.749 9.36 12.229 ;
     RECT  33.672 11.749 34.656 11.845 ;
     RECT  29.832 11.941 30.816 11.989 ;
     RECT  103.752 11.941 104.88 12.037 ;
     RECT  8.112 12.229 9.12 13.573 ;
     RECT  30.84 13.091 31.872 13.187 ;
     RECT  103.896 13.331 104.88 14.389 ;
     RECT  108.984 14.867 110.16 16.453 ;
     RECT  2.712 15.829 3.936 16.595 ;
     RECT  83.88 16.067 85.056 17.461 ;
     RECT  109.032 16.453 110.16 16.501 ;
     RECT  19.32 21.456 19.344 21.491 ;
     RECT  19.464 21.456 19.536 21.491 ;
     RECT  19.656 21.456 19.68 21.491 ;
     RECT  19.8 21.456 19.872 21.491 ;
     RECT  19.992 21.456 20.016 21.491 ;
     RECT  20.136 21.456 20.208 21.491 ;
     RECT  20.328 21.456 20.352 21.491 ;
     RECT  20.472 21.456 20.544 21.491 ;
     RECT  20.664 21.456 20.736 21.491 ;
  END
END hbfd_rly_624_NS_fc
END LIBRARY
